VERSION 5.8 ;
BUSBITCHARS "[]" ;
DIVIDERCHAR "/" ;
UNITS
    DATABASE MICRONS 1000 ;
END UNITS

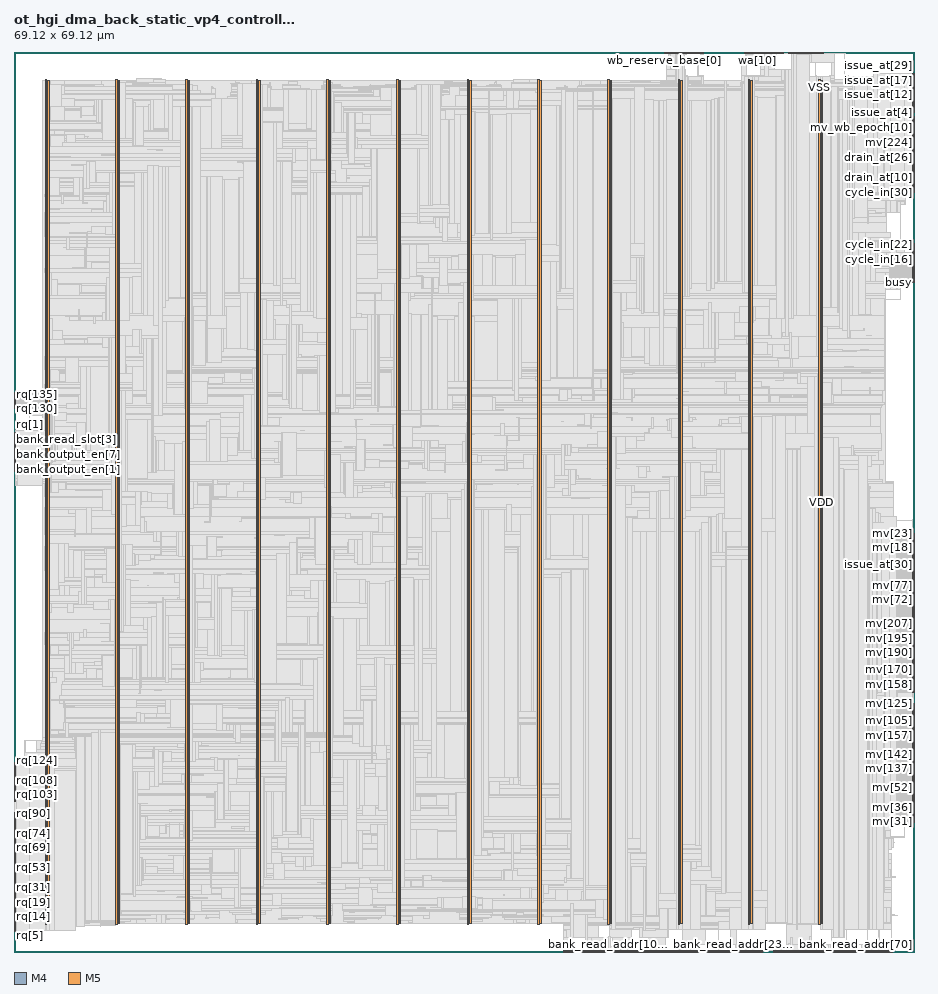
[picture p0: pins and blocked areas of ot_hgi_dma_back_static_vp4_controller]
MACRO ot_hgi_dma_back_static_vp4_controller
  FOREIGN ot_hgi_dma_back_static_vp4_controller 0 0 ;
  CLASS BLOCK ;
  SIZE 69.12 BY 69.12 ;
  PIN bank_output_en[0]
    DIRECTION OUTPUT ;
    USE SIGNAL ;
    PORT
      LAYER M4 ;
        RECT  0 36.912 0.084 36.936 ;
    END
  END bank_output_en[0]
  PIN bank_output_en[1]
    DIRECTION OUTPUT ;
    USE SIGNAL ;
    PORT
      LAYER M4 ;
        RECT  0 37.008 0.084 37.032 ;
    END
  END bank_output_en[1]
  PIN bank_output_en[2]
    DIRECTION OUTPUT ;
    USE SIGNAL ;
    PORT
      LAYER M4 ;
        RECT  0 37.104 0.084 37.128 ;
    END
  END bank_output_en[2]
  PIN bank_output_en[3]
    DIRECTION OUTPUT ;
    USE SIGNAL ;
    PORT
      LAYER M4 ;
        RECT  0 37.2 0.084 37.224 ;
    END
  END bank_output_en[3]
  PIN bank_output_en[4]
    DIRECTION OUTPUT ;
    USE SIGNAL ;
    PORT
      LAYER M4 ;
        RECT  0 37.296 0.084 37.32 ;
    END
  END bank_output_en[4]
  PIN bank_output_en[5]
    DIRECTION OUTPUT ;
    USE SIGNAL ;
    PORT
      LAYER M4 ;
        RECT  0 37.392 0.084 37.416 ;
    END
  END bank_output_en[5]
  PIN bank_output_en[6]
    DIRECTION OUTPUT ;
    USE SIGNAL ;
    PORT
      LAYER M4 ;
        RECT  0 37.488 0.084 37.512 ;
    END
  END bank_output_en[6]
  PIN bank_output_en[7]
    DIRECTION OUTPUT ;
    USE SIGNAL ;
    PORT
      LAYER M4 ;
        RECT  0 37.584 0.084 37.608 ;
    END
  END bank_output_en[7]
  PIN bank_read_addr[0]
    DIRECTION OUTPUT ;
    USE SIGNAL ;
    PORT
      LAYER M5 ;
        RECT  58.32 0 58.344 0.084 ;
    END
  END bank_read_addr[0]
  PIN bank_read_addr[100]
    DIRECTION OUTPUT ;
    USE SIGNAL ;
    PORT
      LAYER M5 ;
        RECT  45.648 0 45.672 0.084 ;
    END
  END bank_read_addr[100]
  PIN bank_read_addr[101]
    DIRECTION OUTPUT ;
    USE SIGNAL ;
    PORT
      LAYER M5 ;
        RECT  45.744 0 45.768 0.084 ;
    END
  END bank_read_addr[101]
  PIN bank_read_addr[102]
    DIRECTION OUTPUT ;
    USE SIGNAL ;
    PORT
      LAYER M5 ;
        RECT  45.84 0 45.864 0.084 ;
    END
  END bank_read_addr[102]
  PIN bank_read_addr[103]
    DIRECTION OUTPUT ;
    USE SIGNAL ;
    PORT
      LAYER M5 ;
        RECT  45.936 0 45.96 0.084 ;
    END
  END bank_read_addr[103]
  PIN bank_read_addr[104]
    DIRECTION OUTPUT ;
    USE SIGNAL ;
    PORT
      LAYER M5 ;
        RECT  46.032 0 46.056 0.084 ;
    END
  END bank_read_addr[104]
  PIN bank_read_addr[105]
    DIRECTION OUTPUT ;
    USE SIGNAL ;
    PORT
      LAYER M5 ;
        RECT  46.128 0 46.152 0.084 ;
    END
  END bank_read_addr[105]
  PIN bank_read_addr[106]
    DIRECTION OUTPUT ;
    USE SIGNAL ;
    PORT
      LAYER M5 ;
        RECT  46.224 0 46.248 0.084 ;
    END
  END bank_read_addr[106]
  PIN bank_read_addr[107]
    DIRECTION OUTPUT ;
    USE SIGNAL ;
    PORT
      LAYER M5 ;
        RECT  46.32 0 46.344 0.084 ;
    END
  END bank_read_addr[107]
  PIN bank_read_addr[108]
    DIRECTION OUTPUT ;
    USE SIGNAL ;
    PORT
      LAYER M5 ;
        RECT  46.416 0 46.44 0.084 ;
    END
  END bank_read_addr[108]
  PIN bank_read_addr[109]
    DIRECTION OUTPUT ;
    USE SIGNAL ;
    PORT
      LAYER M5 ;
        RECT  46.512 0 46.536 0.084 ;
    END
  END bank_read_addr[109]
  PIN bank_read_addr[10]
    DIRECTION OUTPUT ;
    USE SIGNAL ;
    PORT
      LAYER M5 ;
        RECT  59.28 0 59.304 0.084 ;
    END
  END bank_read_addr[10]
  PIN bank_read_addr[110]
    DIRECTION OUTPUT ;
    USE SIGNAL ;
    PORT
      LAYER M5 ;
        RECT  46.608 0 46.632 0.084 ;
    END
  END bank_read_addr[110]
  PIN bank_read_addr[111]
    DIRECTION OUTPUT ;
    USE SIGNAL ;
    PORT
      LAYER M5 ;
        RECT  46.704 0 46.728 0.084 ;
    END
  END bank_read_addr[111]
  PIN bank_read_addr[112]
    DIRECTION OUTPUT ;
    USE SIGNAL ;
    PORT
      LAYER M5 ;
        RECT  46.8 0 46.824 0.084 ;
    END
  END bank_read_addr[112]
  PIN bank_read_addr[113]
    DIRECTION OUTPUT ;
    USE SIGNAL ;
    PORT
      LAYER M5 ;
        RECT  46.896 0 46.92 0.084 ;
    END
  END bank_read_addr[113]
  PIN bank_read_addr[114]
    DIRECTION OUTPUT ;
    USE SIGNAL ;
    PORT
      LAYER M5 ;
        RECT  46.992 0 47.016 0.084 ;
    END
  END bank_read_addr[114]
  PIN bank_read_addr[115]
    DIRECTION OUTPUT ;
    USE SIGNAL ;
    PORT
      LAYER M5 ;
        RECT  47.088 0 47.112 0.084 ;
    END
  END bank_read_addr[115]
  PIN bank_read_addr[116]
    DIRECTION OUTPUT ;
    USE SIGNAL ;
    PORT
      LAYER M5 ;
        RECT  47.184 0 47.208 0.084 ;
    END
  END bank_read_addr[116]
  PIN bank_read_addr[117]
    DIRECTION OUTPUT ;
    USE SIGNAL ;
    PORT
      LAYER M5 ;
        RECT  47.28 0 47.304 0.084 ;
    END
  END bank_read_addr[117]
  PIN bank_read_addr[118]
    DIRECTION OUTPUT ;
    USE SIGNAL ;
    PORT
      LAYER M5 ;
        RECT  47.376 0 47.4 0.084 ;
    END
  END bank_read_addr[118]
  PIN bank_read_addr[119]
    DIRECTION OUTPUT ;
    USE SIGNAL ;
    PORT
      LAYER M5 ;
        RECT  47.472 0 47.496 0.084 ;
    END
  END bank_read_addr[119]
  PIN bank_read_addr[11]
    DIRECTION OUTPUT ;
    USE SIGNAL ;
    PORT
      LAYER M5 ;
        RECT  59.376 0 59.4 0.084 ;
    END
  END bank_read_addr[11]
  PIN bank_read_addr[120]
    DIRECTION OUTPUT ;
    USE SIGNAL ;
    PORT
      LAYER M5 ;
        RECT  47.568 0 47.592 0.084 ;
    END
  END bank_read_addr[120]
  PIN bank_read_addr[121]
    DIRECTION OUTPUT ;
    USE SIGNAL ;
    PORT
      LAYER M5 ;
        RECT  47.664 0 47.688 0.084 ;
    END
  END bank_read_addr[121]
  PIN bank_read_addr[122]
    DIRECTION OUTPUT ;
    USE SIGNAL ;
    PORT
      LAYER M5 ;
        RECT  47.76 0 47.784 0.084 ;
    END
  END bank_read_addr[122]
  PIN bank_read_addr[123]
    DIRECTION OUTPUT ;
    USE SIGNAL ;
    PORT
      LAYER M5 ;
        RECT  47.856 0 47.88 0.084 ;
    END
  END bank_read_addr[123]
  PIN bank_read_addr[124]
    DIRECTION OUTPUT ;
    USE SIGNAL ;
    PORT
      LAYER M5 ;
        RECT  47.952 0 47.976 0.084 ;
    END
  END bank_read_addr[124]
  PIN bank_read_addr[125]
    DIRECTION OUTPUT ;
    USE SIGNAL ;
    PORT
      LAYER M5 ;
        RECT  48.048 0 48.072 0.084 ;
    END
  END bank_read_addr[125]
  PIN bank_read_addr[126]
    DIRECTION OUTPUT ;
    USE SIGNAL ;
    PORT
      LAYER M5 ;
        RECT  48.144 0 48.168 0.084 ;
    END
  END bank_read_addr[126]
  PIN bank_read_addr[127]
    DIRECTION OUTPUT ;
    USE SIGNAL ;
    PORT
      LAYER M5 ;
        RECT  48.24 0 48.264 0.084 ;
    END
  END bank_read_addr[127]
  PIN bank_read_addr[128]
    DIRECTION OUTPUT ;
    USE SIGNAL ;
    PORT
      LAYER M5 ;
        RECT  42.192 0 42.216 0.084 ;
    END
  END bank_read_addr[128]
  PIN bank_read_addr[129]
    DIRECTION OUTPUT ;
    USE SIGNAL ;
    PORT
      LAYER M5 ;
        RECT  42.288 0 42.312 0.084 ;
    END
  END bank_read_addr[129]
  PIN bank_read_addr[12]
    DIRECTION OUTPUT ;
    USE SIGNAL ;
    PORT
      LAYER M5 ;
        RECT  59.472 0 59.496 0.084 ;
    END
  END bank_read_addr[12]
  PIN bank_read_addr[130]
    DIRECTION OUTPUT ;
    USE SIGNAL ;
    PORT
      LAYER M5 ;
        RECT  42.384 0 42.408 0.084 ;
    END
  END bank_read_addr[130]
  PIN bank_read_addr[131]
    DIRECTION OUTPUT ;
    USE SIGNAL ;
    PORT
      LAYER M5 ;
        RECT  42.48 0 42.504 0.084 ;
    END
  END bank_read_addr[131]
  PIN bank_read_addr[132]
    DIRECTION OUTPUT ;
    USE SIGNAL ;
    PORT
      LAYER M5 ;
        RECT  42.576 0 42.6 0.084 ;
    END
  END bank_read_addr[132]
  PIN bank_read_addr[133]
    DIRECTION OUTPUT ;
    USE SIGNAL ;
    PORT
      LAYER M5 ;
        RECT  42.672 0 42.696 0.084 ;
    END
  END bank_read_addr[133]
  PIN bank_read_addr[134]
    DIRECTION OUTPUT ;
    USE SIGNAL ;
    PORT
      LAYER M5 ;
        RECT  42.768 0 42.792 0.084 ;
    END
  END bank_read_addr[134]
  PIN bank_read_addr[135]
    DIRECTION OUTPUT ;
    USE SIGNAL ;
    PORT
      LAYER M5 ;
        RECT  42.864 0 42.888 0.084 ;
    END
  END bank_read_addr[135]
  PIN bank_read_addr[136]
    DIRECTION OUTPUT ;
    USE SIGNAL ;
    PORT
      LAYER M5 ;
        RECT  42.96 0 42.984 0.084 ;
    END
  END bank_read_addr[136]
  PIN bank_read_addr[137]
    DIRECTION OUTPUT ;
    USE SIGNAL ;
    PORT
      LAYER M5 ;
        RECT  43.056 0 43.08 0.084 ;
    END
  END bank_read_addr[137]
  PIN bank_read_addr[138]
    DIRECTION OUTPUT ;
    USE SIGNAL ;
    PORT
      LAYER M5 ;
        RECT  43.152 0 43.176 0.084 ;
    END
  END bank_read_addr[138]
  PIN bank_read_addr[139]
    DIRECTION OUTPUT ;
    USE SIGNAL ;
    PORT
      LAYER M5 ;
        RECT  43.248 0 43.272 0.084 ;
    END
  END bank_read_addr[139]
  PIN bank_read_addr[13]
    DIRECTION OUTPUT ;
    USE SIGNAL ;
    PORT
      LAYER M5 ;
        RECT  59.568 0 59.592 0.084 ;
    END
  END bank_read_addr[13]
  PIN bank_read_addr[140]
    DIRECTION OUTPUT ;
    USE SIGNAL ;
    PORT
      LAYER M5 ;
        RECT  43.344 0 43.368 0.084 ;
    END
  END bank_read_addr[140]
  PIN bank_read_addr[141]
    DIRECTION OUTPUT ;
    USE SIGNAL ;
    PORT
      LAYER M5 ;
        RECT  43.44 0 43.464 0.084 ;
    END
  END bank_read_addr[141]
  PIN bank_read_addr[142]
    DIRECTION OUTPUT ;
    USE SIGNAL ;
    PORT
      LAYER M5 ;
        RECT  43.536 0 43.56 0.084 ;
    END
  END bank_read_addr[142]
  PIN bank_read_addr[143]
    DIRECTION OUTPUT ;
    USE SIGNAL ;
    PORT
      LAYER M5 ;
        RECT  43.632 0 43.656 0.084 ;
    END
  END bank_read_addr[143]
  PIN bank_read_addr[144]
    DIRECTION OUTPUT ;
    USE SIGNAL ;
    PORT
      LAYER M5 ;
        RECT  43.728 0 43.752 0.084 ;
    END
  END bank_read_addr[144]
  PIN bank_read_addr[145]
    DIRECTION OUTPUT ;
    USE SIGNAL ;
    PORT
      LAYER M5 ;
        RECT  43.824 0 43.848 0.084 ;
    END
  END bank_read_addr[145]
  PIN bank_read_addr[146]
    DIRECTION OUTPUT ;
    USE SIGNAL ;
    PORT
      LAYER M5 ;
        RECT  43.92 0 43.944 0.084 ;
    END
  END bank_read_addr[146]
  PIN bank_read_addr[147]
    DIRECTION OUTPUT ;
    USE SIGNAL ;
    PORT
      LAYER M5 ;
        RECT  44.016 0 44.04 0.084 ;
    END
  END bank_read_addr[147]
  PIN bank_read_addr[148]
    DIRECTION OUTPUT ;
    USE SIGNAL ;
    PORT
      LAYER M5 ;
        RECT  44.112 0 44.136 0.084 ;
    END
  END bank_read_addr[148]
  PIN bank_read_addr[149]
    DIRECTION OUTPUT ;
    USE SIGNAL ;
    PORT
      LAYER M5 ;
        RECT  44.208 0 44.232 0.084 ;
    END
  END bank_read_addr[149]
  PIN bank_read_addr[14]
    DIRECTION OUTPUT ;
    USE SIGNAL ;
    PORT
      LAYER M5 ;
        RECT  59.664 0 59.688 0.084 ;
    END
  END bank_read_addr[14]
  PIN bank_read_addr[150]
    DIRECTION OUTPUT ;
    USE SIGNAL ;
    PORT
      LAYER M5 ;
        RECT  44.304 0 44.328 0.084 ;
    END
  END bank_read_addr[150]
  PIN bank_read_addr[151]
    DIRECTION OUTPUT ;
    USE SIGNAL ;
    PORT
      LAYER M5 ;
        RECT  44.4 0 44.424 0.084 ;
    END
  END bank_read_addr[151]
  PIN bank_read_addr[152]
    DIRECTION OUTPUT ;
    USE SIGNAL ;
    PORT
      LAYER M5 ;
        RECT  44.496 0 44.52 0.084 ;
    END
  END bank_read_addr[152]
  PIN bank_read_addr[153]
    DIRECTION OUTPUT ;
    USE SIGNAL ;
    PORT
      LAYER M5 ;
        RECT  44.592 0 44.616 0.084 ;
    END
  END bank_read_addr[153]
  PIN bank_read_addr[154]
    DIRECTION OUTPUT ;
    USE SIGNAL ;
    PORT
      LAYER M5 ;
        RECT  44.688 0 44.712 0.084 ;
    END
  END bank_read_addr[154]
  PIN bank_read_addr[155]
    DIRECTION OUTPUT ;
    USE SIGNAL ;
    PORT
      LAYER M5 ;
        RECT  44.784 0 44.808 0.084 ;
    END
  END bank_read_addr[155]
  PIN bank_read_addr[156]
    DIRECTION OUTPUT ;
    USE SIGNAL ;
    PORT
      LAYER M5 ;
        RECT  44.88 0 44.904 0.084 ;
    END
  END bank_read_addr[156]
  PIN bank_read_addr[157]
    DIRECTION OUTPUT ;
    USE SIGNAL ;
    PORT
      LAYER M5 ;
        RECT  44.976 0 45 0.084 ;
    END
  END bank_read_addr[157]
  PIN bank_read_addr[158]
    DIRECTION OUTPUT ;
    USE SIGNAL ;
    PORT
      LAYER M5 ;
        RECT  45.072 0 45.096 0.084 ;
    END
  END bank_read_addr[158]
  PIN bank_read_addr[159]
    DIRECTION OUTPUT ;
    USE SIGNAL ;
    PORT
      LAYER M5 ;
        RECT  45.168 0 45.192 0.084 ;
    END
  END bank_read_addr[159]
  PIN bank_read_addr[15]
    DIRECTION OUTPUT ;
    USE SIGNAL ;
    PORT
      LAYER M5 ;
        RECT  59.76 0 59.784 0.084 ;
    END
  END bank_read_addr[15]
  PIN bank_read_addr[160]
    DIRECTION OUTPUT ;
    USE SIGNAL ;
    PORT
      LAYER M5 ;
        RECT  51.408 0 51.432 0.084 ;
    END
  END bank_read_addr[160]
  PIN bank_read_addr[161]
    DIRECTION OUTPUT ;
    USE SIGNAL ;
    PORT
      LAYER M5 ;
        RECT  51.504 0 51.528 0.084 ;
    END
  END bank_read_addr[161]
  PIN bank_read_addr[162]
    DIRECTION OUTPUT ;
    USE SIGNAL ;
    PORT
      LAYER M5 ;
        RECT  51.6 0 51.624 0.084 ;
    END
  END bank_read_addr[162]
  PIN bank_read_addr[163]
    DIRECTION OUTPUT ;
    USE SIGNAL ;
    PORT
      LAYER M5 ;
        RECT  51.696 0 51.72 0.084 ;
    END
  END bank_read_addr[163]
  PIN bank_read_addr[164]
    DIRECTION OUTPUT ;
    USE SIGNAL ;
    PORT
      LAYER M5 ;
        RECT  51.792 0 51.816 0.084 ;
    END
  END bank_read_addr[164]
  PIN bank_read_addr[165]
    DIRECTION OUTPUT ;
    USE SIGNAL ;
    PORT
      LAYER M5 ;
        RECT  51.888 0 51.912 0.084 ;
    END
  END bank_read_addr[165]
  PIN bank_read_addr[166]
    DIRECTION OUTPUT ;
    USE SIGNAL ;
    PORT
      LAYER M5 ;
        RECT  51.984 0 52.008 0.084 ;
    END
  END bank_read_addr[166]
  PIN bank_read_addr[167]
    DIRECTION OUTPUT ;
    USE SIGNAL ;
    PORT
      LAYER M5 ;
        RECT  52.08 0 52.104 0.084 ;
    END
  END bank_read_addr[167]
  PIN bank_read_addr[168]
    DIRECTION OUTPUT ;
    USE SIGNAL ;
    PORT
      LAYER M5 ;
        RECT  52.176 0 52.2 0.084 ;
    END
  END bank_read_addr[168]
  PIN bank_read_addr[169]
    DIRECTION OUTPUT ;
    USE SIGNAL ;
    PORT
      LAYER M5 ;
        RECT  52.272 0 52.296 0.084 ;
    END
  END bank_read_addr[169]
  PIN bank_read_addr[16]
    DIRECTION OUTPUT ;
    USE SIGNAL ;
    PORT
      LAYER M5 ;
        RECT  59.856 0 59.88 0.084 ;
    END
  END bank_read_addr[16]
  PIN bank_read_addr[170]
    DIRECTION OUTPUT ;
    USE SIGNAL ;
    PORT
      LAYER M5 ;
        RECT  52.368 0 52.392 0.084 ;
    END
  END bank_read_addr[170]
  PIN bank_read_addr[171]
    DIRECTION OUTPUT ;
    USE SIGNAL ;
    PORT
      LAYER M5 ;
        RECT  52.464 0 52.488 0.084 ;
    END
  END bank_read_addr[171]
  PIN bank_read_addr[172]
    DIRECTION OUTPUT ;
    USE SIGNAL ;
    PORT
      LAYER M5 ;
        RECT  52.56 0 52.584 0.084 ;
    END
  END bank_read_addr[172]
  PIN bank_read_addr[173]
    DIRECTION OUTPUT ;
    USE SIGNAL ;
    PORT
      LAYER M5 ;
        RECT  52.656 0 52.68 0.084 ;
    END
  END bank_read_addr[173]
  PIN bank_read_addr[174]
    DIRECTION OUTPUT ;
    USE SIGNAL ;
    PORT
      LAYER M5 ;
        RECT  52.752 0 52.776 0.084 ;
    END
  END bank_read_addr[174]
  PIN bank_read_addr[175]
    DIRECTION OUTPUT ;
    USE SIGNAL ;
    PORT
      LAYER M5 ;
        RECT  52.848 0 52.872 0.084 ;
    END
  END bank_read_addr[175]
  PIN bank_read_addr[176]
    DIRECTION OUTPUT ;
    USE SIGNAL ;
    PORT
      LAYER M5 ;
        RECT  52.944 0 52.968 0.084 ;
    END
  END bank_read_addr[176]
  PIN bank_read_addr[177]
    DIRECTION OUTPUT ;
    USE SIGNAL ;
    PORT
      LAYER M5 ;
        RECT  53.04 0 53.064 0.084 ;
    END
  END bank_read_addr[177]
  PIN bank_read_addr[178]
    DIRECTION OUTPUT ;
    USE SIGNAL ;
    PORT
      LAYER M5 ;
        RECT  53.136 0 53.16 0.084 ;
    END
  END bank_read_addr[178]
  PIN bank_read_addr[179]
    DIRECTION OUTPUT ;
    USE SIGNAL ;
    PORT
      LAYER M5 ;
        RECT  53.232 0 53.256 0.084 ;
    END
  END bank_read_addr[179]
  PIN bank_read_addr[17]
    DIRECTION OUTPUT ;
    USE SIGNAL ;
    PORT
      LAYER M5 ;
        RECT  59.952 0 59.976 0.084 ;
    END
  END bank_read_addr[17]
  PIN bank_read_addr[180]
    DIRECTION OUTPUT ;
    USE SIGNAL ;
    PORT
      LAYER M5 ;
        RECT  53.328 0 53.352 0.084 ;
    END
  END bank_read_addr[180]
  PIN bank_read_addr[181]
    DIRECTION OUTPUT ;
    USE SIGNAL ;
    PORT
      LAYER M5 ;
        RECT  53.424 0 53.448 0.084 ;
    END
  END bank_read_addr[181]
  PIN bank_read_addr[182]
    DIRECTION OUTPUT ;
    USE SIGNAL ;
    PORT
      LAYER M5 ;
        RECT  53.52 0 53.544 0.084 ;
    END
  END bank_read_addr[182]
  PIN bank_read_addr[183]
    DIRECTION OUTPUT ;
    USE SIGNAL ;
    PORT
      LAYER M5 ;
        RECT  53.616 0 53.64 0.084 ;
    END
  END bank_read_addr[183]
  PIN bank_read_addr[184]
    DIRECTION OUTPUT ;
    USE SIGNAL ;
    PORT
      LAYER M5 ;
        RECT  53.712 0 53.736 0.084 ;
    END
  END bank_read_addr[184]
  PIN bank_read_addr[185]
    DIRECTION OUTPUT ;
    USE SIGNAL ;
    PORT
      LAYER M5 ;
        RECT  53.808 0 53.832 0.084 ;
    END
  END bank_read_addr[185]
  PIN bank_read_addr[186]
    DIRECTION OUTPUT ;
    USE SIGNAL ;
    PORT
      LAYER M5 ;
        RECT  53.904 0 53.928 0.084 ;
    END
  END bank_read_addr[186]
  PIN bank_read_addr[187]
    DIRECTION OUTPUT ;
    USE SIGNAL ;
    PORT
      LAYER M5 ;
        RECT  54 0 54.024 0.084 ;
    END
  END bank_read_addr[187]
  PIN bank_read_addr[188]
    DIRECTION OUTPUT ;
    USE SIGNAL ;
    PORT
      LAYER M5 ;
        RECT  54.096 0 54.12 0.084 ;
    END
  END bank_read_addr[188]
  PIN bank_read_addr[189]
    DIRECTION OUTPUT ;
    USE SIGNAL ;
    PORT
      LAYER M5 ;
        RECT  54.192 0 54.216 0.084 ;
    END
  END bank_read_addr[189]
  PIN bank_read_addr[18]
    DIRECTION OUTPUT ;
    USE SIGNAL ;
    PORT
      LAYER M5 ;
        RECT  60.048 0 60.072 0.084 ;
    END
  END bank_read_addr[18]
  PIN bank_read_addr[190]
    DIRECTION OUTPUT ;
    USE SIGNAL ;
    PORT
      LAYER M5 ;
        RECT  54.288 0 54.312 0.084 ;
    END
  END bank_read_addr[190]
  PIN bank_read_addr[191]
    DIRECTION OUTPUT ;
    USE SIGNAL ;
    PORT
      LAYER M5 ;
        RECT  54.384 0 54.408 0.084 ;
    END
  END bank_read_addr[191]
  PIN bank_read_addr[192]
    DIRECTION OUTPUT ;
    USE SIGNAL ;
    PORT
      LAYER M5 ;
        RECT  48.336 0 48.36 0.084 ;
    END
  END bank_read_addr[192]
  PIN bank_read_addr[193]
    DIRECTION OUTPUT ;
    USE SIGNAL ;
    PORT
      LAYER M5 ;
        RECT  48.432 0 48.456 0.084 ;
    END
  END bank_read_addr[193]
  PIN bank_read_addr[194]
    DIRECTION OUTPUT ;
    USE SIGNAL ;
    PORT
      LAYER M5 ;
        RECT  48.528 0 48.552 0.084 ;
    END
  END bank_read_addr[194]
  PIN bank_read_addr[195]
    DIRECTION OUTPUT ;
    USE SIGNAL ;
    PORT
      LAYER M5 ;
        RECT  48.624 0 48.648 0.084 ;
    END
  END bank_read_addr[195]
  PIN bank_read_addr[196]
    DIRECTION OUTPUT ;
    USE SIGNAL ;
    PORT
      LAYER M5 ;
        RECT  48.72 0 48.744 0.084 ;
    END
  END bank_read_addr[196]
  PIN bank_read_addr[197]
    DIRECTION OUTPUT ;
    USE SIGNAL ;
    PORT
      LAYER M5 ;
        RECT  48.816 0 48.84 0.084 ;
    END
  END bank_read_addr[197]
  PIN bank_read_addr[198]
    DIRECTION OUTPUT ;
    USE SIGNAL ;
    PORT
      LAYER M5 ;
        RECT  48.912 0 48.936 0.084 ;
    END
  END bank_read_addr[198]
  PIN bank_read_addr[199]
    DIRECTION OUTPUT ;
    USE SIGNAL ;
    PORT
      LAYER M5 ;
        RECT  49.008 0 49.032 0.084 ;
    END
  END bank_read_addr[199]
  PIN bank_read_addr[19]
    DIRECTION OUTPUT ;
    USE SIGNAL ;
    PORT
      LAYER M5 ;
        RECT  60.144 0 60.168 0.084 ;
    END
  END bank_read_addr[19]
  PIN bank_read_addr[1]
    DIRECTION OUTPUT ;
    USE SIGNAL ;
    PORT
      LAYER M5 ;
        RECT  58.416 0 58.44 0.084 ;
    END
  END bank_read_addr[1]
  PIN bank_read_addr[200]
    DIRECTION OUTPUT ;
    USE SIGNAL ;
    PORT
      LAYER M5 ;
        RECT  49.104 0 49.128 0.084 ;
    END
  END bank_read_addr[200]
  PIN bank_read_addr[201]
    DIRECTION OUTPUT ;
    USE SIGNAL ;
    PORT
      LAYER M5 ;
        RECT  49.2 0 49.224 0.084 ;
    END
  END bank_read_addr[201]
  PIN bank_read_addr[202]
    DIRECTION OUTPUT ;
    USE SIGNAL ;
    PORT
      LAYER M5 ;
        RECT  49.296 0 49.32 0.084 ;
    END
  END bank_read_addr[202]
  PIN bank_read_addr[203]
    DIRECTION OUTPUT ;
    USE SIGNAL ;
    PORT
      LAYER M5 ;
        RECT  49.392 0 49.416 0.084 ;
    END
  END bank_read_addr[203]
  PIN bank_read_addr[204]
    DIRECTION OUTPUT ;
    USE SIGNAL ;
    PORT
      LAYER M5 ;
        RECT  49.488 0 49.512 0.084 ;
    END
  END bank_read_addr[204]
  PIN bank_read_addr[205]
    DIRECTION OUTPUT ;
    USE SIGNAL ;
    PORT
      LAYER M5 ;
        RECT  49.584 0 49.608 0.084 ;
    END
  END bank_read_addr[205]
  PIN bank_read_addr[206]
    DIRECTION OUTPUT ;
    USE SIGNAL ;
    PORT
      LAYER M5 ;
        RECT  49.68 0 49.704 0.084 ;
    END
  END bank_read_addr[206]
  PIN bank_read_addr[207]
    DIRECTION OUTPUT ;
    USE SIGNAL ;
    PORT
      LAYER M5 ;
        RECT  49.776 0 49.8 0.084 ;
    END
  END bank_read_addr[207]
  PIN bank_read_addr[208]
    DIRECTION OUTPUT ;
    USE SIGNAL ;
    PORT
      LAYER M5 ;
        RECT  49.872 0 49.896 0.084 ;
    END
  END bank_read_addr[208]
  PIN bank_read_addr[209]
    DIRECTION OUTPUT ;
    USE SIGNAL ;
    PORT
      LAYER M5 ;
        RECT  49.968 0 49.992 0.084 ;
    END
  END bank_read_addr[209]
  PIN bank_read_addr[20]
    DIRECTION OUTPUT ;
    USE SIGNAL ;
    PORT
      LAYER M5 ;
        RECT  60.24 0 60.264 0.084 ;
    END
  END bank_read_addr[20]
  PIN bank_read_addr[210]
    DIRECTION OUTPUT ;
    USE SIGNAL ;
    PORT
      LAYER M5 ;
        RECT  50.064 0 50.088 0.084 ;
    END
  END bank_read_addr[210]
  PIN bank_read_addr[211]
    DIRECTION OUTPUT ;
    USE SIGNAL ;
    PORT
      LAYER M5 ;
        RECT  50.16 0 50.184 0.084 ;
    END
  END bank_read_addr[211]
  PIN bank_read_addr[212]
    DIRECTION OUTPUT ;
    USE SIGNAL ;
    PORT
      LAYER M5 ;
        RECT  50.256 0 50.28 0.084 ;
    END
  END bank_read_addr[212]
  PIN bank_read_addr[213]
    DIRECTION OUTPUT ;
    USE SIGNAL ;
    PORT
      LAYER M5 ;
        RECT  50.352 0 50.376 0.084 ;
    END
  END bank_read_addr[213]
  PIN bank_read_addr[214]
    DIRECTION OUTPUT ;
    USE SIGNAL ;
    PORT
      LAYER M5 ;
        RECT  50.448 0 50.472 0.084 ;
    END
  END bank_read_addr[214]
  PIN bank_read_addr[215]
    DIRECTION OUTPUT ;
    USE SIGNAL ;
    PORT
      LAYER M5 ;
        RECT  50.544 0 50.568 0.084 ;
    END
  END bank_read_addr[215]
  PIN bank_read_addr[216]
    DIRECTION OUTPUT ;
    USE SIGNAL ;
    PORT
      LAYER M5 ;
        RECT  50.64 0 50.664 0.084 ;
    END
  END bank_read_addr[216]
  PIN bank_read_addr[217]
    DIRECTION OUTPUT ;
    USE SIGNAL ;
    PORT
      LAYER M5 ;
        RECT  50.736 0 50.76 0.084 ;
    END
  END bank_read_addr[217]
  PIN bank_read_addr[218]
    DIRECTION OUTPUT ;
    USE SIGNAL ;
    PORT
      LAYER M5 ;
        RECT  50.832 0 50.856 0.084 ;
    END
  END bank_read_addr[218]
  PIN bank_read_addr[219]
    DIRECTION OUTPUT ;
    USE SIGNAL ;
    PORT
      LAYER M5 ;
        RECT  50.928 0 50.952 0.084 ;
    END
  END bank_read_addr[219]
  PIN bank_read_addr[21]
    DIRECTION OUTPUT ;
    USE SIGNAL ;
    PORT
      LAYER M5 ;
        RECT  60.336 0 60.36 0.084 ;
    END
  END bank_read_addr[21]
  PIN bank_read_addr[220]
    DIRECTION OUTPUT ;
    USE SIGNAL ;
    PORT
      LAYER M5 ;
        RECT  51.024 0 51.048 0.084 ;
    END
  END bank_read_addr[220]
  PIN bank_read_addr[221]
    DIRECTION OUTPUT ;
    USE SIGNAL ;
    PORT
      LAYER M5 ;
        RECT  51.12 0 51.144 0.084 ;
    END
  END bank_read_addr[221]
  PIN bank_read_addr[222]
    DIRECTION OUTPUT ;
    USE SIGNAL ;
    PORT
      LAYER M5 ;
        RECT  51.216 0 51.24 0.084 ;
    END
  END bank_read_addr[222]
  PIN bank_read_addr[223]
    DIRECTION OUTPUT ;
    USE SIGNAL ;
    PORT
      LAYER M5 ;
        RECT  51.312 0 51.336 0.084 ;
    END
  END bank_read_addr[223]
  PIN bank_read_addr[224]
    DIRECTION OUTPUT ;
    USE SIGNAL ;
    PORT
      LAYER M5 ;
        RECT  54.48 0 54.504 0.084 ;
    END
  END bank_read_addr[224]
  PIN bank_read_addr[225]
    DIRECTION OUTPUT ;
    USE SIGNAL ;
    PORT
      LAYER M5 ;
        RECT  54.576 0 54.6 0.084 ;
    END
  END bank_read_addr[225]
  PIN bank_read_addr[226]
    DIRECTION OUTPUT ;
    USE SIGNAL ;
    PORT
      LAYER M5 ;
        RECT  54.672 0 54.696 0.084 ;
    END
  END bank_read_addr[226]
  PIN bank_read_addr[227]
    DIRECTION OUTPUT ;
    USE SIGNAL ;
    PORT
      LAYER M5 ;
        RECT  54.768 0 54.792 0.084 ;
    END
  END bank_read_addr[227]
  PIN bank_read_addr[228]
    DIRECTION OUTPUT ;
    USE SIGNAL ;
    PORT
      LAYER M5 ;
        RECT  54.864 0 54.888 0.084 ;
    END
  END bank_read_addr[228]
  PIN bank_read_addr[229]
    DIRECTION OUTPUT ;
    USE SIGNAL ;
    PORT
      LAYER M5 ;
        RECT  54.96 0 54.984 0.084 ;
    END
  END bank_read_addr[229]
  PIN bank_read_addr[22]
    DIRECTION OUTPUT ;
    USE SIGNAL ;
    PORT
      LAYER M5 ;
        RECT  60.432 0 60.456 0.084 ;
    END
  END bank_read_addr[22]
  PIN bank_read_addr[230]
    DIRECTION OUTPUT ;
    USE SIGNAL ;
    PORT
      LAYER M5 ;
        RECT  55.056 0 55.08 0.084 ;
    END
  END bank_read_addr[230]
  PIN bank_read_addr[231]
    DIRECTION OUTPUT ;
    USE SIGNAL ;
    PORT
      LAYER M5 ;
        RECT  55.152 0 55.176 0.084 ;
    END
  END bank_read_addr[231]
  PIN bank_read_addr[232]
    DIRECTION OUTPUT ;
    USE SIGNAL ;
    PORT
      LAYER M5 ;
        RECT  55.248 0 55.272 0.084 ;
    END
  END bank_read_addr[232]
  PIN bank_read_addr[233]
    DIRECTION OUTPUT ;
    USE SIGNAL ;
    PORT
      LAYER M5 ;
        RECT  55.344 0 55.368 0.084 ;
    END
  END bank_read_addr[233]
  PIN bank_read_addr[234]
    DIRECTION OUTPUT ;
    USE SIGNAL ;
    PORT
      LAYER M5 ;
        RECT  55.44 0 55.464 0.084 ;
    END
  END bank_read_addr[234]
  PIN bank_read_addr[235]
    DIRECTION OUTPUT ;
    USE SIGNAL ;
    PORT
      LAYER M5 ;
        RECT  55.536 0 55.56 0.084 ;
    END
  END bank_read_addr[235]
  PIN bank_read_addr[236]
    DIRECTION OUTPUT ;
    USE SIGNAL ;
    PORT
      LAYER M5 ;
        RECT  55.632 0 55.656 0.084 ;
    END
  END bank_read_addr[236]
  PIN bank_read_addr[237]
    DIRECTION OUTPUT ;
    USE SIGNAL ;
    PORT
      LAYER M5 ;
        RECT  55.728 0 55.752 0.084 ;
    END
  END bank_read_addr[237]
  PIN bank_read_addr[238]
    DIRECTION OUTPUT ;
    USE SIGNAL ;
    PORT
      LAYER M5 ;
        RECT  55.824 0 55.848 0.084 ;
    END
  END bank_read_addr[238]
  PIN bank_read_addr[239]
    DIRECTION OUTPUT ;
    USE SIGNAL ;
    PORT
      LAYER M5 ;
        RECT  55.92 0 55.944 0.084 ;
    END
  END bank_read_addr[239]
  PIN bank_read_addr[23]
    DIRECTION OUTPUT ;
    USE SIGNAL ;
    PORT
      LAYER M5 ;
        RECT  60.528 0 60.552 0.084 ;
    END
  END bank_read_addr[23]
  PIN bank_read_addr[240]
    DIRECTION OUTPUT ;
    USE SIGNAL ;
    PORT
      LAYER M5 ;
        RECT  56.016 0 56.04 0.084 ;
    END
  END bank_read_addr[240]
  PIN bank_read_addr[241]
    DIRECTION OUTPUT ;
    USE SIGNAL ;
    PORT
      LAYER M5 ;
        RECT  56.112 0 56.136 0.084 ;
    END
  END bank_read_addr[241]
  PIN bank_read_addr[242]
    DIRECTION OUTPUT ;
    USE SIGNAL ;
    PORT
      LAYER M5 ;
        RECT  56.208 0 56.232 0.084 ;
    END
  END bank_read_addr[242]
  PIN bank_read_addr[243]
    DIRECTION OUTPUT ;
    USE SIGNAL ;
    PORT
      LAYER M5 ;
        RECT  56.304 0 56.328 0.084 ;
    END
  END bank_read_addr[243]
  PIN bank_read_addr[244]
    DIRECTION OUTPUT ;
    USE SIGNAL ;
    PORT
      LAYER M5 ;
        RECT  56.4 0 56.424 0.084 ;
    END
  END bank_read_addr[244]
  PIN bank_read_addr[245]
    DIRECTION OUTPUT ;
    USE SIGNAL ;
    PORT
      LAYER M5 ;
        RECT  56.496 0 56.52 0.084 ;
    END
  END bank_read_addr[245]
  PIN bank_read_addr[246]
    DIRECTION OUTPUT ;
    USE SIGNAL ;
    PORT
      LAYER M5 ;
        RECT  56.592 0 56.616 0.084 ;
    END
  END bank_read_addr[246]
  PIN bank_read_addr[247]
    DIRECTION OUTPUT ;
    USE SIGNAL ;
    PORT
      LAYER M5 ;
        RECT  56.688 0 56.712 0.084 ;
    END
  END bank_read_addr[247]
  PIN bank_read_addr[248]
    DIRECTION OUTPUT ;
    USE SIGNAL ;
    PORT
      LAYER M5 ;
        RECT  56.784 0 56.808 0.084 ;
    END
  END bank_read_addr[248]
  PIN bank_read_addr[249]
    DIRECTION OUTPUT ;
    USE SIGNAL ;
    PORT
      LAYER M5 ;
        RECT  56.88 0 56.904 0.084 ;
    END
  END bank_read_addr[249]
  PIN bank_read_addr[24]
    DIRECTION OUTPUT ;
    USE SIGNAL ;
    PORT
      LAYER M5 ;
        RECT  60.624 0 60.648 0.084 ;
    END
  END bank_read_addr[24]
  PIN bank_read_addr[250]
    DIRECTION OUTPUT ;
    USE SIGNAL ;
    PORT
      LAYER M5 ;
        RECT  56.976 0 57 0.084 ;
    END
  END bank_read_addr[250]
  PIN bank_read_addr[251]
    DIRECTION OUTPUT ;
    USE SIGNAL ;
    PORT
      LAYER M5 ;
        RECT  57.072 0 57.096 0.084 ;
    END
  END bank_read_addr[251]
  PIN bank_read_addr[252]
    DIRECTION OUTPUT ;
    USE SIGNAL ;
    PORT
      LAYER M5 ;
        RECT  57.168 0 57.192 0.084 ;
    END
  END bank_read_addr[252]
  PIN bank_read_addr[253]
    DIRECTION OUTPUT ;
    USE SIGNAL ;
    PORT
      LAYER M5 ;
        RECT  57.264 0 57.288 0.084 ;
    END
  END bank_read_addr[253]
  PIN bank_read_addr[254]
    DIRECTION OUTPUT ;
    USE SIGNAL ;
    PORT
      LAYER M5 ;
        RECT  57.36 0 57.384 0.084 ;
    END
  END bank_read_addr[254]
  PIN bank_read_addr[255]
    DIRECTION OUTPUT ;
    USE SIGNAL ;
    PORT
      LAYER M5 ;
        RECT  57.456 0 57.48 0.084 ;
    END
  END bank_read_addr[255]
  PIN bank_read_addr[25]
    DIRECTION OUTPUT ;
    USE SIGNAL ;
    PORT
      LAYER M5 ;
        RECT  60.72 0 60.744 0.084 ;
    END
  END bank_read_addr[25]
  PIN bank_read_addr[26]
    DIRECTION OUTPUT ;
    USE SIGNAL ;
    PORT
      LAYER M5 ;
        RECT  60.816 0 60.84 0.084 ;
    END
  END bank_read_addr[26]
  PIN bank_read_addr[27]
    DIRECTION OUTPUT ;
    USE SIGNAL ;
    PORT
      LAYER M5 ;
        RECT  60.912 0 60.936 0.084 ;
    END
  END bank_read_addr[27]
  PIN bank_read_addr[28]
    DIRECTION OUTPUT ;
    USE SIGNAL ;
    PORT
      LAYER M5 ;
        RECT  61.008 0 61.032 0.084 ;
    END
  END bank_read_addr[28]
  PIN bank_read_addr[29]
    DIRECTION OUTPUT ;
    USE SIGNAL ;
    PORT
      LAYER M5 ;
        RECT  61.104 0 61.128 0.084 ;
    END
  END bank_read_addr[29]
  PIN bank_read_addr[2]
    DIRECTION OUTPUT ;
    USE SIGNAL ;
    PORT
      LAYER M5 ;
        RECT  58.512 0 58.536 0.084 ;
    END
  END bank_read_addr[2]
  PIN bank_read_addr[30]
    DIRECTION OUTPUT ;
    USE SIGNAL ;
    PORT
      LAYER M5 ;
        RECT  61.2 0 61.224 0.084 ;
    END
  END bank_read_addr[30]
  PIN bank_read_addr[31]
    DIRECTION OUTPUT ;
    USE SIGNAL ;
    PORT
      LAYER M5 ;
        RECT  61.296 0 61.32 0.084 ;
    END
  END bank_read_addr[31]
  PIN bank_read_addr[32]
    DIRECTION OUTPUT ;
    USE SIGNAL ;
    PORT
      LAYER M5 ;
        RECT  61.392 0 61.416 0.084 ;
    END
  END bank_read_addr[32]
  PIN bank_read_addr[33]
    DIRECTION OUTPUT ;
    USE SIGNAL ;
    PORT
      LAYER M5 ;
        RECT  61.488 0 61.512 0.084 ;
    END
  END bank_read_addr[33]
  PIN bank_read_addr[34]
    DIRECTION OUTPUT ;
    USE SIGNAL ;
    PORT
      LAYER M5 ;
        RECT  61.584 0 61.608 0.084 ;
    END
  END bank_read_addr[34]
  PIN bank_read_addr[35]
    DIRECTION OUTPUT ;
    USE SIGNAL ;
    PORT
      LAYER M5 ;
        RECT  61.68 0 61.704 0.084 ;
    END
  END bank_read_addr[35]
  PIN bank_read_addr[36]
    DIRECTION OUTPUT ;
    USE SIGNAL ;
    PORT
      LAYER M5 ;
        RECT  61.776 0 61.8 0.084 ;
    END
  END bank_read_addr[36]
  PIN bank_read_addr[37]
    DIRECTION OUTPUT ;
    USE SIGNAL ;
    PORT
      LAYER M5 ;
        RECT  61.872 0 61.896 0.084 ;
    END
  END bank_read_addr[37]
  PIN bank_read_addr[38]
    DIRECTION OUTPUT ;
    USE SIGNAL ;
    PORT
      LAYER M5 ;
        RECT  61.968 0 61.992 0.084 ;
    END
  END bank_read_addr[38]
  PIN bank_read_addr[39]
    DIRECTION OUTPUT ;
    USE SIGNAL ;
    PORT
      LAYER M5 ;
        RECT  62.064 0 62.088 0.084 ;
    END
  END bank_read_addr[39]
  PIN bank_read_addr[3]
    DIRECTION OUTPUT ;
    USE SIGNAL ;
    PORT
      LAYER M5 ;
        RECT  58.608 0 58.632 0.084 ;
    END
  END bank_read_addr[3]
  PIN bank_read_addr[40]
    DIRECTION OUTPUT ;
    USE SIGNAL ;
    PORT
      LAYER M5 ;
        RECT  62.16 0 62.184 0.084 ;
    END
  END bank_read_addr[40]
  PIN bank_read_addr[41]
    DIRECTION OUTPUT ;
    USE SIGNAL ;
    PORT
      LAYER M5 ;
        RECT  62.256 0 62.28 0.084 ;
    END
  END bank_read_addr[41]
  PIN bank_read_addr[42]
    DIRECTION OUTPUT ;
    USE SIGNAL ;
    PORT
      LAYER M5 ;
        RECT  62.352 0 62.376 0.084 ;
    END
  END bank_read_addr[42]
  PIN bank_read_addr[43]
    DIRECTION OUTPUT ;
    USE SIGNAL ;
    PORT
      LAYER M5 ;
        RECT  62.448 0 62.472 0.084 ;
    END
  END bank_read_addr[43]
  PIN bank_read_addr[44]
    DIRECTION OUTPUT ;
    USE SIGNAL ;
    PORT
      LAYER M5 ;
        RECT  62.544 0 62.568 0.084 ;
    END
  END bank_read_addr[44]
  PIN bank_read_addr[45]
    DIRECTION OUTPUT ;
    USE SIGNAL ;
    PORT
      LAYER M5 ;
        RECT  62.64 0 62.664 0.084 ;
    END
  END bank_read_addr[45]
  PIN bank_read_addr[46]
    DIRECTION OUTPUT ;
    USE SIGNAL ;
    PORT
      LAYER M5 ;
        RECT  62.736 0 62.76 0.084 ;
    END
  END bank_read_addr[46]
  PIN bank_read_addr[47]
    DIRECTION OUTPUT ;
    USE SIGNAL ;
    PORT
      LAYER M5 ;
        RECT  62.832 0 62.856 0.084 ;
    END
  END bank_read_addr[47]
  PIN bank_read_addr[48]
    DIRECTION OUTPUT ;
    USE SIGNAL ;
    PORT
      LAYER M5 ;
        RECT  62.928 0 62.952 0.084 ;
    END
  END bank_read_addr[48]
  PIN bank_read_addr[49]
    DIRECTION OUTPUT ;
    USE SIGNAL ;
    PORT
      LAYER M5 ;
        RECT  63.024 0 63.048 0.084 ;
    END
  END bank_read_addr[49]
  PIN bank_read_addr[4]
    DIRECTION OUTPUT ;
    USE SIGNAL ;
    PORT
      LAYER M5 ;
        RECT  58.704 0 58.728 0.084 ;
    END
  END bank_read_addr[4]
  PIN bank_read_addr[50]
    DIRECTION OUTPUT ;
    USE SIGNAL ;
    PORT
      LAYER M5 ;
        RECT  63.12 0 63.144 0.084 ;
    END
  END bank_read_addr[50]
  PIN bank_read_addr[51]
    DIRECTION OUTPUT ;
    USE SIGNAL ;
    PORT
      LAYER M5 ;
        RECT  63.216 0 63.24 0.084 ;
    END
  END bank_read_addr[51]
  PIN bank_read_addr[52]
    DIRECTION OUTPUT ;
    USE SIGNAL ;
    PORT
      LAYER M5 ;
        RECT  63.312 0 63.336 0.084 ;
    END
  END bank_read_addr[52]
  PIN bank_read_addr[53]
    DIRECTION OUTPUT ;
    USE SIGNAL ;
    PORT
      LAYER M5 ;
        RECT  63.408 0 63.432 0.084 ;
    END
  END bank_read_addr[53]
  PIN bank_read_addr[54]
    DIRECTION OUTPUT ;
    USE SIGNAL ;
    PORT
      LAYER M5 ;
        RECT  63.504 0 63.528 0.084 ;
    END
  END bank_read_addr[54]
  PIN bank_read_addr[55]
    DIRECTION OUTPUT ;
    USE SIGNAL ;
    PORT
      LAYER M5 ;
        RECT  63.6 0 63.624 0.084 ;
    END
  END bank_read_addr[55]
  PIN bank_read_addr[56]
    DIRECTION OUTPUT ;
    USE SIGNAL ;
    PORT
      LAYER M5 ;
        RECT  63.696 0 63.72 0.084 ;
    END
  END bank_read_addr[56]
  PIN bank_read_addr[57]
    DIRECTION OUTPUT ;
    USE SIGNAL ;
    PORT
      LAYER M5 ;
        RECT  63.792 0 63.816 0.084 ;
    END
  END bank_read_addr[57]
  PIN bank_read_addr[58]
    DIRECTION OUTPUT ;
    USE SIGNAL ;
    PORT
      LAYER M5 ;
        RECT  63.888 0 63.912 0.084 ;
    END
  END bank_read_addr[58]
  PIN bank_read_addr[59]
    DIRECTION OUTPUT ;
    USE SIGNAL ;
    PORT
      LAYER M5 ;
        RECT  63.984 0 64.008 0.084 ;
    END
  END bank_read_addr[59]
  PIN bank_read_addr[5]
    DIRECTION OUTPUT ;
    USE SIGNAL ;
    PORT
      LAYER M5 ;
        RECT  58.8 0 58.824 0.084 ;
    END
  END bank_read_addr[5]
  PIN bank_read_addr[60]
    DIRECTION OUTPUT ;
    USE SIGNAL ;
    PORT
      LAYER M5 ;
        RECT  64.08 0 64.104 0.084 ;
    END
  END bank_read_addr[60]
  PIN bank_read_addr[61]
    DIRECTION OUTPUT ;
    USE SIGNAL ;
    PORT
      LAYER M5 ;
        RECT  64.176 0 64.2 0.084 ;
    END
  END bank_read_addr[61]
  PIN bank_read_addr[62]
    DIRECTION OUTPUT ;
    USE SIGNAL ;
    PORT
      LAYER M5 ;
        RECT  64.272 0 64.296 0.084 ;
    END
  END bank_read_addr[62]
  PIN bank_read_addr[63]
    DIRECTION OUTPUT ;
    USE SIGNAL ;
    PORT
      LAYER M5 ;
        RECT  64.368 0 64.392 0.084 ;
    END
  END bank_read_addr[63]
  PIN bank_read_addr[64]
    DIRECTION OUTPUT ;
    USE SIGNAL ;
    PORT
      LAYER M5 ;
        RECT  64.464 0 64.488 0.084 ;
    END
  END bank_read_addr[64]
  PIN bank_read_addr[65]
    DIRECTION OUTPUT ;
    USE SIGNAL ;
    PORT
      LAYER M5 ;
        RECT  64.56 0 64.584 0.084 ;
    END
  END bank_read_addr[65]
  PIN bank_read_addr[66]
    DIRECTION OUTPUT ;
    USE SIGNAL ;
    PORT
      LAYER M5 ;
        RECT  64.656 0 64.68 0.084 ;
    END
  END bank_read_addr[66]
  PIN bank_read_addr[67]
    DIRECTION OUTPUT ;
    USE SIGNAL ;
    PORT
      LAYER M5 ;
        RECT  64.752 0 64.776 0.084 ;
    END
  END bank_read_addr[67]
  PIN bank_read_addr[68]
    DIRECTION OUTPUT ;
    USE SIGNAL ;
    PORT
      LAYER M5 ;
        RECT  64.848 0 64.872 0.084 ;
    END
  END bank_read_addr[68]
  PIN bank_read_addr[69]
    DIRECTION OUTPUT ;
    USE SIGNAL ;
    PORT
      LAYER M5 ;
        RECT  64.944 0 64.968 0.084 ;
    END
  END bank_read_addr[69]
  PIN bank_read_addr[6]
    DIRECTION OUTPUT ;
    USE SIGNAL ;
    PORT
      LAYER M5 ;
        RECT  58.896 0 58.92 0.084 ;
    END
  END bank_read_addr[6]
  PIN bank_read_addr[70]
    DIRECTION OUTPUT ;
    USE SIGNAL ;
    PORT
      LAYER M5 ;
        RECT  65.04 0 65.064 0.084 ;
    END
  END bank_read_addr[70]
  PIN bank_read_addr[71]
    DIRECTION OUTPUT ;
    USE SIGNAL ;
    PORT
      LAYER M5 ;
        RECT  65.136 0 65.16 0.084 ;
    END
  END bank_read_addr[71]
  PIN bank_read_addr[72]
    DIRECTION OUTPUT ;
    USE SIGNAL ;
    PORT
      LAYER M5 ;
        RECT  65.232 0 65.256 0.084 ;
    END
  END bank_read_addr[72]
  PIN bank_read_addr[73]
    DIRECTION OUTPUT ;
    USE SIGNAL ;
    PORT
      LAYER M5 ;
        RECT  65.328 0 65.352 0.084 ;
    END
  END bank_read_addr[73]
  PIN bank_read_addr[74]
    DIRECTION OUTPUT ;
    USE SIGNAL ;
    PORT
      LAYER M5 ;
        RECT  65.424 0 65.448 0.084 ;
    END
  END bank_read_addr[74]
  PIN bank_read_addr[75]
    DIRECTION OUTPUT ;
    USE SIGNAL ;
    PORT
      LAYER M5 ;
        RECT  65.52 0 65.544 0.084 ;
    END
  END bank_read_addr[75]
  PIN bank_read_addr[76]
    DIRECTION OUTPUT ;
    USE SIGNAL ;
    PORT
      LAYER M5 ;
        RECT  65.616 0 65.64 0.084 ;
    END
  END bank_read_addr[76]
  PIN bank_read_addr[77]
    DIRECTION OUTPUT ;
    USE SIGNAL ;
    PORT
      LAYER M5 ;
        RECT  65.712 0 65.736 0.084 ;
    END
  END bank_read_addr[77]
  PIN bank_read_addr[78]
    DIRECTION OUTPUT ;
    USE SIGNAL ;
    PORT
      LAYER M5 ;
        RECT  65.808 0 65.832 0.084 ;
    END
  END bank_read_addr[78]
  PIN bank_read_addr[79]
    DIRECTION OUTPUT ;
    USE SIGNAL ;
    PORT
      LAYER M5 ;
        RECT  65.904 0 65.928 0.084 ;
    END
  END bank_read_addr[79]
  PIN bank_read_addr[7]
    DIRECTION OUTPUT ;
    USE SIGNAL ;
    PORT
      LAYER M5 ;
        RECT  58.992 0 59.016 0.084 ;
    END
  END bank_read_addr[7]
  PIN bank_read_addr[80]
    DIRECTION OUTPUT ;
    USE SIGNAL ;
    PORT
      LAYER M5 ;
        RECT  66 0 66.024 0.084 ;
    END
  END bank_read_addr[80]
  PIN bank_read_addr[81]
    DIRECTION OUTPUT ;
    USE SIGNAL ;
    PORT
      LAYER M5 ;
        RECT  66.096 0 66.12 0.084 ;
    END
  END bank_read_addr[81]
  PIN bank_read_addr[82]
    DIRECTION OUTPUT ;
    USE SIGNAL ;
    PORT
      LAYER M5 ;
        RECT  66.192 0 66.216 0.084 ;
    END
  END bank_read_addr[82]
  PIN bank_read_addr[83]
    DIRECTION OUTPUT ;
    USE SIGNAL ;
    PORT
      LAYER M5 ;
        RECT  66.288 0 66.312 0.084 ;
    END
  END bank_read_addr[83]
  PIN bank_read_addr[84]
    DIRECTION OUTPUT ;
    USE SIGNAL ;
    PORT
      LAYER M5 ;
        RECT  66.384 0 66.408 0.084 ;
    END
  END bank_read_addr[84]
  PIN bank_read_addr[85]
    DIRECTION OUTPUT ;
    USE SIGNAL ;
    PORT
      LAYER M5 ;
        RECT  66.48 0 66.504 0.084 ;
    END
  END bank_read_addr[85]
  PIN bank_read_addr[86]
    DIRECTION OUTPUT ;
    USE SIGNAL ;
    PORT
      LAYER M5 ;
        RECT  66.576 0 66.6 0.084 ;
    END
  END bank_read_addr[86]
  PIN bank_read_addr[87]
    DIRECTION OUTPUT ;
    USE SIGNAL ;
    PORT
      LAYER M5 ;
        RECT  66.672 0 66.696 0.084 ;
    END
  END bank_read_addr[87]
  PIN bank_read_addr[88]
    DIRECTION OUTPUT ;
    USE SIGNAL ;
    PORT
      LAYER M5 ;
        RECT  66.768 0 66.792 0.084 ;
    END
  END bank_read_addr[88]
  PIN bank_read_addr[89]
    DIRECTION OUTPUT ;
    USE SIGNAL ;
    PORT
      LAYER M5 ;
        RECT  66.864 0 66.888 0.084 ;
    END
  END bank_read_addr[89]
  PIN bank_read_addr[8]
    DIRECTION OUTPUT ;
    USE SIGNAL ;
    PORT
      LAYER M5 ;
        RECT  59.088 0 59.112 0.084 ;
    END
  END bank_read_addr[8]
  PIN bank_read_addr[90]
    DIRECTION OUTPUT ;
    USE SIGNAL ;
    PORT
      LAYER M5 ;
        RECT  66.96 0 66.984 0.084 ;
    END
  END bank_read_addr[90]
  PIN bank_read_addr[91]
    DIRECTION OUTPUT ;
    USE SIGNAL ;
    PORT
      LAYER M5 ;
        RECT  67.056 0 67.08 0.084 ;
    END
  END bank_read_addr[91]
  PIN bank_read_addr[92]
    DIRECTION OUTPUT ;
    USE SIGNAL ;
    PORT
      LAYER M5 ;
        RECT  67.152 0 67.176 0.084 ;
    END
  END bank_read_addr[92]
  PIN bank_read_addr[93]
    DIRECTION OUTPUT ;
    USE SIGNAL ;
    PORT
      LAYER M5 ;
        RECT  67.248 0 67.272 0.084 ;
    END
  END bank_read_addr[93]
  PIN bank_read_addr[94]
    DIRECTION OUTPUT ;
    USE SIGNAL ;
    PORT
      LAYER M5 ;
        RECT  67.344 0 67.368 0.084 ;
    END
  END bank_read_addr[94]
  PIN bank_read_addr[95]
    DIRECTION OUTPUT ;
    USE SIGNAL ;
    PORT
      LAYER M5 ;
        RECT  67.44 0 67.464 0.084 ;
    END
  END bank_read_addr[95]
  PIN bank_read_addr[96]
    DIRECTION OUTPUT ;
    USE SIGNAL ;
    PORT
      LAYER M5 ;
        RECT  45.264 0 45.288 0.084 ;
    END
  END bank_read_addr[96]
  PIN bank_read_addr[97]
    DIRECTION OUTPUT ;
    USE SIGNAL ;
    PORT
      LAYER M5 ;
        RECT  45.36 0 45.384 0.084 ;
    END
  END bank_read_addr[97]
  PIN bank_read_addr[98]
    DIRECTION OUTPUT ;
    USE SIGNAL ;
    PORT
      LAYER M5 ;
        RECT  45.456 0 45.48 0.084 ;
    END
  END bank_read_addr[98]
  PIN bank_read_addr[99]
    DIRECTION OUTPUT ;
    USE SIGNAL ;
    PORT
      LAYER M5 ;
        RECT  45.552 0 45.576 0.084 ;
    END
  END bank_read_addr[99]
  PIN bank_read_addr[9]
    DIRECTION OUTPUT ;
    USE SIGNAL ;
    PORT
      LAYER M5 ;
        RECT  59.184 0 59.208 0.084 ;
    END
  END bank_read_addr[9]
  PIN bank_read_en[0]
    DIRECTION OUTPUT ;
    USE SIGNAL ;
    PORT
      LAYER M4 ;
        RECT  0 37.68 0.084 37.704 ;
    END
  END bank_read_en[0]
  PIN bank_read_en[1]
    DIRECTION OUTPUT ;
    USE SIGNAL ;
    PORT
      LAYER M4 ;
        RECT  0 37.776 0.084 37.8 ;
    END
  END bank_read_en[1]
  PIN bank_read_en[2]
    DIRECTION OUTPUT ;
    USE SIGNAL ;
    PORT
      LAYER M4 ;
        RECT  0 37.872 0.084 37.896 ;
    END
  END bank_read_en[2]
  PIN bank_read_en[3]
    DIRECTION OUTPUT ;
    USE SIGNAL ;
    PORT
      LAYER M4 ;
        RECT  0 37.968 0.084 37.992 ;
    END
  END bank_read_en[3]
  PIN bank_read_en[4]
    DIRECTION OUTPUT ;
    USE SIGNAL ;
    PORT
      LAYER M4 ;
        RECT  0 38.064 0.084 38.088 ;
    END
  END bank_read_en[4]
  PIN bank_read_en[5]
    DIRECTION OUTPUT ;
    USE SIGNAL ;
    PORT
      LAYER M4 ;
        RECT  0 38.16 0.084 38.184 ;
    END
  END bank_read_en[5]
  PIN bank_read_en[6]
    DIRECTION OUTPUT ;
    USE SIGNAL ;
    PORT
      LAYER M4 ;
        RECT  0 38.256 0.084 38.28 ;
    END
  END bank_read_en[6]
  PIN bank_read_en[7]
    DIRECTION OUTPUT ;
    USE SIGNAL ;
    PORT
      LAYER M4 ;
        RECT  0 38.352 0.084 38.376 ;
    END
  END bank_read_en[7]
  PIN bank_read_slot[0]
    DIRECTION OUTPUT ;
    USE SIGNAL ;
    PORT
      LAYER M4 ;
        RECT  0 38.448 0.084 38.472 ;
    END
  END bank_read_slot[0]
  PIN bank_read_slot[1]
    DIRECTION OUTPUT ;
    USE SIGNAL ;
    PORT
      LAYER M4 ;
        RECT  0 38.544 0.084 38.568 ;
    END
  END bank_read_slot[1]
  PIN bank_read_slot[2]
    DIRECTION OUTPUT ;
    USE SIGNAL ;
    PORT
      LAYER M4 ;
        RECT  0 38.64 0.084 38.664 ;
    END
  END bank_read_slot[2]
  PIN bank_read_slot[3]
    DIRECTION OUTPUT ;
    USE SIGNAL ;
    PORT
      LAYER M4 ;
        RECT  0 38.736 0.084 38.76 ;
    END
  END bank_read_slot[3]
  PIN bank_read_slot[4]
    DIRECTION OUTPUT ;
    USE SIGNAL ;
    PORT
      LAYER M4 ;
        RECT  0 38.832 0.084 38.856 ;
    END
  END bank_read_slot[4]
  PIN bank_read_slot[5]
    DIRECTION OUTPUT ;
    USE SIGNAL ;
    PORT
      LAYER M4 ;
        RECT  0 38.928 0.084 38.952 ;
    END
  END bank_read_slot[5]
  PIN bank_read_slot[6]
    DIRECTION OUTPUT ;
    USE SIGNAL ;
    PORT
      LAYER M4 ;
        RECT  0 39.024 0.084 39.048 ;
    END
  END bank_read_slot[6]
  PIN bank_write_slot[0]
    DIRECTION OUTPUT ;
    USE SIGNAL ;
    PORT
      LAYER M4 ;
        RECT  0 39.12 0.084 39.144 ;
    END
  END bank_write_slot[0]
  PIN bank_write_slot[1]
    DIRECTION OUTPUT ;
    USE SIGNAL ;
    PORT
      LAYER M4 ;
        RECT  0 39.216 0.084 39.24 ;
    END
  END bank_write_slot[1]
  PIN bank_write_slot[2]
    DIRECTION OUTPUT ;
    USE SIGNAL ;
    PORT
      LAYER M4 ;
        RECT  0 39.312 0.084 39.336 ;
    END
  END bank_write_slot[2]
  PIN bank_write_slot[3]
    DIRECTION OUTPUT ;
    USE SIGNAL ;
    PORT
      LAYER M4 ;
        RECT  0 39.408 0.084 39.432 ;
    END
  END bank_write_slot[3]
  PIN bank_write_slot[4]
    DIRECTION OUTPUT ;
    USE SIGNAL ;
    PORT
      LAYER M4 ;
        RECT  0 39.504 0.084 39.528 ;
    END
  END bank_write_slot[4]
  PIN bank_write_slot[5]
    DIRECTION OUTPUT ;
    USE SIGNAL ;
    PORT
      LAYER M4 ;
        RECT  0 39.6 0.084 39.624 ;
    END
  END bank_write_slot[5]
  PIN bank_write_slot[6]
    DIRECTION OUTPUT ;
    USE SIGNAL ;
    PORT
      LAYER M4 ;
        RECT  0 39.696 0.084 39.72 ;
    END
  END bank_write_slot[6]
  PIN busy
    DIRECTION OUTPUT ;
    USE SIGNAL ;
    PORT
      LAYER M4 ;
        RECT  69.036 51.408 69.12 51.432 ;
    END
  END busy
  PIN clk
    DIRECTION INPUT ;
    USE SIGNAL ;
    PORT
      LAYER M4 ;
        RECT  69.036 51.504 69.12 51.528 ;
    END
  END clk
  PIN cycle_in[0]
    DIRECTION INPUT ;
    USE SIGNAL ;
    PORT
      LAYER M4 ;
        RECT  69.036 51.6 69.12 51.624 ;
    END
  END cycle_in[0]
  PIN cycle_in[10]
    DIRECTION INPUT ;
    USE SIGNAL ;
    PORT
      LAYER M4 ;
        RECT  69.036 52.56 69.12 52.584 ;
    END
  END cycle_in[10]
  PIN cycle_in[11]
    DIRECTION INPUT ;
    USE SIGNAL ;
    PORT
      LAYER M4 ;
        RECT  69.036 52.656 69.12 52.68 ;
    END
  END cycle_in[11]
  PIN cycle_in[12]
    DIRECTION INPUT ;
    USE SIGNAL ;
    PORT
      LAYER M4 ;
        RECT  69.036 52.752 69.12 52.776 ;
    END
  END cycle_in[12]
  PIN cycle_in[13]
    DIRECTION INPUT ;
    USE SIGNAL ;
    PORT
      LAYER M4 ;
        RECT  69.036 52.848 69.12 52.872 ;
    END
  END cycle_in[13]
  PIN cycle_in[14]
    DIRECTION INPUT ;
    USE SIGNAL ;
    PORT
      LAYER M4 ;
        RECT  69.036 52.944 69.12 52.968 ;
    END
  END cycle_in[14]
  PIN cycle_in[15]
    DIRECTION INPUT ;
    USE SIGNAL ;
    PORT
      LAYER M4 ;
        RECT  69.036 53.04 69.12 53.064 ;
    END
  END cycle_in[15]
  PIN cycle_in[16]
    DIRECTION INPUT ;
    USE SIGNAL ;
    PORT
      LAYER M4 ;
        RECT  69.036 53.136 69.12 53.16 ;
    END
  END cycle_in[16]
  PIN cycle_in[17]
    DIRECTION INPUT ;
    USE SIGNAL ;
    PORT
      LAYER M4 ;
        RECT  69.036 53.232 69.12 53.256 ;
    END
  END cycle_in[17]
  PIN cycle_in[18]
    DIRECTION INPUT ;
    USE SIGNAL ;
    PORT
      LAYER M4 ;
        RECT  69.036 53.328 69.12 53.352 ;
    END
  END cycle_in[18]
  PIN cycle_in[19]
    DIRECTION INPUT ;
    USE SIGNAL ;
    PORT
      LAYER M4 ;
        RECT  69.036 53.424 69.12 53.448 ;
    END
  END cycle_in[19]
  PIN cycle_in[1]
    DIRECTION INPUT ;
    USE SIGNAL ;
    PORT
      LAYER M4 ;
        RECT  69.036 51.696 69.12 51.72 ;
    END
  END cycle_in[1]
  PIN cycle_in[20]
    DIRECTION INPUT ;
    USE SIGNAL ;
    PORT
      LAYER M4 ;
        RECT  69.036 53.52 69.12 53.544 ;
    END
  END cycle_in[20]
  PIN cycle_in[21]
    DIRECTION INPUT ;
    USE SIGNAL ;
    PORT
      LAYER M4 ;
        RECT  69.036 53.616 69.12 53.64 ;
    END
  END cycle_in[21]
  PIN cycle_in[22]
    DIRECTION INPUT ;
    USE SIGNAL ;
    PORT
      LAYER M4 ;
        RECT  69.036 53.712 69.12 53.736 ;
    END
  END cycle_in[22]
  PIN cycle_in[23]
    DIRECTION INPUT ;
    USE SIGNAL ;
    PORT
      LAYER M4 ;
        RECT  69.036 53.808 69.12 53.832 ;
    END
  END cycle_in[23]
  PIN cycle_in[24]
    DIRECTION INPUT ;
    USE SIGNAL ;
    PORT
      LAYER M4 ;
        RECT  69.036 53.904 69.12 53.928 ;
    END
  END cycle_in[24]
  PIN cycle_in[25]
    DIRECTION INPUT ;
    USE SIGNAL ;
    PORT
      LAYER M4 ;
        RECT  69.036 54 69.12 54.024 ;
    END
  END cycle_in[25]
  PIN cycle_in[26]
    DIRECTION INPUT ;
    USE SIGNAL ;
    PORT
      LAYER M4 ;
        RECT  69.036 54.096 69.12 54.12 ;
    END
  END cycle_in[26]
  PIN cycle_in[27]
    DIRECTION INPUT ;
    USE SIGNAL ;
    PORT
      LAYER M4 ;
        RECT  69.036 54.192 69.12 54.216 ;
    END
  END cycle_in[27]
  PIN cycle_in[28]
    DIRECTION INPUT ;
    USE SIGNAL ;
    PORT
      LAYER M4 ;
        RECT  69.036 54.288 69.12 54.312 ;
    END
  END cycle_in[28]
  PIN cycle_in[29]
    DIRECTION INPUT ;
    USE SIGNAL ;
    PORT
      LAYER M4 ;
        RECT  69.036 54.384 69.12 54.408 ;
    END
  END cycle_in[29]
  PIN cycle_in[2]
    DIRECTION INPUT ;
    USE SIGNAL ;
    PORT
      LAYER M4 ;
        RECT  69.036 51.792 69.12 51.816 ;
    END
  END cycle_in[2]
  PIN cycle_in[30]
    DIRECTION INPUT ;
    USE SIGNAL ;
    PORT
      LAYER M4 ;
        RECT  69.036 58.32 69.12 58.344 ;
    END
  END cycle_in[30]
  PIN cycle_in[31]
    DIRECTION INPUT ;
    USE SIGNAL ;
    PORT
      LAYER M4 ;
        RECT  69.036 58.416 69.12 58.44 ;
    END
  END cycle_in[31]
  PIN cycle_in[3]
    DIRECTION INPUT ;
    USE SIGNAL ;
    PORT
      LAYER M4 ;
        RECT  69.036 51.888 69.12 51.912 ;
    END
  END cycle_in[3]
  PIN cycle_in[4]
    DIRECTION INPUT ;
    USE SIGNAL ;
    PORT
      LAYER M4 ;
        RECT  69.036 51.984 69.12 52.008 ;
    END
  END cycle_in[4]
  PIN cycle_in[5]
    DIRECTION INPUT ;
    USE SIGNAL ;
    PORT
      LAYER M4 ;
        RECT  69.036 52.08 69.12 52.104 ;
    END
  END cycle_in[5]
  PIN cycle_in[6]
    DIRECTION INPUT ;
    USE SIGNAL ;
    PORT
      LAYER M4 ;
        RECT  69.036 52.176 69.12 52.2 ;
    END
  END cycle_in[6]
  PIN cycle_in[7]
    DIRECTION INPUT ;
    USE SIGNAL ;
    PORT
      LAYER M4 ;
        RECT  69.036 52.272 69.12 52.296 ;
    END
  END cycle_in[7]
  PIN cycle_in[8]
    DIRECTION INPUT ;
    USE SIGNAL ;
    PORT
      LAYER M4 ;
        RECT  69.036 52.368 69.12 52.392 ;
    END
  END cycle_in[8]
  PIN cycle_in[9]
    DIRECTION INPUT ;
    USE SIGNAL ;
    PORT
      LAYER M4 ;
        RECT  69.036 52.464 69.12 52.488 ;
    END
  END cycle_in[9]
  PIN drain_at[0]
    DIRECTION INPUT ;
    USE SIGNAL ;
    PORT
      LAYER M4 ;
        RECT  69.036 58.512 69.12 58.536 ;
    END
  END drain_at[0]
  PIN drain_at[10]
    DIRECTION INPUT ;
    USE SIGNAL ;
    PORT
      LAYER M4 ;
        RECT  69.036 59.472 69.12 59.496 ;
    END
  END drain_at[10]
  PIN drain_at[11]
    DIRECTION INPUT ;
    USE SIGNAL ;
    PORT
      LAYER M4 ;
        RECT  69.036 59.568 69.12 59.592 ;
    END
  END drain_at[11]
  PIN drain_at[12]
    DIRECTION INPUT ;
    USE SIGNAL ;
    PORT
      LAYER M4 ;
        RECT  69.036 59.664 69.12 59.688 ;
    END
  END drain_at[12]
  PIN drain_at[13]
    DIRECTION INPUT ;
    USE SIGNAL ;
    PORT
      LAYER M4 ;
        RECT  69.036 59.76 69.12 59.784 ;
    END
  END drain_at[13]
  PIN drain_at[14]
    DIRECTION INPUT ;
    USE SIGNAL ;
    PORT
      LAYER M4 ;
        RECT  69.036 59.856 69.12 59.88 ;
    END
  END drain_at[14]
  PIN drain_at[15]
    DIRECTION INPUT ;
    USE SIGNAL ;
    PORT
      LAYER M4 ;
        RECT  69.036 59.952 69.12 59.976 ;
    END
  END drain_at[15]
  PIN drain_at[16]
    DIRECTION INPUT ;
    USE SIGNAL ;
    PORT
      LAYER M4 ;
        RECT  69.036 60.048 69.12 60.072 ;
    END
  END drain_at[16]
  PIN drain_at[17]
    DIRECTION INPUT ;
    USE SIGNAL ;
    PORT
      LAYER M4 ;
        RECT  69.036 60.144 69.12 60.168 ;
    END
  END drain_at[17]
  PIN drain_at[18]
    DIRECTION INPUT ;
    USE SIGNAL ;
    PORT
      LAYER M4 ;
        RECT  69.036 60.24 69.12 60.264 ;
    END
  END drain_at[18]
  PIN drain_at[19]
    DIRECTION INPUT ;
    USE SIGNAL ;
    PORT
      LAYER M4 ;
        RECT  69.036 60.336 69.12 60.36 ;
    END
  END drain_at[19]
  PIN drain_at[1]
    DIRECTION INPUT ;
    USE SIGNAL ;
    PORT
      LAYER M4 ;
        RECT  69.036 58.608 69.12 58.632 ;
    END
  END drain_at[1]
  PIN drain_at[20]
    DIRECTION INPUT ;
    USE SIGNAL ;
    PORT
      LAYER M4 ;
        RECT  69.036 60.432 69.12 60.456 ;
    END
  END drain_at[20]
  PIN drain_at[21]
    DIRECTION INPUT ;
    USE SIGNAL ;
    PORT
      LAYER M4 ;
        RECT  69.036 60.528 69.12 60.552 ;
    END
  END drain_at[21]
  PIN drain_at[22]
    DIRECTION INPUT ;
    USE SIGNAL ;
    PORT
      LAYER M4 ;
        RECT  69.036 60.624 69.12 60.648 ;
    END
  END drain_at[22]
  PIN drain_at[23]
    DIRECTION INPUT ;
    USE SIGNAL ;
    PORT
      LAYER M4 ;
        RECT  69.036 60.72 69.12 60.744 ;
    END
  END drain_at[23]
  PIN drain_at[24]
    DIRECTION INPUT ;
    USE SIGNAL ;
    PORT
      LAYER M4 ;
        RECT  69.036 60.816 69.12 60.84 ;
    END
  END drain_at[24]
  PIN drain_at[25]
    DIRECTION INPUT ;
    USE SIGNAL ;
    PORT
      LAYER M4 ;
        RECT  69.036 60.912 69.12 60.936 ;
    END
  END drain_at[25]
  PIN drain_at[26]
    DIRECTION INPUT ;
    USE SIGNAL ;
    PORT
      LAYER M4 ;
        RECT  69.036 61.008 69.12 61.032 ;
    END
  END drain_at[26]
  PIN drain_at[27]
    DIRECTION INPUT ;
    USE SIGNAL ;
    PORT
      LAYER M4 ;
        RECT  69.036 61.104 69.12 61.128 ;
    END
  END drain_at[27]
  PIN drain_at[28]
    DIRECTION INPUT ;
    USE SIGNAL ;
    PORT
      LAYER M4 ;
        RECT  69.036 61.2 69.12 61.224 ;
    END
  END drain_at[28]
  PIN drain_at[29]
    DIRECTION INPUT ;
    USE SIGNAL ;
    PORT
      LAYER M4 ;
        RECT  69.036 61.296 69.12 61.32 ;
    END
  END drain_at[29]
  PIN drain_at[2]
    DIRECTION INPUT ;
    USE SIGNAL ;
    PORT
      LAYER M4 ;
        RECT  69.036 58.704 69.12 58.728 ;
    END
  END drain_at[2]
  PIN drain_at[30]
    DIRECTION INPUT ;
    USE SIGNAL ;
    PORT
      LAYER M4 ;
        RECT  69.036 64.464 69.12 64.488 ;
    END
  END drain_at[30]
  PIN drain_at[31]
    DIRECTION INPUT ;
    USE SIGNAL ;
    PORT
      LAYER M4 ;
        RECT  69.036 64.56 69.12 64.584 ;
    END
  END drain_at[31]
  PIN drain_at[3]
    DIRECTION INPUT ;
    USE SIGNAL ;
    PORT
      LAYER M4 ;
        RECT  69.036 58.8 69.12 58.824 ;
    END
  END drain_at[3]
  PIN drain_at[4]
    DIRECTION INPUT ;
    USE SIGNAL ;
    PORT
      LAYER M4 ;
        RECT  69.036 58.896 69.12 58.92 ;
    END
  END drain_at[4]
  PIN drain_at[5]
    DIRECTION INPUT ;
    USE SIGNAL ;
    PORT
      LAYER M4 ;
        RECT  69.036 58.992 69.12 59.016 ;
    END
  END drain_at[5]
  PIN drain_at[6]
    DIRECTION INPUT ;
    USE SIGNAL ;
    PORT
      LAYER M4 ;
        RECT  69.036 59.088 69.12 59.112 ;
    END
  END drain_at[6]
  PIN drain_at[7]
    DIRECTION INPUT ;
    USE SIGNAL ;
    PORT
      LAYER M4 ;
        RECT  69.036 59.184 69.12 59.208 ;
    END
  END drain_at[7]
  PIN drain_at[8]
    DIRECTION INPUT ;
    USE SIGNAL ;
    PORT
      LAYER M4 ;
        RECT  69.036 59.28 69.12 59.304 ;
    END
  END drain_at[8]
  PIN drain_at[9]
    DIRECTION INPUT ;
    USE SIGNAL ;
    PORT
      LAYER M4 ;
        RECT  69.036 59.376 69.12 59.4 ;
    END
  END drain_at[9]
  PIN issue_at[0]
    DIRECTION INPUT ;
    USE SIGNAL ;
    PORT
      LAYER M4 ;
        RECT  69.036 64.656 69.12 64.68 ;
    END
  END issue_at[0]
  PIN issue_at[10]
    DIRECTION INPUT ;
    USE SIGNAL ;
    PORT
      LAYER M4 ;
        RECT  69.036 65.616 69.12 65.64 ;
    END
  END issue_at[10]
  PIN issue_at[11]
    DIRECTION INPUT ;
    USE SIGNAL ;
    PORT
      LAYER M4 ;
        RECT  69.036 65.712 69.12 65.736 ;
    END
  END issue_at[11]
  PIN issue_at[12]
    DIRECTION INPUT ;
    USE SIGNAL ;
    PORT
      LAYER M4 ;
        RECT  69.036 65.808 69.12 65.832 ;
    END
  END issue_at[12]
  PIN issue_at[13]
    DIRECTION INPUT ;
    USE SIGNAL ;
    PORT
      LAYER M4 ;
        RECT  69.036 65.904 69.12 65.928 ;
    END
  END issue_at[13]
  PIN issue_at[14]
    DIRECTION INPUT ;
    USE SIGNAL ;
    PORT
      LAYER M4 ;
        RECT  69.036 66 69.12 66.024 ;
    END
  END issue_at[14]
  PIN issue_at[15]
    DIRECTION INPUT ;
    USE SIGNAL ;
    PORT
      LAYER M4 ;
        RECT  69.036 66.096 69.12 66.12 ;
    END
  END issue_at[15]
  PIN issue_at[16]
    DIRECTION INPUT ;
    USE SIGNAL ;
    PORT
      LAYER M4 ;
        RECT  69.036 66.192 69.12 66.216 ;
    END
  END issue_at[16]
  PIN issue_at[17]
    DIRECTION INPUT ;
    USE SIGNAL ;
    PORT
      LAYER M4 ;
        RECT  69.036 66.288 69.12 66.312 ;
    END
  END issue_at[17]
  PIN issue_at[18]
    DIRECTION INPUT ;
    USE SIGNAL ;
    PORT
      LAYER M4 ;
        RECT  69.036 66.384 69.12 66.408 ;
    END
  END issue_at[18]
  PIN issue_at[19]
    DIRECTION INPUT ;
    USE SIGNAL ;
    PORT
      LAYER M4 ;
        RECT  69.036 66.48 69.12 66.504 ;
    END
  END issue_at[19]
  PIN issue_at[1]
    DIRECTION INPUT ;
    USE SIGNAL ;
    PORT
      LAYER M4 ;
        RECT  69.036 64.752 69.12 64.776 ;
    END
  END issue_at[1]
  PIN issue_at[20]
    DIRECTION INPUT ;
    USE SIGNAL ;
    PORT
      LAYER M4 ;
        RECT  69.036 66.576 69.12 66.6 ;
    END
  END issue_at[20]
  PIN issue_at[21]
    DIRECTION INPUT ;
    USE SIGNAL ;
    PORT
      LAYER M4 ;
        RECT  69.036 66.672 69.12 66.696 ;
    END
  END issue_at[21]
  PIN issue_at[22]
    DIRECTION INPUT ;
    USE SIGNAL ;
    PORT
      LAYER M4 ;
        RECT  69.036 66.768 69.12 66.792 ;
    END
  END issue_at[22]
  PIN issue_at[23]
    DIRECTION INPUT ;
    USE SIGNAL ;
    PORT
      LAYER M4 ;
        RECT  69.036 66.864 69.12 66.888 ;
    END
  END issue_at[23]
  PIN issue_at[24]
    DIRECTION INPUT ;
    USE SIGNAL ;
    PORT
      LAYER M4 ;
        RECT  69.036 66.96 69.12 66.984 ;
    END
  END issue_at[24]
  PIN issue_at[25]
    DIRECTION INPUT ;
    USE SIGNAL ;
    PORT
      LAYER M4 ;
        RECT  69.036 67.056 69.12 67.08 ;
    END
  END issue_at[25]
  PIN issue_at[26]
    DIRECTION INPUT ;
    USE SIGNAL ;
    PORT
      LAYER M4 ;
        RECT  69.036 67.152 69.12 67.176 ;
    END
  END issue_at[26]
  PIN issue_at[27]
    DIRECTION INPUT ;
    USE SIGNAL ;
    PORT
      LAYER M4 ;
        RECT  69.036 67.248 69.12 67.272 ;
    END
  END issue_at[27]
  PIN issue_at[28]
    DIRECTION INPUT ;
    USE SIGNAL ;
    PORT
      LAYER M4 ;
        RECT  69.036 67.344 69.12 67.368 ;
    END
  END issue_at[28]
  PIN issue_at[29]
    DIRECTION INPUT ;
    USE SIGNAL ;
    PORT
      LAYER M4 ;
        RECT  69.036 67.44 69.12 67.464 ;
    END
  END issue_at[29]
  PIN issue_at[2]
    DIRECTION INPUT ;
    USE SIGNAL ;
    PORT
      LAYER M4 ;
        RECT  69.036 64.848 69.12 64.872 ;
    END
  END issue_at[2]
  PIN issue_at[30]
    DIRECTION INPUT ;
    USE SIGNAL ;
    PORT
      LAYER M4 ;
        RECT  69.036 29.136 69.12 29.16 ;
    END
  END issue_at[30]
  PIN issue_at[31]
    DIRECTION INPUT ;
    USE SIGNAL ;
    PORT
      LAYER M4 ;
        RECT  69.036 29.232 69.12 29.256 ;
    END
  END issue_at[31]
  PIN issue_at[3]
    DIRECTION INPUT ;
    USE SIGNAL ;
    PORT
      LAYER M4 ;
        RECT  69.036 64.944 69.12 64.968 ;
    END
  END issue_at[3]
  PIN issue_at[4]
    DIRECTION INPUT ;
    USE SIGNAL ;
    PORT
      LAYER M4 ;
        RECT  69.036 65.04 69.12 65.064 ;
    END
  END issue_at[4]
  PIN issue_at[5]
    DIRECTION INPUT ;
    USE SIGNAL ;
    PORT
      LAYER M4 ;
        RECT  69.036 65.136 69.12 65.16 ;
    END
  END issue_at[5]
  PIN issue_at[6]
    DIRECTION INPUT ;
    USE SIGNAL ;
    PORT
      LAYER M4 ;
        RECT  69.036 65.232 69.12 65.256 ;
    END
  END issue_at[6]
  PIN issue_at[7]
    DIRECTION INPUT ;
    USE SIGNAL ;
    PORT
      LAYER M4 ;
        RECT  69.036 65.328 69.12 65.352 ;
    END
  END issue_at[7]
  PIN issue_at[8]
    DIRECTION INPUT ;
    USE SIGNAL ;
    PORT
      LAYER M4 ;
        RECT  69.036 65.424 69.12 65.448 ;
    END
  END issue_at[8]
  PIN issue_at[9]
    DIRECTION INPUT ;
    USE SIGNAL ;
    PORT
      LAYER M4 ;
        RECT  69.036 65.52 69.12 65.544 ;
    END
  END issue_at[9]
  PIN mv[0]
    DIRECTION INPUT ;
    USE SIGNAL ;
    PORT
      LAYER M4 ;
        RECT  69.036 29.328 69.12 29.352 ;
    END
  END mv[0]
  PIN mv[100]
    DIRECTION INPUT ;
    USE SIGNAL ;
    PORT
      LAYER M4 ;
        RECT  69.036 16.656 69.12 16.68 ;
    END
  END mv[100]
  PIN mv[101]
    DIRECTION INPUT ;
    USE SIGNAL ;
    PORT
      LAYER M4 ;
        RECT  69.036 16.752 69.12 16.776 ;
    END
  END mv[101]
  PIN mv[102]
    DIRECTION INPUT ;
    USE SIGNAL ;
    PORT
      LAYER M4 ;
        RECT  69.036 16.848 69.12 16.872 ;
    END
  END mv[102]
  PIN mv[103]
    DIRECTION INPUT ;
    USE SIGNAL ;
    PORT
      LAYER M4 ;
        RECT  69.036 16.944 69.12 16.968 ;
    END
  END mv[103]
  PIN mv[104]
    DIRECTION INPUT ;
    USE SIGNAL ;
    PORT
      LAYER M4 ;
        RECT  69.036 17.04 69.12 17.064 ;
    END
  END mv[104]
  PIN mv[105]
    DIRECTION INPUT ;
    USE SIGNAL ;
    PORT
      LAYER M4 ;
        RECT  69.036 17.136 69.12 17.16 ;
    END
  END mv[105]
  PIN mv[106]
    DIRECTION INPUT ;
    USE SIGNAL ;
    PORT
      LAYER M4 ;
        RECT  69.036 17.232 69.12 17.256 ;
    END
  END mv[106]
  PIN mv[107]
    DIRECTION INPUT ;
    USE SIGNAL ;
    PORT
      LAYER M4 ;
        RECT  69.036 17.328 69.12 17.352 ;
    END
  END mv[107]
  PIN mv[108]
    DIRECTION INPUT ;
    USE SIGNAL ;
    PORT
      LAYER M4 ;
        RECT  69.036 17.424 69.12 17.448 ;
    END
  END mv[108]
  PIN mv[109]
    DIRECTION INPUT ;
    USE SIGNAL ;
    PORT
      LAYER M4 ;
        RECT  69.036 17.52 69.12 17.544 ;
    END
  END mv[109]
  PIN mv[10]
    DIRECTION INPUT ;
    USE SIGNAL ;
    PORT
      LAYER M4 ;
        RECT  69.036 30.288 69.12 30.312 ;
    END
  END mv[10]
  PIN mv[110]
    DIRECTION INPUT ;
    USE SIGNAL ;
    PORT
      LAYER M4 ;
        RECT  69.036 17.616 69.12 17.64 ;
    END
  END mv[110]
  PIN mv[111]
    DIRECTION INPUT ;
    USE SIGNAL ;
    PORT
      LAYER M4 ;
        RECT  69.036 17.712 69.12 17.736 ;
    END
  END mv[111]
  PIN mv[112]
    DIRECTION INPUT ;
    USE SIGNAL ;
    PORT
      LAYER M4 ;
        RECT  69.036 17.808 69.12 17.832 ;
    END
  END mv[112]
  PIN mv[113]
    DIRECTION INPUT ;
    USE SIGNAL ;
    PORT
      LAYER M4 ;
        RECT  69.036 17.904 69.12 17.928 ;
    END
  END mv[113]
  PIN mv[114]
    DIRECTION INPUT ;
    USE SIGNAL ;
    PORT
      LAYER M4 ;
        RECT  69.036 18 69.12 18.024 ;
    END
  END mv[114]
  PIN mv[115]
    DIRECTION INPUT ;
    USE SIGNAL ;
    PORT
      LAYER M4 ;
        RECT  69.036 18.096 69.12 18.12 ;
    END
  END mv[115]
  PIN mv[116]
    DIRECTION INPUT ;
    USE SIGNAL ;
    PORT
      LAYER M4 ;
        RECT  69.036 18.192 69.12 18.216 ;
    END
  END mv[116]
  PIN mv[117]
    DIRECTION INPUT ;
    USE SIGNAL ;
    PORT
      LAYER M4 ;
        RECT  69.036 18.288 69.12 18.312 ;
    END
  END mv[117]
  PIN mv[118]
    DIRECTION INPUT ;
    USE SIGNAL ;
    PORT
      LAYER M4 ;
        RECT  69.036 18.384 69.12 18.408 ;
    END
  END mv[118]
  PIN mv[119]
    DIRECTION INPUT ;
    USE SIGNAL ;
    PORT
      LAYER M4 ;
        RECT  69.036 18.48 69.12 18.504 ;
    END
  END mv[119]
  PIN mv[11]
    DIRECTION INPUT ;
    USE SIGNAL ;
    PORT
      LAYER M4 ;
        RECT  69.036 30.384 69.12 30.408 ;
    END
  END mv[11]
  PIN mv[120]
    DIRECTION INPUT ;
    USE SIGNAL ;
    PORT
      LAYER M4 ;
        RECT  69.036 18.576 69.12 18.6 ;
    END
  END mv[120]
  PIN mv[121]
    DIRECTION INPUT ;
    USE SIGNAL ;
    PORT
      LAYER M4 ;
        RECT  69.036 18.672 69.12 18.696 ;
    END
  END mv[121]
  PIN mv[122]
    DIRECTION INPUT ;
    USE SIGNAL ;
    PORT
      LAYER M4 ;
        RECT  69.036 18.768 69.12 18.792 ;
    END
  END mv[122]
  PIN mv[123]
    DIRECTION INPUT ;
    USE SIGNAL ;
    PORT
      LAYER M4 ;
        RECT  69.036 18.864 69.12 18.888 ;
    END
  END mv[123]
  PIN mv[124]
    DIRECTION INPUT ;
    USE SIGNAL ;
    PORT
      LAYER M4 ;
        RECT  69.036 18.96 69.12 18.984 ;
    END
  END mv[124]
  PIN mv[125]
    DIRECTION INPUT ;
    USE SIGNAL ;
    PORT
      LAYER M4 ;
        RECT  69.036 19.056 69.12 19.08 ;
    END
  END mv[125]
  PIN mv[126]
    DIRECTION INPUT ;
    USE SIGNAL ;
    PORT
      LAYER M4 ;
        RECT  69.036 13.008 69.12 13.032 ;
    END
  END mv[126]
  PIN mv[127]
    DIRECTION INPUT ;
    USE SIGNAL ;
    PORT
      LAYER M4 ;
        RECT  69.036 13.104 69.12 13.128 ;
    END
  END mv[127]
  PIN mv[128]
    DIRECTION INPUT ;
    USE SIGNAL ;
    PORT
      LAYER M4 ;
        RECT  69.036 13.2 69.12 13.224 ;
    END
  END mv[128]
  PIN mv[129]
    DIRECTION INPUT ;
    USE SIGNAL ;
    PORT
      LAYER M4 ;
        RECT  69.036 13.296 69.12 13.32 ;
    END
  END mv[129]
  PIN mv[12]
    DIRECTION INPUT ;
    USE SIGNAL ;
    PORT
      LAYER M4 ;
        RECT  69.036 30.48 69.12 30.504 ;
    END
  END mv[12]
  PIN mv[130]
    DIRECTION INPUT ;
    USE SIGNAL ;
    PORT
      LAYER M4 ;
        RECT  69.036 13.392 69.12 13.416 ;
    END
  END mv[130]
  PIN mv[131]
    DIRECTION INPUT ;
    USE SIGNAL ;
    PORT
      LAYER M4 ;
        RECT  69.036 13.488 69.12 13.512 ;
    END
  END mv[131]
  PIN mv[132]
    DIRECTION INPUT ;
    USE SIGNAL ;
    PORT
      LAYER M4 ;
        RECT  69.036 13.584 69.12 13.608 ;
    END
  END mv[132]
  PIN mv[133]
    DIRECTION INPUT ;
    USE SIGNAL ;
    PORT
      LAYER M4 ;
        RECT  69.036 13.68 69.12 13.704 ;
    END
  END mv[133]
  PIN mv[134]
    DIRECTION INPUT ;
    USE SIGNAL ;
    PORT
      LAYER M4 ;
        RECT  69.036 13.776 69.12 13.8 ;
    END
  END mv[134]
  PIN mv[135]
    DIRECTION INPUT ;
    USE SIGNAL ;
    PORT
      LAYER M4 ;
        RECT  69.036 13.872 69.12 13.896 ;
    END
  END mv[135]
  PIN mv[136]
    DIRECTION INPUT ;
    USE SIGNAL ;
    PORT
      LAYER M4 ;
        RECT  69.036 13.968 69.12 13.992 ;
    END
  END mv[136]
  PIN mv[137]
    DIRECTION INPUT ;
    USE SIGNAL ;
    PORT
      LAYER M4 ;
        RECT  69.036 14.064 69.12 14.088 ;
    END
  END mv[137]
  PIN mv[138]
    DIRECTION INPUT ;
    USE SIGNAL ;
    PORT
      LAYER M4 ;
        RECT  69.036 14.16 69.12 14.184 ;
    END
  END mv[138]
  PIN mv[139]
    DIRECTION INPUT ;
    USE SIGNAL ;
    PORT
      LAYER M4 ;
        RECT  69.036 14.256 69.12 14.28 ;
    END
  END mv[139]
  PIN mv[13]
    DIRECTION INPUT ;
    USE SIGNAL ;
    PORT
      LAYER M4 ;
        RECT  69.036 30.576 69.12 30.6 ;
    END
  END mv[13]
  PIN mv[140]
    DIRECTION INPUT ;
    USE SIGNAL ;
    PORT
      LAYER M4 ;
        RECT  69.036 14.352 69.12 14.376 ;
    END
  END mv[140]
  PIN mv[141]
    DIRECTION INPUT ;
    USE SIGNAL ;
    PORT
      LAYER M4 ;
        RECT  69.036 14.448 69.12 14.472 ;
    END
  END mv[141]
  PIN mv[142]
    DIRECTION INPUT ;
    USE SIGNAL ;
    PORT
      LAYER M4 ;
        RECT  69.036 14.544 69.12 14.568 ;
    END
  END mv[142]
  PIN mv[143]
    DIRECTION INPUT ;
    USE SIGNAL ;
    PORT
      LAYER M4 ;
        RECT  69.036 14.64 69.12 14.664 ;
    END
  END mv[143]
  PIN mv[144]
    DIRECTION INPUT ;
    USE SIGNAL ;
    PORT
      LAYER M4 ;
        RECT  69.036 14.736 69.12 14.76 ;
    END
  END mv[144]
  PIN mv[145]
    DIRECTION INPUT ;
    USE SIGNAL ;
    PORT
      LAYER M4 ;
        RECT  69.036 14.832 69.12 14.856 ;
    END
  END mv[145]
  PIN mv[146]
    DIRECTION INPUT ;
    USE SIGNAL ;
    PORT
      LAYER M4 ;
        RECT  69.036 14.928 69.12 14.952 ;
    END
  END mv[146]
  PIN mv[147]
    DIRECTION INPUT ;
    USE SIGNAL ;
    PORT
      LAYER M4 ;
        RECT  69.036 15.024 69.12 15.048 ;
    END
  END mv[147]
  PIN mv[148]
    DIRECTION INPUT ;
    USE SIGNAL ;
    PORT
      LAYER M4 ;
        RECT  69.036 15.12 69.12 15.144 ;
    END
  END mv[148]
  PIN mv[149]
    DIRECTION INPUT ;
    USE SIGNAL ;
    PORT
      LAYER M4 ;
        RECT  69.036 15.216 69.12 15.24 ;
    END
  END mv[149]
  PIN mv[14]
    DIRECTION INPUT ;
    USE SIGNAL ;
    PORT
      LAYER M4 ;
        RECT  69.036 30.672 69.12 30.696 ;
    END
  END mv[14]
  PIN mv[150]
    DIRECTION INPUT ;
    USE SIGNAL ;
    PORT
      LAYER M4 ;
        RECT  69.036 15.312 69.12 15.336 ;
    END
  END mv[150]
  PIN mv[151]
    DIRECTION INPUT ;
    USE SIGNAL ;
    PORT
      LAYER M4 ;
        RECT  69.036 15.408 69.12 15.432 ;
    END
  END mv[151]
  PIN mv[152]
    DIRECTION INPUT ;
    USE SIGNAL ;
    PORT
      LAYER M4 ;
        RECT  69.036 15.504 69.12 15.528 ;
    END
  END mv[152]
  PIN mv[153]
    DIRECTION INPUT ;
    USE SIGNAL ;
    PORT
      LAYER M4 ;
        RECT  69.036 15.6 69.12 15.624 ;
    END
  END mv[153]
  PIN mv[154]
    DIRECTION INPUT ;
    USE SIGNAL ;
    PORT
      LAYER M4 ;
        RECT  69.036 15.696 69.12 15.72 ;
    END
  END mv[154]
  PIN mv[155]
    DIRECTION INPUT ;
    USE SIGNAL ;
    PORT
      LAYER M4 ;
        RECT  69.036 15.792 69.12 15.816 ;
    END
  END mv[155]
  PIN mv[156]
    DIRECTION INPUT ;
    USE SIGNAL ;
    PORT
      LAYER M4 ;
        RECT  69.036 15.888 69.12 15.912 ;
    END
  END mv[156]
  PIN mv[157]
    DIRECTION INPUT ;
    USE SIGNAL ;
    PORT
      LAYER M4 ;
        RECT  69.036 15.984 69.12 16.008 ;
    END
  END mv[157]
  PIN mv[158]
    DIRECTION INPUT ;
    USE SIGNAL ;
    PORT
      LAYER M4 ;
        RECT  69.036 19.92 69.12 19.944 ;
    END
  END mv[158]
  PIN mv[159]
    DIRECTION INPUT ;
    USE SIGNAL ;
    PORT
      LAYER M4 ;
        RECT  69.036 20.016 69.12 20.04 ;
    END
  END mv[159]
  PIN mv[15]
    DIRECTION INPUT ;
    USE SIGNAL ;
    PORT
      LAYER M4 ;
        RECT  69.036 30.768 69.12 30.792 ;
    END
  END mv[15]
  PIN mv[160]
    DIRECTION INPUT ;
    USE SIGNAL ;
    PORT
      LAYER M4 ;
        RECT  69.036 20.112 69.12 20.136 ;
    END
  END mv[160]
  PIN mv[161]
    DIRECTION INPUT ;
    USE SIGNAL ;
    PORT
      LAYER M4 ;
        RECT  69.036 20.208 69.12 20.232 ;
    END
  END mv[161]
  PIN mv[162]
    DIRECTION INPUT ;
    USE SIGNAL ;
    PORT
      LAYER M4 ;
        RECT  69.036 20.304 69.12 20.328 ;
    END
  END mv[162]
  PIN mv[163]
    DIRECTION INPUT ;
    USE SIGNAL ;
    PORT
      LAYER M4 ;
        RECT  69.036 20.4 69.12 20.424 ;
    END
  END mv[163]
  PIN mv[164]
    DIRECTION INPUT ;
    USE SIGNAL ;
    PORT
      LAYER M4 ;
        RECT  69.036 20.496 69.12 20.52 ;
    END
  END mv[164]
  PIN mv[165]
    DIRECTION INPUT ;
    USE SIGNAL ;
    PORT
      LAYER M4 ;
        RECT  69.036 20.592 69.12 20.616 ;
    END
  END mv[165]
  PIN mv[166]
    DIRECTION INPUT ;
    USE SIGNAL ;
    PORT
      LAYER M4 ;
        RECT  69.036 20.688 69.12 20.712 ;
    END
  END mv[166]
  PIN mv[167]
    DIRECTION INPUT ;
    USE SIGNAL ;
    PORT
      LAYER M4 ;
        RECT  69.036 20.784 69.12 20.808 ;
    END
  END mv[167]
  PIN mv[168]
    DIRECTION INPUT ;
    USE SIGNAL ;
    PORT
      LAYER M4 ;
        RECT  69.036 20.88 69.12 20.904 ;
    END
  END mv[168]
  PIN mv[169]
    DIRECTION INPUT ;
    USE SIGNAL ;
    PORT
      LAYER M4 ;
        RECT  69.036 20.976 69.12 21 ;
    END
  END mv[169]
  PIN mv[16]
    DIRECTION INPUT ;
    USE SIGNAL ;
    PORT
      LAYER M4 ;
        RECT  69.036 30.864 69.12 30.888 ;
    END
  END mv[16]
  PIN mv[170]
    DIRECTION INPUT ;
    USE SIGNAL ;
    PORT
      LAYER M4 ;
        RECT  69.036 21.072 69.12 21.096 ;
    END
  END mv[170]
  PIN mv[171]
    DIRECTION INPUT ;
    USE SIGNAL ;
    PORT
      LAYER M4 ;
        RECT  69.036 21.168 69.12 21.192 ;
    END
  END mv[171]
  PIN mv[172]
    DIRECTION INPUT ;
    USE SIGNAL ;
    PORT
      LAYER M4 ;
        RECT  69.036 21.264 69.12 21.288 ;
    END
  END mv[172]
  PIN mv[173]
    DIRECTION INPUT ;
    USE SIGNAL ;
    PORT
      LAYER M4 ;
        RECT  69.036 21.36 69.12 21.384 ;
    END
  END mv[173]
  PIN mv[174]
    DIRECTION INPUT ;
    USE SIGNAL ;
    PORT
      LAYER M4 ;
        RECT  69.036 21.456 69.12 21.48 ;
    END
  END mv[174]
  PIN mv[175]
    DIRECTION INPUT ;
    USE SIGNAL ;
    PORT
      LAYER M4 ;
        RECT  69.036 21.552 69.12 21.576 ;
    END
  END mv[175]
  PIN mv[176]
    DIRECTION INPUT ;
    USE SIGNAL ;
    PORT
      LAYER M4 ;
        RECT  69.036 21.648 69.12 21.672 ;
    END
  END mv[176]
  PIN mv[177]
    DIRECTION INPUT ;
    USE SIGNAL ;
    PORT
      LAYER M4 ;
        RECT  69.036 21.744 69.12 21.768 ;
    END
  END mv[177]
  PIN mv[178]
    DIRECTION INPUT ;
    USE SIGNAL ;
    PORT
      LAYER M4 ;
        RECT  69.036 21.84 69.12 21.864 ;
    END
  END mv[178]
  PIN mv[179]
    DIRECTION INPUT ;
    USE SIGNAL ;
    PORT
      LAYER M4 ;
        RECT  69.036 21.936 69.12 21.96 ;
    END
  END mv[179]
  PIN mv[17]
    DIRECTION INPUT ;
    USE SIGNAL ;
    PORT
      LAYER M4 ;
        RECT  69.036 30.96 69.12 30.984 ;
    END
  END mv[17]
  PIN mv[180]
    DIRECTION INPUT ;
    USE SIGNAL ;
    PORT
      LAYER M4 ;
        RECT  69.036 22.032 69.12 22.056 ;
    END
  END mv[180]
  PIN mv[181]
    DIRECTION INPUT ;
    USE SIGNAL ;
    PORT
      LAYER M4 ;
        RECT  69.036 22.128 69.12 22.152 ;
    END
  END mv[181]
  PIN mv[182]
    DIRECTION INPUT ;
    USE SIGNAL ;
    PORT
      LAYER M4 ;
        RECT  69.036 22.224 69.12 22.248 ;
    END
  END mv[182]
  PIN mv[183]
    DIRECTION INPUT ;
    USE SIGNAL ;
    PORT
      LAYER M4 ;
        RECT  69.036 22.32 69.12 22.344 ;
    END
  END mv[183]
  PIN mv[184]
    DIRECTION INPUT ;
    USE SIGNAL ;
    PORT
      LAYER M4 ;
        RECT  69.036 22.416 69.12 22.44 ;
    END
  END mv[184]
  PIN mv[185]
    DIRECTION INPUT ;
    USE SIGNAL ;
    PORT
      LAYER M4 ;
        RECT  69.036 22.512 69.12 22.536 ;
    END
  END mv[185]
  PIN mv[186]
    DIRECTION INPUT ;
    USE SIGNAL ;
    PORT
      LAYER M4 ;
        RECT  69.036 22.608 69.12 22.632 ;
    END
  END mv[186]
  PIN mv[187]
    DIRECTION INPUT ;
    USE SIGNAL ;
    PORT
      LAYER M4 ;
        RECT  69.036 22.704 69.12 22.728 ;
    END
  END mv[187]
  PIN mv[188]
    DIRECTION INPUT ;
    USE SIGNAL ;
    PORT
      LAYER M4 ;
        RECT  69.036 22.8 69.12 22.824 ;
    END
  END mv[188]
  PIN mv[189]
    DIRECTION INPUT ;
    USE SIGNAL ;
    PORT
      LAYER M4 ;
        RECT  69.036 22.896 69.12 22.92 ;
    END
  END mv[189]
  PIN mv[18]
    DIRECTION INPUT ;
    USE SIGNAL ;
    PORT
      LAYER M4 ;
        RECT  69.036 31.056 69.12 31.08 ;
    END
  END mv[18]
  PIN mv[190]
    DIRECTION INPUT ;
    USE SIGNAL ;
    PORT
      LAYER M4 ;
        RECT  69.036 22.992 69.12 23.016 ;
    END
  END mv[190]
  PIN mv[191]
    DIRECTION INPUT ;
    USE SIGNAL ;
    PORT
      LAYER M4 ;
        RECT  69.036 23.088 69.12 23.112 ;
    END
  END mv[191]
  PIN mv[192]
    DIRECTION INPUT ;
    USE SIGNAL ;
    PORT
      LAYER M4 ;
        RECT  69.036 23.184 69.12 23.208 ;
    END
  END mv[192]
  PIN mv[193]
    DIRECTION INPUT ;
    USE SIGNAL ;
    PORT
      LAYER M4 ;
        RECT  69.036 23.28 69.12 23.304 ;
    END
  END mv[193]
  PIN mv[194]
    DIRECTION INPUT ;
    USE SIGNAL ;
    PORT
      LAYER M4 ;
        RECT  69.036 23.376 69.12 23.4 ;
    END
  END mv[194]
  PIN mv[195]
    DIRECTION INPUT ;
    USE SIGNAL ;
    PORT
      LAYER M4 ;
        RECT  69.036 23.472 69.12 23.496 ;
    END
  END mv[195]
  PIN mv[196]
    DIRECTION INPUT ;
    USE SIGNAL ;
    PORT
      LAYER M4 ;
        RECT  69.036 23.568 69.12 23.592 ;
    END
  END mv[196]
  PIN mv[197]
    DIRECTION INPUT ;
    USE SIGNAL ;
    PORT
      LAYER M4 ;
        RECT  69.036 23.664 69.12 23.688 ;
    END
  END mv[197]
  PIN mv[198]
    DIRECTION INPUT ;
    USE SIGNAL ;
    PORT
      LAYER M4 ;
        RECT  69.036 23.76 69.12 23.784 ;
    END
  END mv[198]
  PIN mv[199]
    DIRECTION INPUT ;
    USE SIGNAL ;
    PORT
      LAYER M4 ;
        RECT  69.036 23.856 69.12 23.88 ;
    END
  END mv[199]
  PIN mv[19]
    DIRECTION INPUT ;
    USE SIGNAL ;
    PORT
      LAYER M4 ;
        RECT  69.036 31.152 69.12 31.176 ;
    END
  END mv[19]
  PIN mv[1]
    DIRECTION INPUT ;
    USE SIGNAL ;
    PORT
      LAYER M4 ;
        RECT  69.036 29.424 69.12 29.448 ;
    END
  END mv[1]
  PIN mv[200]
    DIRECTION INPUT ;
    USE SIGNAL ;
    PORT
      LAYER M4 ;
        RECT  69.036 23.952 69.12 23.976 ;
    END
  END mv[200]
  PIN mv[201]
    DIRECTION INPUT ;
    USE SIGNAL ;
    PORT
      LAYER M4 ;
        RECT  69.036 24.048 69.12 24.072 ;
    END
  END mv[201]
  PIN mv[202]
    DIRECTION INPUT ;
    USE SIGNAL ;
    PORT
      LAYER M4 ;
        RECT  69.036 24.144 69.12 24.168 ;
    END
  END mv[202]
  PIN mv[203]
    DIRECTION INPUT ;
    USE SIGNAL ;
    PORT
      LAYER M4 ;
        RECT  69.036 24.24 69.12 24.264 ;
    END
  END mv[203]
  PIN mv[204]
    DIRECTION INPUT ;
    USE SIGNAL ;
    PORT
      LAYER M4 ;
        RECT  69.036 24.336 69.12 24.36 ;
    END
  END mv[204]
  PIN mv[205]
    DIRECTION INPUT ;
    USE SIGNAL ;
    PORT
      LAYER M4 ;
        RECT  69.036 24.432 69.12 24.456 ;
    END
  END mv[205]
  PIN mv[206]
    DIRECTION INPUT ;
    USE SIGNAL ;
    PORT
      LAYER M4 ;
        RECT  69.036 24.528 69.12 24.552 ;
    END
  END mv[206]
  PIN mv[207]
    DIRECTION INPUT ;
    USE SIGNAL ;
    PORT
      LAYER M4 ;
        RECT  69.036 24.624 69.12 24.648 ;
    END
  END mv[207]
  PIN mv[208]
    DIRECTION INPUT ;
    USE SIGNAL ;
    PORT
      LAYER M4 ;
        RECT  69.036 24.72 69.12 24.744 ;
    END
  END mv[208]
  PIN mv[209]
    DIRECTION INPUT ;
    USE SIGNAL ;
    PORT
      LAYER M4 ;
        RECT  69.036 24.816 69.12 24.84 ;
    END
  END mv[209]
  PIN mv[20]
    DIRECTION INPUT ;
    USE SIGNAL ;
    PORT
      LAYER M4 ;
        RECT  69.036 31.248 69.12 31.272 ;
    END
  END mv[20]
  PIN mv[210]
    DIRECTION INPUT ;
    USE SIGNAL ;
    PORT
      LAYER M4 ;
        RECT  69.036 24.912 69.12 24.936 ;
    END
  END mv[210]
  PIN mv[211]
    DIRECTION INPUT ;
    USE SIGNAL ;
    PORT
      LAYER M4 ;
        RECT  69.036 25.008 69.12 25.032 ;
    END
  END mv[211]
  PIN mv[212]
    DIRECTION INPUT ;
    USE SIGNAL ;
    PORT
      LAYER M4 ;
        RECT  69.036 25.104 69.12 25.128 ;
    END
  END mv[212]
  PIN mv[213]
    DIRECTION INPUT ;
    USE SIGNAL ;
    PORT
      LAYER M4 ;
        RECT  69.036 25.2 69.12 25.224 ;
    END
  END mv[213]
  PIN mv[214]
    DIRECTION INPUT ;
    USE SIGNAL ;
    PORT
      LAYER M4 ;
        RECT  69.036 25.296 69.12 25.32 ;
    END
  END mv[214]
  PIN mv[215]
    DIRECTION INPUT ;
    USE SIGNAL ;
    PORT
      LAYER M4 ;
        RECT  69.036 25.392 69.12 25.416 ;
    END
  END mv[215]
  PIN mv[216]
    DIRECTION INPUT ;
    USE SIGNAL ;
    PORT
      LAYER M4 ;
        RECT  69.036 25.488 69.12 25.512 ;
    END
  END mv[216]
  PIN mv[217]
    DIRECTION INPUT ;
    USE SIGNAL ;
    PORT
      LAYER M4 ;
        RECT  69.036 25.584 69.12 25.608 ;
    END
  END mv[217]
  PIN mv[218]
    DIRECTION INPUT ;
    USE SIGNAL ;
    PORT
      LAYER M4 ;
        RECT  69.036 25.68 69.12 25.704 ;
    END
  END mv[218]
  PIN mv[219]
    DIRECTION INPUT ;
    USE SIGNAL ;
    PORT
      LAYER M4 ;
        RECT  69.036 25.776 69.12 25.8 ;
    END
  END mv[219]
  PIN mv[21]
    DIRECTION INPUT ;
    USE SIGNAL ;
    PORT
      LAYER M4 ;
        RECT  69.036 31.344 69.12 31.368 ;
    END
  END mv[21]
  PIN mv[220]
    DIRECTION INPUT ;
    USE SIGNAL ;
    PORT
      LAYER M4 ;
        RECT  69.036 25.872 69.12 25.896 ;
    END
  END mv[220]
  PIN mv[221]
    DIRECTION INPUT ;
    USE SIGNAL ;
    PORT
      LAYER M4 ;
        RECT  69.036 25.968 69.12 25.992 ;
    END
  END mv[221]
  PIN mv[222]
    DIRECTION INPUT ;
    USE SIGNAL ;
    PORT
      LAYER M4 ;
        RECT  69.036 61.392 69.12 61.416 ;
    END
  END mv[222]
  PIN mv[223]
    DIRECTION INPUT ;
    USE SIGNAL ;
    PORT
      LAYER M4 ;
        RECT  69.036 61.488 69.12 61.512 ;
    END
  END mv[223]
  PIN mv[224]
    DIRECTION INPUT ;
    USE SIGNAL ;
    PORT
      LAYER M4 ;
        RECT  69.036 61.584 69.12 61.608 ;
    END
  END mv[224]
  PIN mv[225]
    DIRECTION INPUT ;
    USE SIGNAL ;
    PORT
      LAYER M4 ;
        RECT  69.036 61.68 69.12 61.704 ;
    END
  END mv[225]
  PIN mv[226]
    DIRECTION INPUT ;
    USE SIGNAL ;
    PORT
      LAYER M4 ;
        RECT  69.036 61.776 69.12 61.8 ;
    END
  END mv[226]
  PIN mv[22]
    DIRECTION INPUT ;
    USE SIGNAL ;
    PORT
      LAYER M4 ;
        RECT  69.036 31.44 69.12 31.464 ;
    END
  END mv[22]
  PIN mv[23]
    DIRECTION INPUT ;
    USE SIGNAL ;
    PORT
      LAYER M4 ;
        RECT  69.036 31.536 69.12 31.56 ;
    END
  END mv[23]
  PIN mv[24]
    DIRECTION INPUT ;
    USE SIGNAL ;
    PORT
      LAYER M4 ;
        RECT  69.036 31.632 69.12 31.656 ;
    END
  END mv[24]
  PIN mv[25]
    DIRECTION INPUT ;
    USE SIGNAL ;
    PORT
      LAYER M4 ;
        RECT  69.036 31.728 69.12 31.752 ;
    END
  END mv[25]
  PIN mv[26]
    DIRECTION INPUT ;
    USE SIGNAL ;
    PORT
      LAYER M4 ;
        RECT  69.036 31.824 69.12 31.848 ;
    END
  END mv[26]
  PIN mv[27]
    DIRECTION INPUT ;
    USE SIGNAL ;
    PORT
      LAYER M4 ;
        RECT  69.036 31.92 69.12 31.944 ;
    END
  END mv[27]
  PIN mv[28]
    DIRECTION INPUT ;
    USE SIGNAL ;
    PORT
      LAYER M4 ;
        RECT  69.036 32.016 69.12 32.04 ;
    END
  END mv[28]
  PIN mv[29]
    DIRECTION INPUT ;
    USE SIGNAL ;
    PORT
      LAYER M4 ;
        RECT  69.036 32.112 69.12 32.136 ;
    END
  END mv[29]
  PIN mv[2]
    DIRECTION INPUT ;
    USE SIGNAL ;
    PORT
      LAYER M4 ;
        RECT  69.036 29.52 69.12 29.544 ;
    END
  END mv[2]
  PIN mv[30]
    DIRECTION INPUT ;
    USE SIGNAL ;
    PORT
      LAYER M4 ;
        RECT  69.036 9.936 69.12 9.96 ;
    END
  END mv[30]
  PIN mv[31]
    DIRECTION INPUT ;
    USE SIGNAL ;
    PORT
      LAYER M4 ;
        RECT  69.036 10.032 69.12 10.056 ;
    END
  END mv[31]
  PIN mv[32]
    DIRECTION INPUT ;
    USE SIGNAL ;
    PORT
      LAYER M4 ;
        RECT  69.036 10.128 69.12 10.152 ;
    END
  END mv[32]
  PIN mv[33]
    DIRECTION INPUT ;
    USE SIGNAL ;
    PORT
      LAYER M4 ;
        RECT  69.036 10.224 69.12 10.248 ;
    END
  END mv[33]
  PIN mv[34]
    DIRECTION INPUT ;
    USE SIGNAL ;
    PORT
      LAYER M4 ;
        RECT  69.036 10.32 69.12 10.344 ;
    END
  END mv[34]
  PIN mv[35]
    DIRECTION INPUT ;
    USE SIGNAL ;
    PORT
      LAYER M4 ;
        RECT  69.036 10.416 69.12 10.44 ;
    END
  END mv[35]
  PIN mv[36]
    DIRECTION INPUT ;
    USE SIGNAL ;
    PORT
      LAYER M4 ;
        RECT  69.036 10.512 69.12 10.536 ;
    END
  END mv[36]
  PIN mv[37]
    DIRECTION INPUT ;
    USE SIGNAL ;
    PORT
      LAYER M4 ;
        RECT  69.036 10.608 69.12 10.632 ;
    END
  END mv[37]
  PIN mv[38]
    DIRECTION INPUT ;
    USE SIGNAL ;
    PORT
      LAYER M4 ;
        RECT  69.036 10.704 69.12 10.728 ;
    END
  END mv[38]
  PIN mv[39]
    DIRECTION INPUT ;
    USE SIGNAL ;
    PORT
      LAYER M4 ;
        RECT  69.036 10.8 69.12 10.824 ;
    END
  END mv[39]
  PIN mv[3]
    DIRECTION INPUT ;
    USE SIGNAL ;
    PORT
      LAYER M4 ;
        RECT  69.036 29.616 69.12 29.64 ;
    END
  END mv[3]
  PIN mv[40]
    DIRECTION INPUT ;
    USE SIGNAL ;
    PORT
      LAYER M4 ;
        RECT  69.036 10.896 69.12 10.92 ;
    END
  END mv[40]
  PIN mv[41]
    DIRECTION INPUT ;
    USE SIGNAL ;
    PORT
      LAYER M4 ;
        RECT  69.036 10.992 69.12 11.016 ;
    END
  END mv[41]
  PIN mv[42]
    DIRECTION INPUT ;
    USE SIGNAL ;
    PORT
      LAYER M4 ;
        RECT  69.036 11.088 69.12 11.112 ;
    END
  END mv[42]
  PIN mv[43]
    DIRECTION INPUT ;
    USE SIGNAL ;
    PORT
      LAYER M4 ;
        RECT  69.036 11.184 69.12 11.208 ;
    END
  END mv[43]
  PIN mv[44]
    DIRECTION INPUT ;
    USE SIGNAL ;
    PORT
      LAYER M4 ;
        RECT  69.036 11.28 69.12 11.304 ;
    END
  END mv[44]
  PIN mv[45]
    DIRECTION INPUT ;
    USE SIGNAL ;
    PORT
      LAYER M4 ;
        RECT  69.036 11.376 69.12 11.4 ;
    END
  END mv[45]
  PIN mv[46]
    DIRECTION INPUT ;
    USE SIGNAL ;
    PORT
      LAYER M4 ;
        RECT  69.036 11.472 69.12 11.496 ;
    END
  END mv[46]
  PIN mv[47]
    DIRECTION INPUT ;
    USE SIGNAL ;
    PORT
      LAYER M4 ;
        RECT  69.036 11.568 69.12 11.592 ;
    END
  END mv[47]
  PIN mv[48]
    DIRECTION INPUT ;
    USE SIGNAL ;
    PORT
      LAYER M4 ;
        RECT  69.036 11.664 69.12 11.688 ;
    END
  END mv[48]
  PIN mv[49]
    DIRECTION INPUT ;
    USE SIGNAL ;
    PORT
      LAYER M4 ;
        RECT  69.036 11.76 69.12 11.784 ;
    END
  END mv[49]
  PIN mv[4]
    DIRECTION INPUT ;
    USE SIGNAL ;
    PORT
      LAYER M4 ;
        RECT  69.036 29.712 69.12 29.736 ;
    END
  END mv[4]
  PIN mv[50]
    DIRECTION INPUT ;
    USE SIGNAL ;
    PORT
      LAYER M4 ;
        RECT  69.036 11.856 69.12 11.88 ;
    END
  END mv[50]
  PIN mv[51]
    DIRECTION INPUT ;
    USE SIGNAL ;
    PORT
      LAYER M4 ;
        RECT  69.036 11.952 69.12 11.976 ;
    END
  END mv[51]
  PIN mv[52]
    DIRECTION INPUT ;
    USE SIGNAL ;
    PORT
      LAYER M4 ;
        RECT  69.036 12.048 69.12 12.072 ;
    END
  END mv[52]
  PIN mv[53]
    DIRECTION INPUT ;
    USE SIGNAL ;
    PORT
      LAYER M4 ;
        RECT  69.036 12.144 69.12 12.168 ;
    END
  END mv[53]
  PIN mv[54]
    DIRECTION INPUT ;
    USE SIGNAL ;
    PORT
      LAYER M4 ;
        RECT  69.036 12.24 69.12 12.264 ;
    END
  END mv[54]
  PIN mv[55]
    DIRECTION INPUT ;
    USE SIGNAL ;
    PORT
      LAYER M4 ;
        RECT  69.036 12.336 69.12 12.36 ;
    END
  END mv[55]
  PIN mv[56]
    DIRECTION INPUT ;
    USE SIGNAL ;
    PORT
      LAYER M4 ;
        RECT  69.036 12.432 69.12 12.456 ;
    END
  END mv[56]
  PIN mv[57]
    DIRECTION INPUT ;
    USE SIGNAL ;
    PORT
      LAYER M4 ;
        RECT  69.036 12.528 69.12 12.552 ;
    END
  END mv[57]
  PIN mv[58]
    DIRECTION INPUT ;
    USE SIGNAL ;
    PORT
      LAYER M4 ;
        RECT  69.036 12.624 69.12 12.648 ;
    END
  END mv[58]
  PIN mv[59]
    DIRECTION INPUT ;
    USE SIGNAL ;
    PORT
      LAYER M4 ;
        RECT  69.036 12.72 69.12 12.744 ;
    END
  END mv[59]
  PIN mv[5]
    DIRECTION INPUT ;
    USE SIGNAL ;
    PORT
      LAYER M4 ;
        RECT  69.036 29.808 69.12 29.832 ;
    END
  END mv[5]
  PIN mv[60]
    DIRECTION INPUT ;
    USE SIGNAL ;
    PORT
      LAYER M4 ;
        RECT  69.036 12.816 69.12 12.84 ;
    END
  END mv[60]
  PIN mv[61]
    DIRECTION INPUT ;
    USE SIGNAL ;
    PORT
      LAYER M4 ;
        RECT  69.036 12.912 69.12 12.936 ;
    END
  END mv[61]
  PIN mv[62]
    DIRECTION INPUT ;
    USE SIGNAL ;
    PORT
      LAYER M4 ;
        RECT  69.036 26.064 69.12 26.088 ;
    END
  END mv[62]
  PIN mv[63]
    DIRECTION INPUT ;
    USE SIGNAL ;
    PORT
      LAYER M4 ;
        RECT  69.036 26.16 69.12 26.184 ;
    END
  END mv[63]
  PIN mv[64]
    DIRECTION INPUT ;
    USE SIGNAL ;
    PORT
      LAYER M4 ;
        RECT  69.036 26.256 69.12 26.28 ;
    END
  END mv[64]
  PIN mv[65]
    DIRECTION INPUT ;
    USE SIGNAL ;
    PORT
      LAYER M4 ;
        RECT  69.036 26.352 69.12 26.376 ;
    END
  END mv[65]
  PIN mv[66]
    DIRECTION INPUT ;
    USE SIGNAL ;
    PORT
      LAYER M4 ;
        RECT  69.036 26.448 69.12 26.472 ;
    END
  END mv[66]
  PIN mv[67]
    DIRECTION INPUT ;
    USE SIGNAL ;
    PORT
      LAYER M4 ;
        RECT  69.036 26.544 69.12 26.568 ;
    END
  END mv[67]
  PIN mv[68]
    DIRECTION INPUT ;
    USE SIGNAL ;
    PORT
      LAYER M4 ;
        RECT  69.036 26.64 69.12 26.664 ;
    END
  END mv[68]
  PIN mv[69]
    DIRECTION INPUT ;
    USE SIGNAL ;
    PORT
      LAYER M4 ;
        RECT  69.036 26.736 69.12 26.76 ;
    END
  END mv[69]
  PIN mv[6]
    DIRECTION INPUT ;
    USE SIGNAL ;
    PORT
      LAYER M4 ;
        RECT  69.036 29.904 69.12 29.928 ;
    END
  END mv[6]
  PIN mv[70]
    DIRECTION INPUT ;
    USE SIGNAL ;
    PORT
      LAYER M4 ;
        RECT  69.036 26.832 69.12 26.856 ;
    END
  END mv[70]
  PIN mv[71]
    DIRECTION INPUT ;
    USE SIGNAL ;
    PORT
      LAYER M4 ;
        RECT  69.036 26.928 69.12 26.952 ;
    END
  END mv[71]
  PIN mv[72]
    DIRECTION INPUT ;
    USE SIGNAL ;
    PORT
      LAYER M4 ;
        RECT  69.036 27.024 69.12 27.048 ;
    END
  END mv[72]
  PIN mv[73]
    DIRECTION INPUT ;
    USE SIGNAL ;
    PORT
      LAYER M4 ;
        RECT  69.036 27.12 69.12 27.144 ;
    END
  END mv[73]
  PIN mv[74]
    DIRECTION INPUT ;
    USE SIGNAL ;
    PORT
      LAYER M4 ;
        RECT  69.036 27.216 69.12 27.24 ;
    END
  END mv[74]
  PIN mv[75]
    DIRECTION INPUT ;
    USE SIGNAL ;
    PORT
      LAYER M4 ;
        RECT  69.036 27.312 69.12 27.336 ;
    END
  END mv[75]
  PIN mv[76]
    DIRECTION INPUT ;
    USE SIGNAL ;
    PORT
      LAYER M4 ;
        RECT  69.036 27.408 69.12 27.432 ;
    END
  END mv[76]
  PIN mv[77]
    DIRECTION INPUT ;
    USE SIGNAL ;
    PORT
      LAYER M4 ;
        RECT  69.036 27.504 69.12 27.528 ;
    END
  END mv[77]
  PIN mv[78]
    DIRECTION INPUT ;
    USE SIGNAL ;
    PORT
      LAYER M4 ;
        RECT  69.036 27.6 69.12 27.624 ;
    END
  END mv[78]
  PIN mv[79]
    DIRECTION INPUT ;
    USE SIGNAL ;
    PORT
      LAYER M4 ;
        RECT  69.036 27.696 69.12 27.72 ;
    END
  END mv[79]
  PIN mv[7]
    DIRECTION INPUT ;
    USE SIGNAL ;
    PORT
      LAYER M4 ;
        RECT  69.036 30 69.12 30.024 ;
    END
  END mv[7]
  PIN mv[80]
    DIRECTION INPUT ;
    USE SIGNAL ;
    PORT
      LAYER M4 ;
        RECT  69.036 27.792 69.12 27.816 ;
    END
  END mv[80]
  PIN mv[81]
    DIRECTION INPUT ;
    USE SIGNAL ;
    PORT
      LAYER M4 ;
        RECT  69.036 27.888 69.12 27.912 ;
    END
  END mv[81]
  PIN mv[82]
    DIRECTION INPUT ;
    USE SIGNAL ;
    PORT
      LAYER M4 ;
        RECT  69.036 27.984 69.12 28.008 ;
    END
  END mv[82]
  PIN mv[83]
    DIRECTION INPUT ;
    USE SIGNAL ;
    PORT
      LAYER M4 ;
        RECT  69.036 28.08 69.12 28.104 ;
    END
  END mv[83]
  PIN mv[84]
    DIRECTION INPUT ;
    USE SIGNAL ;
    PORT
      LAYER M4 ;
        RECT  69.036 28.176 69.12 28.2 ;
    END
  END mv[84]
  PIN mv[85]
    DIRECTION INPUT ;
    USE SIGNAL ;
    PORT
      LAYER M4 ;
        RECT  69.036 28.272 69.12 28.296 ;
    END
  END mv[85]
  PIN mv[86]
    DIRECTION INPUT ;
    USE SIGNAL ;
    PORT
      LAYER M4 ;
        RECT  69.036 28.368 69.12 28.392 ;
    END
  END mv[86]
  PIN mv[87]
    DIRECTION INPUT ;
    USE SIGNAL ;
    PORT
      LAYER M4 ;
        RECT  69.036 28.464 69.12 28.488 ;
    END
  END mv[87]
  PIN mv[88]
    DIRECTION INPUT ;
    USE SIGNAL ;
    PORT
      LAYER M4 ;
        RECT  69.036 28.56 69.12 28.584 ;
    END
  END mv[88]
  PIN mv[89]
    DIRECTION INPUT ;
    USE SIGNAL ;
    PORT
      LAYER M4 ;
        RECT  69.036 28.656 69.12 28.68 ;
    END
  END mv[89]
  PIN mv[8]
    DIRECTION INPUT ;
    USE SIGNAL ;
    PORT
      LAYER M4 ;
        RECT  69.036 30.096 69.12 30.12 ;
    END
  END mv[8]
  PIN mv[90]
    DIRECTION INPUT ;
    USE SIGNAL ;
    PORT
      LAYER M4 ;
        RECT  69.036 28.752 69.12 28.776 ;
    END
  END mv[90]
  PIN mv[91]
    DIRECTION INPUT ;
    USE SIGNAL ;
    PORT
      LAYER M4 ;
        RECT  69.036 28.848 69.12 28.872 ;
    END
  END mv[91]
  PIN mv[92]
    DIRECTION INPUT ;
    USE SIGNAL ;
    PORT
      LAYER M4 ;
        RECT  69.036 28.944 69.12 28.968 ;
    END
  END mv[92]
  PIN mv[93]
    DIRECTION INPUT ;
    USE SIGNAL ;
    PORT
      LAYER M4 ;
        RECT  69.036 29.04 69.12 29.064 ;
    END
  END mv[93]
  PIN mv[94]
    DIRECTION INPUT ;
    USE SIGNAL ;
    PORT
      LAYER M4 ;
        RECT  69.036 16.08 69.12 16.104 ;
    END
  END mv[94]
  PIN mv[95]
    DIRECTION INPUT ;
    USE SIGNAL ;
    PORT
      LAYER M4 ;
        RECT  69.036 16.176 69.12 16.2 ;
    END
  END mv[95]
  PIN mv[96]
    DIRECTION INPUT ;
    USE SIGNAL ;
    PORT
      LAYER M4 ;
        RECT  69.036 16.272 69.12 16.296 ;
    END
  END mv[96]
  PIN mv[97]
    DIRECTION INPUT ;
    USE SIGNAL ;
    PORT
      LAYER M4 ;
        RECT  69.036 16.368 69.12 16.392 ;
    END
  END mv[97]
  PIN mv[98]
    DIRECTION INPUT ;
    USE SIGNAL ;
    PORT
      LAYER M4 ;
        RECT  69.036 16.464 69.12 16.488 ;
    END
  END mv[98]
  PIN mv[99]
    DIRECTION INPUT ;
    USE SIGNAL ;
    PORT
      LAYER M4 ;
        RECT  69.036 16.56 69.12 16.584 ;
    END
  END mv[99]
  PIN mv[9]
    DIRECTION INPUT ;
    USE SIGNAL ;
    PORT
      LAYER M4 ;
        RECT  69.036 30.192 69.12 30.216 ;
    END
  END mv[9]
  PIN mv_done
    DIRECTION OUTPUT ;
    USE SIGNAL ;
    PORT
      LAYER M4 ;
        RECT  69.036 61.872 69.12 61.896 ;
    END
  END mv_done
  PIN mv_fault
    DIRECTION OUTPUT ;
    USE SIGNAL ;
    PORT
      LAYER M4 ;
        RECT  69.036 61.968 69.12 61.992 ;
    END
  END mv_fault
  PIN mv_src
    DIRECTION OUTPUT ;
    USE SIGNAL ;
    PORT
      LAYER M4 ;
        RECT  69.036 62.064 69.12 62.088 ;
    END
  END mv_src
  PIN mv_v
    DIRECTION INPUT ;
    USE SIGNAL ;
    PORT
      LAYER M4 ;
        RECT  69.036 62.16 69.12 62.184 ;
    END
  END mv_v
  PIN mv_wb_bank
    DIRECTION INPUT ;
    USE SIGNAL ;
    PORT
      LAYER M4 ;
        RECT  69.036 62.256 69.12 62.28 ;
    END
  END mv_wb_bank
  PIN mv_wb_epoch[0]
    DIRECTION INPUT ;
    USE SIGNAL ;
    PORT
      LAYER M4 ;
        RECT  69.036 62.352 69.12 62.376 ;
    END
  END mv_wb_epoch[0]
  PIN mv_wb_epoch[10]
    DIRECTION INPUT ;
    USE SIGNAL ;
    PORT
      LAYER M4 ;
        RECT  69.036 63.312 69.12 63.336 ;
    END
  END mv_wb_epoch[10]
  PIN mv_wb_epoch[11]
    DIRECTION INPUT ;
    USE SIGNAL ;
    PORT
      LAYER M4 ;
        RECT  69.036 63.408 69.12 63.432 ;
    END
  END mv_wb_epoch[11]
  PIN mv_wb_epoch[12]
    DIRECTION INPUT ;
    USE SIGNAL ;
    PORT
      LAYER M4 ;
        RECT  69.036 63.504 69.12 63.528 ;
    END
  END mv_wb_epoch[12]
  PIN mv_wb_epoch[13]
    DIRECTION INPUT ;
    USE SIGNAL ;
    PORT
      LAYER M4 ;
        RECT  69.036 63.6 69.12 63.624 ;
    END
  END mv_wb_epoch[13]
  PIN mv_wb_epoch[14]
    DIRECTION INPUT ;
    USE SIGNAL ;
    PORT
      LAYER M4 ;
        RECT  69.036 63.696 69.12 63.72 ;
    END
  END mv_wb_epoch[14]
  PIN mv_wb_epoch[15]
    DIRECTION INPUT ;
    USE SIGNAL ;
    PORT
      LAYER M4 ;
        RECT  69.036 63.792 69.12 63.816 ;
    END
  END mv_wb_epoch[15]
  PIN mv_wb_epoch[1]
    DIRECTION INPUT ;
    USE SIGNAL ;
    PORT
      LAYER M4 ;
        RECT  69.036 62.448 69.12 62.472 ;
    END
  END mv_wb_epoch[1]
  PIN mv_wb_epoch[2]
    DIRECTION INPUT ;
    USE SIGNAL ;
    PORT
      LAYER M4 ;
        RECT  69.036 62.544 69.12 62.568 ;
    END
  END mv_wb_epoch[2]
  PIN mv_wb_epoch[3]
    DIRECTION INPUT ;
    USE SIGNAL ;
    PORT
      LAYER M4 ;
        RECT  69.036 62.64 69.12 62.664 ;
    END
  END mv_wb_epoch[3]
  PIN mv_wb_epoch[4]
    DIRECTION INPUT ;
    USE SIGNAL ;
    PORT
      LAYER M4 ;
        RECT  69.036 62.736 69.12 62.76 ;
    END
  END mv_wb_epoch[4]
  PIN mv_wb_epoch[5]
    DIRECTION INPUT ;
    USE SIGNAL ;
    PORT
      LAYER M4 ;
        RECT  69.036 62.832 69.12 62.856 ;
    END
  END mv_wb_epoch[5]
  PIN mv_wb_epoch[6]
    DIRECTION INPUT ;
    USE SIGNAL ;
    PORT
      LAYER M4 ;
        RECT  69.036 62.928 69.12 62.952 ;
    END
  END mv_wb_epoch[6]
  PIN mv_wb_epoch[7]
    DIRECTION INPUT ;
    USE SIGNAL ;
    PORT
      LAYER M4 ;
        RECT  69.036 63.024 69.12 63.048 ;
    END
  END mv_wb_epoch[7]
  PIN mv_wb_epoch[8]
    DIRECTION INPUT ;
    USE SIGNAL ;
    PORT
      LAYER M4 ;
        RECT  69.036 63.12 69.12 63.144 ;
    END
  END mv_wb_epoch[8]
  PIN mv_wb_epoch[9]
    DIRECTION INPUT ;
    USE SIGNAL ;
    PORT
      LAYER M4 ;
        RECT  69.036 63.216 69.12 63.24 ;
    END
  END mv_wb_epoch[9]
  PIN quiet
    DIRECTION OUTPUT ;
    USE SIGNAL ;
    PORT
      LAYER M4 ;
        RECT  69.036 63.888 69.12 63.912 ;
    END
  END quiet
  PIN rq[0]
    DIRECTION OUTPUT ;
    USE SIGNAL ;
    PORT
      LAYER M4 ;
        RECT  0 39.792 0.084 39.816 ;
    END
  END rq[0]
  PIN rq[100]
    DIRECTION OUTPUT ;
    USE SIGNAL ;
    PORT
      LAYER M4 ;
        RECT  0 11.76 0.084 11.784 ;
    END
  END rq[100]
  PIN rq[101]
    DIRECTION OUTPUT ;
    USE SIGNAL ;
    PORT
      LAYER M4 ;
        RECT  0 11.856 0.084 11.88 ;
    END
  END rq[101]
  PIN rq[102]
    DIRECTION OUTPUT ;
    USE SIGNAL ;
    PORT
      LAYER M4 ;
        RECT  0 11.952 0.084 11.976 ;
    END
  END rq[102]
  PIN rq[103]
    DIRECTION OUTPUT ;
    USE SIGNAL ;
    PORT
      LAYER M4 ;
        RECT  0 12.048 0.084 12.072 ;
    END
  END rq[103]
  PIN rq[104]
    DIRECTION OUTPUT ;
    USE SIGNAL ;
    PORT
      LAYER M4 ;
        RECT  0 12.144 0.084 12.168 ;
    END
  END rq[104]
  PIN rq[105]
    DIRECTION OUTPUT ;
    USE SIGNAL ;
    PORT
      LAYER M4 ;
        RECT  0 12.24 0.084 12.264 ;
    END
  END rq[105]
  PIN rq[106]
    DIRECTION OUTPUT ;
    USE SIGNAL ;
    PORT
      LAYER M4 ;
        RECT  0 12.336 0.084 12.36 ;
    END
  END rq[106]
  PIN rq[107]
    DIRECTION OUTPUT ;
    USE SIGNAL ;
    PORT
      LAYER M4 ;
        RECT  0 12.432 0.084 12.456 ;
    END
  END rq[107]
  PIN rq[108]
    DIRECTION OUTPUT ;
    USE SIGNAL ;
    PORT
      LAYER M4 ;
        RECT  0 12.528 0.084 12.552 ;
    END
  END rq[108]
  PIN rq[109]
    DIRECTION OUTPUT ;
    USE SIGNAL ;
    PORT
      LAYER M4 ;
        RECT  0 12.624 0.084 12.648 ;
    END
  END rq[109]
  PIN rq[10]
    DIRECTION OUTPUT ;
    USE SIGNAL ;
    PORT
      LAYER M4 ;
        RECT  0 2.352 0.084 2.376 ;
    END
  END rq[10]
  PIN rq[110]
    DIRECTION OUTPUT ;
    USE SIGNAL ;
    PORT
      LAYER M4 ;
        RECT  0 12.72 0.084 12.744 ;
    END
  END rq[110]
  PIN rq[111]
    DIRECTION OUTPUT ;
    USE SIGNAL ;
    PORT
      LAYER M4 ;
        RECT  0 12.816 0.084 12.84 ;
    END
  END rq[111]
  PIN rq[112]
    DIRECTION OUTPUT ;
    USE SIGNAL ;
    PORT
      LAYER M4 ;
        RECT  0 12.912 0.084 12.936 ;
    END
  END rq[112]
  PIN rq[113]
    DIRECTION OUTPUT ;
    USE SIGNAL ;
    PORT
      LAYER M4 ;
        RECT  0 13.008 0.084 13.032 ;
    END
  END rq[113]
  PIN rq[114]
    DIRECTION OUTPUT ;
    USE SIGNAL ;
    PORT
      LAYER M4 ;
        RECT  0 13.104 0.084 13.128 ;
    END
  END rq[114]
  PIN rq[115]
    DIRECTION OUTPUT ;
    USE SIGNAL ;
    PORT
      LAYER M4 ;
        RECT  0 13.2 0.084 13.224 ;
    END
  END rq[115]
  PIN rq[116]
    DIRECTION OUTPUT ;
    USE SIGNAL ;
    PORT
      LAYER M4 ;
        RECT  0 13.296 0.084 13.32 ;
    END
  END rq[116]
  PIN rq[117]
    DIRECTION OUTPUT ;
    USE SIGNAL ;
    PORT
      LAYER M4 ;
        RECT  0 13.392 0.084 13.416 ;
    END
  END rq[117]
  PIN rq[118]
    DIRECTION OUTPUT ;
    USE SIGNAL ;
    PORT
      LAYER M4 ;
        RECT  0 13.488 0.084 13.512 ;
    END
  END rq[118]
  PIN rq[119]
    DIRECTION OUTPUT ;
    USE SIGNAL ;
    PORT
      LAYER M4 ;
        RECT  0 13.584 0.084 13.608 ;
    END
  END rq[119]
  PIN rq[11]
    DIRECTION OUTPUT ;
    USE SIGNAL ;
    PORT
      LAYER M4 ;
        RECT  0 2.448 0.084 2.472 ;
    END
  END rq[11]
  PIN rq[120]
    DIRECTION OUTPUT ;
    USE SIGNAL ;
    PORT
      LAYER M4 ;
        RECT  0 13.68 0.084 13.704 ;
    END
  END rq[120]
  PIN rq[121]
    DIRECTION OUTPUT ;
    USE SIGNAL ;
    PORT
      LAYER M4 ;
        RECT  0 13.776 0.084 13.8 ;
    END
  END rq[121]
  PIN rq[122]
    DIRECTION OUTPUT ;
    USE SIGNAL ;
    PORT
      LAYER M4 ;
        RECT  0 13.872 0.084 13.896 ;
    END
  END rq[122]
  PIN rq[123]
    DIRECTION OUTPUT ;
    USE SIGNAL ;
    PORT
      LAYER M4 ;
        RECT  0 13.968 0.084 13.992 ;
    END
  END rq[123]
  PIN rq[124]
    DIRECTION OUTPUT ;
    USE SIGNAL ;
    PORT
      LAYER M4 ;
        RECT  0 14.064 0.084 14.088 ;
    END
  END rq[124]
  PIN rq[125]
    DIRECTION OUTPUT ;
    USE SIGNAL ;
    PORT
      LAYER M4 ;
        RECT  0 14.16 0.084 14.184 ;
    END
  END rq[125]
  PIN rq[126]
    DIRECTION OUTPUT ;
    USE SIGNAL ;
    PORT
      LAYER M4 ;
        RECT  0 14.256 0.084 14.28 ;
    END
  END rq[126]
  PIN rq[127]
    DIRECTION OUTPUT ;
    USE SIGNAL ;
    PORT
      LAYER M4 ;
        RECT  0 14.352 0.084 14.376 ;
    END
  END rq[127]
  PIN rq[128]
    DIRECTION OUTPUT ;
    USE SIGNAL ;
    PORT
      LAYER M4 ;
        RECT  0 14.448 0.084 14.472 ;
    END
  END rq[128]
  PIN rq[129]
    DIRECTION OUTPUT ;
    USE SIGNAL ;
    PORT
      LAYER M4 ;
        RECT  0 14.544 0.084 14.568 ;
    END
  END rq[129]
  PIN rq[12]
    DIRECTION OUTPUT ;
    USE SIGNAL ;
    PORT
      LAYER M4 ;
        RECT  0 2.544 0.084 2.568 ;
    END
  END rq[12]
  PIN rq[130]
    DIRECTION OUTPUT ;
    USE SIGNAL ;
    PORT
      LAYER M4 ;
        RECT  0 41.712 0.084 41.736 ;
    END
  END rq[130]
  PIN rq[131]
    DIRECTION OUTPUT ;
    USE SIGNAL ;
    PORT
      LAYER M4 ;
        RECT  0 41.808 0.084 41.832 ;
    END
  END rq[131]
  PIN rq[132]
    DIRECTION OUTPUT ;
    USE SIGNAL ;
    PORT
      LAYER M4 ;
        RECT  0 41.904 0.084 41.928 ;
    END
  END rq[132]
  PIN rq[133]
    DIRECTION OUTPUT ;
    USE SIGNAL ;
    PORT
      LAYER M4 ;
        RECT  0 42 0.084 42.024 ;
    END
  END rq[133]
  PIN rq[134]
    DIRECTION OUTPUT ;
    USE SIGNAL ;
    PORT
      LAYER M4 ;
        RECT  0 42.096 0.084 42.12 ;
    END
  END rq[134]
  PIN rq[135]
    DIRECTION OUTPUT ;
    USE SIGNAL ;
    PORT
      LAYER M4 ;
        RECT  0 42.192 0.084 42.216 ;
    END
  END rq[135]
  PIN rq[13]
    DIRECTION OUTPUT ;
    USE SIGNAL ;
    PORT
      LAYER M4 ;
        RECT  0 2.64 0.084 2.664 ;
    END
  END rq[13]
  PIN rq[14]
    DIRECTION OUTPUT ;
    USE SIGNAL ;
    PORT
      LAYER M4 ;
        RECT  0 2.736 0.084 2.76 ;
    END
  END rq[14]
  PIN rq[15]
    DIRECTION OUTPUT ;
    USE SIGNAL ;
    PORT
      LAYER M4 ;
        RECT  0 2.832 0.084 2.856 ;
    END
  END rq[15]
  PIN rq[16]
    DIRECTION OUTPUT ;
    USE SIGNAL ;
    PORT
      LAYER M4 ;
        RECT  0 2.928 0.084 2.952 ;
    END
  END rq[16]
  PIN rq[17]
    DIRECTION OUTPUT ;
    USE SIGNAL ;
    PORT
      LAYER M4 ;
        RECT  0 3.024 0.084 3.048 ;
    END
  END rq[17]
  PIN rq[18]
    DIRECTION OUTPUT ;
    USE SIGNAL ;
    PORT
      LAYER M4 ;
        RECT  0 3.12 0.084 3.144 ;
    END
  END rq[18]
  PIN rq[19]
    DIRECTION OUTPUT ;
    USE SIGNAL ;
    PORT
      LAYER M4 ;
        RECT  0 3.216 0.084 3.24 ;
    END
  END rq[19]
  PIN rq[1]
    DIRECTION OUTPUT ;
    USE SIGNAL ;
    PORT
      LAYER M4 ;
        RECT  0 39.888 0.084 39.912 ;
    END
  END rq[1]
  PIN rq[20]
    DIRECTION OUTPUT ;
    USE SIGNAL ;
    PORT
      LAYER M4 ;
        RECT  0 3.312 0.084 3.336 ;
    END
  END rq[20]
  PIN rq[21]
    DIRECTION OUTPUT ;
    USE SIGNAL ;
    PORT
      LAYER M4 ;
        RECT  0 3.408 0.084 3.432 ;
    END
  END rq[21]
  PIN rq[22]
    DIRECTION OUTPUT ;
    USE SIGNAL ;
    PORT
      LAYER M4 ;
        RECT  0 3.504 0.084 3.528 ;
    END
  END rq[22]
  PIN rq[23]
    DIRECTION OUTPUT ;
    USE SIGNAL ;
    PORT
      LAYER M4 ;
        RECT  0 3.6 0.084 3.624 ;
    END
  END rq[23]
  PIN rq[24]
    DIRECTION OUTPUT ;
    USE SIGNAL ;
    PORT
      LAYER M4 ;
        RECT  0 3.696 0.084 3.72 ;
    END
  END rq[24]
  PIN rq[25]
    DIRECTION OUTPUT ;
    USE SIGNAL ;
    PORT
      LAYER M4 ;
        RECT  0 3.792 0.084 3.816 ;
    END
  END rq[25]
  PIN rq[26]
    DIRECTION OUTPUT ;
    USE SIGNAL ;
    PORT
      LAYER M4 ;
        RECT  0 3.888 0.084 3.912 ;
    END
  END rq[26]
  PIN rq[27]
    DIRECTION OUTPUT ;
    USE SIGNAL ;
    PORT
      LAYER M4 ;
        RECT  0 3.984 0.084 4.008 ;
    END
  END rq[27]
  PIN rq[28]
    DIRECTION OUTPUT ;
    USE SIGNAL ;
    PORT
      LAYER M4 ;
        RECT  0 4.08 0.084 4.104 ;
    END
  END rq[28]
  PIN rq[29]
    DIRECTION OUTPUT ;
    USE SIGNAL ;
    PORT
      LAYER M4 ;
        RECT  0 4.176 0.084 4.2 ;
    END
  END rq[29]
  PIN rq[2]
    DIRECTION OUTPUT ;
    USE SIGNAL ;
    PORT
      LAYER M4 ;
        RECT  0 1.584 0.084 1.608 ;
    END
  END rq[2]
  PIN rq[30]
    DIRECTION OUTPUT ;
    USE SIGNAL ;
    PORT
      LAYER M4 ;
        RECT  0 4.272 0.084 4.296 ;
    END
  END rq[30]
  PIN rq[31]
    DIRECTION OUTPUT ;
    USE SIGNAL ;
    PORT
      LAYER M4 ;
        RECT  0 4.368 0.084 4.392 ;
    END
  END rq[31]
  PIN rq[32]
    DIRECTION OUTPUT ;
    USE SIGNAL ;
    PORT
      LAYER M4 ;
        RECT  0 4.464 0.084 4.488 ;
    END
  END rq[32]
  PIN rq[33]
    DIRECTION OUTPUT ;
    USE SIGNAL ;
    PORT
      LAYER M4 ;
        RECT  0 4.56 0.084 4.584 ;
    END
  END rq[33]
  PIN rq[34]
    DIRECTION OUTPUT ;
    USE SIGNAL ;
    PORT
      LAYER M4 ;
        RECT  0 4.656 0.084 4.68 ;
    END
  END rq[34]
  PIN rq[35]
    DIRECTION OUTPUT ;
    USE SIGNAL ;
    PORT
      LAYER M4 ;
        RECT  0 4.752 0.084 4.776 ;
    END
  END rq[35]
  PIN rq[36]
    DIRECTION OUTPUT ;
    USE SIGNAL ;
    PORT
      LAYER M4 ;
        RECT  0 4.848 0.084 4.872 ;
    END
  END rq[36]
  PIN rq[37]
    DIRECTION OUTPUT ;
    USE SIGNAL ;
    PORT
      LAYER M4 ;
        RECT  0 4.944 0.084 4.968 ;
    END
  END rq[37]
  PIN rq[38]
    DIRECTION OUTPUT ;
    USE SIGNAL ;
    PORT
      LAYER M4 ;
        RECT  0 5.04 0.084 5.064 ;
    END
  END rq[38]
  PIN rq[39]
    DIRECTION OUTPUT ;
    USE SIGNAL ;
    PORT
      LAYER M4 ;
        RECT  0 5.136 0.084 5.16 ;
    END
  END rq[39]
  PIN rq[3]
    DIRECTION OUTPUT ;
    USE SIGNAL ;
    PORT
      LAYER M4 ;
        RECT  0 1.68 0.084 1.704 ;
    END
  END rq[3]
  PIN rq[40]
    DIRECTION OUTPUT ;
    USE SIGNAL ;
    PORT
      LAYER M4 ;
        RECT  0 5.232 0.084 5.256 ;
    END
  END rq[40]
  PIN rq[41]
    DIRECTION OUTPUT ;
    USE SIGNAL ;
    PORT
      LAYER M4 ;
        RECT  0 5.328 0.084 5.352 ;
    END
  END rq[41]
  PIN rq[42]
    DIRECTION OUTPUT ;
    USE SIGNAL ;
    PORT
      LAYER M4 ;
        RECT  0 5.424 0.084 5.448 ;
    END
  END rq[42]
  PIN rq[43]
    DIRECTION OUTPUT ;
    USE SIGNAL ;
    PORT
      LAYER M4 ;
        RECT  0 5.52 0.084 5.544 ;
    END
  END rq[43]
  PIN rq[44]
    DIRECTION OUTPUT ;
    USE SIGNAL ;
    PORT
      LAYER M4 ;
        RECT  0 5.616 0.084 5.64 ;
    END
  END rq[44]
  PIN rq[45]
    DIRECTION OUTPUT ;
    USE SIGNAL ;
    PORT
      LAYER M4 ;
        RECT  0 5.712 0.084 5.736 ;
    END
  END rq[45]
  PIN rq[46]
    DIRECTION OUTPUT ;
    USE SIGNAL ;
    PORT
      LAYER M4 ;
        RECT  0 5.808 0.084 5.832 ;
    END
  END rq[46]
  PIN rq[47]
    DIRECTION OUTPUT ;
    USE SIGNAL ;
    PORT
      LAYER M4 ;
        RECT  0 5.904 0.084 5.928 ;
    END
  END rq[47]
  PIN rq[48]
    DIRECTION OUTPUT ;
    USE SIGNAL ;
    PORT
      LAYER M4 ;
        RECT  0 6 0.084 6.024 ;
    END
  END rq[48]
  PIN rq[49]
    DIRECTION OUTPUT ;
    USE SIGNAL ;
    PORT
      LAYER M4 ;
        RECT  0 6.096 0.084 6.12 ;
    END
  END rq[49]
  PIN rq[4]
    DIRECTION OUTPUT ;
    USE SIGNAL ;
    PORT
      LAYER M4 ;
        RECT  0 1.776 0.084 1.8 ;
    END
  END rq[4]
  PIN rq[50]
    DIRECTION OUTPUT ;
    USE SIGNAL ;
    PORT
      LAYER M4 ;
        RECT  0 6.192 0.084 6.216 ;
    END
  END rq[50]
  PIN rq[51]
    DIRECTION OUTPUT ;
    USE SIGNAL ;
    PORT
      LAYER M4 ;
        RECT  0 6.288 0.084 6.312 ;
    END
  END rq[51]
  PIN rq[52]
    DIRECTION OUTPUT ;
    USE SIGNAL ;
    PORT
      LAYER M4 ;
        RECT  0 6.384 0.084 6.408 ;
    END
  END rq[52]
  PIN rq[53]
    DIRECTION OUTPUT ;
    USE SIGNAL ;
    PORT
      LAYER M4 ;
        RECT  0 6.48 0.084 6.504 ;
    END
  END rq[53]
  PIN rq[54]
    DIRECTION OUTPUT ;
    USE SIGNAL ;
    PORT
      LAYER M4 ;
        RECT  0 6.576 0.084 6.6 ;
    END
  END rq[54]
  PIN rq[55]
    DIRECTION OUTPUT ;
    USE SIGNAL ;
    PORT
      LAYER M4 ;
        RECT  0 6.672 0.084 6.696 ;
    END
  END rq[55]
  PIN rq[56]
    DIRECTION OUTPUT ;
    USE SIGNAL ;
    PORT
      LAYER M4 ;
        RECT  0 6.768 0.084 6.792 ;
    END
  END rq[56]
  PIN rq[57]
    DIRECTION OUTPUT ;
    USE SIGNAL ;
    PORT
      LAYER M4 ;
        RECT  0 6.864 0.084 6.888 ;
    END
  END rq[57]
  PIN rq[58]
    DIRECTION OUTPUT ;
    USE SIGNAL ;
    PORT
      LAYER M4 ;
        RECT  0 6.96 0.084 6.984 ;
    END
  END rq[58]
  PIN rq[59]
    DIRECTION OUTPUT ;
    USE SIGNAL ;
    PORT
      LAYER M4 ;
        RECT  0 7.056 0.084 7.08 ;
    END
  END rq[59]
  PIN rq[5]
    DIRECTION OUTPUT ;
    USE SIGNAL ;
    PORT
      LAYER M4 ;
        RECT  0 1.872 0.084 1.896 ;
    END
  END rq[5]
  PIN rq[60]
    DIRECTION OUTPUT ;
    USE SIGNAL ;
    PORT
      LAYER M4 ;
        RECT  0 7.152 0.084 7.176 ;
    END
  END rq[60]
  PIN rq[61]
    DIRECTION OUTPUT ;
    USE SIGNAL ;
    PORT
      LAYER M4 ;
        RECT  0 7.248 0.084 7.272 ;
    END
  END rq[61]
  PIN rq[62]
    DIRECTION OUTPUT ;
    USE SIGNAL ;
    PORT
      LAYER M4 ;
        RECT  0 7.344 0.084 7.368 ;
    END
  END rq[62]
  PIN rq[63]
    DIRECTION OUTPUT ;
    USE SIGNAL ;
    PORT
      LAYER M4 ;
        RECT  0 7.44 0.084 7.464 ;
    END
  END rq[63]
  PIN rq[64]
    DIRECTION OUTPUT ;
    USE SIGNAL ;
    PORT
      LAYER M4 ;
        RECT  0 7.536 0.084 7.56 ;
    END
  END rq[64]
  PIN rq[65]
    DIRECTION OUTPUT ;
    USE SIGNAL ;
    PORT
      LAYER M4 ;
        RECT  0 7.632 0.084 7.656 ;
    END
  END rq[65]
  PIN rq[66]
    DIRECTION OUTPUT ;
    USE SIGNAL ;
    PORT
      LAYER M4 ;
        RECT  0 7.728 0.084 7.752 ;
    END
  END rq[66]
  PIN rq[67]
    DIRECTION OUTPUT ;
    USE SIGNAL ;
    PORT
      LAYER M4 ;
        RECT  0 7.824 0.084 7.848 ;
    END
  END rq[67]
  PIN rq[68]
    DIRECTION OUTPUT ;
    USE SIGNAL ;
    PORT
      LAYER M4 ;
        RECT  0 7.92 0.084 7.944 ;
    END
  END rq[68]
  PIN rq[69]
    DIRECTION OUTPUT ;
    USE SIGNAL ;
    PORT
      LAYER M4 ;
        RECT  0 8.016 0.084 8.04 ;
    END
  END rq[69]
  PIN rq[6]
    DIRECTION OUTPUT ;
    USE SIGNAL ;
    PORT
      LAYER M4 ;
        RECT  0 1.968 0.084 1.992 ;
    END
  END rq[6]
  PIN rq[70]
    DIRECTION OUTPUT ;
    USE SIGNAL ;
    PORT
      LAYER M4 ;
        RECT  0 8.112 0.084 8.136 ;
    END
  END rq[70]
  PIN rq[71]
    DIRECTION OUTPUT ;
    USE SIGNAL ;
    PORT
      LAYER M4 ;
        RECT  0 8.208 0.084 8.232 ;
    END
  END rq[71]
  PIN rq[72]
    DIRECTION OUTPUT ;
    USE SIGNAL ;
    PORT
      LAYER M4 ;
        RECT  0 8.304 0.084 8.328 ;
    END
  END rq[72]
  PIN rq[73]
    DIRECTION OUTPUT ;
    USE SIGNAL ;
    PORT
      LAYER M4 ;
        RECT  0 8.4 0.084 8.424 ;
    END
  END rq[73]
  PIN rq[74]
    DIRECTION OUTPUT ;
    USE SIGNAL ;
    PORT
      LAYER M4 ;
        RECT  0 8.496 0.084 8.52 ;
    END
  END rq[74]
  PIN rq[75]
    DIRECTION OUTPUT ;
    USE SIGNAL ;
    PORT
      LAYER M4 ;
        RECT  0 8.592 0.084 8.616 ;
    END
  END rq[75]
  PIN rq[76]
    DIRECTION OUTPUT ;
    USE SIGNAL ;
    PORT
      LAYER M4 ;
        RECT  0 8.688 0.084 8.712 ;
    END
  END rq[76]
  PIN rq[77]
    DIRECTION OUTPUT ;
    USE SIGNAL ;
    PORT
      LAYER M4 ;
        RECT  0 8.784 0.084 8.808 ;
    END
  END rq[77]
  PIN rq[78]
    DIRECTION OUTPUT ;
    USE SIGNAL ;
    PORT
      LAYER M4 ;
        RECT  0 8.88 0.084 8.904 ;
    END
  END rq[78]
  PIN rq[79]
    DIRECTION OUTPUT ;
    USE SIGNAL ;
    PORT
      LAYER M4 ;
        RECT  0 8.976 0.084 9 ;
    END
  END rq[79]
  PIN rq[7]
    DIRECTION OUTPUT ;
    USE SIGNAL ;
    PORT
      LAYER M4 ;
        RECT  0 2.064 0.084 2.088 ;
    END
  END rq[7]
  PIN rq[80]
    DIRECTION OUTPUT ;
    USE SIGNAL ;
    PORT
      LAYER M4 ;
        RECT  0 9.072 0.084 9.096 ;
    END
  END rq[80]
  PIN rq[81]
    DIRECTION OUTPUT ;
    USE SIGNAL ;
    PORT
      LAYER M4 ;
        RECT  0 9.168 0.084 9.192 ;
    END
  END rq[81]
  PIN rq[82]
    DIRECTION OUTPUT ;
    USE SIGNAL ;
    PORT
      LAYER M4 ;
        RECT  0 9.264 0.084 9.288 ;
    END
  END rq[82]
  PIN rq[83]
    DIRECTION OUTPUT ;
    USE SIGNAL ;
    PORT
      LAYER M4 ;
        RECT  0 9.36 0.084 9.384 ;
    END
  END rq[83]
  PIN rq[84]
    DIRECTION OUTPUT ;
    USE SIGNAL ;
    PORT
      LAYER M4 ;
        RECT  0 9.456 0.084 9.48 ;
    END
  END rq[84]
  PIN rq[85]
    DIRECTION OUTPUT ;
    USE SIGNAL ;
    PORT
      LAYER M4 ;
        RECT  0 9.552 0.084 9.576 ;
    END
  END rq[85]
  PIN rq[86]
    DIRECTION OUTPUT ;
    USE SIGNAL ;
    PORT
      LAYER M4 ;
        RECT  0 9.648 0.084 9.672 ;
    END
  END rq[86]
  PIN rq[87]
    DIRECTION OUTPUT ;
    USE SIGNAL ;
    PORT
      LAYER M4 ;
        RECT  0 9.744 0.084 9.768 ;
    END
  END rq[87]
  PIN rq[88]
    DIRECTION OUTPUT ;
    USE SIGNAL ;
    PORT
      LAYER M4 ;
        RECT  0 9.84 0.084 9.864 ;
    END
  END rq[88]
  PIN rq[89]
    DIRECTION OUTPUT ;
    USE SIGNAL ;
    PORT
      LAYER M4 ;
        RECT  0 9.936 0.084 9.96 ;
    END
  END rq[89]
  PIN rq[8]
    DIRECTION OUTPUT ;
    USE SIGNAL ;
    PORT
      LAYER M4 ;
        RECT  0 2.16 0.084 2.184 ;
    END
  END rq[8]
  PIN rq[90]
    DIRECTION OUTPUT ;
    USE SIGNAL ;
    PORT
      LAYER M4 ;
        RECT  0 10.032 0.084 10.056 ;
    END
  END rq[90]
  PIN rq[91]
    DIRECTION OUTPUT ;
    USE SIGNAL ;
    PORT
      LAYER M4 ;
        RECT  0 10.128 0.084 10.152 ;
    END
  END rq[91]
  PIN rq[92]
    DIRECTION OUTPUT ;
    USE SIGNAL ;
    PORT
      LAYER M4 ;
        RECT  0 10.224 0.084 10.248 ;
    END
  END rq[92]
  PIN rq[93]
    DIRECTION OUTPUT ;
    USE SIGNAL ;
    PORT
      LAYER M4 ;
        RECT  0 10.32 0.084 10.344 ;
    END
  END rq[93]
  PIN rq[94]
    DIRECTION OUTPUT ;
    USE SIGNAL ;
    PORT
      LAYER M4 ;
        RECT  0 10.416 0.084 10.44 ;
    END
  END rq[94]
  PIN rq[95]
    DIRECTION OUTPUT ;
    USE SIGNAL ;
    PORT
      LAYER M4 ;
        RECT  0 10.512 0.084 10.536 ;
    END
  END rq[95]
  PIN rq[96]
    DIRECTION OUTPUT ;
    USE SIGNAL ;
    PORT
      LAYER M4 ;
        RECT  0 10.608 0.084 10.632 ;
    END
  END rq[96]
  PIN rq[97]
    DIRECTION OUTPUT ;
    USE SIGNAL ;
    PORT
      LAYER M4 ;
        RECT  0 10.704 0.084 10.728 ;
    END
  END rq[97]
  PIN rq[98]
    DIRECTION OUTPUT ;
    USE SIGNAL ;
    PORT
      LAYER M4 ;
        RECT  0 11.568 0.084 11.592 ;
    END
  END rq[98]
  PIN rq[99]
    DIRECTION OUTPUT ;
    USE SIGNAL ;
    PORT
      LAYER M4 ;
        RECT  0 11.664 0.084 11.688 ;
    END
  END rq[99]
  PIN rq[9]
    DIRECTION OUTPUT ;
    USE SIGNAL ;
    PORT
      LAYER M4 ;
        RECT  0 2.256 0.084 2.28 ;
    END
  END rq[9]
  PIN rr_valid_i[0]
    DIRECTION INPUT ;
    USE SIGNAL ;
    PORT
      LAYER M4 ;
        RECT  0 42.288 0.084 42.312 ;
    END
  END rr_valid_i[0]
  PIN rr_valid_i[1]
    DIRECTION INPUT ;
    USE SIGNAL ;
    PORT
      LAYER M4 ;
        RECT  0 42.384 0.084 42.408 ;
    END
  END rr_valid_i[1]
  PIN rr_valid_i[2]
    DIRECTION INPUT ;
    USE SIGNAL ;
    PORT
      LAYER M4 ;
        RECT  0 42.48 0.084 42.504 ;
    END
  END rr_valid_i[2]
  PIN rr_valid_i[3]
    DIRECTION INPUT ;
    USE SIGNAL ;
    PORT
      LAYER M4 ;
        RECT  0 42.576 0.084 42.6 ;
    END
  END rr_valid_i[3]
  PIN rr_valid_i[4]
    DIRECTION INPUT ;
    USE SIGNAL ;
    PORT
      LAYER M4 ;
        RECT  0 42.672 0.084 42.696 ;
    END
  END rr_valid_i[4]
  PIN rr_valid_i[5]
    DIRECTION INPUT ;
    USE SIGNAL ;
    PORT
      LAYER M4 ;
        RECT  0 42.768 0.084 42.792 ;
    END
  END rr_valid_i[5]
  PIN rr_valid_i[6]
    DIRECTION INPUT ;
    USE SIGNAL ;
    PORT
      LAYER M4 ;
        RECT  0 42.864 0.084 42.888 ;
    END
  END rr_valid_i[6]
  PIN rr_valid_i[7]
    DIRECTION INPUT ;
    USE SIGNAL ;
    PORT
      LAYER M4 ;
        RECT  0 42.96 0.084 42.984 ;
    END
  END rr_valid_i[7]
  PIN rst_n
    DIRECTION INPUT ;
    USE SIGNAL ;
    PORT
      LAYER M4 ;
        RECT  69.036 63.984 69.12 64.008 ;
    END
  END rst_n
  PIN stk[0]
    DIRECTION INPUT ;
    USE SIGNAL ;
    PORT
      LAYER M4 ;
        RECT  69.036 64.08 69.12 64.104 ;
    END
  END stk[0]
  PIN stk[1]
    DIRECTION INPUT ;
    USE SIGNAL ;
    PORT
      LAYER M4 ;
        RECT  69.036 64.176 69.12 64.2 ;
    END
  END stk[1]
  PIN wa[0]
    DIRECTION INPUT ;
    USE SIGNAL ;
    PORT
      LAYER M5 ;
        RECT  56.112 69.036 56.136 69.12 ;
    END
  END wa[0]
  PIN wa[10]
    DIRECTION INPUT ;
    USE SIGNAL ;
    PORT
      LAYER M5 ;
        RECT  57.072 69.036 57.096 69.12 ;
    END
  END wa[10]
  PIN wa[11]
    DIRECTION INPUT ;
    USE SIGNAL ;
    PORT
      LAYER M5 ;
        RECT  57.168 69.036 57.192 69.12 ;
    END
  END wa[11]
  PIN wa[1]
    DIRECTION INPUT ;
    USE SIGNAL ;
    PORT
      LAYER M5 ;
        RECT  56.208 69.036 56.232 69.12 ;
    END
  END wa[1]
  PIN wa[2]
    DIRECTION INPUT ;
    USE SIGNAL ;
    PORT
      LAYER M5 ;
        RECT  56.304 69.036 56.328 69.12 ;
    END
  END wa[2]
  PIN wa[3]
    DIRECTION INPUT ;
    USE SIGNAL ;
    PORT
      LAYER M5 ;
        RECT  56.4 69.036 56.424 69.12 ;
    END
  END wa[3]
  PIN wa[4]
    DIRECTION INPUT ;
    USE SIGNAL ;
    PORT
      LAYER M5 ;
        RECT  56.496 69.036 56.52 69.12 ;
    END
  END wa[4]
  PIN wa[5]
    DIRECTION INPUT ;
    USE SIGNAL ;
    PORT
      LAYER M5 ;
        RECT  56.592 69.036 56.616 69.12 ;
    END
  END wa[5]
  PIN wa[6]
    DIRECTION INPUT ;
    USE SIGNAL ;
    PORT
      LAYER M5 ;
        RECT  56.688 69.036 56.712 69.12 ;
    END
  END wa[6]
  PIN wa[7]
    DIRECTION INPUT ;
    USE SIGNAL ;
    PORT
      LAYER M5 ;
        RECT  56.784 69.036 56.808 69.12 ;
    END
  END wa[7]
  PIN wa[8]
    DIRECTION INPUT ;
    USE SIGNAL ;
    PORT
      LAYER M5 ;
        RECT  56.88 69.036 56.904 69.12 ;
    END
  END wa[8]
  PIN wa[9]
    DIRECTION INPUT ;
    USE SIGNAL ;
    PORT
      LAYER M5 ;
        RECT  56.976 69.036 57 69.12 ;
    END
  END wa[9]
  PIN wb_fill_bank
    DIRECTION OUTPUT ;
    USE SIGNAL ;
    PORT
      LAYER M5 ;
        RECT  57.264 69.036 57.288 69.12 ;
    END
  END wb_fill_bank
  PIN wb_fill_epoch[0]
    DIRECTION OUTPUT ;
    USE SIGNAL ;
    PORT
      LAYER M5 ;
        RECT  57.36 69.036 57.384 69.12 ;
    END
  END wb_fill_epoch[0]
  PIN wb_fill_epoch[10]
    DIRECTION OUTPUT ;
    USE SIGNAL ;
    PORT
      LAYER M5 ;
        RECT  58.32 69.036 58.344 69.12 ;
    END
  END wb_fill_epoch[10]
  PIN wb_fill_epoch[11]
    DIRECTION OUTPUT ;
    USE SIGNAL ;
    PORT
      LAYER M5 ;
        RECT  58.416 69.036 58.44 69.12 ;
    END
  END wb_fill_epoch[11]
  PIN wb_fill_epoch[12]
    DIRECTION OUTPUT ;
    USE SIGNAL ;
    PORT
      LAYER M5 ;
        RECT  58.512 69.036 58.536 69.12 ;
    END
  END wb_fill_epoch[12]
  PIN wb_fill_epoch[13]
    DIRECTION OUTPUT ;
    USE SIGNAL ;
    PORT
      LAYER M5 ;
        RECT  58.608 69.036 58.632 69.12 ;
    END
  END wb_fill_epoch[13]
  PIN wb_fill_epoch[14]
    DIRECTION OUTPUT ;
    USE SIGNAL ;
    PORT
      LAYER M5 ;
        RECT  58.704 69.036 58.728 69.12 ;
    END
  END wb_fill_epoch[14]
  PIN wb_fill_epoch[15]
    DIRECTION OUTPUT ;
    USE SIGNAL ;
    PORT
      LAYER M5 ;
        RECT  58.8 69.036 58.824 69.12 ;
    END
  END wb_fill_epoch[15]
  PIN wb_fill_epoch[1]
    DIRECTION OUTPUT ;
    USE SIGNAL ;
    PORT
      LAYER M5 ;
        RECT  57.456 69.036 57.48 69.12 ;
    END
  END wb_fill_epoch[1]
  PIN wb_fill_epoch[2]
    DIRECTION OUTPUT ;
    USE SIGNAL ;
    PORT
      LAYER M5 ;
        RECT  57.552 69.036 57.576 69.12 ;
    END
  END wb_fill_epoch[2]
  PIN wb_fill_epoch[3]
    DIRECTION OUTPUT ;
    USE SIGNAL ;
    PORT
      LAYER M5 ;
        RECT  57.648 69.036 57.672 69.12 ;
    END
  END wb_fill_epoch[3]
  PIN wb_fill_epoch[4]
    DIRECTION OUTPUT ;
    USE SIGNAL ;
    PORT
      LAYER M5 ;
        RECT  57.744 69.036 57.768 69.12 ;
    END
  END wb_fill_epoch[4]
  PIN wb_fill_epoch[5]
    DIRECTION OUTPUT ;
    USE SIGNAL ;
    PORT
      LAYER M5 ;
        RECT  57.84 69.036 57.864 69.12 ;
    END
  END wb_fill_epoch[5]
  PIN wb_fill_epoch[6]
    DIRECTION OUTPUT ;
    USE SIGNAL ;
    PORT
      LAYER M5 ;
        RECT  57.936 69.036 57.96 69.12 ;
    END
  END wb_fill_epoch[6]
  PIN wb_fill_epoch[7]
    DIRECTION OUTPUT ;
    USE SIGNAL ;
    PORT
      LAYER M5 ;
        RECT  58.032 69.036 58.056 69.12 ;
    END
  END wb_fill_epoch[7]
  PIN wb_fill_epoch[8]
    DIRECTION OUTPUT ;
    USE SIGNAL ;
    PORT
      LAYER M5 ;
        RECT  58.128 69.036 58.152 69.12 ;
    END
  END wb_fill_epoch[8]
  PIN wb_fill_epoch[9]
    DIRECTION OUTPUT ;
    USE SIGNAL ;
    PORT
      LAYER M5 ;
        RECT  58.224 69.036 58.248 69.12 ;
    END
  END wb_fill_epoch[9]
  PIN wb_fill_start
    DIRECTION OUTPUT ;
    USE SIGNAL ;
    PORT
      LAYER M5 ;
        RECT  58.896 69.036 58.92 69.12 ;
    END
  END wb_fill_start
  PIN wb_ready
    DIRECTION INPUT ;
    USE SIGNAL ;
    PORT
      LAYER M5 ;
        RECT  58.992 69.036 59.016 69.12 ;
    END
  END wb_ready
  PIN wb_reserve_bank
    DIRECTION OUTPUT ;
    USE SIGNAL ;
    PORT
      LAYER M5 ;
        RECT  59.088 69.036 59.112 69.12 ;
    END
  END wb_reserve_bank
  PIN wb_reserve_base[0]
    DIRECTION OUTPUT ;
    USE SIGNAL ;
    PORT
      LAYER M5 ;
        RECT  49.968 69.036 49.992 69.12 ;
    END
  END wb_reserve_base[0]
  PIN wb_reserve_base[10]
    DIRECTION OUTPUT ;
    USE SIGNAL ;
    PORT
      LAYER M5 ;
        RECT  50.928 69.036 50.952 69.12 ;
    END
  END wb_reserve_base[10]
  PIN wb_reserve_base[11]
    DIRECTION OUTPUT ;
    USE SIGNAL ;
    PORT
      LAYER M5 ;
        RECT  51.024 69.036 51.048 69.12 ;
    END
  END wb_reserve_base[11]
  PIN wb_reserve_base[12]
    DIRECTION OUTPUT ;
    USE SIGNAL ;
    PORT
      LAYER M5 ;
        RECT  51.12 69.036 51.144 69.12 ;
    END
  END wb_reserve_base[12]
  PIN wb_reserve_base[13]
    DIRECTION OUTPUT ;
    USE SIGNAL ;
    PORT
      LAYER M5 ;
        RECT  51.216 69.036 51.24 69.12 ;
    END
  END wb_reserve_base[13]
  PIN wb_reserve_base[14]
    DIRECTION OUTPUT ;
    USE SIGNAL ;
    PORT
      LAYER M5 ;
        RECT  51.312 69.036 51.336 69.12 ;
    END
  END wb_reserve_base[14]
  PIN wb_reserve_base[15]
    DIRECTION OUTPUT ;
    USE SIGNAL ;
    PORT
      LAYER M5 ;
        RECT  51.408 69.036 51.432 69.12 ;
    END
  END wb_reserve_base[15]
  PIN wb_reserve_base[16]
    DIRECTION OUTPUT ;
    USE SIGNAL ;
    PORT
      LAYER M5 ;
        RECT  51.504 69.036 51.528 69.12 ;
    END
  END wb_reserve_base[16]
  PIN wb_reserve_base[17]
    DIRECTION OUTPUT ;
    USE SIGNAL ;
    PORT
      LAYER M5 ;
        RECT  51.6 69.036 51.624 69.12 ;
    END
  END wb_reserve_base[17]
  PIN wb_reserve_base[18]
    DIRECTION OUTPUT ;
    USE SIGNAL ;
    PORT
      LAYER M5 ;
        RECT  51.696 69.036 51.72 69.12 ;
    END
  END wb_reserve_base[18]
  PIN wb_reserve_base[19]
    DIRECTION OUTPUT ;
    USE SIGNAL ;
    PORT
      LAYER M5 ;
        RECT  51.792 69.036 51.816 69.12 ;
    END
  END wb_reserve_base[19]
  PIN wb_reserve_base[1]
    DIRECTION OUTPUT ;
    USE SIGNAL ;
    PORT
      LAYER M5 ;
        RECT  50.064 69.036 50.088 69.12 ;
    END
  END wb_reserve_base[1]
  PIN wb_reserve_base[20]
    DIRECTION OUTPUT ;
    USE SIGNAL ;
    PORT
      LAYER M5 ;
        RECT  51.888 69.036 51.912 69.12 ;
    END
  END wb_reserve_base[20]
  PIN wb_reserve_base[21]
    DIRECTION OUTPUT ;
    USE SIGNAL ;
    PORT
      LAYER M5 ;
        RECT  51.984 69.036 52.008 69.12 ;
    END
  END wb_reserve_base[21]
  PIN wb_reserve_base[22]
    DIRECTION OUTPUT ;
    USE SIGNAL ;
    PORT
      LAYER M5 ;
        RECT  52.08 69.036 52.104 69.12 ;
    END
  END wb_reserve_base[22]
  PIN wb_reserve_base[23]
    DIRECTION OUTPUT ;
    USE SIGNAL ;
    PORT
      LAYER M5 ;
        RECT  52.176 69.036 52.2 69.12 ;
    END
  END wb_reserve_base[23]
  PIN wb_reserve_base[24]
    DIRECTION OUTPUT ;
    USE SIGNAL ;
    PORT
      LAYER M5 ;
        RECT  52.272 69.036 52.296 69.12 ;
    END
  END wb_reserve_base[24]
  PIN wb_reserve_base[25]
    DIRECTION OUTPUT ;
    USE SIGNAL ;
    PORT
      LAYER M5 ;
        RECT  52.368 69.036 52.392 69.12 ;
    END
  END wb_reserve_base[25]
  PIN wb_reserve_base[26]
    DIRECTION OUTPUT ;
    USE SIGNAL ;
    PORT
      LAYER M5 ;
        RECT  52.464 69.036 52.488 69.12 ;
    END
  END wb_reserve_base[26]
  PIN wb_reserve_base[27]
    DIRECTION OUTPUT ;
    USE SIGNAL ;
    PORT
      LAYER M5 ;
        RECT  52.56 69.036 52.584 69.12 ;
    END
  END wb_reserve_base[27]
  PIN wb_reserve_base[28]
    DIRECTION OUTPUT ;
    USE SIGNAL ;
    PORT
      LAYER M5 ;
        RECT  52.656 69.036 52.68 69.12 ;
    END
  END wb_reserve_base[28]
  PIN wb_reserve_base[29]
    DIRECTION OUTPUT ;
    USE SIGNAL ;
    PORT
      LAYER M5 ;
        RECT  52.752 69.036 52.776 69.12 ;
    END
  END wb_reserve_base[29]
  PIN wb_reserve_base[2]
    DIRECTION OUTPUT ;
    USE SIGNAL ;
    PORT
      LAYER M5 ;
        RECT  50.16 69.036 50.184 69.12 ;
    END
  END wb_reserve_base[2]
  PIN wb_reserve_base[30]
    DIRECTION OUTPUT ;
    USE SIGNAL ;
    PORT
      LAYER M5 ;
        RECT  52.848 69.036 52.872 69.12 ;
    END
  END wb_reserve_base[30]
  PIN wb_reserve_base[31]
    DIRECTION OUTPUT ;
    USE SIGNAL ;
    PORT
      LAYER M5 ;
        RECT  52.944 69.036 52.968 69.12 ;
    END
  END wb_reserve_base[31]
  PIN wb_reserve_base[3]
    DIRECTION OUTPUT ;
    USE SIGNAL ;
    PORT
      LAYER M5 ;
        RECT  50.256 69.036 50.28 69.12 ;
    END
  END wb_reserve_base[3]
  PIN wb_reserve_base[4]
    DIRECTION OUTPUT ;
    USE SIGNAL ;
    PORT
      LAYER M5 ;
        RECT  50.352 69.036 50.376 69.12 ;
    END
  END wb_reserve_base[4]
  PIN wb_reserve_base[5]
    DIRECTION OUTPUT ;
    USE SIGNAL ;
    PORT
      LAYER M5 ;
        RECT  50.448 69.036 50.472 69.12 ;
    END
  END wb_reserve_base[5]
  PIN wb_reserve_base[6]
    DIRECTION OUTPUT ;
    USE SIGNAL ;
    PORT
      LAYER M5 ;
        RECT  50.544 69.036 50.568 69.12 ;
    END
  END wb_reserve_base[6]
  PIN wb_reserve_base[7]
    DIRECTION OUTPUT ;
    USE SIGNAL ;
    PORT
      LAYER M5 ;
        RECT  50.64 69.036 50.664 69.12 ;
    END
  END wb_reserve_base[7]
  PIN wb_reserve_base[8]
    DIRECTION OUTPUT ;
    USE SIGNAL ;
    PORT
      LAYER M5 ;
        RECT  50.736 69.036 50.76 69.12 ;
    END
  END wb_reserve_base[8]
  PIN wb_reserve_base[9]
    DIRECTION OUTPUT ;
    USE SIGNAL ;
    PORT
      LAYER M5 ;
        RECT  50.832 69.036 50.856 69.12 ;
    END
  END wb_reserve_base[9]
  PIN wb_reserve_epoch[0]
    DIRECTION OUTPUT ;
    USE SIGNAL ;
    PORT
      LAYER M5 ;
        RECT  59.472 69.036 59.496 69.12 ;
    END
  END wb_reserve_epoch[0]
  PIN wb_reserve_epoch[10]
    DIRECTION OUTPUT ;
    USE SIGNAL ;
    PORT
      LAYER M5 ;
        RECT  60.432 69.036 60.456 69.12 ;
    END
  END wb_reserve_epoch[10]
  PIN wb_reserve_epoch[11]
    DIRECTION OUTPUT ;
    USE SIGNAL ;
    PORT
      LAYER M5 ;
        RECT  60.528 69.036 60.552 69.12 ;
    END
  END wb_reserve_epoch[11]
  PIN wb_reserve_epoch[12]
    DIRECTION OUTPUT ;
    USE SIGNAL ;
    PORT
      LAYER M5 ;
        RECT  60.624 69.036 60.648 69.12 ;
    END
  END wb_reserve_epoch[12]
  PIN wb_reserve_epoch[13]
    DIRECTION OUTPUT ;
    USE SIGNAL ;
    PORT
      LAYER M5 ;
        RECT  60.72 69.036 60.744 69.12 ;
    END
  END wb_reserve_epoch[13]
  PIN wb_reserve_epoch[14]
    DIRECTION OUTPUT ;
    USE SIGNAL ;
    PORT
      LAYER M5 ;
        RECT  60.816 69.036 60.84 69.12 ;
    END
  END wb_reserve_epoch[14]
  PIN wb_reserve_epoch[15]
    DIRECTION OUTPUT ;
    USE SIGNAL ;
    PORT
      LAYER M5 ;
        RECT  60.912 69.036 60.936 69.12 ;
    END
  END wb_reserve_epoch[15]
  PIN wb_reserve_epoch[1]
    DIRECTION OUTPUT ;
    USE SIGNAL ;
    PORT
      LAYER M5 ;
        RECT  59.568 69.036 59.592 69.12 ;
    END
  END wb_reserve_epoch[1]
  PIN wb_reserve_epoch[2]
    DIRECTION OUTPUT ;
    USE SIGNAL ;
    PORT
      LAYER M5 ;
        RECT  59.664 69.036 59.688 69.12 ;
    END
  END wb_reserve_epoch[2]
  PIN wb_reserve_epoch[3]
    DIRECTION OUTPUT ;
    USE SIGNAL ;
    PORT
      LAYER M5 ;
        RECT  59.76 69.036 59.784 69.12 ;
    END
  END wb_reserve_epoch[3]
  PIN wb_reserve_epoch[4]
    DIRECTION OUTPUT ;
    USE SIGNAL ;
    PORT
      LAYER M5 ;
        RECT  59.856 69.036 59.88 69.12 ;
    END
  END wb_reserve_epoch[4]
  PIN wb_reserve_epoch[5]
    DIRECTION OUTPUT ;
    USE SIGNAL ;
    PORT
      LAYER M5 ;
        RECT  59.952 69.036 59.976 69.12 ;
    END
  END wb_reserve_epoch[5]
  PIN wb_reserve_epoch[6]
    DIRECTION OUTPUT ;
    USE SIGNAL ;
    PORT
      LAYER M5 ;
        RECT  60.048 69.036 60.072 69.12 ;
    END
  END wb_reserve_epoch[6]
  PIN wb_reserve_epoch[7]
    DIRECTION OUTPUT ;
    USE SIGNAL ;
    PORT
      LAYER M5 ;
        RECT  60.144 69.036 60.168 69.12 ;
    END
  END wb_reserve_epoch[7]
  PIN wb_reserve_epoch[8]
    DIRECTION OUTPUT ;
    USE SIGNAL ;
    PORT
      LAYER M5 ;
        RECT  60.24 69.036 60.264 69.12 ;
    END
  END wb_reserve_epoch[8]
  PIN wb_reserve_epoch[9]
    DIRECTION OUTPUT ;
    USE SIGNAL ;
    PORT
      LAYER M5 ;
        RECT  60.336 69.036 60.36 69.12 ;
    END
  END wb_reserve_epoch[9]
  PIN wb_reserve_sectors[0]
    DIRECTION OUTPUT ;
    USE SIGNAL ;
    PORT
      LAYER M5 ;
        RECT  61.008 69.036 61.032 69.12 ;
    END
  END wb_reserve_sectors[0]
  PIN wb_reserve_sectors[10]
    DIRECTION OUTPUT ;
    USE SIGNAL ;
    PORT
      LAYER M5 ;
        RECT  61.968 69.036 61.992 69.12 ;
    END
  END wb_reserve_sectors[10]
  PIN wb_reserve_sectors[11]
    DIRECTION OUTPUT ;
    USE SIGNAL ;
    PORT
      LAYER M5 ;
        RECT  62.064 69.036 62.088 69.12 ;
    END
  END wb_reserve_sectors[11]
  PIN wb_reserve_sectors[1]
    DIRECTION OUTPUT ;
    USE SIGNAL ;
    PORT
      LAYER M5 ;
        RECT  61.104 69.036 61.128 69.12 ;
    END
  END wb_reserve_sectors[1]
  PIN wb_reserve_sectors[2]
    DIRECTION OUTPUT ;
    USE SIGNAL ;
    PORT
      LAYER M5 ;
        RECT  61.2 69.036 61.224 69.12 ;
    END
  END wb_reserve_sectors[2]
  PIN wb_reserve_sectors[3]
    DIRECTION OUTPUT ;
    USE SIGNAL ;
    PORT
      LAYER M5 ;
        RECT  61.296 69.036 61.32 69.12 ;
    END
  END wb_reserve_sectors[3]
  PIN wb_reserve_sectors[4]
    DIRECTION OUTPUT ;
    USE SIGNAL ;
    PORT
      LAYER M5 ;
        RECT  61.392 69.036 61.416 69.12 ;
    END
  END wb_reserve_sectors[4]
  PIN wb_reserve_sectors[5]
    DIRECTION OUTPUT ;
    USE SIGNAL ;
    PORT
      LAYER M5 ;
        RECT  61.488 69.036 61.512 69.12 ;
    END
  END wb_reserve_sectors[5]
  PIN wb_reserve_sectors[6]
    DIRECTION OUTPUT ;
    USE SIGNAL ;
    PORT
      LAYER M5 ;
        RECT  61.584 69.036 61.608 69.12 ;
    END
  END wb_reserve_sectors[6]
  PIN wb_reserve_sectors[7]
    DIRECTION OUTPUT ;
    USE SIGNAL ;
    PORT
      LAYER M5 ;
        RECT  61.68 69.036 61.704 69.12 ;
    END
  END wb_reserve_sectors[7]
  PIN wb_reserve_sectors[8]
    DIRECTION OUTPUT ;
    USE SIGNAL ;
    PORT
      LAYER M5 ;
        RECT  61.776 69.036 61.8 69.12 ;
    END
  END wb_reserve_sectors[8]
  PIN wb_reserve_sectors[9]
    DIRECTION OUTPUT ;
    USE SIGNAL ;
    PORT
      LAYER M5 ;
        RECT  61.872 69.036 61.896 69.12 ;
    END
  END wb_reserve_sectors[9]
  PIN wb_reserve_v
    DIRECTION OUTPUT ;
    USE SIGNAL ;
    PORT
      LAYER M5 ;
        RECT  62.16 69.036 62.184 69.12 ;
    END
  END wb_reserve_v
  PIN VDD
    DIRECTION INOUT ;
    USE POWER ;
    PORT
      LAYER M5 ;
        RECT  61.992 2.151 62.112 66.969 ;
        RECT  56.592 2.151 56.712 66.969 ;
        RECT  51.192 2.151 51.312 66.969 ;
        RECT  45.792 2.151 45.912 66.969 ;
        RECT  40.392 2.151 40.512 66.969 ;
        RECT  34.992 2.151 35.112 66.969 ;
        RECT  29.592 2.151 29.712 66.969 ;
        RECT  24.192 2.151 24.312 66.969 ;
        RECT  18.792 2.151 18.912 66.969 ;
        RECT  13.392 2.151 13.512 66.969 ;
        RECT  7.992 2.151 8.112 66.969 ;
        RECT  2.592 2.151 2.712 66.969 ;
    END
  END VDD
  PIN VSS
    DIRECTION INOUT ;
    USE GROUND ;
    PORT
      LAYER M5 ;
        RECT  61.8 2.137 61.92 66.983 ;
        RECT  56.4 2.137 56.52 66.983 ;
        RECT  51 2.137 51.12 66.983 ;
        RECT  45.6 2.137 45.72 66.983 ;
        RECT  40.2 2.137 40.32 66.983 ;
        RECT  34.8 2.137 34.92 66.983 ;
        RECT  29.4 2.137 29.52 66.983 ;
        RECT  24 2.137 24.12 66.983 ;
        RECT  18.6 2.137 18.72 66.983 ;
        RECT  13.2 2.137 13.32 66.983 ;
        RECT  7.8 2.137 7.92 66.983 ;
        RECT  2.4 2.137 2.52 66.983 ;
    END
  END VSS
  # OT_OBS_CLOSED layer=M5 d_um=1.536 added=396
  OBS
    LAYER RVTN ;
     RECT  2.16 2.16 66.96 2.295 ;
     RECT  2.16 2.565 66.96 2.835 ;
     RECT  2.16 3.105 66.96 3.375 ;
     RECT  2.16 3.645 66.96 3.915 ;
     RECT  2.16 4.185 66.96 4.455 ;
     RECT  2.16 4.725 66.96 4.995 ;
     RECT  2.16 5.265 66.96 5.535 ;
     RECT  2.16 5.805 66.96 6.075 ;
     RECT  2.16 6.345 66.96 6.615 ;
     RECT  2.16 6.885 66.96 7.155 ;
     RECT  2.16 7.425 66.96 7.695 ;
     RECT  2.16 7.965 66.96 8.235 ;
     RECT  2.16 8.505 66.96 8.775 ;
     RECT  2.16 9.045 66.96 9.315 ;
     RECT  2.16 9.585 66.96 9.855 ;
     RECT  2.16 10.125 66.96 10.395 ;
     RECT  2.16 10.665 66.96 10.935 ;
     RECT  2.16 11.205 66.96 11.475 ;
     RECT  2.16 11.745 66.96 12.015 ;
     RECT  2.16 12.285 66.96 12.555 ;
     RECT  2.16 12.825 66.96 13.095 ;
     RECT  2.16 13.365 66.96 13.635 ;
     RECT  2.16 13.905 66.96 14.175 ;
     RECT  2.16 14.445 66.96 14.715 ;
     RECT  2.16 14.985 66.96 15.255 ;
     RECT  2.16 15.525 66.96 15.795 ;
     RECT  2.16 16.065 66.96 16.335 ;
     RECT  2.16 16.605 66.96 16.875 ;
     RECT  2.16 17.145 66.96 17.415 ;
     RECT  2.16 17.685 66.96 17.955 ;
     RECT  2.16 18.225 66.96 18.495 ;
     RECT  2.16 18.765 66.96 19.035 ;
     RECT  2.16 19.305 66.96 19.575 ;
     RECT  2.16 19.845 66.96 20.115 ;
     RECT  2.16 20.385 66.96 20.655 ;
     RECT  2.16 20.925 66.96 21.195 ;
     RECT  2.16 21.465 66.96 21.735 ;
     RECT  2.16 22.005 66.96 22.275 ;
     RECT  2.16 22.545 66.96 22.815 ;
     RECT  2.16 23.085 66.96 23.355 ;
     RECT  2.16 23.625 66.96 23.895 ;
     RECT  2.16 24.165 66.96 24.435 ;
     RECT  2.16 24.705 66.96 24.975 ;
     RECT  2.16 25.245 66.96 25.515 ;
     RECT  2.16 25.785 66.96 26.055 ;
     RECT  2.16 26.325 66.96 26.595 ;
     RECT  2.16 26.865 66.96 27.135 ;
     RECT  2.16 27.405 66.96 27.675 ;
     RECT  2.16 27.945 66.96 28.215 ;
     RECT  2.16 28.485 66.96 28.755 ;
     RECT  2.16 29.025 66.96 29.295 ;
     RECT  2.16 29.565 66.96 29.835 ;
     RECT  2.16 30.105 66.96 30.375 ;
     RECT  2.16 30.645 66.96 30.915 ;
     RECT  2.16 31.185 66.96 31.455 ;
     RECT  2.16 31.725 66.96 31.995 ;
     RECT  2.16 32.265 66.96 32.535 ;
     RECT  2.16 32.805 66.96 33.075 ;
     RECT  2.16 33.345 66.96 33.615 ;
     RECT  2.16 33.885 66.96 34.155 ;
     RECT  2.16 34.425 66.96 34.695 ;
     RECT  2.16 34.965 66.96 35.235 ;
     RECT  2.16 35.505 66.96 35.775 ;
     RECT  2.16 36.045 66.96 36.315 ;
     RECT  2.16 36.585 66.96 36.855 ;
     RECT  2.16 37.125 66.96 37.395 ;
     RECT  2.16 37.665 66.96 37.935 ;
     RECT  2.16 38.205 66.96 38.475 ;
     RECT  2.16 38.745 66.96 39.015 ;
     RECT  2.16 39.285 66.96 39.555 ;
     RECT  2.16 39.825 66.96 40.095 ;
     RECT  2.16 40.365 66.96 40.635 ;
     RECT  2.16 40.905 66.96 41.175 ;
     RECT  2.16 41.445 66.96 41.715 ;
     RECT  2.16 41.985 66.96 42.255 ;
     RECT  2.16 42.525 66.96 42.795 ;
     RECT  2.16 43.065 66.96 43.335 ;
     RECT  2.16 43.605 66.96 43.875 ;
     RECT  2.16 44.145 66.96 44.415 ;
     RECT  2.16 44.685 66.96 44.955 ;
     RECT  2.16 45.225 66.96 45.495 ;
     RECT  2.16 45.765 66.96 46.035 ;
     RECT  2.16 46.305 66.96 46.575 ;
     RECT  2.16 46.845 66.96 47.115 ;
     RECT  2.16 47.385 66.96 47.655 ;
     RECT  2.16 47.925 66.96 48.195 ;
     RECT  2.16 48.465 66.96 48.735 ;
     RECT  2.16 49.005 66.96 49.275 ;
     RECT  2.16 49.545 66.96 49.815 ;
     RECT  2.16 50.085 66.96 50.355 ;
     RECT  2.16 50.625 66.96 50.895 ;
     RECT  2.16 51.165 66.96 51.435 ;
     RECT  2.16 51.705 66.96 51.975 ;
     RECT  2.16 52.245 66.96 52.515 ;
     RECT  2.16 52.785 66.96 53.055 ;
     RECT  2.16 53.325 66.96 53.595 ;
     RECT  2.16 53.865 66.96 54.135 ;
     RECT  2.16 54.405 66.96 54.675 ;
     RECT  2.16 54.945 66.96 55.215 ;
     RECT  2.16 55.485 66.96 55.755 ;
     RECT  2.16 56.025 66.96 56.295 ;
     RECT  2.16 56.565 66.96 56.835 ;
     RECT  2.16 57.105 66.96 57.375 ;
     RECT  2.16 57.645 66.96 57.915 ;
     RECT  2.16 58.185 66.96 58.455 ;
     RECT  2.16 58.725 66.96 58.995 ;
     RECT  2.16 59.265 66.96 59.535 ;
     RECT  2.16 59.805 66.96 60.075 ;
     RECT  2.16 60.345 66.96 60.615 ;
     RECT  2.16 60.885 66.96 61.155 ;
     RECT  2.16 61.425 66.96 61.695 ;
     RECT  2.16 61.965 66.96 62.235 ;
     RECT  2.16 62.505 66.96 62.775 ;
     RECT  2.16 63.045 66.96 63.315 ;
     RECT  2.16 63.585 66.96 63.855 ;
     RECT  2.16 64.125 66.96 64.395 ;
     RECT  2.16 64.665 66.96 64.935 ;
     RECT  2.16 65.205 66.96 65.475 ;
     RECT  2.16 65.745 66.96 66.015 ;
     RECT  2.16 66.285 66.96 66.555 ;
     RECT  2.16 66.825 66.96 66.96 ;
    LAYER RVTP ;
     RECT  2.16 2.295 66.96 2.565 ;
     RECT  2.16 2.835 66.96 3.105 ;
     RECT  2.16 3.375 66.96 3.645 ;
     RECT  2.16 3.915 66.96 4.185 ;
     RECT  2.16 4.455 66.96 4.725 ;
     RECT  2.16 4.995 66.96 5.265 ;
     RECT  2.16 5.535 66.96 5.805 ;
     RECT  2.16 6.075 66.96 6.345 ;
     RECT  2.16 6.615 66.96 6.885 ;
     RECT  2.16 7.155 66.96 7.425 ;
     RECT  2.16 7.695 66.96 7.965 ;
     RECT  2.16 8.235 66.96 8.505 ;
     RECT  2.16 8.775 66.96 9.045 ;
     RECT  2.16 9.315 66.96 9.585 ;
     RECT  2.16 9.855 66.96 10.125 ;
     RECT  2.16 10.395 66.96 10.665 ;
     RECT  2.16 10.935 66.96 11.205 ;
     RECT  2.16 11.475 66.96 11.745 ;
     RECT  2.16 12.015 66.96 12.285 ;
     RECT  2.16 12.555 66.96 12.825 ;
     RECT  2.16 13.095 66.96 13.365 ;
     RECT  2.16 13.635 66.96 13.905 ;
     RECT  2.16 14.175 66.96 14.445 ;
     RECT  2.16 14.715 66.96 14.985 ;
     RECT  2.16 15.255 66.96 15.525 ;
     RECT  2.16 15.795 66.96 16.065 ;
     RECT  2.16 16.335 66.96 16.605 ;
     RECT  2.16 16.875 66.96 17.145 ;
     RECT  2.16 17.415 66.96 17.685 ;
     RECT  2.16 17.955 66.96 18.225 ;
     RECT  2.16 18.495 66.96 18.765 ;
     RECT  2.16 19.035 66.96 19.305 ;
     RECT  2.16 19.575 66.96 19.845 ;
     RECT  2.16 20.115 66.96 20.385 ;
     RECT  2.16 20.655 66.96 20.925 ;
     RECT  2.16 21.195 66.96 21.465 ;
     RECT  2.16 21.735 66.96 22.005 ;
     RECT  2.16 22.275 66.96 22.545 ;
     RECT  2.16 22.815 66.96 23.085 ;
     RECT  2.16 23.355 66.96 23.625 ;
     RECT  2.16 23.895 66.96 24.165 ;
     RECT  2.16 24.435 66.96 24.705 ;
     RECT  2.16 24.975 66.96 25.245 ;
     RECT  2.16 25.515 66.96 25.785 ;
     RECT  2.16 26.055 66.96 26.325 ;
     RECT  2.16 26.595 66.96 26.865 ;
     RECT  2.16 27.135 66.96 27.405 ;
     RECT  2.16 27.675 66.96 27.945 ;
     RECT  2.16 28.215 66.96 28.485 ;
     RECT  2.16 28.755 66.96 29.025 ;
     RECT  2.16 29.295 66.96 29.565 ;
     RECT  2.16 29.835 66.96 30.105 ;
     RECT  2.16 30.375 66.96 30.645 ;
     RECT  2.16 30.915 66.96 31.185 ;
     RECT  2.16 31.455 66.96 31.725 ;
     RECT  2.16 31.995 66.96 32.265 ;
     RECT  2.16 32.535 66.96 32.805 ;
     RECT  2.16 33.075 66.96 33.345 ;
     RECT  2.16 33.615 66.96 33.885 ;
     RECT  2.16 34.155 66.96 34.425 ;
     RECT  2.16 34.695 66.96 34.965 ;
     RECT  2.16 35.235 66.96 35.505 ;
     RECT  2.16 35.775 66.96 36.045 ;
     RECT  2.16 36.315 66.96 36.585 ;
     RECT  2.16 36.855 66.96 37.125 ;
     RECT  2.16 37.395 66.96 37.665 ;
     RECT  2.16 37.935 66.96 38.205 ;
     RECT  2.16 38.475 66.96 38.745 ;
     RECT  2.16 39.015 66.96 39.285 ;
     RECT  2.16 39.555 66.96 39.825 ;
     RECT  2.16 40.095 66.96 40.365 ;
     RECT  2.16 40.635 66.96 40.905 ;
     RECT  2.16 41.175 66.96 41.445 ;
     RECT  2.16 41.715 66.96 41.985 ;
     RECT  2.16 42.255 66.96 42.525 ;
     RECT  2.16 42.795 66.96 43.065 ;
     RECT  2.16 43.335 66.96 43.605 ;
     RECT  2.16 43.875 66.96 44.145 ;
     RECT  2.16 44.415 66.96 44.685 ;
     RECT  2.16 44.955 66.96 45.225 ;
     RECT  2.16 45.495 66.96 45.765 ;
     RECT  2.16 46.035 66.96 46.305 ;
     RECT  2.16 46.575 66.96 46.845 ;
     RECT  2.16 47.115 66.96 47.385 ;
     RECT  2.16 47.655 66.96 47.925 ;
     RECT  2.16 48.195 66.96 48.465 ;
     RECT  2.16 48.735 66.96 49.005 ;
     RECT  2.16 49.275 66.96 49.545 ;
     RECT  2.16 49.815 66.96 50.085 ;
     RECT  2.16 50.355 66.96 50.625 ;
     RECT  2.16 50.895 66.96 51.165 ;
     RECT  2.16 51.435 66.96 51.705 ;
     RECT  2.16 51.975 66.96 52.245 ;
     RECT  2.16 52.515 66.96 52.785 ;
     RECT  2.16 53.055 66.96 53.325 ;
     RECT  2.16 53.595 66.96 53.865 ;
     RECT  2.16 54.135 66.96 54.405 ;
     RECT  2.16 54.675 66.96 54.945 ;
     RECT  2.16 55.215 66.96 55.485 ;
     RECT  2.16 55.755 66.96 56.025 ;
     RECT  2.16 56.295 66.96 56.565 ;
     RECT  2.16 56.835 66.96 57.105 ;
     RECT  2.16 57.375 66.96 57.645 ;
     RECT  2.16 57.915 66.96 58.185 ;
     RECT  2.16 58.455 66.96 58.725 ;
     RECT  2.16 58.995 66.96 59.265 ;
     RECT  2.16 59.535 66.96 59.805 ;
     RECT  2.16 60.075 66.96 60.345 ;
     RECT  2.16 60.615 66.96 60.885 ;
     RECT  2.16 61.155 66.96 61.425 ;
     RECT  2.16 61.695 66.96 61.965 ;
     RECT  2.16 62.235 66.96 62.505 ;
     RECT  2.16 62.775 66.96 63.045 ;
     RECT  2.16 63.315 66.96 63.585 ;
     RECT  2.16 63.855 66.96 64.125 ;
     RECT  2.16 64.395 66.96 64.665 ;
     RECT  2.16 64.935 66.96 65.205 ;
     RECT  2.16 65.475 66.96 65.745 ;
     RECT  2.16 66.015 66.96 66.285 ;
     RECT  2.16 66.555 66.96 66.825 ;
    LAYER M1 ;
     RECT  2.16 2.151 66.96 66.969 ;
    LAYER M2 ;
     RECT  0.103 14.841 0.139 14.859 ;
     RECT  0.103 36.396 0.139 36.414 ;
     RECT  0.139 14.256 0.175 14.859 ;
     RECT  0.103 7.902 0.211 7.92 ;
     RECT  0.139 35.856 0.247 36.414 ;
     RECT  0.103 37.476 0.247 37.494 ;
     RECT  0.211 7.236 0.311 7.92 ;
     RECT  0.175 8.946 0.535 8.964 ;
     RECT  0.175 13.572 0.851 14.859 ;
     RECT  0.535 8.82 1.147 9.576 ;
     RECT  0.103 10.836 1.147 10.854 ;
     RECT  1.147 41.184 1.183 41.202 ;
     RECT  0.851 14.841 1.219 14.859 ;
     RECT  1.147 3.078 1.687 3.096 ;
     RECT  0.851 13.572 1.723 13.59 ;
     RECT  1.219 14.841 1.723 15.354 ;
     RECT  0.823 16.236 1.723 16.254 ;
     RECT  1.723 13.572 2.155 16.254 ;
     RECT  1.687 3.078 2.16 3.132 ;
     RECT  0.535 4.5 2.16 4.518 ;
     RECT  0.535 6.318 2.16 6.336 ;
     RECT  0.311 7.902 2.16 7.92 ;
     RECT  1.147 8.82 2.16 10.854 ;
     RECT  2.155 13.572 2.16 16.434 ;
     RECT  0.247 35.856 2.16 37.494 ;
     RECT  2.155 38.376 2.16 38.394 ;
     RECT  1.183 41.184 2.16 41.544 ;
     RECT  2.16 2.151 2.731 66.969 ;
     RECT  2.731 2.106 2.839 66.969 ;
     RECT  2.839 2.034 3.847 66.969 ;
     RECT  3.847 1.998 6.683 66.969 ;
     RECT  6.683 2.034 7.763 66.969 ;
     RECT  7.763 2.151 9.391 66.969 ;
     RECT  9.391 2.151 11.327 67.086 ;
     RECT  11.327 2.151 11.651 67.014 ;
     RECT  11.651 2.151 38.371 66.969 ;
     RECT  38.371 2.151 39.623 67.014 ;
     RECT  39.623 2.151 43.447 66.969 ;
     RECT  43.447 2.106 43.555 66.969 ;
     RECT  43.555 2.034 45.059 66.969 ;
     RECT  45.059 2.151 47.479 66.969 ;
     RECT  47.479 2.106 47.759 66.969 ;
     RECT  47.759 2.151 53.383 66.969 ;
     RECT  53.383 2.106 54.247 66.969 ;
     RECT  54.247 2.034 55.859 66.969 ;
     RECT  55.859 2.106 56.723 66.969 ;
     RECT  56.723 2.151 57.991 66.969 ;
     RECT  57.991 2.151 59.603 67.014 ;
     RECT  59.603 2.151 62.779 66.969 ;
     RECT  62.779 2.151 65.363 67.014 ;
     RECT  65.363 2.151 66.96 66.969 ;
     RECT  66.96 56.466 66.983 66.618 ;
     RECT  66.96 3.726 67.019 7.524 ;
     RECT  67.019 4.464 67.091 7.524 ;
     RECT  67.091 5.076 67.127 7.524 ;
     RECT  67.127 5.616 67.199 6.03 ;
     RECT  67.127 6.822 67.199 7.524 ;
     RECT  66.96 33.156 67.235 33.912 ;
     RECT  66.96 11.484 67.271 32.292 ;
     RECT  67.235 33.156 67.271 33.606 ;
     RECT  67.199 6.012 67.307 6.03 ;
     RECT  66.96 8.82 67.307 9.378 ;
     RECT  66.96 50.904 67.307 55.242 ;
     RECT  66.983 56.772 67.307 66.618 ;
     RECT  67.199 7.434 67.343 7.524 ;
     RECT  67.343 7.506 67.415 7.524 ;
     RECT  66.96 36.09 67.559 36.108 ;
     RECT  67.271 15.066 67.775 23.148 ;
     RECT  67.271 33.156 67.775 33.444 ;
     RECT  67.307 50.904 67.775 54.666 ;
     RECT  67.271 11.484 67.811 14.166 ;
     RECT  67.775 15.066 67.811 18.018 ;
     RECT  67.271 23.904 67.811 32.292 ;
     RECT  67.775 50.904 67.811 53.892 ;
     RECT  67.775 54.648 67.811 54.666 ;
     RECT  67.307 56.772 67.811 66.582 ;
     RECT  67.811 11.484 67.847 13.698 ;
     RECT  67.775 18.774 67.847 19.026 ;
     RECT  67.775 19.854 67.847 23.148 ;
     RECT  67.811 50.904 67.847 52.614 ;
     RECT  67.811 56.772 67.847 64.692 ;
     RECT  66.96 10.368 67.883 10.692 ;
     RECT  67.847 11.556 67.883 13.698 ;
     RECT  67.847 19.008 67.883 19.026 ;
     RECT  67.847 51.408 67.883 52.308 ;
     RECT  66.96 50.094 68.099 50.112 ;
     RECT  67.847 56.772 68.099 61.452 ;
     RECT  67.811 15.066 68.351 16.632 ;
     RECT  67.811 25.254 68.351 30.906 ;
     RECT  67.811 53.37 68.351 53.892 ;
     RECT  67.811 65.484 68.351 66.582 ;
     RECT  67.883 11.718 68.387 13.698 ;
     RECT  68.351 15.066 68.387 15.084 ;
     RECT  67.811 17.496 68.387 17.982 ;
     RECT  67.847 20.124 68.387 23.148 ;
     RECT  67.811 23.904 68.387 24.498 ;
     RECT  68.351 25.254 68.387 28.746 ;
     RECT  68.351 29.538 68.387 30.906 ;
     RECT  67.883 52.29 68.387 52.308 ;
     RECT  68.351 53.451 68.387 53.892 ;
     RECT  68.351 65.484 68.387 65.538 ;
     RECT  68.351 66.294 68.387 66.582 ;
     RECT  67.307 8.82 68.423 8.838 ;
     RECT  67.883 10.368 68.423 10.386 ;
     RECT  68.387 11.718 68.423 12.384 ;
     RECT  68.351 16.038 68.423 16.632 ;
     RECT  68.387 27.216 68.423 28.584 ;
     RECT  67.883 51.408 68.423 51.426 ;
     RECT  68.387 53.451 68.423 53.694 ;
     RECT  68.071 54.684 68.423 54.702 ;
     RECT  68.099 57.384 68.423 61.452 ;
     RECT  67.847 62.244 68.423 64.656 ;
     RECT  68.387 20.16 68.459 23.148 ;
     RECT  68.387 25.254 68.459 26.082 ;
     RECT  68.423 57.384 68.459 57.402 ;
     RECT  68.423 58.23 68.495 60.912 ;
     RECT  68.423 62.28 68.495 63.108 ;
     RECT  68.387 65.52 68.495 65.538 ;
     RECT  68.387 66.456 68.495 66.546 ;
     RECT  68.423 64.134 68.531 64.656 ;
     RECT  68.495 66.456 68.531 66.474 ;
     RECT  68.791 10.44 68.827 10.458 ;
     RECT  68.387 13.176 68.855 13.698 ;
     RECT  68.387 17.496 68.891 17.514 ;
     RECT  68.423 16.038 68.927 16.596 ;
     RECT  67.811 31.77 68.927 31.788 ;
     RECT  68.827 10.44 68.935 10.809 ;
     RECT  68.935 10.44 68.963 10.998 ;
     RECT  68.459 25.254 68.963 25.308 ;
     RECT  68.387 29.88 68.963 30.474 ;
     RECT  68.963 10.521 68.999 10.998 ;
     RECT  68.423 12.096 68.999 12.114 ;
     RECT  68.927 16.074 68.999 16.596 ;
     RECT  68.459 20.16 68.999 20.448 ;
     RECT  68.459 21.276 68.999 23.148 ;
     RECT  68.963 25.29 68.999 25.308 ;
     RECT  68.963 30.42 68.999 30.474 ;
     RECT  68.423 53.64 68.999 53.694 ;
     RECT  68.495 58.266 68.999 60.912 ;
     RECT  68.999 10.791 69.035 10.998 ;
     RECT  68.855 13.176 69.035 13.194 ;
     RECT  68.999 16.578 69.035 16.596 ;
     RECT  68.999 20.16 69.035 20.178 ;
     RECT  68.999 21.276 69.035 22.914 ;
     RECT  68.387 23.976 69.035 24.498 ;
     RECT  68.459 26.064 69.035 26.082 ;
     RECT  68.423 27.342 69.035 28.584 ;
     RECT  68.999 30.456 69.035 30.474 ;
     RECT  67.775 33.156 69.035 33.174 ;
     RECT  68.999 53.676 69.035 53.694 ;
     RECT  68.999 58.356 69.035 60.912 ;
     RECT  68.495 62.28 69.035 62.496 ;
     RECT  68.531 64.134 69.035 64.152 ;
     RECT  69.035 58.356 69.071 58.824 ;
     RECT  69.007 18.306 69.107 18.324 ;
     RECT  69.035 21.276 69.107 21.879 ;
     RECT  69.035 23.976 69.107 23.994 ;
     RECT  69.071 58.356 69.107 58.374 ;
     RECT  69.035 60.426 69.107 60.444 ;
    LAYER M3 ;
     RECT  48.816 0.091 50.058 0.139 ;
     RECT  53.964 0.091 54.198 0.221 ;
     RECT  53.964 0.221 54.126 0.269 ;
     RECT  56.412 0.091 56.43 0.269 ;
     RECT  62.568 0.091 62.586 0.331 ;
     RECT  45.432 0.091 47.43 0.365 ;
     RECT  65.556 0.427 65.574 0.523 ;
     RECT  62.28 0.331 62.586 0.557 ;
     RECT  42.876 0.091 42.894 0.571 ;
     RECT  43.92 0.523 43.938 0.571 ;
     RECT  44.964 0.523 44.982 0.571 ;
     RECT  51.336 0.091 52.434 0.571 ;
     RECT  55.008 0.091 55.026 0.571 ;
     RECT  43.92 0.571 44.982 0.701 ;
     RECT  42.192 0.571 42.894 1.099 ;
     RECT  43.92 0.701 44.91 1.099 ;
     RECT  48.744 0.139 50.058 1.099 ;
     RECT  45.936 0.365 47.43 1.147 ;
     RECT  48.744 1.099 50.274 1.147 ;
     RECT  62.748 0.571 62.766 1.147 ;
     RECT  45.756 1.147 47.43 1.723 ;
     RECT  48.24 1.147 50.274 1.723 ;
     RECT  51.336 0.571 53.082 1.723 ;
     RECT  55.008 0.571 55.494 1.723 ;
     RECT  62.748 1.147 63.054 1.723 ;
     RECT  66.42 0.139 66.438 1.723 ;
     RECT  67.392 0.571 67.41 1.723 ;
     RECT  45.756 1.723 53.262 1.771 ;
     RECT  54.108 0.269 54.126 1.771 ;
     RECT  55.008 1.723 56.142 1.771 ;
     RECT  65.52 0.523 65.574 1.771 ;
     RECT  3.672 1.771 3.69 1.867 ;
     RECT  4.68 1.675 4.698 1.867 ;
     RECT  57.42 1.819 57.438 1.867 ;
     RECT  3.672 1.867 4.698 1.963 ;
     RECT  65.52 1.771 65.646 2.011 ;
     RECT  42.192 1.099 44.91 2.029 ;
     RECT  45.756 1.771 56.142 2.029 ;
     RECT  1.152 1.579 1.17 2.059 ;
     RECT  65.412 2.011 65.646 2.059 ;
     RECT  2.844 2.029 2.862 2.101 ;
     RECT  6.66 1.993 6.678 2.101 ;
     RECT  7.74 2.029 7.758 2.101 ;
     RECT  42.192 2.029 56.142 2.101 ;
     RECT  57.42 1.867 57.546 2.101 ;
     RECT  62.748 1.723 63.126 2.107 ;
     RECT  63.936 0.523 63.954 2.107 ;
     RECT  1.152 2.059 1.71 2.143 ;
     RECT  2.736 2.101 2.862 2.143 ;
     RECT  6.66 2.101 7.758 2.143 ;
     RECT  59.328 0.091 61.254 2.143 ;
     RECT  65.34 2.059 65.646 2.155 ;
     RECT  66.42 1.723 67.41 2.155 ;
     RECT  3.672 1.963 5.418 2.191 ;
     RECT  6.66 2.143 7.905 2.191 ;
     RECT  24.015 2.143 24.105 2.191 ;
     RECT  42.192 2.101 57.546 2.191 ;
     RECT  59.328 2.143 61.905 2.191 ;
     RECT  62.748 2.107 63.954 2.191 ;
     RECT  65.34 2.155 67.41 2.191 ;
     RECT  24.015 2.191 24.354 2.227 ;
     RECT  58.572 2.191 64.062 2.251 ;
     RECT  64.8 2.191 67.41 2.251 ;
     RECT  3.672 2.191 5.814 2.263 ;
     RECT  6.66 2.191 8.514 2.263 ;
     RECT  17.028 2.191 17.046 2.263 ;
     RECT  25.776 2.227 26.082 2.263 ;
     RECT  38.628 2.227 38.646 2.263 ;
     RECT  41.76 2.191 57.546 2.263 ;
     RECT  58.284 2.251 67.41 2.263 ;
     RECT  30.276 2.191 30.294 2.299 ;
     RECT  34.815 2.143 34.905 2.335 ;
     RECT  1.152 2.143 2.862 2.371 ;
     RECT  3.672 2.263 8.514 2.371 ;
     RECT  23.94 2.227 24.354 2.371 ;
     RECT  25.632 2.263 26.154 2.371 ;
     RECT  34.815 2.335 35.658 2.371 ;
     RECT  13.215 2.143 13.305 2.413 ;
     RECT  18.615 2.143 18.705 2.413 ;
     RECT  29.415 2.143 29.505 2.413 ;
     RECT  30.276 2.299 30.618 2.413 ;
     RECT  40.215 2.143 40.305 2.413 ;
     RECT  1.152 2.371 8.946 2.461 ;
     RECT  10.116 2.371 10.134 2.461 ;
     RECT  13.215 2.413 13.497 2.461 ;
     RECT  38.628 2.263 39.294 2.461 ;
     RECT  11.952 2.461 11.97 2.497 ;
     RECT  13.215 2.461 13.662 2.497 ;
     RECT  17.028 2.263 17.154 2.497 ;
     RECT  18.615 2.413 18.897 2.497 ;
     RECT  20.592 2.461 20.61 2.497 ;
     RECT  25.308 2.371 26.154 2.497 ;
     RECT  34.815 2.371 35.946 2.497 ;
     RECT  37.944 2.461 39.402 2.497 ;
     RECT  40.215 2.413 40.497 2.497 ;
     RECT  13.032 2.497 13.662 2.533 ;
     RECT  20.34 2.497 20.61 2.533 ;
     RECT  11.7 2.497 11.97 2.569 ;
     RECT  28.008 2.533 28.026 2.569 ;
     RECT  34.236 2.497 35.946 2.569 ;
     RECT  20.34 2.533 21.042 2.597 ;
     RECT  1.152 2.461 10.134 2.605 ;
     RECT  10.908 2.371 10.926 2.605 ;
     RECT  11.7 2.569 12.078 2.605 ;
     RECT  13.032 2.533 13.806 2.605 ;
     RECT  14.76 2.569 14.778 2.605 ;
     RECT  20.52 2.597 21.042 2.605 ;
     RECT  21.852 2.533 21.87 2.605 ;
     RECT  23.544 2.371 24.354 2.605 ;
     RECT  25.308 2.497 27.054 2.605 ;
     RECT  27.936 2.569 28.134 2.605 ;
     RECT  0.216 2.587 0.234 2.635 ;
     RECT  14.76 2.605 14.958 2.641 ;
     RECT  15.768 2.569 15.786 2.641 ;
     RECT  20.52 2.605 21.87 2.641 ;
     RECT  25.308 2.605 28.134 2.641 ;
     RECT  34.236 2.569 36.414 2.641 ;
     RECT  37.656 2.497 40.497 2.641 ;
     RECT  0.144 2.635 0.234 2.731 ;
     RECT  23.256 2.605 24.354 2.731 ;
     RECT  29.415 2.413 30.618 2.731 ;
     RECT  37.548 2.641 40.497 2.731 ;
     RECT  41.292 2.263 67.41 2.731 ;
     RECT  23.04 2.731 24.354 2.767 ;
     RECT  25.308 2.641 28.242 2.767 ;
     RECT  29.16 2.731 30.618 2.767 ;
     RECT  20.52 2.641 22.194 2.803 ;
     RECT  23.04 2.767 24.462 2.803 ;
     RECT  25.308 2.767 30.618 2.803 ;
     RECT  31.428 2.569 31.878 2.803 ;
     RECT  0.144 2.731 0.342 2.861 ;
     RECT  11.7 2.605 13.878 2.875 ;
     RECT  14.76 2.641 15.786 2.875 ;
     RECT  17.028 2.497 18.897 2.875 ;
     RECT  1.152 2.605 10.926 2.911 ;
     RECT  11.7 2.875 15.786 2.911 ;
     RECT  16.812 2.875 19.026 2.911 ;
     RECT  34.236 2.641 36.702 2.911 ;
     RECT  16.812 2.911 19.278 3.001 ;
     RECT  34.236 2.911 36.774 3.001 ;
     RECT  16.74 3.001 19.278 3.037 ;
     RECT  1.152 2.911 15.786 3.101 ;
     RECT  25.272 2.803 31.878 3.109 ;
     RECT  33.048 3.073 33.066 3.109 ;
     RECT  1.692 3.101 13.662 3.137 ;
     RECT  25.272 3.109 33.066 3.145 ;
     RECT  33.948 3.001 36.774 3.145 ;
     RECT  37.548 2.731 67.41 3.145 ;
     RECT  14.4 3.101 15.786 3.181 ;
     RECT  16.56 3.037 19.278 3.181 ;
     RECT  25.272 3.145 67.41 3.181 ;
     RECT  2.304 3.137 13.662 3.209 ;
     RECT  25.236 3.181 67.41 3.299 ;
     RECT  14.4 3.181 19.746 3.343 ;
     RECT  20.52 2.803 24.462 3.343 ;
     RECT  14.4 3.343 24.462 3.569 ;
     RECT  25.236 3.299 35.982 3.569 ;
     RECT  27.36 3.569 35.982 3.677 ;
     RECT  20.556 3.569 24.462 3.721 ;
     RECT  25.236 3.569 26.478 3.721 ;
     RECT  2.304 3.209 13.59 3.955 ;
     RECT  14.4 3.569 19.818 3.955 ;
     RECT  36.756 3.299 67.41 3.983 ;
     RECT  27.504 3.677 35.982 4.081 ;
     RECT  36.756 3.983 41.598 4.081 ;
     RECT  27.504 4.081 41.598 4.109 ;
     RECT  20.556 3.721 26.478 4.145 ;
     RECT  0.144 2.861 0.162 4.219 ;
     RECT  0.144 4.219 0.234 4.363 ;
     RECT  2.304 3.955 19.818 4.379 ;
     RECT  0.144 4.363 0.342 4.495 ;
     RECT  15.156 4.379 19.818 4.495 ;
     RECT  20.556 4.145 26.442 4.495 ;
     RECT  2.304 4.379 14.382 4.685 ;
     RECT  27.504 4.109 38.934 4.765 ;
     RECT  39.744 4.109 41.598 4.801 ;
     RECT  42.48 3.983 67.41 4.801 ;
     RECT  0.144 4.495 0.558 4.877 ;
     RECT  15.156 4.495 26.442 4.891 ;
     RECT  15.156 4.891 26.478 4.939 ;
     RECT  27.468 4.765 38.934 4.963 ;
     RECT  39.744 4.801 67.41 4.963 ;
     RECT  2.34 4.685 14.382 5.161 ;
     RECT  15.156 4.939 26.55 5.161 ;
     RECT  0.144 4.877 0.306 5.501 ;
     RECT  27.396 4.963 67.41 5.501 ;
     RECT  27.396 5.501 37.458 5.575 ;
     RECT  0.216 5.501 0.306 5.597 ;
     RECT  2.34 5.161 26.55 5.603 ;
     RECT  0.288 5.597 0.306 5.645 ;
     RECT  20.808 5.603 26.55 5.701 ;
     RECT  27.324 5.575 37.458 5.701 ;
     RECT  2.34 5.603 19.926 5.851 ;
     RECT  2.196 5.851 19.926 6.029 ;
     RECT  20.808 5.701 37.458 6.277 ;
     RECT  38.268 5.501 67.41 6.277 ;
     RECT  2.268 6.029 19.926 6.385 ;
     RECT  2.268 6.385 19.962 6.811 ;
     RECT  20.808 6.277 67.41 6.811 ;
     RECT  0.54 6.313 0.558 6.955 ;
     RECT  0.432 6.955 0.558 7.051 ;
     RECT  2.268 6.811 67.41 7.079 ;
     RECT  0.36 7.051 0.558 7.133 ;
     RECT  0.36 7.133 0.378 7.147 ;
     RECT  0.144 7.147 0.378 7.181 ;
     RECT  2.304 7.079 67.41 7.529 ;
     RECT  0.144 7.181 0.342 7.661 ;
     RECT  2.304 7.529 66.906 7.889 ;
     RECT  0.144 7.661 0.234 7.897 ;
     RECT  2.304 7.889 66.834 7.915 ;
     RECT  2.268 7.915 66.834 7.925 ;
     RECT  21.096 7.925 66.834 7.961 ;
     RECT  0.108 7.897 0.234 8.045 ;
     RECT  2.268 7.925 20.214 8.107 ;
     RECT  21.096 7.961 35.91 8.303 ;
     RECT  2.232 8.107 20.214 8.429 ;
     RECT  2.268 8.429 20.214 8.699 ;
     RECT  0.144 8.045 0.234 8.765 ;
     RECT  2.304 8.699 20.214 8.765 ;
     RECT  0.18 8.765 0.234 8.815 ;
     RECT  1.152 7.483 1.17 8.815 ;
     RECT  12.708 8.765 20.214 8.815 ;
     RECT  21.096 8.303 26.658 8.815 ;
     RECT  36.828 7.961 66.834 8.827 ;
     RECT  27.432 8.303 35.91 8.941 ;
     RECT  12.708 8.815 26.658 9.049 ;
     RECT  27.432 8.941 35.982 9.049 ;
     RECT  12.708 9.049 35.982 9.247 ;
     RECT  36.72 8.827 66.834 9.247 ;
     RECT  12.708 9.247 66.834 9.355 ;
     RECT  2.304 8.765 11.97 9.643 ;
     RECT  68.4 8.815 68.418 9.835 ;
     RECT  0.18 8.815 1.17 9.869 ;
     RECT  2.268 9.643 11.97 9.931 ;
     RECT  12.708 9.355 67.302 9.931 ;
     RECT  2.268 9.931 67.302 10.157 ;
     RECT  0.144 9.931 0.162 10.219 ;
     RECT  1.152 9.869 1.17 10.229 ;
     RECT  2.268 10.157 66.726 10.463 ;
     RECT  2.268 10.463 26.802 10.633 ;
     RECT  68.4 9.835 69.03 10.669 ;
     RECT  0.108 10.219 0.162 10.685 ;
     RECT  2.232 10.633 26.802 10.831 ;
     RECT  0.108 10.685 0.126 10.859 ;
     RECT  67.86 10.669 69.03 10.925 ;
     RECT  27.756 10.463 66.726 11.011 ;
     RECT  27.756 11.011 66.834 11.069 ;
     RECT  1.728 10.831 26.802 11.281 ;
     RECT  27.756 11.069 66.726 11.281 ;
     RECT  67.86 10.925 67.95 11.479 ;
     RECT  67.824 11.479 67.95 11.713 ;
     RECT  68.832 10.925 69.03 11.713 ;
     RECT  67.824 11.713 69.03 11.755 ;
     RECT  1.728 11.281 66.726 12.043 ;
     RECT  1.728 12.043 66.762 12.119 ;
     RECT  1.728 12.119 36.522 12.209 ;
     RECT  0.324 11.851 0.342 12.235 ;
     RECT  37.26 12.119 66.762 12.523 ;
     RECT  67.788 11.755 69.03 12.523 ;
     RECT  0.108 12.235 0.342 12.557 ;
     RECT  1.728 12.209 36.486 12.857 ;
     RECT  37.26 12.523 69.03 12.857 ;
     RECT  1.728 12.857 16.362 13.003 ;
     RECT  17.1 12.857 36.486 13.055 ;
     RECT  28.62 13.055 36.486 13.063 ;
     RECT  37.26 12.857 38.034 13.063 ;
     RECT  38.772 12.857 69.03 13.199 ;
     RECT  38.772 13.199 68.85 13.433 ;
     RECT  28.62 13.063 38.034 13.675 ;
     RECT  38.772 13.433 66.834 13.675 ;
     RECT  67.788 13.433 68.85 13.703 ;
     RECT  1.224 13.003 16.362 13.711 ;
     RECT  17.1 13.055 27.774 13.711 ;
     RECT  28.62 13.675 66.834 13.837 ;
     RECT  1.224 13.711 27.774 14.099 ;
     RECT  28.584 13.837 66.834 14.099 ;
     RECT  28.584 14.099 36.09 14.135 ;
     RECT  36.864 14.099 66.834 14.135 ;
     RECT  0.108 12.557 0.198 14.251 ;
     RECT  1.224 14.099 22.518 14.251 ;
     RECT  23.292 14.099 27.774 14.525 ;
     RECT  67.788 13.703 68.418 14.539 ;
     RECT  37.008 14.135 66.834 14.755 ;
     RECT  67.788 14.539 68.994 14.755 ;
     RECT  23.328 14.525 27.774 14.791 ;
     RECT  37.008 14.755 68.994 14.819 ;
     RECT  0.108 14.251 22.518 14.864 ;
     RECT  28.584 14.135 36.054 14.881 ;
     RECT  23.328 14.791 27.81 15.053 ;
     RECT  67.248 14.819 68.994 15.211 ;
     RECT  23.364 15.053 27.81 15.251 ;
     RECT  23.364 15.251 27.774 15.323 ;
     RECT  28.584 14.881 36.27 15.331 ;
     RECT  37.008 14.819 66.474 15.331 ;
     RECT  0.828 14.864 22.518 15.359 ;
     RECT  1.728 15.359 22.518 15.557 ;
     RECT  28.584 15.331 66.474 15.565 ;
     RECT  67.248 15.211 69.03 15.565 ;
     RECT  2.016 15.557 22.518 15.787 ;
     RECT  28.584 15.565 69.03 15.821 ;
     RECT  2.016 15.787 22.734 15.989 ;
     RECT  2.088 15.989 22.734 16.141 ;
     RECT  23.472 15.323 27.774 16.141 ;
     RECT  2.088 16.141 27.774 16.169 ;
     RECT  0.828 15.359 0.846 16.259 ;
     RECT  28.584 15.821 67.806 16.267 ;
     RECT  2.16 16.169 27.774 16.439 ;
     RECT  2.415 16.439 27.774 16.537 ;
     RECT  28.548 16.267 67.806 16.537 ;
     RECT  68.832 15.821 69.03 16.601 ;
     RECT  2.415 16.537 67.806 16.609 ;
     RECT  68.832 16.601 68.958 16.609 ;
     RECT  2.415 16.609 68.958 16.709 ;
     RECT  3.456 16.709 68.958 16.781 ;
     RECT  68.868 16.781 68.958 17.069 ;
     RECT  3.456 16.781 67.806 17.075 ;
     RECT  3.816 17.075 67.806 17.515 ;
     RECT  68.868 17.069 68.886 17.515 ;
     RECT  3.816 17.515 68.886 17.645 ;
     RECT  3.96 17.645 68.886 17.899 ;
     RECT  3.96 17.899 68.994 17.987 ;
     RECT  3.96 17.987 67.806 18.023 ;
     RECT  68.976 17.987 68.994 18.283 ;
     RECT  68.976 18.283 69.03 18.301 ;
     RECT  3.96 18.023 67.77 18.769 ;
     RECT  3.96 18.769 67.842 18.955 ;
     RECT  68.976 18.301 69.102 18.955 ;
     RECT  3.96 18.955 69.102 19.075 ;
     RECT  3.492 19.075 69.102 19.103 ;
     RECT  67.752 19.103 69.102 19.301 ;
     RECT  2.415 16.709 2.697 19.339 ;
     RECT  3.492 19.103 66.834 19.339 ;
     RECT  2.415 19.339 66.834 19.379 ;
     RECT  3.492 19.379 66.834 19.679 ;
     RECT  67.824 19.301 69.102 20.107 ;
     RECT  3.636 19.679 66.834 20.191 ;
     RECT  67.788 20.107 69.102 20.191 ;
     RECT  3.636 20.191 69.102 20.579 ;
     RECT  2.415 19.379 2.697 20.683 ;
     RECT  2.415 20.683 2.754 20.731 ;
     RECT  3.708 20.579 69.102 20.759 ;
     RECT  3.852 20.759 69.102 20.909 ;
     RECT  3.852 20.909 66.834 21.029 ;
     RECT  2.415 20.731 2.898 21.067 ;
     RECT  2.415 21.067 2.934 21.505 ;
     RECT  3.852 21.029 5.598 21.505 ;
     RECT  6.336 21.029 66.834 21.733 ;
     RECT  67.752 20.909 69.102 21.733 ;
     RECT  6.336 21.733 69.102 21.773 ;
     RECT  2.415 21.505 5.598 21.811 ;
     RECT  6.336 21.773 66.834 21.811 ;
     RECT  2.415 21.811 66.834 22.507 ;
     RECT  67.752 21.773 69.102 22.507 ;
     RECT  2.415 22.507 69.102 22.811 ;
     RECT  3.456 22.811 69.102 23.189 ;
     RECT  2.415 22.811 2.697 23.557 ;
     RECT  3.456 23.189 66.762 23.557 ;
     RECT  2.415 23.557 66.762 23.629 ;
     RECT  67.788 23.189 69.102 23.927 ;
     RECT  68.94 23.927 69.102 23.999 ;
     RECT  67.788 23.927 67.806 24.043 ;
     RECT  2.376 23.629 66.762 24.133 ;
     RECT  67.752 24.043 67.806 24.133 ;
     RECT  68.94 23.999 69.03 24.503 ;
     RECT  2.376 24.133 67.806 24.509 ;
     RECT  68.94 24.503 68.994 25.291 ;
     RECT  2.415 24.509 67.806 25.511 ;
     RECT  68.94 25.291 69.03 25.555 ;
     RECT  68.364 25.555 69.03 26.087 ;
     RECT  68.364 26.087 68.454 26.093 ;
     RECT  68.364 26.093 68.382 26.251 ;
     RECT  68.328 26.251 68.382 26.347 ;
     RECT  2.415 25.511 67.374 26.443 ;
     RECT  68.292 26.347 68.382 26.443 ;
     RECT  2.415 26.443 68.382 26.923 ;
     RECT  2.415 26.923 69.03 27.401 ;
     RECT  4.284 27.401 69.03 27.977 ;
     RECT  2.415 27.401 3.51 28.147 ;
     RECT  4.284 27.977 5.454 28.147 ;
     RECT  2.415 28.147 5.454 28.445 ;
     RECT  2.415 28.445 5.418 28.553 ;
     RECT  6.192 27.977 69.03 29.021 ;
     RECT  68.328 29.021 69.03 29.327 ;
     RECT  2.415 28.553 5.346 29.335 ;
     RECT  2.376 29.335 5.346 29.371 ;
     RECT  6.192 29.021 67.266 29.371 ;
     RECT  2.376 29.371 67.266 29.489 ;
     RECT  4.5 29.489 67.266 30.109 ;
     RECT  68.364 29.327 69.03 30.109 ;
     RECT  2.376 29.489 3.726 30.331 ;
     RECT  2.376 30.331 3.762 30.415 ;
     RECT  4.5 30.109 69.03 30.415 ;
     RECT  2.376 30.415 69.03 30.479 ;
     RECT  2.376 30.479 68.922 30.911 ;
     RECT  68.868 30.911 68.922 30.941 ;
     RECT  2.376 30.911 67.914 31.085 ;
     RECT  2.376 31.085 67.806 31.145 ;
     RECT  68.904 30.941 68.922 31.339 ;
     RECT  68.904 31.339 69.03 31.793 ;
     RECT  2.415 31.145 67.806 32.035 ;
     RECT  2.34 32.035 67.806 32.297 ;
     RECT  69.012 31.793 69.03 33.179 ;
     RECT  2.34 32.297 67.77 33.449 ;
     RECT  2.34 33.449 67.554 34.151 ;
     RECT  2.415 34.151 67.554 34.925 ;
     RECT  2.415 34.925 16.326 34.969 ;
     RECT  17.136 34.925 67.554 35.339 ;
     RECT  2.34 34.969 16.326 35.941 ;
     RECT  17.604 35.339 67.554 35.969 ;
     RECT  2.34 35.941 16.542 36.013 ;
     RECT  67.536 35.969 67.554 36.113 ;
     RECT  0.144 35.851 0.162 36.121 ;
     RECT  2.16 36.013 16.542 36.121 ;
     RECT  17.604 35.969 66.69 36.121 ;
     RECT  2.16 36.121 66.69 36.275 ;
     RECT  0.144 36.121 0.234 36.391 ;
     RECT  0.108 36.391 0.234 36.859 ;
     RECT  0.108 36.859 0.27 37.399 ;
     RECT  2.16 36.275 66.474 37.471 ;
     RECT  0.108 37.399 0.306 37.675 ;
     RECT  0.108 37.675 0.342 37.709 ;
     RECT  2.16 37.471 66.762 37.769 ;
     RECT  0.144 37.709 0.342 37.805 ;
     RECT  2.16 37.769 66.402 38.399 ;
     RECT  2.304 38.399 66.402 38.551 ;
     RECT  0.144 37.805 0.306 38.669 ;
     RECT  2.304 38.551 66.618 38.669 ;
     RECT  0.36 38.827 0.45 39.005 ;
     RECT  0.36 39.005 0.378 39.053 ;
     RECT  1.152 39.115 1.17 39.211 ;
     RECT  0.324 39.403 0.342 39.533 ;
     RECT  0.216 39.547 0.234 39.821 ;
     RECT  2.34 38.669 66.618 39.821 ;
     RECT  0.108 39.883 0.126 40.061 ;
     RECT  2.34 39.821 66.546 40.325 ;
     RECT  1.152 39.211 1.206 41.207 ;
     RECT  2.34 40.325 65.79 41.251 ;
     RECT  66.528 40.325 66.546 41.251 ;
     RECT  2.34 41.251 66.546 41.341 ;
     RECT  1.188 41.207 1.206 41.549 ;
     RECT  2.304 41.341 66.546 41.791 ;
     RECT  2.304 41.791 66.618 41.933 ;
     RECT  30.528 41.933 66.618 41.953 ;
     RECT  30.528 41.953 66.69 41.987 ;
     RECT  30.888 41.987 66.69 42.061 ;
     RECT  0.144 41.947 0.162 42.125 ;
     RECT  30.888 42.061 66.834 42.179 ;
     RECT  2.304 41.933 29.697 42.667 ;
     RECT  30.888 42.179 66.726 42.715 ;
     RECT  2.268 42.667 29.697 42.755 ;
     RECT  30.492 42.715 66.726 42.797 ;
     RECT  2.304 42.755 29.697 42.835 ;
     RECT  30.492 42.797 62.838 42.835 ;
     RECT  63.576 42.797 66.726 43.141 ;
     RECT  2.304 42.835 62.838 43.259 ;
     RECT  2.304 43.259 44.37 43.331 ;
     RECT  2.304 43.331 29.754 43.565 ;
     RECT  2.415 43.565 29.754 43.601 ;
     RECT  2.415 43.601 29.697 43.709 ;
     RECT  30.672 43.331 44.37 44.011 ;
     RECT  45.144 43.259 62.838 44.011 ;
     RECT  30.672 44.011 62.838 44.077 ;
     RECT  63.576 43.141 66.87 44.077 ;
     RECT  30.672 44.077 66.87 44.155 ;
     RECT  30.564 44.155 66.87 44.419 ;
     RECT  3.528 43.709 29.697 44.443 ;
     RECT  3.528 44.443 29.754 44.491 ;
     RECT  3.492 44.491 29.754 44.581 ;
     RECT  30.528 44.419 66.87 44.581 ;
     RECT  3.492 44.581 66.87 44.689 ;
     RECT  2.415 43.709 2.697 44.725 ;
     RECT  3.42 44.689 66.87 44.725 ;
     RECT  2.376 44.725 66.87 44.915 ;
     RECT  2.376 44.915 58.734 45.419 ;
     RECT  2.376 45.419 58.662 45.629 ;
     RECT  59.796 44.915 66.87 45.697 ;
     RECT  2.376 45.629 58.23 45.725 ;
     RECT  59.76 45.697 66.87 46.201 ;
     RECT  2.415 45.725 58.23 46.651 ;
     RECT  59.148 46.201 66.87 46.651 ;
     RECT  2.415 46.651 66.87 47.111 ;
     RECT  2.415 47.111 58.158 47.381 ;
     RECT  2.415 47.381 57.942 48.901 ;
     RECT  58.968 47.111 66.87 48.901 ;
     RECT  2.415 48.901 66.87 50.155 ;
     RECT  2.415 50.155 66.906 50.395 ;
     RECT  2.412 50.395 66.906 50.549 ;
     RECT  2.412 50.549 32.634 50.669 ;
     RECT  68.076 50.089 68.094 50.899 ;
     RECT  2.415 50.669 32.634 51.331 ;
     RECT  33.372 50.549 66.906 51.331 ;
     RECT  67.824 50.899 68.094 51.403 ;
     RECT  67.824 51.403 68.418 51.595 ;
     RECT  67.824 51.595 69.03 51.787 ;
     RECT  67.788 51.787 69.03 51.883 ;
     RECT  2.415 51.331 66.906 52.171 ;
     RECT  2.376 52.171 66.906 52.213 ;
     RECT  67.752 51.883 69.03 52.213 ;
     RECT  2.376 52.213 69.03 52.475 ;
     RECT  2.415 52.475 69.03 53.453 ;
     RECT  2.415 53.453 67.014 53.474 ;
     RECT  67.752 53.453 69.03 53.699 ;
     RECT  2.415 53.474 66.978 54.379 ;
     RECT  67.752 53.699 68.418 54.379 ;
     RECT  2.415 54.379 68.418 54.671 ;
     RECT  68.076 54.671 68.418 54.707 ;
     RECT  2.415 54.671 67.302 54.869 ;
     RECT  2.415 54.869 33.246 54.985 ;
     RECT  34.056 54.869 67.302 55.247 ;
     RECT  2.376 54.985 33.246 55.993 ;
     RECT  34.056 55.247 66.978 55.993 ;
     RECT  2.376 55.993 66.978 56.489 ;
     RECT  68.076 54.707 68.094 56.795 ;
     RECT  2.376 56.489 66.906 56.831 ;
     RECT  2.412 56.831 66.906 57.065 ;
     RECT  68.436 57.379 68.454 57.649 ;
     RECT  2.415 57.065 66.906 57.721 ;
     RECT  67.824 57.649 68.454 57.721 ;
     RECT  2.415 57.721 68.454 57.991 ;
     RECT  2.376 57.991 68.454 58.157 ;
     RECT  2.415 58.157 68.454 58.225 ;
     RECT  2.415 58.225 68.49 58.261 ;
     RECT  2.415 58.261 68.994 58.315 ;
     RECT  2.415 58.315 69.03 58.351 ;
     RECT  2.415 58.351 69.102 58.733 ;
     RECT  2.415 58.733 67.554 58.877 ;
     RECT  2.415 58.877 41.058 59.099 ;
     RECT  2.415 59.099 24.786 59.189 ;
     RECT  41.832 58.877 67.554 59.563 ;
     RECT  68.4 58.733 69.102 59.563 ;
     RECT  25.524 59.099 41.058 59.611 ;
     RECT  41.832 59.563 69.102 59.611 ;
     RECT  2.415 59.189 24.678 60.035 ;
     RECT  25.524 59.611 69.102 60.151 ;
     RECT  25.164 60.151 69.102 60.449 ;
     RECT  2.415 60.035 24.354 60.817 ;
     RECT  25.164 60.449 69.03 60.817 ;
     RECT  2.415 60.817 69.03 60.989 ;
     RECT  2.415 60.989 22.59 61.349 ;
     RECT  2.415 61.349 22.554 61.889 ;
     RECT  23.364 60.989 69.03 62.041 ;
     RECT  3.708 61.889 22.554 62.159 ;
     RECT  3.852 62.159 22.554 62.311 ;
     RECT  23.292 62.041 69.03 62.311 ;
     RECT  3.852 62.311 69.03 62.501 ;
     RECT  2.415 61.889 2.697 62.731 ;
     RECT  3.852 62.501 68.958 63.005 ;
     RECT  2.415 62.731 3.114 63.121 ;
     RECT  3.852 63.005 68.49 63.121 ;
     RECT  2.415 63.121 68.49 63.149 ;
     RECT  2.415 63.149 33.282 63.653 ;
     RECT  2.415 63.653 33.102 63.815 ;
     RECT  2.415 63.815 9.522 63.821 ;
     RECT  3.852 63.821 9.522 63.851 ;
     RECT  34.164 63.149 68.454 63.851 ;
     RECT  34.164 63.851 67.302 63.883 ;
     RECT  68.076 63.851 68.454 64.075 ;
     RECT  68.076 64.075 69.03 64.157 ;
     RECT  34.056 63.883 67.302 64.205 ;
     RECT  34.056 64.205 66.834 64.291 ;
     RECT  3.852 63.851 9.486 64.633 ;
     RECT  10.296 63.815 33.102 64.633 ;
     RECT  68.076 64.157 68.526 64.651 ;
     RECT  3.852 64.633 33.102 64.741 ;
     RECT  33.84 64.291 66.834 64.741 ;
     RECT  3.852 64.741 66.834 64.769 ;
     RECT  38.772 64.769 66.834 64.933 ;
     RECT  67.788 64.651 68.526 64.933 ;
     RECT  3.852 64.769 37.818 64.939 ;
     RECT  3.564 64.939 37.818 64.967 ;
     RECT  38.772 64.933 68.526 65.035 ;
     RECT  3.564 64.967 32.85 65.357 ;
     RECT  38.772 65.035 68.958 65.399 ;
     RECT  3.564 65.357 15.642 65.435 ;
     RECT  16.416 65.357 32.85 65.669 ;
     RECT  16.524 65.669 32.85 65.705 ;
     RECT  33.912 64.967 37.818 65.741 ;
     RECT  16.632 65.705 32.85 65.749 ;
     RECT  16.632 65.749 32.958 65.821 ;
     RECT  3.564 65.435 15.462 65.885 ;
     RECT  3.852 65.885 15.462 65.939 ;
     RECT  16.632 65.821 33.462 66.047 ;
     RECT  16.668 66.047 33.462 66.083 ;
     RECT  23.508 66.083 33.462 66.119 ;
     RECT  34.2 65.741 37.818 66.139 ;
     RECT  38.844 65.399 68.958 66.139 ;
     RECT  3.852 65.939 14.31 66.173 ;
     RECT  16.668 66.083 22.698 66.209 ;
     RECT  34.2 66.139 68.958 66.221 ;
     RECT  34.2 66.221 67.302 66.269 ;
     RECT  68.328 66.221 68.958 66.269 ;
     RECT  20.628 66.209 22.698 66.281 ;
     RECT  68.328 66.269 68.526 66.281 ;
     RECT  15.192 65.939 15.462 66.317 ;
     RECT  20.628 66.281 22.626 66.317 ;
     RECT  23.58 66.119 33.462 66.353 ;
     RECT  34.2 66.269 40.497 66.353 ;
     RECT  41.652 66.269 67.302 66.353 ;
     RECT  15.192 66.317 15.354 66.389 ;
     RECT  23.58 66.353 29.697 66.389 ;
     RECT  30.492 66.353 33.462 66.389 ;
     RECT  41.652 66.353 42.498 66.389 ;
     RECT  3.852 66.173 14.094 66.479 ;
     RECT  15.192 66.389 15.21 66.479 ;
     RECT  16.668 66.209 19.782 66.479 ;
     RECT  23.58 66.389 25.254 66.479 ;
     RECT  26.1 66.389 29.697 66.479 ;
     RECT  34.2 66.353 37.458 66.479 ;
     RECT  42.3 66.389 42.498 66.479 ;
     RECT  43.272 66.353 67.302 66.479 ;
     RECT  68.364 66.281 68.526 66.479 ;
     RECT  30.744 66.389 33.462 66.487 ;
     RECT  34.2 66.479 35.514 66.487 ;
     RECT  27.288 66.479 29.697 66.515 ;
     RECT  42.3 66.479 42.318 66.515 ;
     RECT  16.668 66.479 19.71 66.551 ;
     RECT  20.628 66.317 22.014 66.551 ;
     RECT  23.58 66.479 25.074 66.551 ;
     RECT  27.396 66.515 29.697 66.551 ;
     RECT  30.744 66.487 35.514 66.551 ;
     RECT  36.252 66.479 37.458 66.551 ;
     RECT  43.38 66.479 54.882 66.551 ;
     RECT  7.815 66.479 14.094 66.557 ;
     RECT  3.852 66.479 5.238 66.587 ;
     RECT  6.12 66.479 6.894 66.587 ;
     RECT  23.796 66.551 25.074 66.587 ;
     RECT  27.396 66.551 27.414 66.587 ;
     RECT  30.888 66.551 35.514 66.587 ;
     RECT  36.54 66.551 37.386 66.587 ;
     RECT  43.92 66.551 54.882 66.587 ;
     RECT  68.364 66.479 68.49 66.587 ;
     RECT  6.12 66.587 6.138 66.605 ;
     RECT  7.815 66.557 13.698 66.605 ;
     RECT  4.464 66.587 4.482 66.623 ;
     RECT  5.22 66.587 5.238 66.623 ;
     RECT  6.876 66.587 6.894 66.623 ;
     RECT  7.815 66.605 11.646 66.623 ;
     RECT  12.492 66.605 13.497 66.623 ;
     RECT  23.796 66.587 24.822 66.623 ;
     RECT  28.548 66.551 29.697 66.623 ;
     RECT  30.888 66.587 31.95 66.623 ;
     RECT  32.796 66.587 35.514 66.623 ;
     RECT  36.864 66.587 37.386 66.623 ;
     RECT  43.92 66.587 44.298 66.623 ;
     RECT  12.888 66.623 13.497 66.659 ;
     RECT  16.668 66.551 19.674 66.659 ;
     RECT  20.628 66.551 21.762 66.659 ;
     RECT  23.796 66.623 24.534 66.659 ;
     RECT  28.728 66.623 29.697 66.659 ;
     RECT  30.96 66.623 30.978 66.659 ;
     RECT  31.932 66.623 31.95 66.659 ;
     RECT  32.796 66.623 35.097 66.659 ;
     RECT  43.92 66.623 43.938 66.659 ;
     RECT  45.108 66.587 54.882 66.659 ;
     RECT  16.668 66.659 17.298 66.701 ;
     RECT  18.072 66.659 18.897 66.701 ;
     RECT  55.764 66.479 67.302 66.701 ;
     RECT  2.415 63.821 2.697 66.707 ;
     RECT  13.215 66.659 13.497 66.707 ;
     RECT  18.216 66.701 18.897 66.707 ;
     RECT  29.415 66.659 29.697 66.707 ;
     RECT  33.048 66.659 35.097 66.707 ;
     RECT  38.232 66.353 40.497 66.707 ;
     RECT  17.028 66.701 17.298 66.749 ;
     RECT  19.656 66.659 19.674 66.749 ;
     RECT  23.796 66.659 24.426 66.749 ;
     RECT  33.048 66.707 34.905 66.749 ;
     RECT  36.936 66.623 37.026 66.749 ;
     RECT  38.232 66.707 40.305 66.749 ;
     RECT  45.615 66.659 54.738 66.749 ;
     RECT  55.764 66.701 67.266 66.749 ;
     RECT  7.815 66.623 9.414 66.755 ;
     RECT  10.332 66.623 11.646 66.785 ;
     RECT  33.048 66.749 33.894 66.785 ;
     RECT  34.74 66.749 34.905 66.785 ;
     RECT  38.376 66.749 40.305 66.785 ;
     RECT  45.615 66.749 46.278 66.785 ;
     RECT  65.304 66.749 67.266 66.797 ;
     RECT  8.64 66.755 9.414 66.821 ;
     RECT  23.796 66.749 24.318 66.821 ;
     RECT  33.048 66.785 33.642 66.821 ;
     RECT  37.008 66.749 37.026 66.821 ;
     RECT  47.376 66.749 48.87 66.821 ;
     RECT  55.872 66.749 63.018 66.845 ;
     RECT  21.096 66.659 21.762 66.857 ;
     RECT  49.644 66.749 54.702 66.857 ;
     RECT  65.304 66.797 66.726 66.857 ;
     RECT  17.028 66.749 17.046 66.893 ;
     RECT  24.015 66.821 24.318 66.893 ;
     RECT  63.756 66.749 64.566 66.893 ;
     RECT  9.18 66.821 9.414 66.929 ;
     RECT  18.216 66.707 18.705 66.929 ;
     RECT  33.048 66.821 33.066 66.929 ;
     RECT  47.376 66.821 47.394 66.929 ;
     RECT  48.852 66.821 48.87 66.929 ;
     RECT  49.644 66.857 52.974 66.929 ;
     RECT  53.82 66.857 54.702 66.929 ;
     RECT  61.38 66.845 63.018 66.929 ;
     RECT  63.792 66.893 64.566 66.929 ;
     RECT  54.684 66.929 54.702 66.941 ;
     RECT  2.415 66.707 2.505 66.977 ;
     RECT  7.815 66.755 7.905 66.977 ;
     RECT  13.215 66.707 13.305 66.977 ;
     RECT  18.615 66.929 18.705 66.977 ;
     RECT  24.015 66.893 24.105 66.977 ;
     RECT  29.415 66.707 29.505 66.977 ;
     RECT  34.815 66.785 34.905 66.977 ;
     RECT  39.6 66.785 40.305 66.977 ;
     RECT  45.615 66.785 45.705 66.977 ;
     RECT  68.436 66.587 68.49 66.989 ;
     RECT  10.728 66.785 11.646 67.019 ;
     RECT  38.376 66.785 38.394 67.019 ;
     RECT  39.6 66.977 39.618 67.019 ;
     RECT  65.34 66.857 66.726 67.019 ;
     RECT  61.524 66.929 63.018 67.085 ;
     RECT  9.396 66.929 9.414 67.091 ;
     RECT  10.908 67.019 11.322 67.091 ;
     RECT  68.472 66.989 68.49 67.181 ;
     RECT  50.148 66.929 52.974 67.229 ;
     RECT  50.148 67.229 51.75 67.277 ;
     RECT  52.524 67.229 52.974 67.277 ;
     RECT  55.872 66.845 60.498 67.277 ;
     RECT  61.524 67.085 61.65 67.277 ;
     RECT  62.64 67.085 63.018 67.277 ;
     RECT  63.792 66.929 64.098 67.277 ;
     RECT  65.988 67.019 66.726 67.373 ;
     RECT  65.988 67.373 66.006 67.469 ;
     RECT  50.148 67.277 51.57 67.805 ;
     RECT  57.348 67.277 58.806 67.805 ;
     RECT  59.724 67.277 59.778 67.805 ;
     RECT  62.82 67.277 63.018 68.333 ;
     RECT  50.148 67.805 51.462 68.381 ;
     RECT  62.82 68.333 62.838 68.381 ;
     RECT  52.524 67.277 52.542 68.429 ;
     RECT  55.872 67.277 56.25 68.429 ;
     RECT  59.724 67.805 59.742 68.429 ;
     RECT  61.524 67.277 61.578 68.429 ;
     RECT  50.472 68.381 50.922 68.909 ;
     RECT  57.348 67.805 58.374 68.909 ;
     RECT  50.472 68.909 50.886 69.005 ;
     RECT  56.232 68.429 56.25 69.005 ;
     RECT  57.78 68.909 58.374 69.005 ;
     RECT  60.084 68.875 60.102 69.005 ;
     RECT  61.524 68.429 61.542 69.005 ;
     RECT  63.792 67.277 63.81 69.005 ;
    LAYER M4 ;
     RECT  0.084 36.912 0.097 36.936 ;
     RECT  0.06 36.936 0.097 37.008 ;
     RECT  0.084 37.008 0.097 37.032 ;
     RECT  0.06 37.032 0.097 37.104 ;
     RECT  0.084 37.104 0.097 37.128 ;
     RECT  0.06 37.128 0.097 37.2 ;
     RECT  0.084 37.2 0.097 37.224 ;
     RECT  0.06 37.224 0.097 37.296 ;
     RECT  0.084 37.296 0.097 37.32 ;
     RECT  0.06 37.32 0.097 37.392 ;
     RECT  0.084 37.392 0.097 37.416 ;
     RECT  0.06 37.416 0.097 37.488 ;
     RECT  0.084 37.488 0.097 37.512 ;
     RECT  0.06 37.512 0.097 37.584 ;
     RECT  0.084 37.584 0.097 37.608 ;
     RECT  0.06 37.608 0.097 37.68 ;
     RECT  0.084 37.68 0.097 37.704 ;
     RECT  0.06 37.704 0.097 37.776 ;
     RECT  0.084 37.776 0.097 37.8 ;
     RECT  0.06 37.8 0.097 37.872 ;
     RECT  0.084 37.872 0.097 37.896 ;
     RECT  0.06 37.896 0.097 37.968 ;
     RECT  0.084 37.968 0.097 37.992 ;
     RECT  0.06 37.992 0.097 38.064 ;
     RECT  0.084 38.064 0.097 38.088 ;
     RECT  0.06 38.088 0.097 38.16 ;
     RECT  0.084 38.16 0.097 38.184 ;
     RECT  0.06 38.184 0.097 38.256 ;
     RECT  0.084 38.256 0.097 38.28 ;
     RECT  0.06 38.28 0.097 38.352 ;
     RECT  0.084 38.352 0.097 38.376 ;
     RECT  0.06 38.376 0.097 38.448 ;
     RECT  0.084 38.448 0.097 38.472 ;
     RECT  0.06 38.472 0.097 38.544 ;
     RECT  0.084 38.544 0.097 38.568 ;
     RECT  0.06 38.568 0.097 38.64 ;
     RECT  0.084 38.64 0.097 38.664 ;
     RECT  0.06 38.664 0.097 38.736 ;
     RECT  0.084 38.736 0.097 38.76 ;
     RECT  0.06 38.76 0.097 38.832 ;
     RECT  0.084 38.832 0.097 38.856 ;
     RECT  0.06 38.856 0.097 38.928 ;
     RECT  0.084 38.928 0.097 38.952 ;
     RECT  0.06 38.952 0.097 39.024 ;
     RECT  0.084 39.024 0.097 39.048 ;
     RECT  0.06 39.048 0.097 39.12 ;
     RECT  0.084 39.12 0.097 39.144 ;
     RECT  0.06 39.144 0.097 39.216 ;
     RECT  0.084 39.216 0.097 39.24 ;
     RECT  0.06 39.24 0.097 39.312 ;
     RECT  0.084 39.312 0.097 39.336 ;
     RECT  0.06 39.336 0.097 39.408 ;
     RECT  0.084 39.408 0.097 39.432 ;
     RECT  0.06 39.432 0.097 39.504 ;
     RECT  0.084 39.504 0.097 39.528 ;
     RECT  0.06 39.528 0.097 39.6 ;
     RECT  0.084 39.6 0.097 39.624 ;
     RECT  0.06 39.624 0.097 39.696 ;
     RECT  0.084 39.696 0.097 39.72 ;
     RECT  0.06 39.72 0.097 39.792 ;
     RECT  0.084 39.792 0.097 39.816 ;
     RECT  0.06 39.816 0.097 39.888 ;
     RECT  0.084 39.888 0.097 39.912 ;
     RECT  0.084 1.584 0.205 1.608 ;
     RECT  0.06 1.608 0.205 1.68 ;
     RECT  0.084 1.68 0.205 1.704 ;
     RECT  0.06 1.704 0.205 1.776 ;
     RECT  0.084 1.776 0.205 1.8 ;
     RECT  0.06 1.8 0.205 1.872 ;
     RECT  0.084 1.872 0.205 1.896 ;
     RECT  0.06 1.896 0.205 1.968 ;
     RECT  0.084 1.968 0.205 1.992 ;
     RECT  0.06 1.992 0.205 2.064 ;
     RECT  0.084 2.064 0.205 2.088 ;
     RECT  0.06 2.088 0.205 2.16 ;
     RECT  0.084 2.16 0.205 2.184 ;
     RECT  0.06 2.184 0.205 2.256 ;
     RECT  0.084 2.256 0.205 2.28 ;
     RECT  0.06 2.28 0.205 2.352 ;
     RECT  0.084 2.352 0.205 2.376 ;
     RECT  0.06 2.376 0.205 2.448 ;
     RECT  0.084 2.448 0.205 2.472 ;
     RECT  0.06 2.472 0.205 2.544 ;
     RECT  0.084 2.544 0.205 2.568 ;
     RECT  0.06 2.568 0.205 2.64 ;
     RECT  0.084 2.64 0.205 2.664 ;
     RECT  0.06 2.664 0.205 2.736 ;
     RECT  0.084 2.736 0.205 2.76 ;
     RECT  0.06 2.76 0.205 2.832 ;
     RECT  0.084 2.832 0.205 2.856 ;
     RECT  0.06 2.856 0.205 2.928 ;
     RECT  0.084 2.928 0.205 2.952 ;
     RECT  0.06 2.952 0.205 3.024 ;
     RECT  0.084 3.024 0.205 3.048 ;
     RECT  0.06 3.048 0.205 3.12 ;
     RECT  0.084 3.12 0.205 3.144 ;
     RECT  0.06 3.144 0.205 3.216 ;
     RECT  0.084 3.216 0.205 3.24 ;
     RECT  0.06 3.24 0.205 3.312 ;
     RECT  0.084 3.312 0.205 3.336 ;
     RECT  0.06 3.336 0.205 3.408 ;
     RECT  0.084 3.408 0.205 3.432 ;
     RECT  0.06 3.432 0.205 3.504 ;
     RECT  0.084 3.504 0.205 3.528 ;
     RECT  0.06 3.528 0.205 3.6 ;
     RECT  0.084 3.6 0.205 3.624 ;
     RECT  0.06 3.624 0.205 3.696 ;
     RECT  0.084 3.696 0.205 3.72 ;
     RECT  0.06 3.72 0.205 3.792 ;
     RECT  0.084 3.792 0.205 3.816 ;
     RECT  0.06 3.816 0.205 3.888 ;
     RECT  0.084 3.888 0.205 3.912 ;
     RECT  0.06 3.912 0.205 3.984 ;
     RECT  0.084 3.984 0.205 4.008 ;
     RECT  0.06 4.008 0.205 4.08 ;
     RECT  0.084 4.08 0.205 4.104 ;
     RECT  0.06 4.104 0.205 4.176 ;
     RECT  0.084 4.176 0.205 4.2 ;
     RECT  0.06 4.2 0.205 4.272 ;
     RECT  0.084 4.272 0.205 4.296 ;
     RECT  0.06 4.296 0.205 4.368 ;
     RECT  0.084 4.368 0.205 4.392 ;
     RECT  0.06 4.392 0.205 4.464 ;
     RECT  0.084 4.464 0.205 4.488 ;
     RECT  0.06 4.488 0.205 4.56 ;
     RECT  0.084 4.56 0.205 4.584 ;
     RECT  0.06 4.584 0.205 4.656 ;
     RECT  0.084 4.656 0.205 4.68 ;
     RECT  0.06 4.68 0.205 4.752 ;
     RECT  0.084 4.752 0.205 4.776 ;
     RECT  0.06 4.776 0.205 4.848 ;
     RECT  0.084 4.848 0.205 4.872 ;
     RECT  0.06 4.872 0.205 4.944 ;
     RECT  0.084 4.944 0.205 4.968 ;
     RECT  0.06 4.968 0.205 5.04 ;
     RECT  0.084 5.04 0.205 5.064 ;
     RECT  0.06 5.064 0.205 5.136 ;
     RECT  0.084 5.136 0.205 5.16 ;
     RECT  0.06 5.16 0.205 5.232 ;
     RECT  0.084 5.232 0.205 5.256 ;
     RECT  0.06 5.256 0.205 5.328 ;
     RECT  0.084 5.328 0.205 5.352 ;
     RECT  0.06 5.352 0.205 5.424 ;
     RECT  0.084 5.424 0.205 5.448 ;
     RECT  0.06 5.448 0.205 5.52 ;
     RECT  0.084 5.52 0.205 5.544 ;
     RECT  0.06 5.544 0.205 5.616 ;
     RECT  0.084 5.616 0.205 5.64 ;
     RECT  0.06 5.64 0.205 5.712 ;
     RECT  0.084 5.712 0.205 5.736 ;
     RECT  0.06 5.736 0.205 5.808 ;
     RECT  0.084 5.808 0.205 5.832 ;
     RECT  0.06 5.832 0.205 5.904 ;
     RECT  0.084 5.904 0.205 5.928 ;
     RECT  0.06 5.928 0.205 6 ;
     RECT  0.084 6 0.205 6.024 ;
     RECT  0.06 6.024 0.205 6.096 ;
     RECT  0.084 6.096 0.205 6.12 ;
     RECT  0.06 6.12 0.205 6.192 ;
     RECT  0.084 6.192 0.205 6.216 ;
     RECT  0.06 6.216 0.205 6.288 ;
     RECT  0.084 6.288 0.205 6.312 ;
     RECT  0.06 6.312 0.205 6.384 ;
     RECT  0.084 6.384 0.205 6.408 ;
     RECT  0.06 6.408 0.205 6.48 ;
     RECT  0.084 6.48 0.205 6.504 ;
     RECT  0.06 6.504 0.205 6.576 ;
     RECT  0.084 6.576 0.205 6.6 ;
     RECT  0.06 6.6 0.205 6.672 ;
     RECT  0.084 6.672 0.205 6.696 ;
     RECT  0.06 6.696 0.205 6.768 ;
     RECT  0.084 6.768 0.205 6.792 ;
     RECT  0.06 6.792 0.205 6.864 ;
     RECT  0.084 6.864 0.205 6.888 ;
     RECT  0.06 6.888 0.205 6.96 ;
     RECT  0.084 6.96 0.205 6.984 ;
     RECT  0.06 6.984 0.205 7.056 ;
     RECT  0.084 7.056 0.205 7.08 ;
     RECT  0.06 7.08 0.205 7.152 ;
     RECT  0.084 7.152 0.205 7.176 ;
     RECT  0.06 7.176 0.205 7.248 ;
     RECT  0.084 7.248 0.205 7.272 ;
     RECT  0.06 7.272 0.205 7.344 ;
     RECT  0.084 7.344 0.205 7.368 ;
     RECT  0.06 7.368 0.205 7.44 ;
     RECT  0.084 7.44 0.205 7.464 ;
     RECT  0.06 7.464 0.205 7.536 ;
     RECT  0.084 7.536 0.205 7.56 ;
     RECT  0.06 7.56 0.205 7.632 ;
     RECT  0.084 7.632 0.205 7.656 ;
     RECT  0.06 7.656 0.205 7.728 ;
     RECT  0.084 7.728 0.205 7.752 ;
     RECT  0.06 7.752 0.205 7.824 ;
     RECT  0.084 7.824 0.205 7.848 ;
     RECT  0.06 7.848 0.205 7.92 ;
     RECT  0.084 7.92 0.205 7.944 ;
     RECT  0.06 7.944 0.205 8.016 ;
     RECT  0.084 8.016 0.205 8.04 ;
     RECT  0.06 8.04 0.205 8.112 ;
     RECT  0.084 8.112 0.205 8.136 ;
     RECT  0.06 8.136 0.205 8.208 ;
     RECT  0.084 8.208 0.205 8.232 ;
     RECT  0.06 8.232 0.205 8.304 ;
     RECT  0.084 8.304 0.205 8.328 ;
     RECT  0.06 8.328 0.205 8.4 ;
     RECT  0.084 8.4 0.205 8.424 ;
     RECT  0.06 8.424 0.205 8.496 ;
     RECT  0.084 8.496 0.205 8.52 ;
     RECT  0.06 8.52 0.205 8.592 ;
     RECT  0.084 8.592 0.205 8.616 ;
     RECT  0.06 8.616 0.205 8.688 ;
     RECT  0.084 8.688 0.205 8.712 ;
     RECT  0.06 8.712 0.205 8.784 ;
     RECT  0.084 8.784 0.205 8.808 ;
     RECT  0.06 8.808 0.205 8.88 ;
     RECT  0.084 8.88 0.205 8.904 ;
     RECT  0.06 8.904 0.205 8.976 ;
     RECT  0.084 8.976 0.205 9 ;
     RECT  0.06 9 0.205 9.072 ;
     RECT  0.084 9.072 0.205 9.096 ;
     RECT  0.06 9.096 0.205 9.168 ;
     RECT  0.084 9.168 0.205 9.192 ;
     RECT  0.06 9.192 0.205 9.264 ;
     RECT  0.084 9.264 0.205 9.288 ;
     RECT  0.06 9.288 0.205 9.36 ;
     RECT  0.084 9.36 0.205 9.384 ;
     RECT  0.06 9.384 0.205 9.456 ;
     RECT  0.084 9.456 0.205 9.48 ;
     RECT  0.06 9.48 0.205 9.552 ;
     RECT  0.084 9.552 0.205 9.576 ;
     RECT  0.06 9.576 0.205 9.648 ;
     RECT  0.084 9.648 0.205 9.672 ;
     RECT  0.06 9.672 0.205 9.744 ;
     RECT  0.084 9.744 0.205 9.768 ;
     RECT  0.06 9.768 0.205 9.84 ;
     RECT  0.084 9.84 0.205 9.864 ;
     RECT  0.06 9.864 0.205 9.936 ;
     RECT  0.084 9.936 0.205 9.96 ;
     RECT  0.06 9.96 0.205 10.032 ;
     RECT  0.084 10.032 0.205 10.056 ;
     RECT  0.06 10.056 0.205 10.128 ;
     RECT  0.084 10.128 0.205 10.152 ;
     RECT  0.06 10.152 0.205 10.224 ;
     RECT  0.084 10.224 0.205 10.248 ;
     RECT  0.06 10.248 0.205 10.32 ;
     RECT  0.084 10.32 0.205 10.344 ;
     RECT  0.06 10.344 0.205 10.416 ;
     RECT  0.084 10.416 0.205 10.44 ;
     RECT  0.06 10.44 0.205 10.512 ;
     RECT  0.084 10.512 0.205 10.536 ;
     RECT  0.06 10.536 0.205 10.608 ;
     RECT  0.084 10.608 0.205 10.632 ;
     RECT  0.06 10.632 0.205 10.704 ;
     RECT  0.084 10.704 0.205 10.728 ;
     RECT  0.06 10.728 0.205 11.568 ;
     RECT  0.084 11.568 0.205 11.592 ;
     RECT  0.06 11.592 0.205 11.664 ;
     RECT  0.084 11.664 0.205 11.688 ;
     RECT  0.06 11.688 0.205 11.76 ;
     RECT  0.084 11.76 0.205 11.784 ;
     RECT  0.06 11.784 0.205 11.856 ;
     RECT  0.084 11.856 0.205 11.88 ;
     RECT  0.06 11.88 0.205 11.952 ;
     RECT  0.084 11.952 0.205 11.976 ;
     RECT  0.06 11.976 0.205 12.048 ;
     RECT  0.084 12.048 0.205 12.072 ;
     RECT  0.06 12.072 0.205 12.144 ;
     RECT  0.084 12.144 0.205 12.168 ;
     RECT  0.06 12.168 0.205 12.24 ;
     RECT  0.084 12.24 0.205 12.264 ;
     RECT  0.06 12.264 0.205 12.336 ;
     RECT  0.084 12.336 0.205 12.36 ;
     RECT  0.06 12.36 0.205 12.432 ;
     RECT  0.084 12.432 0.205 12.456 ;
     RECT  0.06 12.456 0.205 12.528 ;
     RECT  0.084 12.528 0.205 12.552 ;
     RECT  0.06 12.552 0.205 12.624 ;
     RECT  0.084 12.624 0.205 12.648 ;
     RECT  0.06 12.648 0.205 12.72 ;
     RECT  0.084 12.72 0.205 12.744 ;
     RECT  0.06 12.744 0.205 12.816 ;
     RECT  0.084 12.816 0.205 12.84 ;
     RECT  0.06 12.84 0.205 12.912 ;
     RECT  0.084 12.912 0.205 12.936 ;
     RECT  0.06 12.936 0.205 13.008 ;
     RECT  0.084 13.008 0.205 13.032 ;
     RECT  0.06 13.032 0.205 13.104 ;
     RECT  0.084 13.104 0.205 13.128 ;
     RECT  0.06 13.128 0.205 13.2 ;
     RECT  0.084 13.2 0.205 13.224 ;
     RECT  0.06 13.224 0.205 13.296 ;
     RECT  0.084 13.296 0.205 13.32 ;
     RECT  0.06 13.32 0.205 13.392 ;
     RECT  0.084 13.392 0.205 13.416 ;
     RECT  0.06 13.416 0.205 13.488 ;
     RECT  0.084 13.488 0.205 13.512 ;
     RECT  0.06 13.512 0.205 13.584 ;
     RECT  0.084 13.584 0.205 13.608 ;
     RECT  0.06 13.608 0.205 13.68 ;
     RECT  0.084 13.68 0.205 13.704 ;
     RECT  0.06 13.704 0.205 13.776 ;
     RECT  0.084 13.776 0.205 13.8 ;
     RECT  0.06 13.8 0.205 13.872 ;
     RECT  0.084 13.872 0.205 13.896 ;
     RECT  0.06 13.896 0.205 13.968 ;
     RECT  0.084 13.968 0.205 13.992 ;
     RECT  0.06 13.992 0.205 14.064 ;
     RECT  0.084 14.064 0.205 14.088 ;
     RECT  0.06 14.088 0.205 14.16 ;
     RECT  0.084 14.16 0.205 14.184 ;
     RECT  0.06 14.184 0.205 14.256 ;
     RECT  0.084 14.256 0.205 14.28 ;
     RECT  0.06 14.28 0.205 14.352 ;
     RECT  0.084 14.352 0.205 14.376 ;
     RECT  0.06 14.376 0.205 14.448 ;
     RECT  0.084 14.448 0.205 14.472 ;
     RECT  0.06 14.472 0.205 14.544 ;
     RECT  0.084 14.544 0.205 14.568 ;
     RECT  0.205 1.584 1.181 14.664 ;
     RECT  0.084 41.712 2.401 41.736 ;
     RECT  0.06 41.736 2.401 41.808 ;
     RECT  0.084 41.808 2.401 41.832 ;
     RECT  0.06 41.832 2.401 41.904 ;
     RECT  0.084 41.904 2.401 41.928 ;
     RECT  0.06 41.928 2.401 42 ;
     RECT  0.084 42 2.401 42.024 ;
     RECT  0.06 42.024 2.401 42.096 ;
     RECT  0.084 42.096 2.401 42.12 ;
     RECT  0.06 42.12 2.401 42.192 ;
     RECT  0.084 42.192 2.401 42.216 ;
     RECT  0.06 42.216 2.401 42.288 ;
     RECT  0.084 42.288 2.401 42.312 ;
     RECT  0.06 42.312 2.401 42.384 ;
     RECT  0.084 42.384 2.401 42.408 ;
     RECT  0.06 42.408 2.401 42.48 ;
     RECT  0.084 42.48 2.401 42.504 ;
     RECT  0.06 42.504 2.401 42.576 ;
     RECT  0.084 42.576 2.401 42.6 ;
     RECT  0.06 42.6 2.401 42.672 ;
     RECT  0.084 42.672 2.401 42.696 ;
     RECT  0.06 42.696 2.401 42.768 ;
     RECT  0.084 42.768 2.401 42.792 ;
     RECT  0.06 42.792 2.401 42.864 ;
     RECT  0.084 42.864 2.401 42.888 ;
     RECT  0.06 42.888 2.401 42.96 ;
     RECT  0.084 42.96 2.401 42.984 ;
     RECT  1.181 1.68 2.408 14.664 ;
     RECT  2.365 24.48 2.408 24.504 ;
     RECT  2.365 29.76 2.408 29.784 ;
     RECT  2.401 35.28 2.408 35.304 ;
     RECT  0.097 36.912 2.408 40.056 ;
     RECT  2.401 41.376 2.408 43.032 ;
     RECT  2.365 45.696 2.408 45.72 ;
     RECT  2.401 50.64 2.408 50.664 ;
     RECT  2.365 52.176 2.408 52.2 ;
     RECT  2.365 55.968 2.408 55.992 ;
     RECT  2.401 57.024 2.408 57.048 ;
     RECT  2.365 58.128 2.408 58.152 ;
     RECT  2.408 1.68 2.512 66.972 ;
     RECT  2.512 1.68 2.704 66.702 ;
     RECT  2.704 35.28 2.765 43.8 ;
     RECT  2.704 26.064 2.867 26.76 ;
     RECT  2.704 50.4 2.867 52.2 ;
     RECT  2.765 35.28 2.873 42.6 ;
     RECT  2.704 55.92 2.873 55.992 ;
     RECT  2.873 37.584 2.945 42.6 ;
     RECT  2.945 37.584 2.981 41.4 ;
     RECT  2.704 47.04 2.981 48.648 ;
     RECT  2.704 1.68 3.089 14.664 ;
     RECT  2.981 37.68 3.089 41.4 ;
     RECT  3.089 37.68 3.161 39.576 ;
     RECT  2.704 45.648 3.161 45.72 ;
     RECT  2.704 20.688 3.299 21.096 ;
     RECT  2.945 42.576 3.305 42.6 ;
     RECT  2.867 50.4 3.305 51.624 ;
     RECT  3.161 37.968 3.341 39.576 ;
     RECT  2.704 27.84 3.395 31.368 ;
     RECT  2.873 35.28 3.413 36.024 ;
     RECT  2.704 63.792 3.443 63.816 ;
     RECT  2.704 16.032 3.485 16.056 ;
     RECT  2.704 57.024 3.521 57.048 ;
     RECT  2.704 58.128 3.521 59.448 ;
     RECT  2.704 64.944 3.635 66.6 ;
     RECT  3.521 58.128 3.685 58.152 ;
     RECT  2.981 47.04 3.701 47.736 ;
     RECT  3.685 57.456 3.772 58.152 ;
     RECT  2.704 17.04 3.805 17.064 ;
     RECT  2.704 19.344 3.829 19.368 ;
     RECT  3.829 18.816 3.875 19.368 ;
     RECT  3.395 28.416 3.875 31.368 ;
     RECT  2.704 22.752 3.877 22.776 ;
     RECT  3.701 47.04 3.913 47.064 ;
     RECT  3.413 35.52 3.949 36.024 ;
     RECT  3.161 45.648 3.949 45.672 ;
     RECT  2.765 43.776 3.973 43.8 ;
     RECT  3.949 44.976 3.973 45.672 ;
     RECT  3.805 17.04 3.985 17.64 ;
     RECT  3.805 54.096 4.021 54.12 ;
     RECT  2.704 62.736 4.021 62.76 ;
     RECT  3.089 40.848 4.025 41.4 ;
     RECT  3.949 35.52 4.061 36.12 ;
     RECT  2.704 24.432 4.093 24.504 ;
     RECT  2.867 26.736 4.093 26.76 ;
     RECT  3.985 16.512 4.169 17.64 ;
     RECT  3.875 28.8 4.169 31.368 ;
     RECT  2.704 33.984 4.201 34.008 ;
     RECT  3.949 48.816 4.237 48.84 ;
     RECT  4.021 53.952 4.241 54.84 ;
     RECT  2.873 55.92 4.241 55.944 ;
     RECT  3.877 21.36 4.273 22.776 ;
     RECT  4.093 23.904 4.273 24.504 ;
     RECT  2.704 61.104 4.313 61.128 ;
     RECT  3.341 37.968 4.405 39.384 ;
     RECT  4.273 21.36 4.421 24.504 ;
     RECT  4.169 16.512 4.525 16.536 ;
     RECT  4.405 37.872 4.529 39.384 ;
     RECT  3.772 58.128 4.549 58.152 ;
     RECT  3.521 59.424 4.549 59.448 ;
     RECT  4.169 28.8 4.565 30.936 ;
     RECT  4.421 23.28 4.595 24.504 ;
     RECT  4.093 26.112 4.601 26.76 ;
     RECT  3.875 18.816 4.637 18.84 ;
     RECT  4.061 35.52 4.637 35.544 ;
     RECT  4.525 16.32 4.669 16.536 ;
     RECT  2.704 32.448 4.669 32.472 ;
     RECT  4.529 38.16 4.669 39.384 ;
     RECT  3.635 64.944 4.673 65.544 ;
     RECT  4.669 15.456 4.705 16.536 ;
     RECT  3.089 1.68 4.709 13.944 ;
     RECT  4.021 62.208 4.709 62.76 ;
     RECT  4.669 31.92 4.741 32.472 ;
     RECT  4.201 33.648 4.741 34.008 ;
     RECT  4.421 21.36 4.745 22.248 ;
     RECT  4.741 31.92 4.753 34.008 ;
     RECT  4.709 1.968 4.777 13.944 ;
     RECT  4.705 14.976 4.777 16.536 ;
     RECT  4.669 38.16 4.777 39.48 ;
     RECT  4.057 40.656 4.777 40.68 ;
     RECT  4.237 48.48 4.921 48.84 ;
     RECT  3.973 43.776 4.925 45.672 ;
     RECT  4.601 26.688 4.957 26.76 ;
     RECT  4.057 41.76 4.957 42.12 ;
     RECT  4.921 48.48 4.981 48.888 ;
     RECT  4.595 23.904 4.997 24.504 ;
     RECT  3.305 50.4 5.027 51.288 ;
     RECT  4.549 58.128 5.065 59.448 ;
     RECT  4.981 48.48 5.068 49.368 ;
     RECT  4.957 41.76 5.101 42.792 ;
     RECT  4.925 43.776 5.101 45 ;
     RECT  5.068 48.48 5.105 48.888 ;
     RECT  4.673 64.944 5.132 64.968 ;
     RECT  4.169 17.616 5.141 17.64 ;
     RECT  4.957 26.688 5.209 27.72 ;
     RECT  4.565 28.8 5.209 30.84 ;
     RECT  5.027 50.688 5.213 51.288 ;
     RECT  5.132 64.128 5.219 64.968 ;
     RECT  5.065 57.744 5.253 59.448 ;
     RECT  4.997 24.144 5.317 24.504 ;
     RECT  4.364 36.864 5.317 36.888 ;
     RECT  5.253 57.456 5.353 59.448 ;
     RECT  4.453 60.432 5.353 60.456 ;
     RECT  4.745 21.36 5.357 22.2 ;
     RECT  5.353 57.456 5.363 60.456 ;
     RECT  3.913 46.752 5.389 47.064 ;
     RECT  4.709 62.496 5.411 62.76 ;
     RECT  4.489 52.56 5.425 52.584 ;
     RECT  4.241 53.952 5.425 54.12 ;
     RECT  4.777 1.968 5.429 16.536 ;
     RECT  5.209 26.688 5.429 30.84 ;
     RECT  5.425 52.56 5.497 54.12 ;
     RECT  4.777 38.16 5.5 40.68 ;
     RECT  5.429 2.208 5.501 16.536 ;
     RECT  5.497 52.512 5.533 54.12 ;
     RECT  4.273 55.2 5.533 55.272 ;
     RECT  5.363 58.656 5.533 60.456 ;
     RECT  5.429 26.688 5.537 28.824 ;
     RECT  5.533 52.512 5.537 55.272 ;
     RECT  5.5 38.496 5.569 40.68 ;
     RECT  5.101 41.76 5.569 45 ;
     RECT  5.317 24.144 5.573 24.792 ;
     RECT  5.537 27.888 5.573 28.824 ;
     RECT  4.753 32.16 5.605 34.008 ;
     RECT  5.411 62.496 5.609 62.664 ;
     RECT  5.537 54.096 5.645 55.272 ;
     RECT  5.389 46.704 5.677 47.064 ;
     RECT  5.645 55.2 5.677 55.272 ;
     RECT  5.363 57.456 5.681 57.576 ;
     RECT  5.609 62.64 5.753 62.664 ;
     RECT  5.533 58.656 5.825 60.744 ;
     RECT  5.569 38.496 5.897 45 ;
     RECT  5.501 2.4 5.929 16.536 ;
     RECT  5.317 36.864 5.965 37.08 ;
     RECT  5.677 55.2 5.965 55.32 ;
     RECT  5.605 32.16 5.969 34.104 ;
     RECT  5.537 52.512 5.969 53.016 ;
     RECT  5.537 26.688 6.109 26.904 ;
     RECT  5.219 64.272 6.109 64.968 ;
     RECT  5.105 48.48 6.14 48.84 ;
     RECT  6.109 64.272 6.145 65.016 ;
     RECT  3.635 66.576 6.149 66.6 ;
     RECT  5.357 21.984 6.181 22.2 ;
     RECT  5.573 24.144 6.185 24.168 ;
     RECT  6.14 48.24 6.227 48.84 ;
     RECT  5.825 59.136 6.293 60.744 ;
     RECT  6.145 64.272 6.325 65.496 ;
     RECT  6.293 59.136 6.329 59.88 ;
     RECT  5.965 36.864 6.469 37.32 ;
     RECT  6.325 63.744 6.509 65.496 ;
     RECT  5.929 2.4 6.517 16.872 ;
     RECT  6.517 2.4 6.653 17.112 ;
     RECT  6.181 21.984 6.685 22.344 ;
     RECT  6.509 63.744 6.685 65.448 ;
     RECT  6.685 62.976 6.767 65.448 ;
     RECT  6.685 21.984 6.793 22.776 ;
     RECT  5.573 28.8 6.793 28.824 ;
     RECT  5.969 33.888 6.793 34.104 ;
     RECT  6.793 28.8 6.829 29.016 ;
     RECT  6.793 33.888 6.829 34.44 ;
     RECT  4.705 35.472 6.829 35.496 ;
     RECT  5.677 46.704 6.829 47.208 ;
     RECT  6.227 48.48 6.829 48.84 ;
     RECT  5.929 56.832 6.865 57.048 ;
     RECT  5.429 30.576 6.937 30.84 ;
     RECT  6.829 48.48 7.004 49.128 ;
     RECT  5.213 50.688 7.004 51.192 ;
     RECT  5.965 55.2 7.045 55.752 ;
     RECT  6.829 28.368 7.117 29.016 ;
     RECT  6.937 30.576 7.117 30.984 ;
     RECT  7.004 48.48 7.117 51.192 ;
     RECT  6.865 56.832 7.117 57.624 ;
     RECT  5.897 38.496 7.225 44.952 ;
     RECT  6.829 46.464 7.225 47.208 ;
     RECT  6.109 26.304 7.261 26.904 ;
     RECT  6.757 23.856 7.297 23.88 ;
     RECT  6.469 36.864 7.297 37.416 ;
     RECT  7.225 38.496 7.297 47.208 ;
     RECT  7.117 48.48 7.333 51.768 ;
     RECT  5.969 52.944 7.333 53.016 ;
     RECT  7.117 56.832 7.333 58.152 ;
     RECT  6.329 59.136 7.333 59.832 ;
     RECT  7.297 23.856 7.369 23.928 ;
     RECT  6.649 25.2 7.369 25.224 ;
     RECT  7.333 48.48 7.369 53.016 ;
     RECT  5.645 54.096 7.369 54.12 ;
     RECT  7.369 23.856 7.381 25.224 ;
     RECT  7.261 26.304 7.381 27.096 ;
     RECT  6.829 33.888 7.513 35.496 ;
     RECT  7.297 36.864 7.513 47.208 ;
     RECT  7.045 55.104 7.585 55.752 ;
     RECT  7.333 56.832 7.585 59.832 ;
     RECT  6.793 20.4 7.729 22.776 ;
     RECT  7.381 23.856 7.729 27.096 ;
     RECT  7.261 19.344 7.765 19.368 ;
     RECT  6.653 2.4 7.808 16.872 ;
     RECT  7.765 19.296 7.808 19.368 ;
     RECT  7.729 20.4 7.808 27.096 ;
     RECT  7.117 28.368 7.808 30.984 ;
     RECT  5.969 32.16 7.808 32.52 ;
     RECT  7.513 33.6 7.808 47.208 ;
     RECT  7.369 48.48 7.808 54.12 ;
     RECT  7.585 55.104 7.808 59.832 ;
     RECT  6.721 61.2 7.808 61.224 ;
     RECT  6.767 62.304 7.808 65.448 ;
     RECT  7.808 2.148 7.912 66.972 ;
     RECT  7.912 2.4 7.949 66.744 ;
     RECT  7.949 2.418 8.104 66.744 ;
     RECT  8.104 2.784 8.201 15.96 ;
     RECT  8.201 2.784 8.237 3.048 ;
     RECT  8.104 24.624 8.237 43.128 ;
     RECT  8.237 24.624 8.243 34.392 ;
     RECT  8.243 32.496 8.273 34.392 ;
     RECT  8.243 24.624 8.417 31.32 ;
     RECT  8.104 44.4 8.531 47.352 ;
     RECT  8.417 25.104 8.561 31.32 ;
     RECT  8.237 35.376 8.597 43.128 ;
     RECT  8.104 62.448 8.597 66.744 ;
     RECT  8.273 32.688 8.633 34.392 ;
     RECT  8.531 44.4 8.633 45.144 ;
     RECT  8.597 35.376 8.741 40.872 ;
     RECT  8.104 48.48 8.849 51.816 ;
     RECT  8.561 25.104 8.915 28.584 ;
     RECT  8.915 25.104 8.956 28.536 ;
     RECT  8.956 25.104 8.957 26.904 ;
     RECT  8.597 42.144 9.065 43.128 ;
     RECT  9.065 43.104 9.097 43.128 ;
     RECT  8.633 44.4 9.097 45 ;
     RECT  8.531 46.512 9.097 47.352 ;
     RECT  8.849 49.008 9.097 51.816 ;
     RECT  8.597 62.448 9.097 65.544 ;
     RECT  8.597 66.576 9.107 66.744 ;
     RECT  8.104 21.12 9.133 23.304 ;
     RECT  8.201 4.512 9.137 15.96 ;
     RECT  8.561 29.664 9.137 31.32 ;
     RECT  9.097 61.92 9.137 65.544 ;
     RECT  9.107 66.624 9.173 66.744 ;
     RECT  9.137 61.92 9.209 65.448 ;
     RECT  9.137 4.512 9.212 13.848 ;
     RECT  8.104 52.848 9.253 58.776 ;
     RECT  8.104 59.808 9.253 59.832 ;
     RECT  9.137 29.664 9.281 30.6 ;
     RECT  9.212 4.272 9.299 13.848 ;
     RECT  8.237 2.784 9.317 2.856 ;
     RECT  9.137 14.928 9.317 15.96 ;
     RECT  9.281 29.664 9.317 30.504 ;
     RECT  8.633 32.736 9.349 34.392 ;
     RECT  8.741 35.376 9.349 35.4 ;
     RECT  9.209 61.92 9.353 65.256 ;
     RECT  9.133 20.928 9.385 23.304 ;
     RECT  8.104 18.768 9.389 19.368 ;
     RECT  8.104 17.664 9.421 17.688 ;
     RECT  9.299 5.088 9.497 13.848 ;
     RECT  8.956 28.512 9.539 28.536 ;
     RECT  9.317 29.76 9.58 30.504 ;
     RECT  9.589 19.824 9.601 19.848 ;
     RECT  9.385 20.928 9.601 23.544 ;
     RECT  9.097 46.512 9.601 47.784 ;
     RECT  9.497 5.088 9.605 11.4 ;
     RECT  9.605 8.64 9.677 11.4 ;
     RECT  9.421 17.664 9.677 18.408 ;
     RECT  9.601 19.824 9.677 23.544 ;
     RECT  9.349 32.736 9.713 35.4 ;
     RECT  9.713 32.736 9.745 33.336 ;
     RECT  9.605 5.088 9.779 7.224 ;
     RECT  9.097 49.008 9.781 51.864 ;
     RECT  9.253 52.848 9.781 59.832 ;
     RECT  9.677 20.352 9.821 23.544 ;
     RECT  9.713 34.368 9.821 35.4 ;
     RECT  9.601 45.984 9.821 47.784 ;
     RECT  9.779 5.472 9.893 7.224 ;
     RECT  9.781 49.008 9.925 59.832 ;
     RECT  9.893 5.472 9.929 7.128 ;
     RECT  9.353 61.92 9.929 64.92 ;
     RECT  8.957 25.104 9.961 25.704 ;
     RECT  9.097 43.104 9.961 45 ;
     RECT  9.821 45.984 9.961 47.112 ;
     RECT  9.677 17.664 10.001 18.312 ;
     RECT  9.745 32.256 10.001 33.336 ;
     RECT  10.001 32.256 10.037 33.192 ;
     RECT  9.929 6 10.073 7.128 ;
     RECT  9.677 8.64 10.073 10.392 ;
     RECT  10.037 32.256 10.181 33.096 ;
     RECT  9.961 43.104 10.213 47.112 ;
     RECT  8.741 36.384 10.217 40.872 ;
     RECT  9.925 48.912 10.249 59.832 ;
     RECT  9.733 3.936 10.253 3.96 ;
     RECT  9.821 21.12 10.285 23.544 ;
     RECT  9.961 24.768 10.285 25.704 ;
     RECT  10.073 8.88 10.289 10.392 ;
     RECT  9.677 11.376 10.289 11.4 ;
     RECT  9.821 34.608 10.289 35.4 ;
     RECT  9.929 63.12 10.321 64.92 ;
     RECT  10.261 28.128 10.348 28.152 ;
     RECT  8.957 26.784 10.353 26.904 ;
     RECT  9.173 66.72 10.361 66.744 ;
     RECT  9.497 12.48 10.433 13.848 ;
     RECT  10.321 63.12 10.465 65.064 ;
     RECT  9.317 2.832 10.469 2.856 ;
     RECT  9.58 30.096 10.469 30.504 ;
     RECT  10.285 21.12 10.549 25.704 ;
     RECT  10.217 36.816 10.573 40.872 ;
     RECT  10.213 42.144 10.573 47.112 ;
     RECT  10.289 34.608 10.577 35.304 ;
     RECT  10.573 36.816 10.613 47.112 ;
     RECT  9.317 14.928 10.645 15.432 ;
     RECT  10.249 48.912 10.681 60.408 ;
     RECT  10.465 63.12 10.685 65.496 ;
     RECT  10.613 36.864 10.693 47.112 ;
     RECT  10.645 14.928 10.7 15.528 ;
     RECT  10.181 32.256 10.717 32.328 ;
     RECT  10.469 30.192 10.757 30.504 ;
     RECT  10.7 14.928 10.787 15.72 ;
     RECT  10.433 12.72 10.789 13.848 ;
     RECT  10.787 14.928 10.789 15.528 ;
     RECT  10.693 36.864 10.865 39.624 ;
     RECT  10.549 21.12 10.933 25.752 ;
     RECT  10.353 26.784 10.933 26.808 ;
     RECT  10.249 61.632 10.933 61.656 ;
     RECT  10.717 31.536 10.937 32.328 ;
     RECT  10.865 36.864 10.937 39.288 ;
     RECT  10.001 18 10.973 18.312 ;
     RECT  10.073 6 11.009 6.552 ;
     RECT  10.973 18.288 11.041 18.312 ;
     RECT  10.681 48.096 11.075 60.408 ;
     RECT  10.937 36.96 11.081 39.288 ;
     RECT  10.693 41.184 11.113 47.112 ;
     RECT  11.075 48.096 11.113 60.36 ;
     RECT  10.789 12.72 11.117 15.528 ;
     RECT  10.289 8.88 11.153 9.72 ;
     RECT  10.757 30.48 11.228 30.504 ;
     RECT  10.937 31.536 11.228 32.28 ;
     RECT  10.825 20.064 11.297 20.088 ;
     RECT  11.228 30.48 11.315 32.28 ;
     RECT  10.933 21.12 11.372 26.808 ;
     RECT  11.117 12.912 11.405 15.384 ;
     RECT  11.113 41.184 11.411 60.36 ;
     RECT  11.411 41.184 11.441 48.456 ;
     RECT  10.933 61.536 11.441 61.656 ;
     RECT  11.372 21.12 11.459 27.24 ;
     RECT  11.405 14.592 11.477 15.384 ;
     RECT  10.717 29.088 11.513 29.112 ;
     RECT  10.685 63.264 11.581 65.496 ;
     RECT  11.005 4.656 11.585 4.68 ;
     RECT  11.081 37.008 11.585 39.288 ;
     RECT  11.041 18.288 11.617 18.84 ;
     RECT  11.153 9.072 11.653 9.72 ;
     RECT  11.459 21.12 11.653 27.096 ;
     RECT  11.653 20.736 11.657 27.096 ;
     RECT  11.411 49.536 11.657 60.36 ;
     RECT  11.653 9.072 11.699 9.816 ;
     RECT  11.441 42.096 11.701 48.456 ;
     RECT  11.701 42.144 11.74 48.456 ;
     RECT  10.577 34.608 11.761 35.208 ;
     RECT  11.581 63.264 11.833 65.832 ;
     RECT  11.657 20.736 11.837 25.848 ;
     RECT  11.837 20.736 11.873 23.352 ;
     RECT  11.657 50.016 11.873 60.36 ;
     RECT  11.905 10.896 11.977 10.92 ;
     RECT  11.761 17.232 12.049 17.256 ;
     RECT  11.617 18.288 12.049 19.368 ;
     RECT  11.977 10.8 12.083 10.92 ;
     RECT  11.477 14.64 12.089 15.384 ;
     RECT  11.873 20.976 12.125 23.352 ;
     RECT  11.761 34.08 12.157 35.208 ;
     RECT  11.833 62.304 12.161 65.832 ;
     RECT  12.157 34.08 12.229 35.928 ;
     RECT  11.009 6 12.265 6.264 ;
     RECT  11.869 7.392 12.265 7.416 ;
     RECT  12.229 33.6 12.325 35.928 ;
     RECT  11.585 37.008 12.325 39.048 ;
     RECT  11.761 29.04 12.337 29.064 ;
     RECT  11.315 30.48 12.517 30.744 ;
     RECT  11.315 31.92 12.517 32.28 ;
     RECT  11.657 27.072 12.553 27.096 ;
     RECT  12.481 4.176 12.589 4.2 ;
     RECT  12.517 30.48 12.613 32.28 ;
     RECT  12.553 27.072 12.697 27.192 ;
     RECT  12.337 28.416 12.697 29.064 ;
     RECT  11.873 50.304 12.769 60.36 ;
     RECT  12.769 50.304 12.812 60.696 ;
     RECT  12.161 62.304 12.812 64.968 ;
     RECT  11.405 12.912 12.877 13.08 ;
     RECT  12.613 30.384 12.913 32.28 ;
     RECT  12.325 33.6 12.949 39.048 ;
     RECT  11.74 44.688 12.949 48.456 ;
     RECT  12.265 6 13.021 7.416 ;
     RECT  12.517 8.736 13.021 8.76 ;
     RECT  11.699 9.792 13.021 9.816 ;
     RECT  11.74 42.144 13.057 43.32 ;
     RECT  12.949 44.448 13.057 48.456 ;
     RECT  13.021 8.736 13.093 9.816 ;
     RECT  12.083 10.896 13.093 10.92 ;
     RECT  12.877 12.912 13.093 13.608 ;
     RECT  13.057 42.144 13.093 48.456 ;
     RECT  12.089 14.64 13.129 14.664 ;
     RECT  12.553 15.744 13.129 16.008 ;
     RECT  13.093 42 13.129 48.696 ;
     RECT  13.093 8.736 13.201 10.92 ;
     RECT  13.129 41.712 13.201 48.696 ;
     RECT  12.985 3.072 13.208 3.096 ;
     RECT  12.589 4.176 13.208 4.248 ;
     RECT  13.021 5.568 13.208 7.416 ;
     RECT  13.201 8.448 13.208 10.92 ;
     RECT  13.093 12.48 13.208 13.608 ;
     RECT  13.129 14.64 13.208 16.008 ;
     RECT  12.049 17.232 13.208 19.368 ;
     RECT  12.125 20.976 13.208 21 ;
     RECT  12.125 22.08 13.208 23.352 ;
     RECT  11.837 24.48 13.208 25.848 ;
     RECT  12.697 27.072 13.208 29.064 ;
     RECT  12.913 30.384 13.208 32.328 ;
     RECT  12.949 33.6 13.208 39.24 ;
     RECT  13.201 41.712 13.208 49.08 ;
     RECT  12.812 50.304 13.208 64.968 ;
     RECT  12.193 66.24 13.208 66.6 ;
     RECT  13.208 2.148 13.312 66.972 ;
     RECT  13.312 2.418 13.504 66.702 ;
     RECT  13.504 13.056 13.637 13.608 ;
     RECT  13.504 42.144 13.667 64.968 ;
     RECT  13.504 4.128 13.673 4.248 ;
     RECT  13.504 8.544 13.673 10.872 ;
     RECT  13.504 14.64 13.708 18.984 ;
     RECT  13.504 20.736 13.709 31.224 ;
     RECT  13.504 66.144 13.709 66.6 ;
     RECT  13.673 9.312 13.745 10.872 ;
     RECT  13.667 45.024 13.745 64.968 ;
     RECT  13.504 34.08 13.781 36.168 ;
     RECT  13.745 45.024 13.817 49.608 ;
     RECT  13.709 20.736 13.853 29.064 ;
     RECT  13.853 23.28 13.889 29.064 ;
     RECT  13.708 14.64 13.955 16.152 ;
     RECT  13.889 23.376 13.961 29.064 ;
     RECT  13.781 34.368 14.069 36.168 ;
     RECT  13.961 23.376 14.105 26.808 ;
     RECT  13.709 66.144 14.105 66.552 ;
     RECT  13.955 14.784 14.141 16.152 ;
     RECT  13.853 20.736 14.291 22.248 ;
     RECT  13.745 50.64 14.291 64.968 ;
     RECT  13.504 32.304 14.321 32.328 ;
     RECT  14.291 60.672 14.321 64.968 ;
     RECT  14.105 66.144 14.321 66.168 ;
     RECT  14.321 61.344 14.332 64.968 ;
     RECT  14.141 15.84 14.429 16.152 ;
     RECT  13.637 13.584 14.537 13.608 ;
     RECT  14.291 21.648 14.537 22.248 ;
     RECT  14.537 22.08 14.573 22.248 ;
     RECT  13.961 27.888 14.573 29.064 ;
     RECT  13.817 45.024 14.681 48.504 ;
     RECT  13.504 37.68 14.773 39.336 ;
     RECT  13.504 40.416 14.773 40.44 ;
     RECT  14.773 37.68 14.785 40.44 ;
     RECT  13.817 49.584 14.785 49.608 ;
     RECT  14.291 50.64 14.785 59.592 ;
     RECT  14.732 2.592 14.819 2.616 ;
     RECT  13.709 30.192 14.821 31.224 ;
     RECT  14.681 45.264 14.821 48.504 ;
     RECT  14.785 49.584 14.821 59.592 ;
     RECT  13.673 4.128 14.825 4.152 ;
     RECT  14.105 23.376 14.857 24.744 ;
     RECT  13.667 42.144 14.86 43.8 ;
     RECT  14.821 30.192 14.861 31.896 ;
     RECT  14.86 42.144 14.861 42.168 ;
     RECT  14.821 45.264 14.897 59.592 ;
     RECT  14.86 43.632 14.929 43.8 ;
     RECT  14.429 15.84 14.933 15.864 ;
     RECT  14.785 37.68 15.001 40.776 ;
     RECT  14.641 33.024 15.013 33.048 ;
     RECT  14.069 34.368 15.013 35.832 ;
     RECT  13.504 6.096 15.02 6.312 ;
     RECT  15.013 33.024 15.059 35.832 ;
     RECT  14.897 48.864 15.059 59.592 ;
     RECT  15.02 6.096 15.073 7.272 ;
     RECT  15.073 5.712 15.109 7.272 ;
     RECT  14.141 14.784 15.109 14.808 ;
     RECT  14.105 25.728 15.109 26.808 ;
     RECT  15.059 33.504 15.149 35.832 ;
     RECT  15.109 4.944 15.157 7.272 ;
     RECT  15.109 25.728 15.181 26.904 ;
     RECT  14.573 27.888 15.181 28.968 ;
     RECT  14.332 61.68 15.181 64.968 ;
     RECT  15.149 33.504 15.185 33.528 ;
     RECT  15.157 6.096 15.253 7.272 ;
     RECT  15.149 34.752 15.253 35.832 ;
     RECT  15.253 34.752 15.299 36.264 ;
     RECT  13.745 9.6 15.361 10.872 ;
     RECT  14.749 11.904 15.361 11.928 ;
     RECT  14.857 22.8 15.361 24.744 ;
     RECT  15.181 25.728 15.361 28.968 ;
     RECT  15.109 14.784 15.397 14.904 ;
     RECT  15.361 9.6 15.433 10.92 ;
     RECT  15.361 11.904 15.433 12.36 ;
     RECT  15.433 9.6 15.473 12.36 ;
     RECT  14.861 30.384 15.581 31.896 ;
     RECT  13.708 17.52 15.589 18.984 ;
     RECT  15.361 22.8 15.617 28.968 ;
     RECT  15.299 35.904 15.617 36.264 ;
     RECT  15.397 13.92 15.635 14.904 ;
     RECT  15.548 15.984 15.635 16.008 ;
     RECT  15.473 10.176 15.649 12.36 ;
     RECT  15.299 34.752 15.689 34.824 ;
     RECT  15.617 35.904 15.761 35.928 ;
     RECT  15.617 22.8 15.793 27.912 ;
     RECT  15.617 28.944 15.833 28.968 ;
     RECT  15.001 37.68 15.833 40.872 ;
     RECT  15.157 4.944 15.901 4.968 ;
     RECT  15.793 22.704 15.905 27.912 ;
     RECT  14.897 45.264 15.905 47.88 ;
     RECT  15.905 22.8 15.923 27.912 ;
     RECT  15.181 61.68 15.941 65.544 ;
     RECT  15.581 30.384 15.971 30.84 ;
     RECT  15.971 30.816 15.977 30.84 ;
     RECT  15.581 31.872 16.013 31.896 ;
     RECT  15.059 48.912 16.013 59.592 ;
     RECT  15.589 17.04 16.019 18.984 ;
     RECT  14.929 43.632 16.049 44.088 ;
     RECT  15.905 46.128 16.085 47.88 ;
     RECT  15.649 10.176 16.117 12.936 ;
     RECT  15.635 13.92 16.117 14.808 ;
     RECT  16.013 48.912 16.157 59.304 ;
     RECT  16.117 10.176 16.163 14.808 ;
     RECT  16.049 43.776 16.189 44.088 ;
     RECT  16.019 17.04 16.301 17.544 ;
     RECT  16.085 46.32 16.333 47.88 ;
     RECT  16.157 48.912 16.333 49.608 ;
     RECT  15.833 37.68 16.373 39.48 ;
     RECT  16.163 10.896 16.481 14.808 ;
     RECT  16.301 17.04 16.556 17.448 ;
     RECT  16.481 10.896 16.595 12.36 ;
     RECT  16.441 21.024 16.597 21.048 ;
     RECT  15.923 23.52 16.697 27.912 ;
     RECT  16.697 27.312 16.805 27.912 ;
     RECT  16.019 18.768 16.841 18.792 ;
     RECT  16.556 16.992 16.873 17.448 ;
     RECT  15.901 4.128 16.909 4.968 ;
     RECT  15.253 6.096 16.945 7.896 ;
     RECT  16.873 16.368 16.981 17.448 ;
     RECT  16.481 13.344 17.129 14.808 ;
     RECT  15.941 62.736 17.161 65.544 ;
     RECT  16.657 66.672 17.161 66.696 ;
     RECT  16.373 38.16 17.165 39.48 ;
     RECT  17.165 38.496 17.221 39.48 ;
     RECT  16.909 3.408 17.269 4.968 ;
     RECT  16.945 6.096 17.269 7.944 ;
     RECT  16.157 50.64 17.269 59.304 ;
     RECT  17.221 38.496 17.305 39.912 ;
     RECT  15.865 41.04 17.305 41.448 ;
     RECT  17.269 50.64 17.309 59.496 ;
     RECT  17.233 15.072 17.345 15.096 ;
     RECT  16.333 46.32 17.377 49.608 ;
     RECT  17.309 50.64 17.377 50.664 ;
     RECT  17.269 3.408 17.381 7.944 ;
     RECT  16.189 43.776 17.381 44.52 ;
     RECT  16.981 16.128 17.417 17.448 ;
     RECT  16.333 29.04 17.453 29.064 ;
     RECT  17.317 33.072 17.461 33.096 ;
     RECT  17.461 33.072 17.507 33.336 ;
     RECT  15.941 61.68 17.521 61.704 ;
     RECT  17.161 62.736 17.521 66.696 ;
     RECT  17.161 60.672 17.557 60.696 ;
     RECT  17.305 38.496 17.593 41.448 ;
     RECT  17.593 38.496 17.653 42.168 ;
     RECT  17.309 51.744 17.653 59.496 ;
     RECT  17.557 60.528 17.653 60.696 ;
     RECT  16.697 23.52 17.665 26.232 ;
     RECT  16.693 9.456 17.701 9.672 ;
     RECT  16.597 21.024 17.953 21.672 ;
     RECT  17.665 22.752 17.953 26.232 ;
     RECT  17.377 46.32 17.953 50.664 ;
     RECT  17.701 9.264 18.061 9.672 ;
     RECT  16.595 11.28 18.061 12.36 ;
     RECT  16.805 27.312 18.169 27.72 ;
     RECT  17.381 3.408 18.205 3.432 ;
     RECT  17.653 38.496 18.277 42.792 ;
     RECT  17.953 21.024 18.313 26.232 ;
     RECT  17.381 43.776 18.349 43.944 ;
     RECT  18.277 37.872 18.469 42.792 ;
     RECT  18.349 43.776 18.469 44.808 ;
     RECT  17.953 46.272 18.469 50.664 ;
     RECT  18.313 21.024 18.493 26.28 ;
     RECT  18.169 29.232 18.529 29.256 ;
     RECT  17.129 13.344 18.565 13.992 ;
     RECT  17.653 51.744 18.601 60.696 ;
     RECT  17.521 61.68 18.601 66.696 ;
     RECT  18.205 2.928 18.608 3.432 ;
     RECT  17.381 4.944 18.608 7.944 ;
     RECT  18.061 9.264 18.608 12.36 ;
     RECT  18.565 13.344 18.608 14.76 ;
     RECT  17.521 15.792 18.608 15.816 ;
     RECT  17.417 17.04 18.608 17.448 ;
     RECT  17.233 18.672 18.608 18.696 ;
     RECT  18.493 20.688 18.608 26.28 ;
     RECT  18.169 27.312 18.608 27.912 ;
     RECT  18.529 28.992 18.608 29.256 ;
     RECT  18.133 30.672 18.608 30.696 ;
     RECT  18.457 31.776 18.608 31.8 ;
     RECT  17.507 33.312 18.608 33.336 ;
     RECT  15.689 34.752 18.608 34.776 ;
     RECT  18.469 37.872 18.608 44.808 ;
     RECT  18.469 46.176 18.608 50.664 ;
     RECT  18.601 51.744 18.608 66.696 ;
     RECT  18.608 2.148 18.712 66.972 ;
     RECT  18.712 2.418 18.904 66.702 ;
     RECT  18.904 51.312 19.073 66.6 ;
     RECT  18.904 40.416 19.109 50.136 ;
     RECT  18.904 5.04 19.139 13.464 ;
     RECT  19.139 5.712 19.253 13.464 ;
     RECT  18.904 34.752 19.283 36.456 ;
     RECT  19.283 34.752 19.324 34.776 ;
     RECT  19.109 47.04 19.379 50.136 ;
     RECT  19.253 5.712 19.389 12.36 ;
     RECT  19.109 40.416 19.433 45.864 ;
     RECT  19.433 40.416 19.505 42.024 ;
     RECT  19.073 64.896 19.505 66.6 ;
     RECT  18.904 3.312 19.541 3.336 ;
     RECT  19.505 64.896 19.721 66.36 ;
     RECT  19.389 5.712 19.793 5.736 ;
     RECT  19.389 6.816 19.804 12.36 ;
     RECT  19.073 51.312 19.897 63.672 ;
     RECT  19.379 47.04 19.901 50.04 ;
     RECT  19.804 8.784 19.907 12.36 ;
     RECT  18.904 14.64 20.005 16.248 ;
     RECT  18.904 17.424 20.005 17.448 ;
     RECT  18.904 37.872 20.041 37.896 ;
     RECT  20.005 14.64 20.113 17.496 ;
     RECT  18.904 18.528 20.113 18.552 ;
     RECT  19.901 47.04 20.117 48.552 ;
     RECT  18.904 20.64 20.153 30.168 ;
     RECT  19.897 51.168 20.153 63.672 ;
     RECT  20.153 23.664 20.185 30.168 ;
     RECT  20.113 14.64 20.293 18.552 ;
     RECT  20.041 37.584 20.329 37.896 ;
     RECT  19.969 39.216 20.329 39.24 ;
     RECT  19.505 40.416 20.369 41.064 ;
     RECT  19.283 36.432 20.437 36.456 ;
     RECT  20.329 37.584 20.437 39.24 ;
     RECT  19.901 49.68 20.473 50.04 ;
     RECT  20.153 51.168 20.473 60.696 ;
     RECT  20.437 36.432 20.509 39.24 ;
     RECT  19.804 6.816 20.531 7.656 ;
     RECT  20.293 14.64 20.549 19.32 ;
     RECT  20.369 41.04 20.549 41.064 ;
     RECT  20.473 49.68 20.585 60.696 ;
     RECT  20.153 61.68 20.585 63.672 ;
     RECT  20.531 6.816 20.621 7.368 ;
     RECT  20.509 36.432 20.621 39.912 ;
     RECT  19.433 43.008 20.653 45.864 ;
     RECT  19.907 8.976 20.657 12.36 ;
     RECT  20.585 63.072 20.725 63.672 ;
     RECT  19.721 64.896 20.725 66.264 ;
     RECT  20.005 32.016 20.765 32.04 ;
     RECT  20.401 34.752 20.833 34.776 ;
     RECT  20.657 9.264 20.869 12.36 ;
     RECT  19.253 13.44 20.869 13.464 ;
     RECT  20.549 16.896 20.869 19.32 ;
     RECT  20.585 49.68 20.905 50.04 ;
     RECT  20.653 42.432 20.941 45.864 ;
     RECT  20.117 47.04 20.941 48.168 ;
     RECT  20.185 23.664 20.945 30.6 ;
     RECT  20.905 49.488 20.945 50.04 ;
     RECT  20.869 9.264 20.965 13.464 ;
     RECT  20.549 14.64 20.965 15.816 ;
     RECT  20.941 42.432 21.085 48.168 ;
     RECT  20.725 63.072 21.089 66.264 ;
     RECT  20.945 27.36 21.121 30.6 ;
     RECT  21.085 42.144 21.121 48.168 ;
     RECT  20.945 49.488 21.121 49.704 ;
     RECT  20.869 16.896 21.125 19.512 ;
     RECT  21.121 27.36 21.125 30.696 ;
     RECT  21.125 28.992 21.193 30.696 ;
     RECT  21.121 42.144 21.193 49.704 ;
     RECT  20.833 34.56 21.265 34.776 ;
     RECT  21.125 27.36 21.305 27.768 ;
     RECT  20.585 51.696 21.305 60.696 ;
     RECT  21.193 41.712 21.341 49.704 ;
     RECT  20.365 3.36 21.373 3.384 ;
     RECT  21.125 16.896 21.377 19.416 ;
     RECT  21.305 59.232 21.409 60.696 ;
     RECT  20.585 61.68 21.409 61.704 ;
     RECT  21.409 59.232 21.413 61.704 ;
     RECT  21.265 34.56 21.445 35.256 ;
     RECT  21.413 60.624 21.593 61.704 ;
     RECT  20.621 6.96 21.625 7.368 ;
     RECT  21.305 51.696 21.625 58.2 ;
     RECT  20.621 36.624 21.676 39.912 ;
     RECT  21.341 41.712 21.701 48.216 ;
     RECT  21.193 28.992 21.733 31.416 ;
     RECT  21.733 28.992 21.773 31.8 ;
     RECT  20.965 9.264 21.805 15.816 ;
     RECT  21.805 9.024 21.877 15.816 ;
     RECT  21.377 16.896 21.877 17.496 ;
     RECT  21.701 45.696 21.881 48.216 ;
     RECT  21.881 46.896 21.917 48.216 ;
     RECT  20.153 20.64 21.973 22.488 ;
     RECT  21.773 28.992 22.012 30.696 ;
     RECT  21.341 49.2 22.021 49.704 ;
     RECT  21.625 51.312 22.021 58.2 ;
     RECT  21.877 9.024 22.025 17.496 ;
     RECT  21.445 34.464 22.061 35.256 ;
     RECT  21.881 45.696 22.061 45.864 ;
     RECT  22.025 9.024 22.093 10.248 ;
     RECT  22.061 35.232 22.097 35.256 ;
     RECT  21.701 41.712 22.129 44.424 ;
     RECT  22.012 30.336 22.133 30.696 ;
     RECT  21.917 46.896 22.133 48.168 ;
     RECT  21.973 20.496 22.165 22.488 ;
     RECT  21.625 6.576 22.201 7.368 ;
     RECT  21.305 27.408 22.273 27.768 ;
     RECT  21.985 40.032 22.277 40.056 ;
     RECT  22.025 11.232 22.345 17.496 ;
     RECT  21.377 18.528 22.345 19.416 ;
     RECT  22.345 11.232 22.349 19.416 ;
     RECT  22.201 6.288 22.385 7.368 ;
     RECT  21.089 63.648 22.453 66.264 ;
     RECT  20.945 23.664 22.549 25.752 ;
     RECT  22.021 49.2 22.549 58.2 ;
     RECT  21.413 59.232 22.549 59.448 ;
     RECT  22.549 49.2 22.561 59.448 ;
     RECT  21.593 60.768 22.561 61.704 ;
     RECT  22.012 28.992 22.565 29.304 ;
     RECT  21.773 31.776 22.669 31.8 ;
     RECT  18.904 33.312 22.669 33.336 ;
     RECT  22.549 23.52 22.673 25.752 ;
     RECT  22.093 8.784 22.777 10.248 ;
     RECT  22.273 27.12 22.777 27.768 ;
     RECT  22.561 49.2 22.787 61.704 ;
     RECT  22.349 11.232 22.809 15.816 ;
     RECT  22.385 6.576 22.817 7.368 ;
     RECT  22.453 63.216 22.885 66.264 ;
     RECT  22.817 6.624 22.993 7.368 ;
     RECT  22.777 8.592 22.993 10.248 ;
     RECT  22.787 49.2 22.993 59.88 ;
     RECT  22.993 6.624 22.997 10.248 ;
     RECT  22.349 16.896 23.029 19.416 ;
     RECT  22.165 20.448 23.029 22.488 ;
     RECT  22.061 45.696 23.065 45.72 ;
     RECT  22.133 30.624 23.101 30.696 ;
     RECT  22.669 31.776 23.101 33.336 ;
     RECT  23.101 30.336 23.137 33.336 ;
     RECT  22.787 60.864 23.209 61.704 ;
     RECT  22.885 63.072 23.209 66.264 ;
     RECT  22.993 48.72 23.245 59.88 ;
     RECT  22.673 23.616 23.281 25.752 ;
     RECT  22.129 41.616 23.281 44.424 ;
     RECT  23.065 45.696 23.281 45.816 ;
     RECT  23.029 16.896 23.317 22.488 ;
     RECT  22.133 46.896 23.317 47.592 ;
     RECT  23.281 23.616 23.42 26.04 ;
     RECT  22.777 27.12 23.42 28.536 ;
     RECT  23.281 41.616 23.497 45.816 ;
     RECT  23.317 5.328 23.605 5.352 ;
     RECT  23.317 16.896 23.749 22.584 ;
     RECT  23.42 23.616 23.749 28.536 ;
     RECT  22.809 11.232 23.785 15.288 ;
     RECT  21.676 36.624 23.857 38.52 ;
     RECT  23.209 60.864 23.893 66.264 ;
     RECT  21.373 3.312 24.008 3.384 ;
     RECT  23.605 5.232 24.008 5.352 ;
     RECT  22.997 6.624 24.008 10.152 ;
     RECT  23.785 11.232 24.008 15.432 ;
     RECT  23.749 16.896 24.008 28.536 ;
     RECT  23.137 29.76 24.008 33.336 ;
     RECT  23.857 35.712 24.008 38.52 ;
     RECT  23.497 41.472 24.008 45.816 ;
     RECT  23.317 46.848 24.008 47.592 ;
     RECT  23.245 48.672 24.008 59.88 ;
     RECT  23.893 60.864 24.008 66.552 ;
     RECT  24.008 2.148 24.112 66.972 ;
     RECT  24.112 2.418 24.304 66.702 ;
     RECT  24.304 33.408 24.365 34.2 ;
     RECT  24.304 61.344 24.419 66.552 ;
     RECT  24.304 13.392 24.467 25.752 ;
     RECT  24.467 16.08 24.473 25.752 ;
     RECT  24.304 3.168 24.48 3.192 ;
     RECT  24.304 26.832 24.509 30.888 ;
     RECT  24.473 16.656 24.515 25.752 ;
     RECT  24.419 62.976 24.545 66.072 ;
     RECT  24.509 30.144 24.581 30.888 ;
     RECT  24.545 62.976 24.617 65.784 ;
     RECT  24.304 41.472 24.653 58.2 ;
     RECT  24.304 59.76 24.689 59.784 ;
     RECT  24.509 26.832 24.797 29.16 ;
     RECT  24.653 41.472 24.941 41.736 ;
     RECT  24.304 35.328 25.043 38.184 ;
     RECT  24.617 62.976 25.121 65.256 ;
     RECT  24.304 6.528 25.157 10.152 ;
     RECT  24.304 39.216 25.157 39.24 ;
     RECT  24.653 42.816 25.265 58.2 ;
     RECT  24.304 11.232 25.333 12.312 ;
     RECT  24.467 13.392 25.333 14.76 ;
     RECT  25.043 35.328 25.333 37.608 ;
     RECT  24.515 16.656 25.337 25.608 ;
     RECT  25.121 62.976 25.337 64.92 ;
     RECT  25.333 35.232 25.369 37.608 ;
     RECT  24.365 33.408 25.441 33.672 ;
     RECT  25.369 35.136 25.477 37.608 ;
     RECT  24.304 4.8 25.481 5.256 ;
     RECT  24.419 61.344 25.513 61.704 ;
     RECT  25.337 62.976 25.513 64.44 ;
     RECT  24.581 30.576 25.585 30.888 ;
     RECT  25.513 61.344 25.585 64.44 ;
     RECT  25.157 6.912 25.621 10.152 ;
     RECT  25.333 11.232 25.621 14.76 ;
     RECT  25.585 30.576 25.657 31.416 ;
     RECT  25.585 61.104 25.665 64.44 ;
     RECT  25.621 59.424 25.769 59.448 ;
     RECT  25.265 42.816 25.805 58.152 ;
     RECT  24.941 41.712 25.873 41.736 ;
     RECT  25.805 42.816 25.873 47.784 ;
     RECT  25.441 33.264 25.877 33.672 ;
     RECT  25.877 33.264 25.913 33.432 ;
     RECT  25.405 38.784 26.012 38.808 ;
     RECT  25.337 16.656 26.017 17.448 ;
     RECT  25.913 33.312 26.021 33.432 ;
     RECT  25.477 34.944 26.099 37.608 ;
     RECT  25.873 41.712 26.099 47.784 ;
     RECT  25.665 60.528 26.129 64.44 ;
     RECT  25.657 30.576 26.161 31.704 ;
     RECT  25.765 3.072 26.165 3.096 ;
     RECT  26.099 41.952 26.201 47.784 ;
     RECT  26.099 36.96 26.233 37.608 ;
     RECT  26.012 38.64 26.233 38.808 ;
     RECT  26.201 42 26.243 47.784 ;
     RECT  26.129 61.68 26.243 64.44 ;
     RECT  26.161 40.896 26.252 40.92 ;
     RECT  25.621 6.912 26.273 14.76 ;
     RECT  26.233 36.96 26.293 38.808 ;
     RECT  26.252 40.272 26.293 40.92 ;
     RECT  25.337 18.528 26.309 25.608 ;
     RECT  25.805 48.768 26.309 58.152 ;
     RECT  26.293 36.96 26.339 40.92 ;
     RECT  26.099 34.944 26.345 35.832 ;
     RECT  26.345 35.136 26.381 35.832 ;
     RECT  26.243 61.68 26.381 62.52 ;
     RECT  25.873 66.048 26.381 66.072 ;
     RECT  26.161 29.904 26.413 31.704 ;
     RECT  26.273 6.912 26.449 9.336 ;
     RECT  26.017 16.032 26.521 17.448 ;
     RECT  26.273 10.992 26.525 14.76 ;
     RECT  26.309 23.184 26.525 25.608 ;
     RECT  24.797 26.832 26.557 28.584 ;
     RECT  25.481 4.944 26.561 5.256 ;
     RECT  26.309 18.528 26.627 22.056 ;
     RECT  26.309 48.768 26.669 49.032 ;
     RECT  26.381 61.68 26.669 62.04 ;
     RECT  26.309 54.96 26.737 58.152 ;
     RECT  26.449 6.432 26.771 9.336 ;
     RECT  26.413 29.76 26.773 31.704 ;
     RECT  26.381 35.328 26.777 35.832 ;
     RECT  26.339 40.896 26.777 40.92 ;
     RECT  26.243 63.648 26.777 64.44 ;
     RECT  26.521 15.792 26.809 17.448 ;
     RECT  26.627 18.528 26.809 19.32 ;
     RECT  26.525 11.232 26.885 14.76 ;
     RECT  26.339 36.96 26.885 39.384 ;
     RECT  26.129 60.528 26.917 60.552 ;
     RECT  26.885 37.248 26.957 39.384 ;
     RECT  26.557 26.784 26.993 28.584 ;
     RECT  26.957 37.248 26.993 38.52 ;
     RECT  26.525 23.568 27.133 25.608 ;
     RECT  26.993 26.784 27.133 28.44 ;
     RECT  26.243 43.728 27.169 47.784 ;
     RECT  26.669 48.768 27.169 48.936 ;
     RECT  27.133 23.568 27.281 28.44 ;
     RECT  26.737 54.96 27.313 58.776 ;
     RECT  26.771 9.072 27.349 9.336 ;
     RECT  26.917 60.336 27.349 60.552 ;
     RECT  26.669 61.68 27.349 61.704 ;
     RECT  26.777 63.648 27.385 64.344 ;
     RECT  26.773 29.76 27.389 32.328 ;
     RECT  26.777 35.616 27.425 35.832 ;
     RECT  26.885 14.496 27.452 14.76 ;
     RECT  26.809 15.792 27.452 19.32 ;
     RECT  26.021 33.312 27.457 33.336 ;
     RECT  26.243 42 27.457 42.408 ;
     RECT  27.169 43.728 27.457 48.936 ;
     RECT  27.313 54.96 27.457 59.304 ;
     RECT  27.349 60.336 27.457 61.704 ;
     RECT  26.449 66.192 27.457 66.216 ;
     RECT  27.452 14.496 27.539 19.32 ;
     RECT  27.389 29.904 27.569 32.328 ;
     RECT  27.457 66.048 27.601 66.216 ;
     RECT  27.457 42 27.685 48.936 ;
     RECT  26.309 50.016 27.685 50.568 ;
     RECT  26.627 20.4 27.709 22.056 ;
     RECT  27.685 42 27.772 50.568 ;
     RECT  27.539 15.84 27.817 19.32 ;
     RECT  27.709 20.4 27.817 22.584 ;
     RECT  27.637 3.456 27.853 3.48 ;
     RECT  27.457 54.96 27.853 61.704 ;
     RECT  27.772 42 27.884 48.936 ;
     RECT  26.561 4.992 27.889 5.256 ;
     RECT  26.771 6.672 27.925 7.896 ;
     RECT  27.349 9.072 27.925 9.816 ;
     RECT  26.309 51.696 27.925 53.592 ;
     RECT  27.853 54.72 27.925 61.704 ;
     RECT  27.925 51.696 27.929 61.704 ;
     RECT  26.885 11.232 27.961 13.464 ;
     RECT  27.569 32.256 27.961 32.328 ;
     RECT  27.457 33.312 27.961 33.672 ;
     RECT  27.884 41.52 27.971 48.936 ;
     RECT  27.971 41.904 28.037 48.936 ;
     RECT  26.993 37.248 28.073 37.8 ;
     RECT  27.601 65.712 28.105 66.216 ;
     RECT  28.105 65.712 28.141 66.264 ;
     RECT  28.141 65.424 28.177 66.264 ;
     RECT  27.772 50.016 28.213 50.568 ;
     RECT  27.961 32.256 28.289 33.672 ;
     RECT  27.569 29.904 28.325 31.128 ;
     RECT  27.817 15.84 28.433 22.584 ;
     RECT  27.425 35.664 28.453 35.832 ;
     RECT  27.925 6.672 28.465 9.816 ;
     RECT  27.853 3.456 28.537 3.576 ;
     RECT  27.281 23.568 28.537 28.296 ;
     RECT  27.961 10.896 28.609 13.464 ;
     RECT  27.539 14.496 28.609 14.76 ;
     RECT  28.465 6.288 28.681 9.816 ;
     RECT  28.609 10.896 28.681 14.76 ;
     RECT  28.537 23.568 28.825 28.44 ;
     RECT  28.453 35.664 28.897 36.072 ;
     RECT  28.681 6.288 28.933 14.76 ;
     RECT  28.433 15.84 28.933 22.056 ;
     RECT  28.037 45.696 28.933 48.936 ;
     RECT  28.037 41.904 29.005 44.472 ;
     RECT  27.385 62.736 29.005 64.344 ;
     RECT  28.177 65.424 29.005 66.408 ;
     RECT  28.897 35.232 29.041 36.072 ;
     RECT  28.412 38.928 29.041 38.952 ;
     RECT  27.349 40.512 29.041 40.536 ;
     RECT  27.889 4.56 29.077 5.256 ;
     RECT  28.933 6.288 29.077 22.056 ;
     RECT  29.041 38.928 29.113 40.536 ;
     RECT  29.005 41.904 29.113 44.712 ;
     RECT  28.933 45.696 29.113 48.984 ;
     RECT  28.325 29.952 29.185 31.128 ;
     RECT  28.289 32.256 29.185 33.336 ;
     RECT  28.825 23.568 29.257 28.536 ;
     RECT  29.113 41.904 29.257 48.984 ;
     RECT  28.213 50.016 29.257 51.336 ;
     RECT  29.041 34.896 29.329 36.072 ;
     RECT  28.537 2.832 29.408 3.576 ;
     RECT  29.077 4.56 29.408 22.056 ;
     RECT  29.257 23.568 29.408 28.728 ;
     RECT  29.185 29.952 29.408 33.336 ;
     RECT  29.329 34.848 29.408 36.072 ;
     RECT  28.073 37.248 29.408 37.656 ;
     RECT  29.113 38.784 29.408 40.536 ;
     RECT  29.257 41.904 29.408 51.336 ;
     RECT  27.929 52.416 29.408 61.704 ;
     RECT  29.005 62.736 29.408 66.408 ;
     RECT  29.408 2.148 29.512 66.972 ;
     RECT  29.512 2.418 29.704 66.702 ;
     RECT  29.704 51.696 29.765 54.312 ;
     RECT  29.704 4.944 29.98 17.496 ;
     RECT  29.704 29.76 30.131 34.968 ;
     RECT  30.131 30.192 30.197 34.968 ;
     RECT  29.704 37.152 30.269 37.656 ;
     RECT  29.704 41.568 30.269 50.664 ;
     RECT  30.269 37.536 30.341 37.656 ;
     RECT  29.765 51.744 30.341 54.312 ;
     RECT  29.98 7.104 30.413 17.496 ;
     RECT  30.269 50.016 30.413 50.664 ;
     RECT  29.98 4.944 30.485 5.496 ;
     RECT  30.269 41.568 30.521 49.032 ;
     RECT  30.485 4.992 30.557 5.496 ;
     RECT  29.704 38.784 30.593 40.344 ;
     RECT  30.413 10.896 30.701 17.496 ;
     RECT  29.704 23.568 30.701 28.728 ;
     RECT  29.704 18.48 30.733 22.152 ;
     RECT  30.701 23.568 30.733 28.584 ;
     RECT  30.413 50.352 30.773 50.664 ;
     RECT  30.701 10.896 30.809 14.952 ;
     RECT  29.704 62.784 30.877 66.264 ;
     RECT  30.413 7.104 30.881 9.384 ;
     RECT  30.773 50.64 30.881 50.664 ;
     RECT  30.341 51.888 30.881 54.312 ;
     RECT  30.877 62.784 30.949 66.6 ;
     RECT  29.704 56.688 31.021 61.704 ;
     RECT  30.701 16.224 31.093 17.496 ;
     RECT  30.733 18.48 31.093 28.584 ;
     RECT  30.197 30.192 31.093 30.648 ;
     RECT  31.021 55.968 31.169 61.704 ;
     RECT  30.593 40.32 31.196 40.344 ;
     RECT  30.521 41.568 31.196 48.984 ;
     RECT  30.809 10.896 31.205 11.976 ;
     RECT  31.169 55.968 31.237 56.088 ;
     RECT  31.196 40.32 31.241 48.984 ;
     RECT  30.593 38.784 31.273 39.288 ;
     RECT  31.241 40.416 31.283 48.984 ;
     RECT  30.881 51.888 31.309 51.96 ;
     RECT  30.949 62.784 31.309 66.648 ;
     RECT  30.557 5.04 31.34 5.496 ;
     RECT  31.093 29.664 31.345 30.648 ;
     RECT  30.341 37.536 31.345 37.608 ;
     RECT  31.309 50.976 31.349 51.96 ;
     RECT  31.345 29.664 31.381 30.696 ;
     RECT  30.197 31.872 31.381 34.968 ;
     RECT  31.093 16.224 31.385 28.584 ;
     RECT  31.34 5.04 31.427 5.88 ;
     RECT  31.349 50.976 31.457 51.912 ;
     RECT  31.345 37.104 31.489 37.608 ;
     RECT  31.273 38.64 31.489 39.288 ;
     RECT  29.704 36.048 31.532 36.072 ;
     RECT  31.021 3.36 31.571 3.384 ;
     RECT  31.532 35.952 31.601 36.072 ;
     RECT  31.601 35.952 31.619 35.976 ;
     RECT  31.381 29.664 31.633 34.968 ;
     RECT  30.809 13.392 31.741 14.952 ;
     RECT  31.489 37.104 31.777 39.288 ;
     RECT  31.169 57.312 31.849 61.704 ;
     RECT  31.309 62.688 31.849 66.648 ;
     RECT  30.881 52.992 31.853 54.312 ;
     RECT  31.283 41.664 31.861 48.984 ;
     RECT  31.385 23.28 31.921 28.584 ;
     RECT  31.633 29.664 31.921 35.208 ;
     RECT  31.777 37.008 31.925 39.288 ;
     RECT  31.925 38.64 31.961 39.288 ;
     RECT  31.849 57.312 31.961 66.648 ;
     RECT  31.741 13.392 32.029 15.24 ;
     RECT  31.385 16.224 32.029 22.152 ;
     RECT  31.861 41.664 32.029 49.752 ;
     RECT  31.457 50.976 32.029 51.816 ;
     RECT  31.427 5.472 32.051 5.88 ;
     RECT  31.921 23.28 32.069 35.208 ;
     RECT  32.029 41.664 32.105 51.816 ;
     RECT  31.961 57.312 32.177 66.6 ;
     RECT  31.237 55.92 32.209 56.088 ;
     RECT  32.105 50.64 32.249 51.816 ;
     RECT  31.853 52.992 32.281 53.352 ;
     RECT  32.209 55.92 32.353 56.376 ;
     RECT  31.205 11.232 32.425 11.976 ;
     RECT  32.029 13.392 32.465 22.152 ;
     RECT  32.465 18.48 32.485 22.152 ;
     RECT  32.069 23.28 32.485 32.28 ;
     RECT  32.005 3.408 32.533 3.432 ;
     RECT  30.881 7.152 32.537 9.384 ;
     RECT  32.105 41.664 32.537 48.84 ;
     RECT  31.961 38.784 32.573 39.288 ;
     RECT  31.283 40.416 32.573 40.44 ;
     RECT  32.249 50.976 32.573 51.816 ;
     RECT  32.573 51.216 32.641 51.816 ;
     RECT  32.281 52.944 32.641 53.352 ;
     RECT  32.353 55.632 32.677 56.376 ;
     RECT  32.177 57.408 32.753 66.6 ;
     RECT  32.533 3.408 32.821 4.152 ;
     RECT  32.753 65.52 32.861 66.6 ;
     RECT  32.051 5.472 32.893 5.496 ;
     RECT  32.861 66.144 32.897 66.6 ;
     RECT  32.677 55.248 32.929 56.376 ;
     RECT  32.821 3.312 32.965 4.152 ;
     RECT  31.925 37.008 33.068 37.608 ;
     RECT  32.465 13.392 33.073 17.496 ;
     RECT  33.068 36.816 33.109 37.608 ;
     RECT  32.573 38.784 33.109 38.952 ;
     RECT  33.109 36.816 33.155 38.952 ;
     RECT  32.537 41.664 33.257 48.6 ;
     RECT  32.641 51.216 33.257 53.352 ;
     RECT  32.929 54.576 33.257 56.376 ;
     RECT  32.069 33.312 33.329 35.208 ;
     RECT  32.897 66.144 33.329 66.168 ;
     RECT  32.753 57.408 33.361 63.912 ;
     RECT  32.425 11.232 33.397 12.072 ;
     RECT  33.257 55.968 33.433 56.376 ;
     RECT  33.361 57.36 33.433 63.912 ;
     RECT  32.485 18.48 33.505 32.28 ;
     RECT  33.329 33.312 33.505 34.776 ;
     RECT  33.257 52.416 33.577 53.352 ;
     RECT  33.257 41.664 33.653 42.744 ;
     RECT  33.257 43.824 33.793 48.6 ;
     RECT  33.433 55.968 33.829 63.912 ;
     RECT  33.397 10.464 33.932 12.072 ;
     RECT  32.537 7.152 33.973 9.288 ;
     RECT  33.932 10.464 33.973 12.264 ;
     RECT  33.793 43.824 34.117 48.792 ;
     RECT  33.577 52.416 34.165 53.4 ;
     RECT  33.257 51.216 34.225 51.24 ;
     RECT  33.257 54.576 34.261 54.696 ;
     RECT  33.829 55.968 34.261 64.344 ;
     RECT  34.225 51.168 34.309 51.24 ;
     RECT  33.505 18.48 34.405 34.776 ;
     RECT  32.965 3.312 34.441 4.2 ;
     RECT  33.155 37.584 34.441 38.952 ;
     RECT  34.117 43.824 34.549 49.896 ;
     RECT  34.309 51.168 34.549 51.432 ;
     RECT  33.073 13.344 34.585 17.496 ;
     RECT  34.405 18.48 34.585 35.544 ;
     RECT  34.585 18.48 34.621 35.784 ;
     RECT  34.441 37.584 34.657 39.24 ;
     RECT  33.653 41.664 34.693 41.688 ;
     RECT  33.653 42.72 34.693 42.744 ;
     RECT  33.973 7.152 34.729 12.264 ;
     RECT  34.585 13.296 34.729 17.496 ;
     RECT  34.621 18.48 34.729 35.976 ;
     RECT  34.657 37.584 34.729 39.768 ;
     RECT  34.441 3.312 34.808 4.248 ;
     RECT  32.893 5.424 34.808 5.496 ;
     RECT  34.729 7.152 34.808 17.496 ;
     RECT  34.729 18.48 34.808 36.072 ;
     RECT  34.729 37.584 34.808 40.68 ;
     RECT  34.693 41.664 34.808 42.744 ;
     RECT  34.549 43.824 34.808 51.432 ;
     RECT  34.165 52.416 34.808 53.544 ;
     RECT  34.261 54.576 34.808 64.344 ;
     RECT  34.808 2.148 34.912 66.972 ;
     RECT  34.912 2.418 35.104 66.702 ;
     RECT  35.104 39.744 35.165 42.696 ;
     RECT  35.104 5.472 35.267 36.264 ;
     RECT  35.267 5.472 35.309 6.312 ;
     RECT  35.104 50.064 35.309 53.544 ;
     RECT  35.104 55.008 35.345 64.536 ;
     RECT  35.267 7.44 35.381 36.264 ;
     RECT  35.165 39.744 35.381 39.768 ;
     RECT  35.104 43.872 35.381 48.792 ;
     RECT  35.345 55.152 35.411 64.536 ;
     RECT  35.104 3.312 35.417 4.248 ;
     RECT  35.381 35.52 35.525 35.928 ;
     RECT  35.417 3.312 35.633 4.2 ;
     RECT  35.104 37.584 35.633 38.184 ;
     RECT  35.381 7.44 35.921 34.008 ;
     RECT  35.633 37.584 35.921 38.136 ;
     RECT  35.309 51.168 35.957 53.544 ;
     RECT  35.633 4.176 35.993 4.2 ;
     RECT  35.921 8.784 36.029 34.008 ;
     RECT  35.921 7.44 36.371 7.8 ;
     RECT  35.411 55.152 36.421 64.488 ;
     RECT  35.104 65.568 36.421 66.168 ;
     RECT  36.029 10.416 36.467 34.008 ;
     RECT  36.421 55.152 36.497 66.168 ;
     RECT  36.497 55.152 36.565 64.344 ;
     RECT  36.371 7.44 36.605 7.464 ;
     RECT  35.957 51.216 36.713 53.544 ;
     RECT  36.029 8.784 36.749 9.144 ;
     RECT  35.525 35.904 36.785 35.928 ;
     RECT  35.165 41.616 36.785 42.696 ;
     RECT  36.565 54.72 36.785 64.344 ;
     RECT  36.785 41.616 36.965 42.6 ;
     RECT  36.713 51.216 37.001 53.448 ;
     RECT  35.309 50.064 37.033 50.088 ;
     RECT  36.965 41.616 37.069 41.64 ;
     RECT  35.381 43.872 37.141 48.408 ;
     RECT  37.033 50.064 37.141 50.184 ;
     RECT  37.069 41.568 37.153 41.64 ;
     RECT  36.925 39.648 37.357 39.672 ;
     RECT  37.004 37.008 37.465 37.032 ;
     RECT  37.153 41.616 37.613 41.64 ;
     RECT  36.497 65.376 37.613 66.168 ;
     RECT  35.309 5.472 37.621 5.496 ;
     RECT  37.357 7.632 37.645 7.656 ;
     RECT  36.749 8.784 37.645 9.096 ;
     RECT  37.465 36.96 37.645 37.032 ;
     RECT  35.921 38.112 37.645 38.136 ;
     RECT  37.58 4.368 37.667 4.392 ;
     RECT  37.621 5.472 37.685 6.312 ;
     RECT  36.467 13.392 37.685 34.008 ;
     RECT  37.357 39.648 37.685 40.584 ;
     RECT  37.685 32.304 37.789 34.008 ;
     RECT  37.645 36.96 37.813 38.136 ;
     RECT  37.685 39.648 37.813 39.672 ;
     RECT  37.813 36.96 37.859 39.672 ;
     RECT  36.785 55.152 37.861 64.344 ;
     RECT  37.859 36.96 37.865 37.608 ;
     RECT  37.859 38.88 37.9 39.672 ;
     RECT  37.861 55.152 38.189 64.392 ;
     RECT  37.789 32.304 38.225 34.392 ;
     RECT  37.613 66.144 38.225 66.168 ;
     RECT  37.685 6.288 38.245 6.312 ;
     RECT  37.645 7.632 38.245 9.096 ;
     RECT  37.141 43.872 38.257 50.184 ;
     RECT  37.001 51.216 38.257 53.352 ;
     RECT  38.245 6.288 38.341 9.096 ;
     RECT  38.257 43.104 38.437 50.184 ;
     RECT  38.257 51.168 38.545 53.352 ;
     RECT  36.565 2.832 38.581 2.856 ;
     RECT  37.685 13.392 38.653 30.648 ;
     RECT  38.341 6.288 38.689 6.408 ;
     RECT  38.636 35.904 38.723 35.928 ;
     RECT  38.653 13.392 38.729 31.176 ;
     RECT  37.9 39.312 38.753 39.672 ;
     RECT  38.617 41.04 38.753 41.064 ;
     RECT  38.437 42.336 38.765 50.184 ;
     RECT  38.753 39.312 38.819 41.064 ;
     RECT  38.819 39.312 38.837 40.968 ;
     RECT  38.729 18.48 38.869 31.176 ;
     RECT  38.225 32.304 38.869 33.624 ;
     RECT  38.341 7.632 38.873 9.096 ;
     RECT  38.729 13.392 38.905 17.496 ;
     RECT  38.765 44.016 38.981 50.184 ;
     RECT  38.765 42.336 39.085 42.6 ;
     RECT  37.865 37.152 39.157 37.608 ;
     RECT  38.581 2.832 39.161 3 ;
     RECT  38.545 51.168 39.253 53.544 ;
     RECT  38.905 54.72 39.253 54.744 ;
     RECT  38.189 56.016 39.697 64.392 ;
     RECT  38.869 18.48 39.733 33.624 ;
     RECT  39.733 18.48 39.769 34.152 ;
     RECT  39.733 35.232 39.769 35.784 ;
     RECT  39.769 18.48 39.877 35.784 ;
     RECT  39.157 37.152 39.877 38.184 ;
     RECT  38.293 66.192 40.021 66.216 ;
     RECT  38.981 44.016 40.057 44.184 ;
     RECT  38.873 8.16 40.165 9.096 ;
     RECT  38.905 12.816 40.165 17.496 ;
     RECT  39.877 18.48 40.165 38.184 ;
     RECT  40.057 43.872 40.201 44.184 ;
     RECT  38.981 45.264 40.201 50.184 ;
     RECT  39.161 2.832 40.208 2.856 ;
     RECT  38.689 5.856 40.208 6.408 ;
     RECT  40.165 7.392 40.208 9.096 ;
     RECT  36.467 10.416 40.208 11.832 ;
     RECT  40.165 12.816 40.208 38.184 ;
     RECT  38.837 39.648 40.208 39.672 ;
     RECT  38.837 40.944 40.208 40.968 ;
     RECT  39.085 42.192 40.208 42.6 ;
     RECT  40.201 43.872 40.208 50.184 ;
     RECT  39.253 51.168 40.208 54.744 ;
     RECT  39.697 56.016 40.208 64.68 ;
     RECT  40.021 66.048 40.208 66.216 ;
     RECT  40.208 2.148 40.312 66.972 ;
     RECT  40.312 2.418 40.504 66.702 ;
     RECT  40.504 2.832 40.643 2.856 ;
     RECT  40.504 3.84 40.643 5.16 ;
     RECT  40.504 12.912 40.673 38.184 ;
     RECT  40.504 8.16 40.781 11.832 ;
     RECT  40.673 30.144 40.835 38.184 ;
     RECT  40.835 30.24 40.889 38.184 ;
     RECT  40.889 30.24 40.925 34.44 ;
     RECT  40.643 4.512 41.069 5.16 ;
     RECT  40.925 30.24 41.213 33.624 ;
     RECT  40.504 43.872 41.213 53.064 ;
     RECT  40.889 35.712 41.501 38.184 ;
     RECT  41.213 44.16 41.645 53.064 ;
     RECT  40.504 54.336 41.653 65.016 ;
     RECT  41.645 44.16 41.753 49.608 ;
     RECT  40.504 42.72 41.821 42.744 ;
     RECT  40.781 10.272 41.857 11.832 ;
     RECT  40.673 12.912 41.857 28.776 ;
     RECT  41.821 42.336 41.929 42.744 ;
     RECT  41.645 50.736 41.929 53.064 ;
     RECT  41.653 54.288 41.929 65.016 ;
     RECT  41.929 50.736 41.933 65.016 ;
     RECT  41.933 50.928 42.037 65.016 ;
     RECT  40.504 66.048 42.037 66.264 ;
     RECT  41.857 10.272 42.073 28.776 ;
     RECT  41.501 36.576 42.073 38.184 ;
     RECT  42.085 40.752 42.172 40.776 ;
     RECT  41.069 5.136 42.185 5.16 ;
     RECT  42.181 0.576 42.217 0.6 ;
     RECT  42.073 36.576 42.293 38.952 ;
     RECT  42.217 0.576 42.323 0.696 ;
     RECT  42.037 50.928 42.329 66.264 ;
     RECT  42.293 38.112 42.365 38.952 ;
     RECT  42.289 1.68 42.373 1.704 ;
     RECT  42.373 1.68 42.397 1.752 ;
     RECT  42.289 5.376 42.421 5.688 ;
     RECT  42.421 5.376 42.467 6.648 ;
     RECT  41.929 42.336 42.473 43.176 ;
     RECT  40.781 8.16 42.505 9.096 ;
     RECT  42.365 38.16 42.505 38.952 ;
     RECT  42.145 35.088 42.613 35.592 ;
     RECT  42.293 36.576 42.613 37.08 ;
     RECT  42.505 38.16 42.725 39 ;
     RECT  42.397 1.104 42.757 1.752 ;
     RECT  42.181 2.832 42.757 2.856 ;
     RECT  42.467 5.664 42.757 6.648 ;
     RECT  42.505 7.92 42.757 9.096 ;
     RECT  42.073 10.272 42.757 29.112 ;
     RECT  42.613 35.088 42.761 37.08 ;
     RECT  42.757 5.664 42.793 9.096 ;
     RECT  42.757 10.272 42.793 29.352 ;
     RECT  42.473 42.528 42.803 43.176 ;
     RECT  42.725 38.4 42.833 39 ;
     RECT  42.821 0.096 42.905 0.12 ;
     RECT  42.757 1.104 42.941 3.72 ;
     RECT  41.753 44.16 42.973 49.32 ;
     RECT  42.329 50.928 42.973 66.12 ;
     RECT  41.213 30.48 42.977 33.624 ;
     RECT  42.761 35.904 43.121 37.08 ;
     RECT  43.121 36.288 43.193 37.08 ;
     RECT  42.973 44.16 43.301 66.12 ;
     RECT  43.193 36.288 43.337 36.6 ;
     RECT  43.301 66.096 43.369 66.12 ;
     RECT  42.833 38.4 43.373 38.712 ;
     RECT  42.829 34.848 43.513 34.872 ;
     RECT  43.525 3.984 43.585 4.008 ;
     RECT  42.803 42.528 43.621 42.744 ;
     RECT  43.513 34.8 43.661 34.872 ;
     RECT  42.977 30.48 43.693 33.576 ;
     RECT  43.585 3.984 43.729 4.632 ;
     RECT  42.793 5.664 43.729 29.352 ;
     RECT  43.297 40.464 43.837 40.488 ;
     RECT  43.729 3.984 43.859 29.352 ;
     RECT  42.941 1.104 43.909 2.904 ;
     RECT  43.373 38.688 43.985 38.712 ;
     RECT  43.909 0.528 44.051 2.904 ;
     RECT  44.051 2.256 44.065 2.904 ;
     RECT  43.859 5.136 44.089 29.352 ;
     RECT  43.693 30.336 44.089 33.576 ;
     RECT  43.661 34.848 44.165 34.872 ;
     RECT  43.337 36.288 44.165 36.36 ;
     RECT  44.165 36.336 44.237 36.36 ;
     RECT  43.837 40.464 44.252 41.352 ;
     RECT  44.252 40.224 44.339 41.352 ;
     RECT  44.051 0.528 44.341 1.128 ;
     RECT  43.621 42.336 44.437 42.744 ;
     RECT  43.301 44.16 44.437 64.68 ;
     RECT  44.437 42.336 44.444 64.68 ;
     RECT  43.369 66.096 44.444 66.168 ;
     RECT  44.339 41.04 44.489 41.352 ;
     RECT  44.444 42.336 44.524 66.168 ;
     RECT  44.524 44.736 44.531 66.168 ;
     RECT  44.524 42.336 44.597 43.128 ;
     RECT  44.065 2.688 44.629 2.904 ;
     RECT  43.859 3.984 44.629 4.008 ;
     RECT  44.053 38.736 44.809 38.952 ;
     RECT  44.629 2.688 45.301 4.008 ;
     RECT  44.341 0.144 45.421 1.128 ;
     RECT  45.301 2.496 45.608 4.008 ;
     RECT  44.089 5.136 45.608 33.576 ;
     RECT  45.205 35.808 45.608 35.832 ;
     RECT  45.529 37.104 45.608 37.128 ;
     RECT  44.809 38.736 45.608 40.008 ;
     RECT  44.489 41.04 45.608 41.064 ;
     RECT  44.597 43.104 45.608 43.128 ;
     RECT  44.531 44.736 45.608 64.68 ;
     RECT  44.531 66.144 45.608 66.168 ;
     RECT  45.421 0.096 45.637 1.128 ;
     RECT  45.608 2.148 45.712 66.972 ;
     RECT  45.637 0.096 45.785 1.176 ;
     RECT  45.712 2.148 45.877 66.702 ;
     RECT  45.877 1.728 45.904 66.702 ;
     RECT  45.904 42.432 46.001 65.544 ;
     RECT  45.785 0.096 46.067 0.408 ;
     RECT  45.904 1.728 46.181 39.624 ;
     RECT  46.181 37.104 46.253 39.624 ;
     RECT  45.904 41.376 46.361 41.4 ;
     RECT  46.253 37.104 46.505 37.128 ;
     RECT  46.001 42.432 46.547 50.616 ;
     RECT  46.547 45.696 46.649 50.616 ;
     RECT  46.547 42.432 46.793 44.472 ;
     RECT  46.649 45.696 46.829 48.312 ;
     RECT  46.181 2.256 46.937 35.832 ;
     RECT  46.253 38.256 46.973 39.624 ;
     RECT  46.649 49.296 47.045 50.616 ;
     RECT  46.937 2.256 47.117 33.336 ;
     RECT  46.067 0.096 47.153 0.168 ;
     RECT  46.001 51.6 47.333 65.544 ;
     RECT  47.117 2.256 47.369 7.656 ;
     RECT  47.333 54.336 47.369 65.544 ;
     RECT  46.937 34.368 47.405 35.832 ;
     RECT  47.369 2.256 47.411 6.6 ;
     RECT  47.005 41.04 47.413 41.064 ;
     RECT  46.793 42.432 47.413 43.272 ;
     RECT  47.153 0.096 47.441 0.12 ;
     RECT  46.829 45.696 47.441 47.928 ;
     RECT  47.413 40.8 47.477 41.064 ;
     RECT  46.793 44.352 47.477 44.472 ;
     RECT  47.477 40.8 47.5 40.824 ;
     RECT  47.413 42.192 47.5 43.272 ;
     RECT  47.117 8.736 47.513 33.336 ;
     RECT  47.5 42.576 47.621 43.272 ;
     RECT  47.477 44.448 47.621 44.472 ;
     RECT  47.369 54.432 47.653 65.544 ;
     RECT  47.405 35.328 47.657 35.832 ;
     RECT  46.973 38.688 47.801 39.624 ;
     RECT  47.045 49.392 47.833 50.616 ;
     RECT  47.333 51.6 47.833 53.304 ;
     RECT  47.513 33.312 47.905 33.336 ;
     RECT  47.833 37.296 47.941 37.32 ;
     RECT  47.557 1.728 48.037 1.896 ;
     RECT  47.833 49.392 48.049 53.304 ;
     RECT  47.369 7.632 48.085 7.656 ;
     RECT  47.513 8.736 48.085 32.328 ;
     RECT  48.049 49.296 48.193 53.304 ;
     RECT  48.037 1.152 48.269 1.896 ;
     RECT  48.193 49.008 48.341 53.304 ;
     RECT  48.269 1.68 48.38 1.896 ;
     RECT  47.411 2.88 48.38 6.6 ;
     RECT  47.801 39.312 48.409 39.624 ;
     RECT  47.441 45.744 48.409 47.928 ;
     RECT  48.341 49.152 48.409 53.304 ;
     RECT  47.653 54.432 48.409 66.456 ;
     RECT  48.409 49.152 48.413 66.456 ;
     RECT  48.409 39.312 48.449 39.912 ;
     RECT  48.38 1.68 48.467 6.6 ;
     RECT  48.467 2.832 48.553 6.6 ;
     RECT  48.085 7.632 48.553 32.328 ;
     RECT  47.941 36.432 48.557 37.32 ;
     RECT  48.517 0.096 48.689 0.12 ;
     RECT  48.449 39.888 48.733 39.912 ;
     RECT  48.689 0.096 48.773 0.168 ;
     RECT  48.733 39.888 48.773 40.2 ;
     RECT  47.905 33.312 48.805 33.912 ;
     RECT  47.657 35.328 48.805 35.352 ;
     RECT  48.409 45.168 48.805 47.928 ;
     RECT  48.557 36.912 48.809 37.32 ;
     RECT  48.809 36.912 48.851 36.936 ;
     RECT  47.621 43.248 48.851 43.272 ;
     RECT  48.773 40.176 48.997 40.2 ;
     RECT  48.997 40.176 49.084 41.064 ;
     RECT  48.413 49.152 49.097 65.496 ;
     RECT  49.084 40.176 49.139 40.968 ;
     RECT  48.467 1.68 49.235 1.8 ;
     RECT  48.553 2.832 49.309 32.328 ;
     RECT  48.805 33.312 49.309 35.352 ;
     RECT  49.309 2.832 49.523 35.352 ;
     RECT  49.523 4.512 49.525 35.352 ;
     RECT  49.097 49.152 49.525 65.4 ;
     RECT  48.805 45.024 49.561 47.928 ;
     RECT  49.525 48.96 49.561 65.4 ;
     RECT  49.235 1.728 49.597 1.8 ;
     RECT  49.523 2.832 49.597 3.336 ;
     RECT  49.525 4.512 49.619 35.448 ;
     RECT  49.561 45.024 49.853 65.4 ;
     RECT  49.853 45.024 49.889 49.32 ;
     RECT  49.813 36.48 49.96 36.504 ;
     RECT  49.889 48.96 49.961 49.32 ;
     RECT  49.96 36.48 50.101 36.552 ;
     RECT  49.853 50.592 50.137 65.4 ;
     RECT  49.597 1.728 50.204 3.336 ;
     RECT  50.137 40.848 50.209 40.872 ;
     RECT  49.957 68.352 50.245 68.376 ;
     RECT  50.204 1.104 50.291 3.336 ;
     RECT  49.619 33.312 50.317 35.448 ;
     RECT  50.101 36.432 50.317 36.552 ;
     RECT  50.209 40.032 50.353 40.872 ;
     RECT  50.245 68.352 50.389 68.952 ;
     RECT  50.389 67.824 50.434 68.952 ;
     RECT  50.353 40.032 50.461 40.968 ;
     RECT  49.619 4.512 50.713 32.328 ;
     RECT  50.317 33.312 50.713 36.552 ;
     RECT  48.773 0.096 50.821 0.12 ;
     RECT  49.669 66.672 50.821 66.696 ;
     RECT  50.434 67.824 50.821 69 ;
     RECT  49.889 45.024 50.849 47.928 ;
     RECT  50.291 1.728 50.869 3.336 ;
     RECT  50.713 4.512 50.869 36.552 ;
     RECT  50.821 66.672 50.897 69 ;
     RECT  50.849 44.448 50.965 47.928 ;
     RECT  49.961 49.056 50.965 49.32 ;
     RECT  50.869 1.728 51.008 36.552 ;
     RECT  50.461 39.552 51.008 40.968 ;
     RECT  50.893 42.48 51.008 42.504 ;
     RECT  50.965 44.448 51.008 49.32 ;
     RECT  50.137 50.592 51.008 65.496 ;
     RECT  50.897 66.672 51.008 68.952 ;
     RECT  50.821 0.096 51.059 0.312 ;
     RECT  51.008 1.728 51.304 68.952 ;
     RECT  51.304 50.352 51.473 68.952 ;
     RECT  51.304 46.32 51.581 49.32 ;
     RECT  51.473 50.352 51.581 67.8 ;
     RECT  51.304 33.312 51.587 37.608 ;
     RECT  51.473 68.928 51.683 68.952 ;
     RECT  51.581 50.352 51.689 67.272 ;
     RECT  51.689 66.576 51.761 67.272 ;
     RECT  51.304 40.752 51.833 41.976 ;
     RECT  51.304 43.056 51.833 43.08 ;
     RECT  51.761 66.576 51.833 67.224 ;
     RECT  51.833 40.752 51.869 41.304 ;
     RECT  51.689 50.352 51.875 65.4 ;
     RECT  51.875 50.592 51.905 65.4 ;
     RECT  51.587 33.888 51.923 37.608 ;
     RECT  51.923 33.888 51.941 33.912 ;
     RECT  51.304 1.728 51.977 6.936 ;
     RECT  51.833 66.576 52.021 66.696 ;
     RECT  51.905 50.928 52.049 65.4 ;
     RECT  51.977 6.336 52.057 6.936 ;
     RECT  51.304 38.688 52.121 39.624 ;
     RECT  51.869 40.752 52.121 41.064 ;
     RECT  51.059 0.096 52.22 0.216 ;
     RECT  52.121 38.688 52.307 38.712 ;
     RECT  51.304 8.256 52.333 32.328 ;
     RECT  52.121 40.896 52.345 41.064 ;
     RECT  52.22 0.096 52.445 0.552 ;
     RECT  52.057 6.384 52.445 6.936 ;
     RECT  52.345 40.896 52.445 40.92 ;
     RECT  52.508 68.4 52.595 68.424 ;
     RECT  52.333 8.208 52.621 32.328 ;
     RECT  51.923 35.04 52.697 37.608 ;
     RECT  51.977 1.728 52.705 5.16 ;
     RECT  52.621 8.208 52.765 32.472 ;
     RECT  51.304 45.264 52.765 45.288 ;
     RECT  52.445 6.576 52.801 6.936 ;
     RECT  52.765 8.208 52.801 33 ;
     RECT  52.021 66.624 52.837 66.696 ;
     RECT  52.741 68.928 52.931 68.952 ;
     RECT  51.581 46.32 52.981 48.168 ;
     RECT  51.581 49.296 52.981 49.32 ;
     RECT  52.837 66.624 52.985 67.272 ;
     RECT  52.765 44.928 53.021 45.288 ;
     RECT  52.697 35.04 53.057 36.888 ;
     RECT  52.705 2.832 53.092 5.16 ;
     RECT  53.009 0.576 53.093 0.6 ;
     RECT  52.049 51.36 53.161 65.4 ;
     RECT  53.092 2.832 53.201 5.208 ;
     RECT  53.057 35.088 53.212 35.832 ;
     RECT  52.801 6.576 53.305 33 ;
     RECT  52.981 46.32 53.305 49.32 ;
     RECT  53.161 50.832 53.489 65.4 ;
     RECT  53.305 6.576 53.509 33.336 ;
     RECT  53.509 6.288 53.557 33.336 ;
     RECT  53.557 6.288 53.561 33.48 ;
     RECT  53.489 50.976 53.593 65.4 ;
     RECT  53.305 46.32 53.597 49.848 ;
     RECT  53.561 6.288 53.605 29.592 ;
     RECT  53.057 36.864 53.665 36.888 ;
     RECT  53.021 45.264 53.804 45.288 ;
     RECT  53.597 46.32 53.804 49.128 ;
     RECT  53.593 50.976 53.809 65.448 ;
     RECT  53.809 50.976 53.813 65.544 ;
     RECT  53.201 2.832 53.849 4.632 ;
     RECT  53.849 3.408 53.891 4.632 ;
     RECT  53.804 45.264 53.891 49.128 ;
     RECT  53.797 0.288 53.893 0.312 ;
     RECT  53.665 36.864 53.917 37.464 ;
     RECT  53.893 0.192 53.938 0.312 ;
     RECT  53.917 36.864 53.953 38.424 ;
     RECT  53.938 0.096 53.954 0.312 ;
     RECT  53.561 30.72 53.989 33.48 ;
     RECT  53.813 51.408 54.029 65.544 ;
     RECT  52.705 1.728 54.085 1.8 ;
     RECT  53.891 46.32 54.101 49.128 ;
     RECT  53.954 0.096 54.131 0.264 ;
     RECT  53.989 30.72 54.133 33.576 ;
     RECT  54.029 51.504 54.133 65.544 ;
     RECT  54.133 40.464 54.169 40.488 ;
     RECT  54.133 51.504 54.205 65.592 ;
     RECT  53.212 35.184 54.277 35.832 ;
     RECT  53.953 36.864 54.277 38.568 ;
     RECT  53.891 4.512 54.325 4.632 ;
     RECT  53.605 5.712 54.325 29.592 ;
     RECT  54.169 40.464 54.353 40.872 ;
     RECT  54.131 0.096 54.371 0.216 ;
     RECT  54.133 30.72 54.419 33.672 ;
     RECT  53.845 43.824 54.565 43.848 ;
     RECT  54.205 51.504 54.565 65.64 ;
     RECT  52.985 66.624 54.565 66.936 ;
     RECT  54.419 33.312 54.601 33.672 ;
     RECT  54.277 35.184 54.601 38.568 ;
     RECT  54.325 4.512 54.637 29.592 ;
     RECT  54.419 30.72 54.637 32.328 ;
     RECT  54.637 4.512 54.659 32.328 ;
     RECT  54.565 42.864 54.713 43.848 ;
     RECT  54.565 51.504 54.713 66.936 ;
     RECT  54.659 4.56 54.721 32.328 ;
     RECT  54.353 40.608 54.901 40.872 ;
     RECT  54.085 1.728 54.949 2.328 ;
     RECT  53.891 3.408 54.949 3.432 ;
     RECT  54.371 0.096 55.037 0.12 ;
     RECT  54.101 47.04 55.361 49.128 ;
     RECT  54.713 43.824 55.429 43.848 ;
     RECT  55.421 0.144 55.505 0.6 ;
     RECT  54.901 40.608 55.681 41.064 ;
     RECT  55.141 42.816 55.681 42.84 ;
     RECT  55.361 48.336 55.681 49.128 ;
     RECT  54.721 31.152 55.861 32.328 ;
     RECT  54.601 33.312 55.861 38.568 ;
     RECT  54.713 51.504 55.861 66.168 ;
     RECT  55.681 40.608 55.868 41.16 ;
     RECT  54.949 1.728 55.897 3.432 ;
     RECT  54.721 4.56 55.897 30.12 ;
     RECT  55.861 51.504 55.969 66.696 ;
     RECT  55.969 50.688 56.069 66.696 ;
     RECT  55.861 68.4 56.177 68.424 ;
     RECT  56.177 68.4 56.261 69 ;
     RECT  55.505 0.144 56.293 0.264 ;
     RECT  55.361 47.04 56.293 47.304 ;
     RECT  55.897 1.728 56.408 30.12 ;
     RECT  55.861 31.152 56.408 38.568 ;
     RECT  55.868 39.888 56.408 41.16 ;
     RECT  55.681 42.336 56.408 42.84 ;
     RECT  55.429 43.824 56.408 44.616 ;
     RECT  56.293 46.704 56.408 47.304 ;
     RECT  55.681 48.336 56.408 49.608 ;
     RECT  56.069 50.688 56.408 67.272 ;
     RECT  56.293 0.096 56.485 0.264 ;
     RECT  56.408 1.728 56.704 67.272 ;
     RECT  56.704 48.384 56.765 49.608 ;
     RECT  56.704 1.728 56.819 41.16 ;
     RECT  56.704 45.888 56.819 47.064 ;
     RECT  56.704 51.168 56.837 67.272 ;
     RECT  56.485 0.096 56.867 0.36 ;
     RECT  56.765 48.48 56.981 49.608 ;
     RECT  56.837 51.168 57.107 65.736 ;
     RECT  56.837 66.912 57.203 67.272 ;
     RECT  56.261 68.4 57.253 68.952 ;
     RECT  56.704 43.392 57.413 43.848 ;
     RECT  56.819 4.704 57.443 41.16 ;
     RECT  57.203 67.248 57.637 67.272 ;
     RECT  57.253 68.4 57.637 69 ;
     RECT  56.819 1.728 57.731 3.432 ;
     RECT  56.819 45.888 57.845 46.824 ;
     RECT  57.731 2.256 57.884 3.432 ;
     RECT  57.443 4.704 57.884 32.328 ;
     RECT  57.829 42.192 57.913 42.216 ;
     RECT  57.413 43.392 57.913 43.416 ;
     RECT  57.637 67.248 57.971 69 ;
     RECT  57.913 42.192 57.989 43.416 ;
     RECT  56.981 48.672 57.993 49.608 ;
     RECT  57.989 42.192 58.025 42.888 ;
     RECT  58.025 42.192 58.067 42.744 ;
     RECT  57.845 45.888 58.067 45.912 ;
     RECT  56.867 0.096 58.213 0.12 ;
     RECT  57.443 33.312 58.237 41.16 ;
     RECT  58.213 0.096 58.261 0.216 ;
     RECT  57.884 2.256 58.489 32.328 ;
     RECT  58.237 33.312 58.489 41.208 ;
     RECT  57.107 51.168 58.501 65.64 ;
     RECT  57.993 48.672 58.525 50.136 ;
     RECT  58.501 51.168 58.525 65.784 ;
     RECT  57.971 68.928 58.595 69 ;
     RECT  58.067 42.24 58.781 42.744 ;
     RECT  57.971 67.248 58.94 67.8 ;
     RECT  58.957 47.28 58.993 47.304 ;
     RECT  58.453 43.872 59.065 43.896 ;
     RECT  59.065 43.872 59.105 44.472 ;
     RECT  58.525 48.672 59.209 65.784 ;
     RECT  58.94 66.912 59.209 67.8 ;
     RECT  58.489 2.256 59.267 41.208 ;
     RECT  58.993 47.28 59.269 47.544 ;
     RECT  59.209 48.672 59.269 67.8 ;
     RECT  58.261 0.096 59.365 0.312 ;
     RECT  59.267 2.256 59.425 38.616 ;
     RECT  59.365 0.096 59.461 0.6 ;
     RECT  59.269 47.28 59.465 67.8 ;
     RECT  58.633 45.6 59.569 45.624 ;
     RECT  59.465 47.28 59.569 47.544 ;
     RECT  59.461 0.096 59.605 0.648 ;
     RECT  59.569 45.6 59.681 47.544 ;
     RECT  59.465 48.672 59.713 67.8 ;
     RECT  58.595 68.976 59.713 69 ;
     RECT  58.781 42.624 59.749 42.648 ;
     RECT  59.605 0.096 59.795 1.128 ;
     RECT  59.425 2.16 59.797 38.616 ;
     RECT  59.749 42.624 59.861 42.792 ;
     RECT  59.713 48.672 59.897 69 ;
     RECT  59.267 39.792 60.041 41.208 ;
     RECT  59.797 2.112 60.101 38.616 ;
     RECT  59.897 48.912 60.113 69 ;
     RECT  59.105 44.448 60.181 44.472 ;
     RECT  60.101 1.728 60.185 38.616 ;
     RECT  59.681 45.6 60.257 47.304 ;
     RECT  60.181 43.632 60.365 44.472 ;
     RECT  60.185 2.16 60.421 38.616 ;
     RECT  60.041 39.84 60.937 41.208 ;
     RECT  59.861 42.624 60.937 42.648 ;
     RECT  60.937 39.84 60.973 42.648 ;
     RECT  60.365 43.632 60.973 44.232 ;
     RECT  60.113 48.912 61.091 68.952 ;
     RECT  59.795 0.096 61.093 0.6 ;
     RECT  61.093 0.096 61.235 1.176 ;
     RECT  61.235 0.096 61.265 0.6 ;
     RECT  61.091 68.304 61.285 68.952 ;
     RECT  60.421 2.16 61.441 38.808 ;
     RECT  60.973 39.84 61.441 44.232 ;
     RECT  61.265 0.144 61.619 0.6 ;
     RECT  60.257 45.744 61.669 47.304 ;
     RECT  61.091 48.912 61.669 67.272 ;
     RECT  61.441 2.16 61.729 44.232 ;
     RECT  61.729 2.16 61.808 44.376 ;
     RECT  61.669 45.744 61.808 67.272 ;
     RECT  61.808 2.148 61.957 67.272 ;
     RECT  61.957 1.728 62.104 67.272 ;
     RECT  62.104 46.128 62.489 48.024 ;
     RECT  61.619 0.144 62.557 0.552 ;
     RECT  62.104 49.488 62.669 67.272 ;
     RECT  62.557 0.096 62.675 0.552 ;
     RECT  62.675 0.48 62.725 0.552 ;
     RECT  62.669 49.488 62.777 66.504 ;
     RECT  62.104 42.144 62.819 43.704 ;
     RECT  62.725 0.48 62.867 0.6 ;
     RECT  62.104 1.728 62.917 39.48 ;
     RECT  62.819 42.144 62.921 42.792 ;
     RECT  62.104 44.688 62.957 44.712 ;
     RECT  61.285 68.304 63.029 69 ;
     RECT  62.777 49.488 63.277 66.456 ;
     RECT  62.917 1.152 63.353 39.48 ;
     RECT  63.277 49.152 63.353 66.456 ;
     RECT  62.489 47.904 63.421 48.024 ;
     RECT  63.353 49.152 63.421 65.496 ;
     RECT  63.353 1.152 63.425 38.712 ;
     RECT  63.421 47.904 63.596 65.496 ;
     RECT  62.489 46.128 63.605 46.296 ;
     RECT  63.425 1.152 63.731 37.128 ;
     RECT  63.731 1.152 63.779 37.08 ;
     RECT  63.029 68.976 63.821 69 ;
     RECT  62.921 42.72 64.001 42.792 ;
     RECT  63.925 0.528 64.019 0.6 ;
     RECT  63.596 47.712 64.028 65.496 ;
     RECT  63.745 66.864 64.069 66.888 ;
     RECT  64.028 47.184 64.153 65.496 ;
     RECT  64.153 47.184 64.253 47.736 ;
     RECT  63.425 38.112 64.357 38.712 ;
     RECT  64.153 48.864 64.361 65.496 ;
     RECT  64.361 56.352 64.429 65.496 ;
     RECT  64.069 66.864 64.429 67.272 ;
     RECT  64.357 38.112 64.444 38.904 ;
     RECT  63.781 44.976 64.505 45 ;
     RECT  64.444 38.112 64.541 38.472 ;
     RECT  64.429 56.352 64.541 67.272 ;
     RECT  64.541 38.112 64.613 38.184 ;
     RECT  63.605 46.128 64.739 46.152 ;
     RECT  63.779 1.728 64.861 37.08 ;
     RECT  64.613 38.112 64.861 38.136 ;
     RECT  64.361 48.864 64.865 55.224 ;
     RECT  64.019 0.576 65.125 0.6 ;
     RECT  64.253 47.712 65.257 47.736 ;
     RECT  65.257 47.712 65.341 47.88 ;
     RECT  64.865 48.96 65.404 55.224 ;
     RECT  65.404 48.96 65.405 54.888 ;
     RECT  64.541 56.4 65.516 67.272 ;
     RECT  64.861 1.728 65.585 38.136 ;
     RECT  65.516 55.92 65.585 67.272 ;
     RECT  65.585 1.728 65.596 35.88 ;
     RECT  65.585 55.92 65.603 56.952 ;
     RECT  65.041 46.224 65.621 46.248 ;
     RECT  65.596 1.728 65.693 35.736 ;
     RECT  64.001 42.768 65.701 42.792 ;
     RECT  65.701 42.768 65.747 43.368 ;
     RECT  65.693 35.616 65.765 35.736 ;
     RECT  65.113 44.448 65.765 44.472 ;
     RECT  65.405 51.504 65.765 54.888 ;
     RECT  65.765 35.712 65.795 35.736 ;
     RECT  65.405 48.96 65.795 50.184 ;
     RECT  65.747 43.344 65.801 43.368 ;
     RECT  65.585 37.296 65.837 38.136 ;
     RECT  65.795 48.96 65.837 48.984 ;
     RECT  65.473 47.328 65.873 47.352 ;
     RECT  65.693 1.728 65.945 34.056 ;
     RECT  65.585 57.984 65.977 67.272 ;
     RECT  65.977 57.984 66.017 67.464 ;
     RECT  65.837 38.112 66.161 38.136 ;
     RECT  65.603 56.688 66.161 56.952 ;
     RECT  65.945 32.976 66.197 34.056 ;
     RECT  65.765 51.504 66.197 54.552 ;
     RECT  66.161 56.688 66.197 56.76 ;
     RECT  65.945 1.728 66.269 31.944 ;
     RECT  66.197 52.656 66.305 54.552 ;
     RECT  66.269 19.872 66.341 31.944 ;
     RECT  66.017 58.368 66.341 67.464 ;
     RECT  66.197 32.976 66.377 33.72 ;
     RECT  66.305 53.712 66.377 54.552 ;
     RECT  66.377 32.976 66.563 33.672 ;
     RECT  66.197 56.736 66.593 56.76 ;
     RECT  66.341 19.92 66.601 31.944 ;
     RECT  66.269 1.728 66.773 18.888 ;
     RECT  66.563 32.976 66.773 33 ;
     RECT  66.197 51.504 66.805 51.528 ;
     RECT  66.773 4.512 66.809 18.888 ;
     RECT  66.341 58.368 66.809 61.992 ;
     RECT  66.809 4.56 66.845 18.888 ;
     RECT  66.845 4.56 66.881 8.712 ;
     RECT  66.809 58.464 66.881 61.992 ;
     RECT  65.795 50.16 66.917 50.184 ;
     RECT  66.773 2.304 67.043 3.432 ;
     RECT  66.881 5.76 67.187 8.712 ;
     RECT  66.601 20.4 67.201 31.944 ;
     RECT  66.805 51.408 67.273 51.528 ;
     RECT  66.305 52.656 67.273 52.68 ;
     RECT  66.377 53.712 67.273 54.408 ;
     RECT  67.187 5.76 67.283 6.36 ;
     RECT  66.881 58.608 67.309 61.992 ;
     RECT  66.341 62.976 67.309 67.464 ;
     RECT  66.881 4.56 67.313 4.584 ;
     RECT  66.845 9.696 67.331 18.888 ;
     RECT  67.043 2.304 67.349 3.384 ;
     RECT  67.349 2.736 67.379 3.384 ;
     RECT  67.187 7.872 67.379 8.712 ;
     RECT  65.125 0.096 67.421 0.6 ;
     RECT  67.379 2.736 67.427 2.856 ;
     RECT  67.379 8.064 67.523 8.712 ;
     RECT  67.421 0.096 67.571 0.264 ;
     RECT  67.523 8.4 67.571 8.712 ;
     RECT  67.427 2.784 67.619 2.856 ;
     RECT  67.571 8.4 67.619 8.424 ;
     RECT  67.571 0.096 67.667 0.12 ;
     RECT  67.283 5.76 67.667 5.784 ;
     RECT  67.201 20.4 67.741 32.04 ;
     RECT  67.741 20.208 67.777 32.136 ;
     RECT  67.331 9.84 67.813 18.888 ;
     RECT  67.813 9.84 67.849 19.08 ;
     RECT  67.777 20.112 67.849 32.136 ;
     RECT  67.619 2.784 67.859 2.808 ;
     RECT  67.309 58.608 68.389 67.464 ;
     RECT  68.389 58.416 69.001 67.464 ;
     RECT  67.849 9.84 69.041 9.936 ;
     RECT  67.849 9.936 69.036 9.96 ;
     RECT  67.849 9.96 69.041 10.032 ;
     RECT  67.849 10.032 69.036 10.056 ;
     RECT  67.849 10.056 69.041 10.128 ;
     RECT  67.849 10.128 69.036 10.152 ;
     RECT  67.849 10.152 69.041 10.224 ;
     RECT  67.849 10.224 69.036 10.248 ;
     RECT  67.849 10.248 69.041 10.32 ;
     RECT  67.849 10.32 69.036 10.344 ;
     RECT  67.849 10.344 69.041 10.416 ;
     RECT  67.849 10.416 69.036 10.44 ;
     RECT  67.849 10.44 69.041 10.512 ;
     RECT  67.849 10.512 69.036 10.536 ;
     RECT  67.849 10.536 69.041 10.608 ;
     RECT  67.849 10.608 69.036 10.632 ;
     RECT  67.849 10.632 69.041 10.704 ;
     RECT  67.849 10.704 69.036 10.728 ;
     RECT  67.849 10.728 69.041 10.8 ;
     RECT  67.849 10.8 69.036 10.824 ;
     RECT  67.849 10.824 69.041 10.896 ;
     RECT  67.849 10.896 69.036 10.92 ;
     RECT  67.849 10.92 69.041 10.992 ;
     RECT  67.849 10.992 69.036 11.016 ;
     RECT  67.849 11.016 69.041 11.088 ;
     RECT  67.849 11.088 69.036 11.112 ;
     RECT  67.849 11.112 69.041 11.184 ;
     RECT  67.849 11.184 69.036 11.208 ;
     RECT  67.849 11.208 69.041 11.28 ;
     RECT  67.849 11.28 69.036 11.304 ;
     RECT  67.849 11.304 69.041 11.376 ;
     RECT  67.849 11.376 69.036 11.4 ;
     RECT  67.849 11.4 69.041 11.472 ;
     RECT  67.849 11.472 69.036 11.496 ;
     RECT  67.849 11.496 69.041 11.568 ;
     RECT  67.849 11.568 69.036 11.592 ;
     RECT  67.849 11.592 69.041 11.664 ;
     RECT  67.849 11.664 69.036 11.688 ;
     RECT  67.849 11.688 69.041 11.76 ;
     RECT  67.849 11.76 69.036 11.784 ;
     RECT  67.849 11.784 69.041 11.856 ;
     RECT  67.849 11.856 69.036 11.88 ;
     RECT  67.849 11.88 69.041 11.952 ;
     RECT  67.849 11.952 69.036 11.976 ;
     RECT  67.849 11.976 69.041 12.048 ;
     RECT  67.849 12.048 69.036 12.072 ;
     RECT  67.849 12.072 69.041 12.144 ;
     RECT  67.849 12.144 69.036 12.168 ;
     RECT  67.849 12.168 69.041 12.24 ;
     RECT  67.849 12.24 69.036 12.264 ;
     RECT  67.849 12.264 69.041 12.336 ;
     RECT  67.849 12.336 69.036 12.36 ;
     RECT  67.849 12.36 69.041 12.432 ;
     RECT  67.849 12.432 69.036 12.456 ;
     RECT  67.849 12.456 69.041 12.528 ;
     RECT  67.849 12.528 69.036 12.552 ;
     RECT  67.849 12.552 69.041 12.624 ;
     RECT  67.849 12.624 69.036 12.648 ;
     RECT  67.849 12.648 69.041 12.72 ;
     RECT  67.849 12.72 69.036 12.744 ;
     RECT  67.849 12.744 69.041 12.816 ;
     RECT  67.849 12.816 69.036 12.84 ;
     RECT  67.849 12.84 69.041 12.912 ;
     RECT  67.849 12.912 69.036 12.936 ;
     RECT  67.849 12.936 69.041 13.008 ;
     RECT  67.849 13.008 69.036 13.032 ;
     RECT  67.849 13.032 69.041 13.104 ;
     RECT  67.849 13.104 69.036 13.128 ;
     RECT  67.849 13.128 69.041 13.2 ;
     RECT  67.849 13.2 69.036 13.224 ;
     RECT  67.849 13.224 69.041 13.296 ;
     RECT  67.849 13.296 69.036 13.32 ;
     RECT  67.849 13.32 69.041 13.392 ;
     RECT  67.849 13.392 69.036 13.416 ;
     RECT  67.849 13.416 69.041 13.488 ;
     RECT  67.849 13.488 69.036 13.512 ;
     RECT  67.849 13.512 69.041 13.584 ;
     RECT  67.849 13.584 69.036 13.608 ;
     RECT  67.849 13.608 69.041 13.68 ;
     RECT  67.849 13.68 69.036 13.704 ;
     RECT  67.849 13.704 69.041 13.776 ;
     RECT  67.849 13.776 69.036 13.8 ;
     RECT  67.849 13.8 69.041 13.872 ;
     RECT  67.849 13.872 69.036 13.896 ;
     RECT  67.849 13.896 69.041 13.968 ;
     RECT  67.849 13.968 69.036 13.992 ;
     RECT  67.849 13.992 69.041 14.064 ;
     RECT  67.849 14.064 69.036 14.088 ;
     RECT  67.849 14.088 69.041 14.16 ;
     RECT  67.849 14.16 69.036 14.184 ;
     RECT  67.849 14.184 69.041 14.256 ;
     RECT  67.849 14.256 69.036 14.28 ;
     RECT  67.849 14.28 69.041 14.352 ;
     RECT  67.849 14.352 69.036 14.376 ;
     RECT  67.849 14.376 69.041 14.448 ;
     RECT  67.849 14.448 69.036 14.472 ;
     RECT  67.849 14.472 69.041 14.544 ;
     RECT  67.849 14.544 69.036 14.568 ;
     RECT  67.849 14.568 69.041 14.64 ;
     RECT  67.849 14.64 69.036 14.664 ;
     RECT  67.849 14.664 69.041 14.736 ;
     RECT  67.849 14.736 69.036 14.76 ;
     RECT  67.849 14.76 69.041 14.832 ;
     RECT  67.849 14.832 69.036 14.856 ;
     RECT  67.849 14.856 69.041 14.928 ;
     RECT  67.849 14.928 69.036 14.952 ;
     RECT  67.849 14.952 69.041 15.024 ;
     RECT  67.849 15.024 69.036 15.048 ;
     RECT  67.849 15.048 69.041 15.12 ;
     RECT  67.849 15.12 69.036 15.144 ;
     RECT  67.849 15.144 69.041 15.216 ;
     RECT  67.849 15.216 69.036 15.24 ;
     RECT  67.849 15.24 69.041 15.312 ;
     RECT  67.849 15.312 69.036 15.336 ;
     RECT  67.849 15.336 69.041 15.408 ;
     RECT  67.849 15.408 69.036 15.432 ;
     RECT  67.849 15.432 69.041 15.504 ;
     RECT  67.849 15.504 69.036 15.528 ;
     RECT  67.849 15.528 69.041 15.6 ;
     RECT  67.849 15.6 69.036 15.624 ;
     RECT  67.849 15.624 69.041 15.696 ;
     RECT  67.849 15.696 69.036 15.72 ;
     RECT  67.849 15.72 69.041 15.792 ;
     RECT  67.849 15.792 69.036 15.816 ;
     RECT  67.849 15.816 69.041 15.888 ;
     RECT  67.849 15.888 69.036 15.912 ;
     RECT  67.849 15.912 69.041 15.984 ;
     RECT  67.849 15.984 69.036 16.008 ;
     RECT  67.849 16.008 69.041 16.08 ;
     RECT  67.849 16.08 69.036 16.104 ;
     RECT  67.849 16.104 69.041 16.176 ;
     RECT  67.849 16.176 69.036 16.2 ;
     RECT  67.849 16.2 69.041 16.272 ;
     RECT  67.849 16.272 69.036 16.296 ;
     RECT  67.849 16.296 69.041 16.368 ;
     RECT  67.849 16.368 69.036 16.392 ;
     RECT  67.849 16.392 69.041 16.464 ;
     RECT  67.849 16.464 69.036 16.488 ;
     RECT  67.849 16.488 69.041 16.56 ;
     RECT  67.849 16.56 69.036 16.584 ;
     RECT  67.849 16.584 69.041 16.656 ;
     RECT  67.849 16.656 69.036 16.68 ;
     RECT  67.849 16.68 69.041 16.752 ;
     RECT  67.849 16.752 69.036 16.776 ;
     RECT  67.849 16.776 69.041 16.848 ;
     RECT  67.849 16.848 69.036 16.872 ;
     RECT  67.849 16.872 69.041 16.944 ;
     RECT  67.849 16.944 69.036 16.968 ;
     RECT  67.849 16.968 69.041 17.04 ;
     RECT  67.849 17.04 69.036 17.064 ;
     RECT  67.849 17.064 69.041 17.136 ;
     RECT  67.849 17.136 69.036 17.16 ;
     RECT  67.849 17.16 69.041 17.232 ;
     RECT  67.849 17.232 69.036 17.256 ;
     RECT  67.849 17.256 69.041 17.328 ;
     RECT  67.849 17.328 69.036 17.352 ;
     RECT  67.849 17.352 69.041 17.424 ;
     RECT  67.849 17.424 69.036 17.448 ;
     RECT  67.849 17.448 69.041 17.52 ;
     RECT  67.849 17.52 69.036 17.544 ;
     RECT  67.849 17.544 69.041 17.616 ;
     RECT  67.849 17.616 69.036 17.64 ;
     RECT  67.849 17.64 69.041 17.712 ;
     RECT  67.849 17.712 69.036 17.736 ;
     RECT  67.849 17.736 69.041 17.808 ;
     RECT  67.849 17.808 69.036 17.832 ;
     RECT  67.849 17.832 69.041 17.904 ;
     RECT  67.849 17.904 69.036 17.928 ;
     RECT  67.849 17.928 69.041 18 ;
     RECT  67.849 18 69.036 18.024 ;
     RECT  67.849 18.024 69.041 18.096 ;
     RECT  67.849 18.096 69.036 18.12 ;
     RECT  67.849 18.12 69.041 18.192 ;
     RECT  67.849 18.192 69.036 18.216 ;
     RECT  67.849 18.216 69.041 18.288 ;
     RECT  67.849 18.288 69.036 18.312 ;
     RECT  67.849 18.312 69.041 18.384 ;
     RECT  67.849 18.384 69.036 18.408 ;
     RECT  67.849 18.408 69.041 18.48 ;
     RECT  67.849 18.48 69.036 18.504 ;
     RECT  67.849 18.504 69.041 18.576 ;
     RECT  67.849 18.576 69.036 18.6 ;
     RECT  67.849 18.6 69.041 18.672 ;
     RECT  67.849 18.672 69.036 18.696 ;
     RECT  67.849 18.696 69.041 18.768 ;
     RECT  67.849 18.768 69.036 18.792 ;
     RECT  67.849 18.792 69.041 18.864 ;
     RECT  67.849 18.864 69.036 18.888 ;
     RECT  67.849 18.888 69.041 18.96 ;
     RECT  67.849 18.96 69.036 18.984 ;
     RECT  67.849 18.984 69.041 19.056 ;
     RECT  67.849 19.056 69.036 19.08 ;
     RECT  67.849 19.08 69.041 19.92 ;
     RECT  67.849 19.92 69.036 19.944 ;
     RECT  67.849 19.944 69.041 20.016 ;
     RECT  67.849 20.016 69.036 20.04 ;
     RECT  67.849 20.04 69.041 20.112 ;
     RECT  67.849 20.112 69.036 20.136 ;
     RECT  67.849 20.136 69.041 20.208 ;
     RECT  67.849 20.208 69.036 20.232 ;
     RECT  67.849 20.232 69.041 20.304 ;
     RECT  67.849 20.304 69.036 20.328 ;
     RECT  67.849 20.328 69.041 20.4 ;
     RECT  67.849 20.4 69.036 20.424 ;
     RECT  67.849 20.424 69.041 20.496 ;
     RECT  67.849 20.496 69.036 20.52 ;
     RECT  67.849 20.52 69.041 20.592 ;
     RECT  67.849 20.592 69.036 20.616 ;
     RECT  67.849 20.616 69.041 20.688 ;
     RECT  67.849 20.688 69.036 20.712 ;
     RECT  67.849 20.712 69.041 20.784 ;
     RECT  67.849 20.784 69.036 20.808 ;
     RECT  67.849 20.808 69.041 20.88 ;
     RECT  67.849 20.88 69.036 20.904 ;
     RECT  67.849 20.904 69.041 20.976 ;
     RECT  67.849 20.976 69.036 21 ;
     RECT  67.849 21 69.041 21.072 ;
     RECT  67.849 21.072 69.036 21.096 ;
     RECT  67.849 21.096 69.041 21.168 ;
     RECT  67.849 21.168 69.036 21.192 ;
     RECT  67.849 21.192 69.041 21.264 ;
     RECT  67.849 21.264 69.036 21.288 ;
     RECT  67.849 21.288 69.041 21.36 ;
     RECT  67.849 21.36 69.036 21.384 ;
     RECT  67.849 21.384 69.041 21.456 ;
     RECT  67.849 21.456 69.036 21.48 ;
     RECT  67.849 21.48 69.041 21.552 ;
     RECT  67.849 21.552 69.036 21.576 ;
     RECT  67.849 21.576 69.041 21.648 ;
     RECT  67.849 21.648 69.036 21.672 ;
     RECT  67.849 21.672 69.041 21.744 ;
     RECT  67.849 21.744 69.036 21.768 ;
     RECT  67.849 21.768 69.041 21.84 ;
     RECT  67.849 21.84 69.036 21.864 ;
     RECT  67.849 21.864 69.041 21.936 ;
     RECT  67.849 21.936 69.036 21.96 ;
     RECT  67.849 21.96 69.041 22.032 ;
     RECT  67.849 22.032 69.036 22.056 ;
     RECT  67.849 22.056 69.041 22.128 ;
     RECT  67.849 22.128 69.036 22.152 ;
     RECT  67.849 22.152 69.041 22.224 ;
     RECT  67.849 22.224 69.036 22.248 ;
     RECT  67.849 22.248 69.041 22.32 ;
     RECT  67.849 22.32 69.036 22.344 ;
     RECT  67.849 22.344 69.041 22.416 ;
     RECT  67.849 22.416 69.036 22.44 ;
     RECT  67.849 22.44 69.041 22.512 ;
     RECT  67.849 22.512 69.036 22.536 ;
     RECT  67.849 22.536 69.041 22.608 ;
     RECT  67.849 22.608 69.036 22.632 ;
     RECT  67.849 22.632 69.041 22.704 ;
     RECT  67.849 22.704 69.036 22.728 ;
     RECT  67.849 22.728 69.041 22.8 ;
     RECT  67.849 22.8 69.036 22.824 ;
     RECT  67.849 22.824 69.041 22.896 ;
     RECT  67.849 22.896 69.036 22.92 ;
     RECT  67.849 22.92 69.041 22.992 ;
     RECT  67.849 22.992 69.036 23.016 ;
     RECT  67.849 23.016 69.041 23.088 ;
     RECT  67.849 23.088 69.036 23.112 ;
     RECT  67.849 23.112 69.041 23.184 ;
     RECT  67.849 23.184 69.036 23.208 ;
     RECT  67.849 23.208 69.041 23.28 ;
     RECT  67.849 23.28 69.036 23.304 ;
     RECT  67.849 23.304 69.041 23.376 ;
     RECT  67.849 23.376 69.036 23.4 ;
     RECT  67.849 23.4 69.041 23.472 ;
     RECT  67.849 23.472 69.036 23.496 ;
     RECT  67.849 23.496 69.041 23.568 ;
     RECT  67.849 23.568 69.036 23.592 ;
     RECT  67.849 23.592 69.041 23.664 ;
     RECT  67.849 23.664 69.036 23.688 ;
     RECT  67.849 23.688 69.041 23.76 ;
     RECT  67.849 23.76 69.036 23.784 ;
     RECT  67.849 23.784 69.041 23.856 ;
     RECT  67.849 23.856 69.036 23.88 ;
     RECT  67.849 23.88 69.041 23.952 ;
     RECT  67.849 23.952 69.036 23.976 ;
     RECT  67.849 23.976 69.041 24.048 ;
     RECT  67.849 24.048 69.036 24.072 ;
     RECT  67.849 24.072 69.041 24.144 ;
     RECT  67.849 24.144 69.036 24.168 ;
     RECT  67.849 24.168 69.041 24.24 ;
     RECT  67.849 24.24 69.036 24.264 ;
     RECT  67.849 24.264 69.041 24.336 ;
     RECT  67.849 24.336 69.036 24.36 ;
     RECT  67.849 24.36 69.041 24.432 ;
     RECT  67.849 24.432 69.036 24.456 ;
     RECT  67.849 24.456 69.041 24.528 ;
     RECT  67.849 24.528 69.036 24.552 ;
     RECT  67.849 24.552 69.041 24.624 ;
     RECT  67.849 24.624 69.036 24.648 ;
     RECT  67.849 24.648 69.041 24.72 ;
     RECT  67.849 24.72 69.036 24.744 ;
     RECT  67.849 24.744 69.041 24.816 ;
     RECT  67.849 24.816 69.036 24.84 ;
     RECT  67.849 24.84 69.041 24.912 ;
     RECT  67.849 24.912 69.036 24.936 ;
     RECT  67.849 24.936 69.041 25.008 ;
     RECT  67.849 25.008 69.036 25.032 ;
     RECT  67.849 25.032 69.041 25.104 ;
     RECT  67.849 25.104 69.036 25.128 ;
     RECT  67.849 25.128 69.041 25.2 ;
     RECT  67.849 25.2 69.036 25.224 ;
     RECT  67.849 25.224 69.041 25.296 ;
     RECT  67.849 25.296 69.036 25.32 ;
     RECT  67.849 25.32 69.041 25.392 ;
     RECT  67.849 25.392 69.036 25.416 ;
     RECT  67.849 25.416 69.041 25.488 ;
     RECT  67.849 25.488 69.036 25.512 ;
     RECT  67.849 25.512 69.041 25.584 ;
     RECT  67.849 25.584 69.036 25.608 ;
     RECT  67.849 25.608 69.041 25.68 ;
     RECT  67.849 25.68 69.036 25.704 ;
     RECT  67.849 25.704 69.041 25.776 ;
     RECT  67.849 25.776 69.036 25.8 ;
     RECT  67.849 25.8 69.041 25.872 ;
     RECT  67.849 25.872 69.036 25.896 ;
     RECT  67.849 25.896 69.041 25.968 ;
     RECT  67.849 25.968 69.036 25.992 ;
     RECT  67.849 25.992 69.041 26.064 ;
     RECT  67.849 26.064 69.036 26.088 ;
     RECT  67.849 26.088 69.041 26.16 ;
     RECT  67.849 26.16 69.036 26.184 ;
     RECT  67.849 26.184 69.041 26.256 ;
     RECT  67.849 26.256 69.036 26.28 ;
     RECT  67.849 26.28 69.041 26.352 ;
     RECT  67.849 26.352 69.036 26.376 ;
     RECT  67.849 26.376 69.041 26.448 ;
     RECT  67.849 26.448 69.036 26.472 ;
     RECT  67.849 26.472 69.041 26.544 ;
     RECT  67.849 26.544 69.036 26.568 ;
     RECT  67.849 26.568 69.041 26.64 ;
     RECT  67.849 26.64 69.036 26.664 ;
     RECT  67.849 26.664 69.041 26.736 ;
     RECT  67.849 26.736 69.036 26.76 ;
     RECT  67.849 26.76 69.041 26.832 ;
     RECT  67.849 26.832 69.036 26.856 ;
     RECT  67.849 26.856 69.041 26.928 ;
     RECT  67.849 26.928 69.036 26.952 ;
     RECT  67.849 26.952 69.041 27.024 ;
     RECT  67.849 27.024 69.036 27.048 ;
     RECT  67.849 27.048 69.041 27.12 ;
     RECT  67.849 27.12 69.036 27.144 ;
     RECT  67.849 27.144 69.041 27.216 ;
     RECT  67.849 27.216 69.036 27.24 ;
     RECT  67.849 27.24 69.041 27.312 ;
     RECT  67.849 27.312 69.036 27.336 ;
     RECT  67.849 27.336 69.041 27.408 ;
     RECT  67.849 27.408 69.036 27.432 ;
     RECT  67.849 27.432 69.041 27.504 ;
     RECT  67.849 27.504 69.036 27.528 ;
     RECT  67.849 27.528 69.041 27.6 ;
     RECT  67.849 27.6 69.036 27.624 ;
     RECT  67.849 27.624 69.041 27.696 ;
     RECT  67.849 27.696 69.036 27.72 ;
     RECT  67.849 27.72 69.041 27.792 ;
     RECT  67.849 27.792 69.036 27.816 ;
     RECT  67.849 27.816 69.041 27.888 ;
     RECT  67.849 27.888 69.036 27.912 ;
     RECT  67.849 27.912 69.041 27.984 ;
     RECT  67.849 27.984 69.036 28.008 ;
     RECT  67.849 28.008 69.041 28.08 ;
     RECT  67.849 28.08 69.036 28.104 ;
     RECT  67.849 28.104 69.041 28.176 ;
     RECT  67.849 28.176 69.036 28.2 ;
     RECT  67.849 28.2 69.041 28.272 ;
     RECT  67.849 28.272 69.036 28.296 ;
     RECT  67.849 28.296 69.041 28.368 ;
     RECT  67.849 28.368 69.036 28.392 ;
     RECT  67.849 28.392 69.041 28.464 ;
     RECT  67.849 28.464 69.036 28.488 ;
     RECT  67.849 28.488 69.041 28.56 ;
     RECT  67.849 28.56 69.036 28.584 ;
     RECT  67.849 28.584 69.041 28.656 ;
     RECT  67.849 28.656 69.036 28.68 ;
     RECT  67.849 28.68 69.041 28.752 ;
     RECT  67.849 28.752 69.036 28.776 ;
     RECT  67.849 28.776 69.041 28.848 ;
     RECT  67.849 28.848 69.036 28.872 ;
     RECT  67.849 28.872 69.041 28.944 ;
     RECT  67.849 28.944 69.036 28.968 ;
     RECT  67.849 28.968 69.041 29.04 ;
     RECT  67.849 29.04 69.036 29.064 ;
     RECT  67.849 29.064 69.041 29.136 ;
     RECT  67.849 29.136 69.036 29.16 ;
     RECT  67.849 29.16 69.041 29.232 ;
     RECT  67.849 29.232 69.036 29.256 ;
     RECT  67.849 29.256 69.041 29.328 ;
     RECT  67.849 29.328 69.036 29.352 ;
     RECT  67.849 29.352 69.041 29.424 ;
     RECT  67.849 29.424 69.036 29.448 ;
     RECT  67.849 29.448 69.041 29.52 ;
     RECT  67.849 29.52 69.036 29.544 ;
     RECT  67.849 29.544 69.041 29.616 ;
     RECT  67.849 29.616 69.036 29.64 ;
     RECT  67.849 29.64 69.041 29.712 ;
     RECT  67.849 29.712 69.036 29.736 ;
     RECT  67.849 29.736 69.041 29.808 ;
     RECT  67.849 29.808 69.036 29.832 ;
     RECT  67.849 29.832 69.041 29.904 ;
     RECT  67.849 29.904 69.036 29.928 ;
     RECT  67.849 29.928 69.041 30 ;
     RECT  67.849 30 69.036 30.024 ;
     RECT  67.849 30.024 69.041 30.096 ;
     RECT  67.849 30.096 69.036 30.12 ;
     RECT  67.849 30.12 69.041 30.192 ;
     RECT  67.849 30.192 69.036 30.216 ;
     RECT  67.849 30.216 69.041 30.288 ;
     RECT  67.849 30.288 69.036 30.312 ;
     RECT  67.849 30.312 69.041 30.384 ;
     RECT  67.849 30.384 69.036 30.408 ;
     RECT  67.849 30.408 69.041 30.48 ;
     RECT  67.849 30.48 69.036 30.504 ;
     RECT  67.849 30.504 69.041 30.576 ;
     RECT  67.849 30.576 69.036 30.6 ;
     RECT  67.849 30.6 69.041 30.672 ;
     RECT  67.849 30.672 69.036 30.696 ;
     RECT  67.849 30.696 69.041 30.768 ;
     RECT  67.849 30.768 69.036 30.792 ;
     RECT  67.849 30.792 69.041 30.864 ;
     RECT  67.849 30.864 69.036 30.888 ;
     RECT  67.849 30.888 69.041 30.96 ;
     RECT  67.849 30.96 69.036 30.984 ;
     RECT  67.849 30.984 69.041 31.056 ;
     RECT  67.849 31.056 69.036 31.08 ;
     RECT  67.849 31.08 69.041 31.152 ;
     RECT  67.849 31.152 69.036 31.176 ;
     RECT  67.849 31.176 69.041 31.248 ;
     RECT  67.849 31.248 69.036 31.272 ;
     RECT  67.849 31.272 69.041 31.344 ;
     RECT  67.849 31.344 69.036 31.368 ;
     RECT  67.849 31.368 69.041 31.44 ;
     RECT  67.849 31.44 69.036 31.464 ;
     RECT  67.849 31.464 69.041 31.536 ;
     RECT  67.849 31.536 69.036 31.56 ;
     RECT  67.849 31.56 69.041 31.632 ;
     RECT  67.849 31.632 69.036 31.656 ;
     RECT  67.849 31.656 69.041 31.728 ;
     RECT  67.849 31.728 69.036 31.752 ;
     RECT  67.849 31.752 69.041 31.824 ;
     RECT  67.849 31.824 69.036 31.848 ;
     RECT  67.849 31.848 69.041 31.92 ;
     RECT  67.849 31.92 69.036 31.944 ;
     RECT  67.849 31.944 69.041 32.016 ;
     RECT  67.849 32.016 69.036 32.04 ;
     RECT  67.849 32.04 69.041 32.112 ;
     RECT  67.849 32.112 69.036 32.136 ;
     RECT  69.041 9.96 69.084 10.032 ;
     RECT  69.041 10.056 69.084 10.128 ;
     RECT  69.041 10.152 69.084 10.224 ;
     RECT  69.041 10.248 69.084 10.32 ;
     RECT  69.041 10.344 69.084 10.416 ;
     RECT  69.041 10.44 69.084 10.512 ;
     RECT  69.041 10.536 69.084 10.608 ;
     RECT  69.041 10.632 69.084 10.704 ;
     RECT  69.041 10.728 69.084 10.8 ;
     RECT  69.041 10.824 69.084 10.896 ;
     RECT  69.041 10.92 69.084 10.992 ;
     RECT  69.041 11.016 69.084 11.088 ;
     RECT  69.041 11.112 69.084 11.184 ;
     RECT  69.041 11.208 69.084 11.28 ;
     RECT  69.041 11.304 69.084 11.376 ;
     RECT  69.041 11.4 69.084 11.472 ;
     RECT  69.041 11.496 69.084 11.568 ;
     RECT  69.041 11.592 69.084 11.664 ;
     RECT  69.041 11.688 69.084 11.76 ;
     RECT  69.041 11.784 69.084 11.856 ;
     RECT  69.041 11.88 69.084 11.952 ;
     RECT  69.041 11.976 69.084 12.048 ;
     RECT  69.041 12.072 69.084 12.144 ;
     RECT  69.041 12.168 69.084 12.24 ;
     RECT  69.041 12.264 69.084 12.336 ;
     RECT  69.041 12.36 69.084 12.432 ;
     RECT  69.041 12.456 69.084 12.528 ;
     RECT  69.041 12.552 69.084 12.624 ;
     RECT  69.041 12.648 69.084 12.72 ;
     RECT  69.041 12.744 69.084 12.816 ;
     RECT  69.041 12.84 69.084 12.912 ;
     RECT  69.041 12.936 69.084 13.008 ;
     RECT  69.041 13.032 69.084 13.104 ;
     RECT  69.041 13.128 69.084 13.2 ;
     RECT  69.041 13.224 69.084 13.296 ;
     RECT  69.041 13.32 69.084 13.392 ;
     RECT  69.041 13.416 69.084 13.488 ;
     RECT  69.041 13.512 69.084 13.584 ;
     RECT  69.041 13.608 69.084 13.68 ;
     RECT  69.041 13.704 69.084 13.776 ;
     RECT  69.041 13.8 69.084 13.872 ;
     RECT  69.041 13.896 69.084 13.968 ;
     RECT  69.041 13.992 69.084 14.064 ;
     RECT  69.041 14.088 69.084 14.16 ;
     RECT  69.041 14.184 69.084 14.256 ;
     RECT  69.041 14.28 69.084 14.352 ;
     RECT  69.041 14.376 69.084 14.448 ;
     RECT  69.041 14.472 69.084 14.544 ;
     RECT  69.041 14.568 69.084 14.64 ;
     RECT  69.041 14.664 69.084 14.736 ;
     RECT  69.041 14.76 69.084 14.832 ;
     RECT  69.041 14.856 69.084 14.928 ;
     RECT  69.041 14.952 69.084 15.024 ;
     RECT  69.041 15.048 69.084 15.12 ;
     RECT  69.041 15.144 69.084 15.216 ;
     RECT  69.041 15.24 69.084 15.312 ;
     RECT  69.041 15.336 69.084 15.408 ;
     RECT  69.041 15.432 69.084 15.504 ;
     RECT  69.041 15.528 69.084 15.6 ;
     RECT  69.041 15.624 69.084 15.696 ;
     RECT  69.041 15.72 69.084 15.792 ;
     RECT  69.041 15.816 69.084 15.888 ;
     RECT  69.041 15.912 69.084 15.984 ;
     RECT  69.041 16.008 69.084 16.08 ;
     RECT  69.041 16.104 69.084 16.176 ;
     RECT  69.041 16.2 69.084 16.272 ;
     RECT  69.041 16.296 69.084 16.368 ;
     RECT  69.041 16.392 69.084 16.464 ;
     RECT  69.041 16.488 69.084 16.56 ;
     RECT  69.041 16.584 69.084 16.656 ;
     RECT  69.041 16.68 69.084 16.752 ;
     RECT  69.041 16.776 69.084 16.848 ;
     RECT  69.041 16.872 69.084 16.944 ;
     RECT  69.041 16.968 69.084 17.04 ;
     RECT  69.041 17.064 69.084 17.136 ;
     RECT  69.041 17.16 69.084 17.232 ;
     RECT  69.041 17.256 69.084 17.328 ;
     RECT  69.041 17.352 69.084 17.424 ;
     RECT  69.041 17.448 69.084 17.52 ;
     RECT  69.041 17.544 69.084 17.616 ;
     RECT  69.041 17.64 69.084 17.712 ;
     RECT  69.041 17.736 69.084 17.808 ;
     RECT  69.041 17.832 69.084 17.904 ;
     RECT  69.041 17.928 69.084 18 ;
     RECT  69.041 18.024 69.084 18.096 ;
     RECT  69.041 18.12 69.084 18.192 ;
     RECT  69.041 18.216 69.084 18.288 ;
     RECT  69.041 18.312 69.084 18.384 ;
     RECT  69.041 18.408 69.084 18.48 ;
     RECT  69.041 18.504 69.084 18.576 ;
     RECT  69.041 18.6 69.084 18.672 ;
     RECT  69.041 18.696 69.084 18.768 ;
     RECT  69.041 18.792 69.084 18.864 ;
     RECT  69.041 18.888 69.084 18.96 ;
     RECT  69.041 18.984 69.084 19.056 ;
     RECT  69.041 19.08 69.084 19.92 ;
     RECT  69.041 19.944 69.084 20.016 ;
     RECT  69.041 20.04 69.084 20.112 ;
     RECT  69.041 20.136 69.084 20.208 ;
     RECT  69.041 20.232 69.084 20.304 ;
     RECT  69.041 20.328 69.084 20.4 ;
     RECT  69.041 20.424 69.084 20.496 ;
     RECT  69.041 20.52 69.084 20.592 ;
     RECT  69.041 20.616 69.084 20.688 ;
     RECT  69.041 20.712 69.084 20.784 ;
     RECT  69.041 20.808 69.084 20.88 ;
     RECT  69.041 20.904 69.084 20.976 ;
     RECT  69.041 21 69.084 21.072 ;
     RECT  69.041 21.096 69.084 21.168 ;
     RECT  69.041 21.192 69.084 21.264 ;
     RECT  69.041 21.288 69.084 21.36 ;
     RECT  69.041 21.384 69.084 21.456 ;
     RECT  69.041 21.48 69.084 21.552 ;
     RECT  69.041 21.576 69.084 21.648 ;
     RECT  69.041 21.672 69.084 21.744 ;
     RECT  69.041 21.768 69.084 21.84 ;
     RECT  69.041 21.864 69.084 21.936 ;
     RECT  69.041 21.96 69.084 22.032 ;
     RECT  69.041 22.056 69.084 22.128 ;
     RECT  69.041 22.152 69.084 22.224 ;
     RECT  69.041 22.248 69.084 22.32 ;
     RECT  69.041 22.344 69.084 22.416 ;
     RECT  69.041 22.44 69.084 22.512 ;
     RECT  69.041 22.536 69.084 22.608 ;
     RECT  69.041 22.632 69.084 22.704 ;
     RECT  69.041 22.728 69.084 22.8 ;
     RECT  69.041 22.824 69.084 22.896 ;
     RECT  69.041 22.92 69.084 22.992 ;
     RECT  69.041 23.016 69.084 23.088 ;
     RECT  69.041 23.112 69.084 23.184 ;
     RECT  69.041 23.208 69.084 23.28 ;
     RECT  69.041 23.304 69.084 23.376 ;
     RECT  69.041 23.4 69.084 23.472 ;
     RECT  69.041 23.496 69.084 23.568 ;
     RECT  69.041 23.592 69.084 23.664 ;
     RECT  69.041 23.688 69.084 23.76 ;
     RECT  69.041 23.784 69.084 23.856 ;
     RECT  69.041 23.88 69.084 23.952 ;
     RECT  69.041 23.976 69.084 24.048 ;
     RECT  69.041 24.072 69.084 24.144 ;
     RECT  69.041 24.168 69.084 24.24 ;
     RECT  69.041 24.264 69.084 24.336 ;
     RECT  69.041 24.36 69.084 24.432 ;
     RECT  69.041 24.456 69.084 24.528 ;
     RECT  69.041 24.552 69.084 24.624 ;
     RECT  69.041 24.648 69.084 24.72 ;
     RECT  69.041 24.744 69.084 24.816 ;
     RECT  69.041 24.84 69.084 24.912 ;
     RECT  69.041 24.936 69.084 25.008 ;
     RECT  69.041 25.032 69.084 25.104 ;
     RECT  69.041 25.128 69.084 25.2 ;
     RECT  69.041 25.224 69.084 25.296 ;
     RECT  69.041 25.32 69.084 25.392 ;
     RECT  69.041 25.416 69.084 25.488 ;
     RECT  69.041 25.512 69.084 25.584 ;
     RECT  69.041 25.608 69.084 25.68 ;
     RECT  69.041 25.704 69.084 25.776 ;
     RECT  69.041 25.8 69.084 25.872 ;
     RECT  69.041 25.896 69.084 25.968 ;
     RECT  69.041 25.992 69.084 26.064 ;
     RECT  69.041 26.088 69.084 26.16 ;
     RECT  69.041 26.184 69.084 26.256 ;
     RECT  69.041 26.28 69.084 26.352 ;
     RECT  69.041 26.376 69.084 26.448 ;
     RECT  69.041 26.472 69.084 26.544 ;
     RECT  69.041 26.568 69.084 26.64 ;
     RECT  69.041 26.664 69.084 26.736 ;
     RECT  69.041 26.76 69.084 26.832 ;
     RECT  69.041 26.856 69.084 26.928 ;
     RECT  69.041 26.952 69.084 27.024 ;
     RECT  69.041 27.048 69.084 27.12 ;
     RECT  69.041 27.144 69.084 27.216 ;
     RECT  69.041 27.24 69.084 27.312 ;
     RECT  69.041 27.336 69.084 27.408 ;
     RECT  69.041 27.432 69.084 27.504 ;
     RECT  69.041 27.528 69.084 27.6 ;
     RECT  69.041 27.624 69.084 27.696 ;
     RECT  69.041 27.72 69.084 27.792 ;
     RECT  69.041 27.816 69.084 27.888 ;
     RECT  69.041 27.912 69.084 27.984 ;
     RECT  69.041 28.008 69.084 28.08 ;
     RECT  69.041 28.104 69.084 28.176 ;
     RECT  69.041 28.2 69.084 28.272 ;
     RECT  69.041 28.296 69.084 28.368 ;
     RECT  69.041 28.392 69.084 28.464 ;
     RECT  69.041 28.488 69.084 28.56 ;
     RECT  69.041 28.584 69.084 28.656 ;
     RECT  69.041 28.68 69.084 28.752 ;
     RECT  69.041 28.776 69.084 28.848 ;
     RECT  69.041 28.872 69.084 28.944 ;
     RECT  69.041 28.968 69.084 29.04 ;
     RECT  69.041 29.064 69.084 29.136 ;
     RECT  69.041 29.16 69.084 29.232 ;
     RECT  69.041 29.256 69.084 29.328 ;
     RECT  69.041 29.352 69.084 29.424 ;
     RECT  69.041 29.448 69.084 29.52 ;
     RECT  69.041 29.544 69.084 29.616 ;
     RECT  69.041 29.64 69.084 29.712 ;
     RECT  69.041 29.736 69.084 29.808 ;
     RECT  69.041 29.832 69.084 29.904 ;
     RECT  69.041 29.928 69.084 30 ;
     RECT  69.041 30.024 69.084 30.096 ;
     RECT  69.041 30.12 69.084 30.192 ;
     RECT  69.041 30.216 69.084 30.288 ;
     RECT  69.041 30.312 69.084 30.384 ;
     RECT  69.041 30.408 69.084 30.48 ;
     RECT  69.041 30.504 69.084 30.576 ;
     RECT  69.041 30.6 69.084 30.672 ;
     RECT  69.041 30.696 69.084 30.768 ;
     RECT  69.041 30.792 69.084 30.864 ;
     RECT  69.041 30.888 69.084 30.96 ;
     RECT  69.041 30.984 69.084 31.056 ;
     RECT  69.041 31.08 69.084 31.152 ;
     RECT  69.041 31.176 69.084 31.248 ;
     RECT  69.041 31.272 69.084 31.344 ;
     RECT  69.041 31.368 69.084 31.44 ;
     RECT  69.041 31.464 69.084 31.536 ;
     RECT  69.041 31.56 69.084 31.632 ;
     RECT  69.041 31.656 69.084 31.728 ;
     RECT  69.041 31.752 69.084 31.824 ;
     RECT  69.041 31.848 69.084 31.92 ;
     RECT  69.041 31.944 69.084 32.016 ;
     RECT  69.041 32.04 69.084 32.112 ;
     RECT  67.273 51.408 69.036 51.432 ;
     RECT  67.273 51.432 69.084 51.504 ;
     RECT  67.273 51.504 69.036 51.528 ;
     RECT  67.273 51.528 69.084 51.6 ;
     RECT  67.273 51.6 69.036 51.624 ;
     RECT  67.273 51.624 69.084 51.696 ;
     RECT  67.273 51.696 69.036 51.72 ;
     RECT  67.273 51.72 69.084 51.792 ;
     RECT  67.273 51.792 69.036 51.816 ;
     RECT  67.273 51.816 69.084 51.888 ;
     RECT  67.273 51.888 69.036 51.912 ;
     RECT  67.273 51.912 69.084 51.984 ;
     RECT  67.273 51.984 69.036 52.008 ;
     RECT  67.273 52.008 69.084 52.08 ;
     RECT  67.273 52.08 69.036 52.104 ;
     RECT  67.273 52.104 69.084 52.176 ;
     RECT  67.273 52.176 69.036 52.2 ;
     RECT  67.273 52.2 69.084 52.272 ;
     RECT  67.273 52.272 69.036 52.296 ;
     RECT  67.273 52.296 69.084 52.368 ;
     RECT  67.273 52.368 69.036 52.392 ;
     RECT  67.273 52.392 69.084 52.464 ;
     RECT  67.273 52.464 69.036 52.488 ;
     RECT  67.273 52.488 69.084 52.56 ;
     RECT  67.273 52.56 69.036 52.584 ;
     RECT  67.273 52.584 69.084 52.656 ;
     RECT  67.273 52.656 69.036 52.68 ;
     RECT  67.273 52.68 69.084 52.752 ;
     RECT  67.273 52.752 69.036 52.776 ;
     RECT  67.273 52.776 69.084 52.848 ;
     RECT  67.273 52.848 69.036 52.872 ;
     RECT  67.273 52.872 69.084 52.944 ;
     RECT  67.273 52.944 69.036 52.968 ;
     RECT  67.273 52.968 69.084 53.04 ;
     RECT  67.273 53.04 69.036 53.064 ;
     RECT  67.273 53.064 69.084 53.136 ;
     RECT  67.273 53.136 69.036 53.16 ;
     RECT  67.273 53.16 69.084 53.232 ;
     RECT  67.273 53.232 69.036 53.256 ;
     RECT  67.273 53.256 69.084 53.328 ;
     RECT  67.273 53.328 69.036 53.352 ;
     RECT  67.273 53.352 69.084 53.424 ;
     RECT  67.273 53.424 69.036 53.448 ;
     RECT  67.273 53.448 69.084 53.52 ;
     RECT  67.273 53.52 69.036 53.544 ;
     RECT  67.273 53.544 69.084 53.616 ;
     RECT  67.273 53.616 69.036 53.64 ;
     RECT  67.273 53.64 69.084 53.712 ;
     RECT  67.273 53.712 69.036 53.736 ;
     RECT  67.273 53.736 69.084 53.808 ;
     RECT  67.273 53.808 69.036 53.832 ;
     RECT  67.273 53.832 69.084 53.904 ;
     RECT  67.273 53.904 69.036 53.928 ;
     RECT  67.273 53.928 69.084 54 ;
     RECT  67.273 54 69.036 54.024 ;
     RECT  67.273 54.024 69.084 54.096 ;
     RECT  67.273 54.096 69.036 54.12 ;
     RECT  67.273 54.12 69.084 54.192 ;
     RECT  67.273 54.192 69.036 54.216 ;
     RECT  67.273 54.216 69.084 54.288 ;
     RECT  67.273 54.288 69.036 54.312 ;
     RECT  67.273 54.312 69.084 54.384 ;
     RECT  67.273 54.384 69.036 54.408 ;
     RECT  69.001 58.32 69.036 58.344 ;
     RECT  69.001 58.344 69.084 58.416 ;
     RECT  69.001 58.416 69.036 58.44 ;
     RECT  69.001 58.44 69.084 58.512 ;
     RECT  69.001 58.512 69.036 58.536 ;
     RECT  69.001 58.536 69.084 58.608 ;
     RECT  69.001 58.608 69.036 58.632 ;
     RECT  69.001 58.632 69.084 58.704 ;
     RECT  69.001 58.704 69.036 58.728 ;
     RECT  69.001 58.728 69.084 58.8 ;
     RECT  69.001 58.8 69.036 58.824 ;
     RECT  69.001 58.824 69.084 58.896 ;
     RECT  69.001 58.896 69.036 58.92 ;
     RECT  69.001 58.92 69.084 58.992 ;
     RECT  69.001 58.992 69.036 59.016 ;
     RECT  69.001 59.016 69.084 59.088 ;
     RECT  69.001 59.088 69.036 59.112 ;
     RECT  69.001 59.112 69.084 59.184 ;
     RECT  69.001 59.184 69.036 59.208 ;
     RECT  69.001 59.208 69.084 59.28 ;
     RECT  69.001 59.28 69.036 59.304 ;
     RECT  69.001 59.304 69.084 59.376 ;
     RECT  69.001 59.376 69.036 59.4 ;
     RECT  69.001 59.4 69.084 59.472 ;
     RECT  69.001 59.472 69.036 59.496 ;
     RECT  69.001 59.496 69.084 59.568 ;
     RECT  69.001 59.568 69.036 59.592 ;
     RECT  69.001 59.592 69.084 59.664 ;
     RECT  69.001 59.664 69.036 59.688 ;
     RECT  69.001 59.688 69.084 59.76 ;
     RECT  69.001 59.76 69.036 59.784 ;
     RECT  69.001 59.784 69.084 59.856 ;
     RECT  69.001 59.856 69.036 59.88 ;
     RECT  69.001 59.88 69.084 59.952 ;
     RECT  69.001 59.952 69.036 59.976 ;
     RECT  69.001 59.976 69.084 60.048 ;
     RECT  69.001 60.048 69.036 60.072 ;
     RECT  69.001 60.072 69.084 60.144 ;
     RECT  69.001 60.144 69.036 60.168 ;
     RECT  69.001 60.168 69.084 60.24 ;
     RECT  69.001 60.24 69.036 60.264 ;
     RECT  69.001 60.264 69.084 60.336 ;
     RECT  69.001 60.336 69.036 60.36 ;
     RECT  69.001 60.36 69.084 60.432 ;
     RECT  69.001 60.432 69.036 60.456 ;
     RECT  69.001 60.456 69.084 60.528 ;
     RECT  69.001 60.528 69.036 60.552 ;
     RECT  69.001 60.552 69.084 60.624 ;
     RECT  69.001 60.624 69.036 60.648 ;
     RECT  69.001 60.648 69.084 60.72 ;
     RECT  69.001 60.72 69.036 60.744 ;
     RECT  69.001 60.744 69.084 60.816 ;
     RECT  69.001 60.816 69.036 60.84 ;
     RECT  69.001 60.84 69.084 60.912 ;
     RECT  69.001 60.912 69.036 60.936 ;
     RECT  69.001 60.936 69.084 61.008 ;
     RECT  69.001 61.008 69.036 61.032 ;
     RECT  69.001 61.032 69.084 61.104 ;
     RECT  69.001 61.104 69.036 61.128 ;
     RECT  69.001 61.128 69.084 61.2 ;
     RECT  69.001 61.2 69.036 61.224 ;
     RECT  69.001 61.224 69.084 61.296 ;
     RECT  69.001 61.296 69.036 61.32 ;
     RECT  69.001 61.32 69.084 61.392 ;
     RECT  69.001 61.392 69.036 61.416 ;
     RECT  69.001 61.416 69.084 61.488 ;
     RECT  69.001 61.488 69.036 61.512 ;
     RECT  69.001 61.512 69.084 61.584 ;
     RECT  69.001 61.584 69.036 61.608 ;
     RECT  69.001 61.608 69.084 61.68 ;
     RECT  69.001 61.68 69.036 61.704 ;
     RECT  69.001 61.704 69.084 61.776 ;
     RECT  69.001 61.776 69.036 61.8 ;
     RECT  69.001 61.8 69.084 61.872 ;
     RECT  69.001 61.872 69.036 61.896 ;
     RECT  69.001 61.896 69.084 61.968 ;
     RECT  69.001 61.968 69.036 61.992 ;
     RECT  69.001 61.992 69.084 62.064 ;
     RECT  69.001 62.064 69.036 62.088 ;
     RECT  69.001 62.088 69.084 62.16 ;
     RECT  69.001 62.16 69.036 62.184 ;
     RECT  69.001 62.184 69.084 62.256 ;
     RECT  69.001 62.256 69.036 62.28 ;
     RECT  69.001 62.28 69.084 62.352 ;
     RECT  69.001 62.352 69.036 62.376 ;
     RECT  69.001 62.376 69.084 62.448 ;
     RECT  69.001 62.448 69.036 62.472 ;
     RECT  69.001 62.472 69.084 62.544 ;
     RECT  69.001 62.544 69.036 62.568 ;
     RECT  69.001 62.568 69.084 62.64 ;
     RECT  69.001 62.64 69.036 62.664 ;
     RECT  69.001 62.664 69.084 62.736 ;
     RECT  69.001 62.736 69.036 62.76 ;
     RECT  69.001 62.76 69.084 62.832 ;
     RECT  69.001 62.832 69.036 62.856 ;
     RECT  69.001 62.856 69.084 62.928 ;
     RECT  69.001 62.928 69.036 62.952 ;
     RECT  69.001 62.952 69.084 63.024 ;
     RECT  69.001 63.024 69.036 63.048 ;
     RECT  69.001 63.048 69.084 63.12 ;
     RECT  69.001 63.12 69.036 63.144 ;
     RECT  69.001 63.144 69.084 63.216 ;
     RECT  69.001 63.216 69.036 63.24 ;
     RECT  69.001 63.24 69.084 63.312 ;
     RECT  69.001 63.312 69.036 63.336 ;
     RECT  69.001 63.336 69.084 63.408 ;
     RECT  69.001 63.408 69.036 63.432 ;
     RECT  69.001 63.432 69.084 63.504 ;
     RECT  69.001 63.504 69.036 63.528 ;
     RECT  69.001 63.528 69.084 63.6 ;
     RECT  69.001 63.6 69.036 63.624 ;
     RECT  69.001 63.624 69.084 63.696 ;
     RECT  69.001 63.696 69.036 63.72 ;
     RECT  69.001 63.72 69.084 63.792 ;
     RECT  69.001 63.792 69.036 63.816 ;
     RECT  69.001 63.816 69.084 63.888 ;
     RECT  69.001 63.888 69.036 63.912 ;
     RECT  69.001 63.912 69.084 63.984 ;
     RECT  69.001 63.984 69.036 64.008 ;
     RECT  69.001 64.008 69.084 64.08 ;
     RECT  69.001 64.08 69.036 64.104 ;
     RECT  69.001 64.104 69.084 64.176 ;
     RECT  69.001 64.176 69.036 64.2 ;
     RECT  69.001 64.2 69.084 64.464 ;
     RECT  69.001 64.464 69.036 64.488 ;
     RECT  69.001 64.488 69.084 64.56 ;
     RECT  69.001 64.56 69.036 64.584 ;
     RECT  69.001 64.584 69.084 64.656 ;
     RECT  69.001 64.656 69.036 64.68 ;
     RECT  69.001 64.68 69.084 64.752 ;
     RECT  69.001 64.752 69.036 64.776 ;
     RECT  69.001 64.776 69.084 64.848 ;
     RECT  69.001 64.848 69.036 64.872 ;
     RECT  69.001 64.872 69.084 64.944 ;
     RECT  69.001 64.944 69.036 64.968 ;
     RECT  69.001 64.968 69.084 65.04 ;
     RECT  69.001 65.04 69.036 65.064 ;
     RECT  69.001 65.064 69.084 65.136 ;
     RECT  69.001 65.136 69.036 65.16 ;
     RECT  69.001 65.16 69.084 65.232 ;
     RECT  69.001 65.232 69.036 65.256 ;
     RECT  69.001 65.256 69.084 65.328 ;
     RECT  69.001 65.328 69.036 65.352 ;
     RECT  69.001 65.352 69.084 65.424 ;
     RECT  69.001 65.424 69.036 65.448 ;
     RECT  69.001 65.448 69.084 65.52 ;
     RECT  69.001 65.52 69.036 65.544 ;
     RECT  69.001 65.544 69.084 65.616 ;
     RECT  69.001 65.616 69.036 65.64 ;
     RECT  69.001 65.64 69.084 65.712 ;
     RECT  69.001 65.712 69.036 65.736 ;
     RECT  69.001 65.736 69.084 65.808 ;
     RECT  69.001 65.808 69.036 65.832 ;
     RECT  69.001 65.832 69.084 65.904 ;
     RECT  69.001 65.904 69.036 65.928 ;
     RECT  69.001 65.928 69.084 66 ;
     RECT  69.001 66 69.036 66.024 ;
     RECT  69.001 66.024 69.084 66.096 ;
     RECT  69.001 66.096 69.036 66.12 ;
     RECT  69.001 66.12 69.084 66.192 ;
     RECT  69.001 66.192 69.036 66.216 ;
     RECT  69.001 66.216 69.084 66.288 ;
     RECT  69.001 66.288 69.036 66.312 ;
     RECT  69.001 66.312 69.084 66.384 ;
     RECT  69.001 66.384 69.036 66.408 ;
     RECT  69.001 66.408 69.084 66.48 ;
     RECT  69.001 66.48 69.036 66.504 ;
     RECT  69.001 66.504 69.084 66.576 ;
     RECT  69.001 66.576 69.036 66.6 ;
     RECT  69.001 66.6 69.084 66.672 ;
     RECT  69.001 66.672 69.036 66.696 ;
     RECT  69.001 66.696 69.084 66.768 ;
     RECT  69.001 66.768 69.036 66.792 ;
     RECT  69.001 66.792 69.084 66.864 ;
     RECT  69.001 66.864 69.036 66.888 ;
     RECT  69.001 66.888 69.084 66.96 ;
     RECT  69.001 66.96 69.036 66.984 ;
     RECT  69.001 66.984 69.084 67.056 ;
     RECT  69.001 67.056 69.036 67.08 ;
     RECT  69.001 67.08 69.084 67.152 ;
     RECT  69.001 67.152 69.036 67.176 ;
     RECT  69.001 67.176 69.084 67.248 ;
     RECT  69.001 67.248 69.036 67.272 ;
     RECT  69.001 67.272 69.084 67.344 ;
     RECT  69.001 67.344 69.036 67.368 ;
     RECT  69.001 67.368 69.084 67.44 ;
     RECT  69.001 67.44 69.036 67.464 ;
    LAYER M5 ;
     RECT  42.216 0.016 42.288 0.084 ;
     RECT  42.312 0.016 42.384 0.084 ;
     RECT  42.408 0.016 42.48 0.084 ;
     RECT  42.504 0.016 42.576 0.084 ;
     RECT  42.6 0.016 42.672 0.084 ;
     RECT  42.696 0.016 42.768 0.084 ;
     RECT  42.792 0.016 42.864 0.084 ;
     RECT  42.888 0.016 42.96 0.084 ;
     RECT  42.984 0.016 43.056 0.084 ;
     RECT  43.08 0.016 43.152 0.084 ;
     RECT  43.176 0.016 43.248 0.084 ;
     RECT  43.272 0.016 43.344 0.084 ;
     RECT  43.368 0.016 43.44 0.084 ;
     RECT  43.464 0.016 43.536 0.084 ;
     RECT  43.56 0.016 43.632 0.084 ;
     RECT  43.656 0.016 43.728 0.084 ;
     RECT  43.752 0.016 43.824 0.084 ;
     RECT  43.848 0.016 43.92 0.084 ;
     RECT  43.944 0.016 44.016 0.084 ;
     RECT  44.04 0.016 44.112 0.084 ;
     RECT  44.136 0.016 44.208 0.084 ;
     RECT  44.232 0.016 44.304 0.084 ;
     RECT  44.328 0.016 44.4 0.084 ;
     RECT  44.424 0.016 44.496 0.084 ;
     RECT  44.52 0.016 44.592 0.084 ;
     RECT  44.616 0.016 44.688 0.084 ;
     RECT  44.712 0.016 44.784 0.084 ;
     RECT  44.808 0.016 44.88 0.084 ;
     RECT  44.904 0.016 44.976 0.084 ;
     RECT  45 0.016 45.072 0.084 ;
     RECT  45.096 0.016 45.168 0.084 ;
     RECT  45.192 0.016 45.264 0.084 ;
     RECT  45.288 0.016 45.36 0.084 ;
     RECT  45.384 0.016 45.456 0.084 ;
     RECT  45.48 0.016 45.552 0.084 ;
     RECT  45.576 0.016 45.648 0.084 ;
     RECT  45.672 0.016 45.744 0.084 ;
     RECT  45.768 0.016 45.84 0.084 ;
     RECT  45.864 0.016 45.936 0.084 ;
     RECT  45.96 0.016 46.032 0.084 ;
     RECT  46.056 0.016 46.128 0.084 ;
     RECT  46.152 0.016 46.224 0.084 ;
     RECT  46.248 0.016 46.32 0.084 ;
     RECT  46.344 0.016 46.416 0.084 ;
     RECT  46.44 0.016 46.512 0.084 ;
     RECT  46.536 0.016 46.608 0.084 ;
     RECT  46.632 0.016 46.704 0.084 ;
     RECT  46.728 0.016 46.8 0.084 ;
     RECT  46.824 0.016 46.896 0.084 ;
     RECT  46.92 0.016 46.992 0.084 ;
     RECT  47.016 0.016 47.088 0.084 ;
     RECT  47.112 0.016 47.184 0.084 ;
     RECT  47.208 0.016 47.28 0.084 ;
     RECT  47.304 0.016 47.376 0.084 ;
     RECT  47.4 0.016 47.472 0.084 ;
     RECT  47.496 0.016 47.568 0.084 ;
     RECT  47.592 0.016 47.664 0.084 ;
     RECT  47.688 0.016 47.76 0.084 ;
     RECT  47.784 0.016 47.856 0.084 ;
     RECT  47.88 0.016 47.952 0.084 ;
     RECT  47.976 0.016 48.048 0.084 ;
     RECT  48.072 0.016 48.144 0.084 ;
     RECT  48.168 0.016 48.24 0.084 ;
     RECT  48.264 0.016 48.336 0.084 ;
     RECT  48.36 0.016 48.432 0.084 ;
     RECT  48.456 0.016 48.528 0.084 ;
     RECT  48.552 0.016 48.624 0.084 ;
     RECT  48.648 0.016 48.72 0.084 ;
     RECT  48.744 0.016 48.816 0.084 ;
     RECT  48.84 0.016 48.912 0.084 ;
     RECT  48.936 0.016 49.008 0.084 ;
     RECT  49.032 0.016 49.104 0.084 ;
     RECT  49.128 0.016 49.2 0.084 ;
     RECT  49.224 0.016 49.296 0.084 ;
     RECT  49.32 0.016 49.392 0.084 ;
     RECT  49.416 0.016 49.488 0.084 ;
     RECT  49.512 0.016 49.584 0.084 ;
     RECT  49.608 0.016 49.68 0.084 ;
     RECT  49.704 0.016 49.776 0.084 ;
     RECT  49.8 0.016 49.872 0.084 ;
     RECT  49.896 0.016 49.968 0.084 ;
     RECT  49.992 0.016 50.064 0.084 ;
     RECT  50.088 0.016 50.16 0.084 ;
     RECT  50.184 0.016 50.256 0.084 ;
     RECT  50.28 0.016 50.352 0.084 ;
     RECT  50.376 0.016 50.448 0.084 ;
     RECT  50.472 0.016 50.544 0.084 ;
     RECT  50.568 0.016 50.64 0.084 ;
     RECT  50.664 0.016 50.736 0.084 ;
     RECT  50.76 0.016 50.832 0.084 ;
     RECT  50.856 0.016 50.928 0.084 ;
     RECT  50.952 0.016 51.024 0.084 ;
     RECT  51.048 0.016 51.12 0.084 ;
     RECT  51.144 0.016 51.216 0.084 ;
     RECT  51.24 0.016 51.312 0.084 ;
     RECT  51.336 0.016 51.408 0.084 ;
     RECT  51.432 0.016 51.504 0.084 ;
     RECT  51.528 0.016 51.6 0.084 ;
     RECT  51.624 0.016 51.696 0.084 ;
     RECT  51.72 0.016 51.792 0.084 ;
     RECT  51.816 0.016 51.888 0.084 ;
     RECT  51.912 0.016 51.984 0.084 ;
     RECT  52.008 0.016 52.08 0.084 ;
     RECT  52.104 0.016 52.176 0.084 ;
     RECT  52.2 0.016 52.272 0.084 ;
     RECT  52.296 0.016 52.368 0.084 ;
     RECT  52.392 0.016 52.464 0.084 ;
     RECT  52.488 0.016 52.56 0.084 ;
     RECT  52.584 0.016 52.656 0.084 ;
     RECT  52.68 0.016 52.752 0.084 ;
     RECT  52.776 0.016 52.848 0.084 ;
     RECT  52.872 0.016 52.944 0.084 ;
     RECT  52.968 0.016 53.04 0.084 ;
     RECT  53.064 0.016 53.136 0.084 ;
     RECT  53.16 0.016 53.232 0.084 ;
     RECT  53.256 0.016 53.328 0.084 ;
     RECT  53.352 0.016 53.424 0.084 ;
     RECT  53.448 0.016 53.52 0.084 ;
     RECT  53.544 0.016 53.616 0.084 ;
     RECT  53.64 0.016 53.712 0.084 ;
     RECT  53.736 0.016 53.808 0.084 ;
     RECT  53.832 0.016 53.904 0.084 ;
     RECT  53.928 0.016 54 0.084 ;
     RECT  54.024 0.016 54.096 0.084 ;
     RECT  54.12 0.016 54.192 0.084 ;
     RECT  54.216 0.016 54.288 0.084 ;
     RECT  54.312 0.016 54.384 0.084 ;
     RECT  54.408 0.016 54.48 0.084 ;
     RECT  54.504 0.016 54.576 0.084 ;
     RECT  54.6 0.016 54.672 0.084 ;
     RECT  54.696 0.016 54.768 0.084 ;
     RECT  54.792 0.016 54.864 0.084 ;
     RECT  54.888 0.016 54.96 0.084 ;
     RECT  54.984 0.016 55.056 0.084 ;
     RECT  55.08 0.016 55.152 0.084 ;
     RECT  55.176 0.016 55.248 0.084 ;
     RECT  55.272 0.016 55.344 0.084 ;
     RECT  55.368 0.016 55.44 0.084 ;
     RECT  55.464 0.016 55.536 0.084 ;
     RECT  55.56 0.016 55.632 0.084 ;
     RECT  55.656 0.016 55.728 0.084 ;
     RECT  55.752 0.016 55.824 0.084 ;
     RECT  55.848 0.016 55.92 0.084 ;
     RECT  55.944 0.016 56.016 0.084 ;
     RECT  56.04 0.016 56.112 0.084 ;
     RECT  56.136 0.016 56.208 0.084 ;
     RECT  56.232 0.016 56.304 0.084 ;
     RECT  56.328 0.016 56.4 0.084 ;
     RECT  56.424 0.016 56.496 0.084 ;
     RECT  56.52 0.016 56.592 0.084 ;
     RECT  56.616 0.016 56.688 0.084 ;
     RECT  56.712 0.016 56.784 0.084 ;
     RECT  56.808 0.016 56.88 0.084 ;
     RECT  56.904 0.016 56.976 0.084 ;
     RECT  57 0.016 57.072 0.084 ;
     RECT  57.096 0.016 57.168 0.084 ;
     RECT  57.192 0.016 57.264 0.084 ;
     RECT  57.288 0.016 57.36 0.084 ;
     RECT  57.384 0.016 57.456 0.084 ;
     RECT  57.48 0.016 58.32 0.084 ;
     RECT  58.344 0.016 58.416 0.084 ;
     RECT  58.44 0.016 58.512 0.084 ;
     RECT  58.536 0.016 58.608 0.084 ;
     RECT  58.632 0.016 58.704 0.084 ;
     RECT  58.728 0.016 58.8 0.084 ;
     RECT  58.824 0.016 58.896 0.084 ;
     RECT  58.92 0.016 58.992 0.084 ;
     RECT  59.016 0.016 59.088 0.084 ;
     RECT  59.112 0.016 59.184 0.084 ;
     RECT  59.208 0.016 59.28 0.084 ;
     RECT  59.304 0.016 59.376 0.084 ;
     RECT  59.4 0.016 59.472 0.084 ;
     RECT  59.496 0.016 59.568 0.084 ;
     RECT  59.592 0.016 59.664 0.084 ;
     RECT  59.688 0.016 59.76 0.084 ;
     RECT  59.784 0.016 59.856 0.084 ;
     RECT  59.88 0.016 59.952 0.084 ;
     RECT  59.976 0.016 60.048 0.084 ;
     RECT  60.072 0.016 60.144 0.084 ;
     RECT  60.168 0.016 60.24 0.084 ;
     RECT  60.264 0.016 60.336 0.084 ;
     RECT  60.36 0.016 60.432 0.084 ;
     RECT  60.456 0.016 60.528 0.084 ;
     RECT  60.552 0.016 60.624 0.084 ;
     RECT  60.648 0.016 60.72 0.084 ;
     RECT  60.744 0.016 60.816 0.084 ;
     RECT  60.84 0.016 60.912 0.084 ;
     RECT  60.936 0.016 61.008 0.084 ;
     RECT  61.032 0.016 61.104 0.084 ;
     RECT  61.128 0.016 61.2 0.084 ;
     RECT  61.224 0.016 61.296 0.084 ;
     RECT  61.32 0.016 61.392 0.084 ;
     RECT  61.416 0.016 61.488 0.084 ;
     RECT  61.512 0.016 61.584 0.084 ;
     RECT  61.608 0.016 61.68 0.084 ;
     RECT  61.704 0.016 61.776 0.084 ;
     RECT  61.8 0.016 61.872 0.084 ;
     RECT  61.896 0.016 61.968 0.084 ;
     RECT  61.992 0.016 62.064 0.084 ;
     RECT  62.088 0.016 62.16 0.084 ;
     RECT  62.184 0.016 62.256 0.084 ;
     RECT  62.28 0.016 62.352 0.084 ;
     RECT  62.376 0.016 62.448 0.084 ;
     RECT  62.472 0.016 62.544 0.084 ;
     RECT  62.568 0.016 62.64 0.084 ;
     RECT  62.664 0.016 62.736 0.084 ;
     RECT  62.76 0.016 62.832 0.084 ;
     RECT  62.856 0.016 62.928 0.084 ;
     RECT  62.952 0.016 63.024 0.084 ;
     RECT  63.048 0.016 63.12 0.084 ;
     RECT  63.144 0.016 63.216 0.084 ;
     RECT  63.24 0.016 63.312 0.084 ;
     RECT  63.336 0.016 63.408 0.084 ;
     RECT  63.432 0.016 63.504 0.084 ;
     RECT  63.528 0.016 63.6 0.084 ;
     RECT  63.624 0.016 63.696 0.084 ;
     RECT  63.72 0.016 63.792 0.084 ;
     RECT  63.816 0.016 63.888 0.084 ;
     RECT  63.912 0.016 63.984 0.084 ;
     RECT  64.008 0.016 64.08 0.084 ;
     RECT  64.104 0.016 64.176 0.084 ;
     RECT  64.2 0.016 64.272 0.084 ;
     RECT  64.296 0.016 64.368 0.084 ;
     RECT  64.392 0.016 64.464 0.084 ;
     RECT  64.488 0.016 64.56 0.084 ;
     RECT  64.584 0.016 64.656 0.084 ;
     RECT  64.68 0.016 64.752 0.084 ;
     RECT  64.776 0.016 64.848 0.084 ;
     RECT  64.872 0.016 64.944 0.084 ;
     RECT  64.968 0.016 65.04 0.084 ;
     RECT  65.064 0.016 65.136 0.084 ;
     RECT  65.16 0.016 65.232 0.084 ;
     RECT  65.256 0.016 65.328 0.084 ;
     RECT  65.352 0.016 65.424 0.084 ;
     RECT  65.448 0.016 65.52 0.084 ;
     RECT  65.544 0.016 65.616 0.084 ;
     RECT  65.64 0.016 65.712 0.084 ;
     RECT  65.736 0.016 65.808 0.084 ;
     RECT  65.832 0.016 65.904 0.084 ;
     RECT  65.928 0.016 66 0.084 ;
     RECT  66.024 0.016 66.096 0.084 ;
     RECT  66.12 0.016 66.192 0.084 ;
     RECT  66.216 0.016 66.288 0.084 ;
     RECT  66.312 0.016 66.384 0.084 ;
     RECT  66.408 0.016 66.48 0.084 ;
     RECT  66.504 0.016 66.576 0.084 ;
     RECT  66.6 0.016 66.672 0.084 ;
     RECT  66.696 0.016 66.768 0.084 ;
     RECT  66.792 0.016 66.864 0.084 ;
     RECT  66.888 0.016 66.96 0.084 ;
     RECT  66.984 0.016 67.056 0.084 ;
     RECT  67.08 0.016 67.152 0.084 ;
     RECT  67.176 0.016 67.248 0.084 ;
     RECT  67.272 0.016 67.344 0.084 ;
     RECT  67.368 0.016 67.44 0.084 ;
     RECT  42.192 0.084 67.464 0.085 ;
     RECT  42.192 0.085 67.656 0.611 ;
     RECT  42.288 0.611 67.656 0.707 ;
     RECT  42.384 0.707 67.656 1.763 ;
     RECT  2.4 2.137 2.52 2.151 ;
     RECT  7.8 2.137 7.92 2.151 ;
     RECT  13.2 2.137 13.32 2.151 ;
     RECT  18.6 2.137 18.72 2.151 ;
     RECT  24 2.137 24.12 2.151 ;
     RECT  29.4 2.137 29.52 2.151 ;
     RECT  34.8 2.137 34.92 2.151 ;
     RECT  40.2 2.137 40.32 2.151 ;
     RECT  42.48 1.763 67.656 2.773 ;
     RECT  29.4 2.151 29.712 2.821 ;
     RECT  40.2 2.151 40.512 2.821 ;
     RECT  42.48 2.773 67.848 2.867 ;
     RECT  24 2.151 24.312 3.157 ;
     RECT  31.536 3.349 31.56 3.397 ;
     RECT  40.2 2.821 40.632 3.875 ;
     RECT  7.8 2.151 8.112 3.925 ;
     RECT  43.536 2.867 67.848 4.019 ;
     RECT  9.744 3.925 9.768 4.261 ;
     RECT  43.728 4.019 67.848 4.643 ;
     RECT  24 3.157 24.408 4.789 ;
     RECT  29.088 2.821 29.712 4.885 ;
     RECT  14.784 2.581 14.808 4.933 ;
     RECT  18.6 2.151 18.912 5.029 ;
     RECT  31.536 3.397 32.04 5.029 ;
     RECT  43.776 4.643 67.848 5.171 ;
     RECT  29.04 4.885 29.712 5.221 ;
     RECT  29.04 5.221 29.832 5.461 ;
     RECT  14.784 4.933 15.144 5.747 ;
     RECT  14.784 5.747 15.096 6.131 ;
     RECT  18.6 5.029 19.128 6.277 ;
     RECT  37.632 2.821 37.656 6.323 ;
     RECT  43.824 5.171 67.848 6.323 ;
     RECT  47.04 6.323 67.848 6.371 ;
     RECT  9.264 4.261 9.768 6.805 ;
     RECT  18.6 6.277 19.368 7.139 ;
     RECT  34.8 2.151 35.112 7.141 ;
     RECT  42.432 5.365 42.456 7.381 ;
     RECT  29.04 5.461 30.024 7.427 ;
     RECT  2.4 2.151 2.712 7.861 ;
     RECT  2.4 7.861 2.808 8.003 ;
     RECT  38.256 6.805 38.328 8.195 ;
     RECT  27.936 4.837 27.96 8.243 ;
     RECT  18.6 7.139 18.912 8.437 ;
     RECT  20.496 7.189 20.52 8.437 ;
     RECT  24 4.789 25.08 8.485 ;
     RECT  26.736 6.421 26.76 8.579 ;
     RECT  29.088 7.427 30.024 8.579 ;
     RECT  48.096 6.371 67.848 8.579 ;
     RECT  9.264 6.805 10.008 8.675 ;
     RECT  43.824 6.323 46.008 8.725 ;
     RECT  47.04 6.371 47.112 8.725 ;
     RECT  36.336 7.765 36.36 8.867 ;
     RECT  38.256 8.195 38.28 8.915 ;
     RECT  34.8 7.141 35.256 9.013 ;
     RECT  29.4 8.579 30.024 9.109 ;
     RECT  34.8 9.013 35.352 9.109 ;
     RECT  18.6 8.437 20.52 9.155 ;
     RECT  48.48 8.579 67.848 9.155 ;
     RECT  31.392 5.029 32.04 9.205 ;
     RECT  23.616 8.485 25.08 9.251 ;
     RECT  31.2 9.205 32.04 9.251 ;
     RECT  29.4 9.109 30.072 9.493 ;
     RECT  31.2 9.251 31.56 9.493 ;
     RECT  40.2 3.875 40.512 9.541 ;
     RECT  0.144 9.397 0.168 9.587 ;
     RECT  9.264 8.675 9.48 9.587 ;
     RECT  23.616 9.251 24.984 9.731 ;
     RECT  11.664 9.061 11.688 9.827 ;
     RECT  48.48 9.155 53.304 9.923 ;
     RECT  54.624 9.155 67.848 10.019 ;
     RECT  34.8 9.109 35.88 10.067 ;
     RECT  15.072 6.131 15.096 10.211 ;
     RECT  23.616 9.731 24.312 10.213 ;
     RECT  48.528 9.923 53.304 10.259 ;
     RECT  7.392 3.925 8.112 10.261 ;
     RECT  6.48 10.261 8.112 10.309 ;
     RECT  9.264 9.587 9.288 10.309 ;
     RECT  42.432 7.381 42.792 10.355 ;
     RECT  54.624 10.019 67.464 10.355 ;
     RECT  18.6 9.155 19.896 10.597 ;
     RECT  50.544 10.259 53.304 10.597 ;
     RECT  54.624 10.355 66.648 10.597 ;
     RECT  40.2 9.541 40.728 10.643 ;
     RECT  48.528 10.259 49.56 10.691 ;
     RECT  29.4 9.493 31.56 10.693 ;
     RECT  13.2 2.151 13.512 10.741 ;
     RECT  6.48 10.309 9.288 10.883 ;
     RECT  16.128 10.165 16.152 10.885 ;
     RECT  29.28 10.693 31.56 10.885 ;
     RECT  12.048 10.789 12.072 10.931 ;
     RECT  43.824 8.725 47.112 10.933 ;
     RECT  42.576 10.355 42.792 10.981 ;
     RECT  43.824 10.933 47.496 10.981 ;
     RECT  16.128 10.885 16.584 11.411 ;
     RECT  18.384 10.597 19.896 11.459 ;
     RECT  21.12 10.597 21.144 11.459 ;
     RECT  28.656 10.885 31.56 11.459 ;
     RECT  3.936 11.413 3.96 11.555 ;
     RECT  36.672 10.501 36.696 11.653 ;
     RECT  49.008 10.691 49.56 11.653 ;
     RECT  36.432 11.653 36.696 11.699 ;
     RECT  7.008 10.883 8.112 11.795 ;
     RECT  22.8 10.213 24.312 11.843 ;
     RECT  38.256 11.701 38.28 11.843 ;
     RECT  22.896 11.843 24.312 11.939 ;
     RECT  31.392 11.459 31.56 11.941 ;
     RECT  50.544 10.597 66.648 11.941 ;
     RECT  48.624 11.653 49.56 11.989 ;
     RECT  50.544 11.941 66.696 11.989 ;
     RECT  28.656 11.459 30.264 12.179 ;
     RECT  34.8 10.067 35.352 12.229 ;
     RECT  42.576 10.981 47.496 12.467 ;
     RECT  13.2 10.741 13.944 12.469 ;
     RECT  47.472 12.467 47.496 12.469 ;
     RECT  48.624 11.989 66.696 12.469 ;
     RECT  29.4 12.179 30.264 12.517 ;
     RECT  31.392 11.941 31.608 12.517 ;
     RECT  42.768 12.467 46.44 12.563 ;
     RECT  36.432 11.699 36.456 12.755 ;
     RECT  0.144 11.797 0.168 12.803 ;
     RECT  47.472 12.469 66.696 12.851 ;
     RECT  40.2 10.643 40.512 12.901 ;
     RECT  23.616 11.939 24.312 13.045 ;
     RECT  22.752 13.045 24.312 13.091 ;
     RECT  29.4 12.517 31.608 13.139 ;
     RECT  54.096 12.851 66.696 13.331 ;
     RECT  16.128 11.411 16.152 13.379 ;
     RECT  47.472 12.851 53.064 13.379 ;
     RECT  31.392 13.139 31.608 13.427 ;
     RECT  7.392 11.795 8.112 13.429 ;
     RECT  9.264 10.883 9.288 13.429 ;
     RECT  10.848 12.709 10.872 13.477 ;
     RECT  42.768 12.563 46.248 13.525 ;
     RECT  47.472 13.379 48.408 13.525 ;
     RECT  22.752 13.091 22.776 13.573 ;
     RECT  13.104 12.469 13.944 13.619 ;
     RECT  24 13.091 24.312 13.621 ;
     RECT  33.984 12.229 35.352 13.715 ;
     RECT  31.392 13.427 31.416 13.763 ;
     RECT  10.56 13.477 10.872 13.811 ;
     RECT  49.536 13.379 53.064 13.909 ;
     RECT  54.096 13.331 66.648 13.909 ;
     RECT  7.392 13.429 9.288 14.101 ;
     RECT  29.4 13.139 30.264 14.101 ;
     RECT  6.528 14.101 9.288 14.147 ;
     RECT  29.4 14.101 30.552 14.197 ;
     RECT  22.224 13.573 22.776 14.339 ;
     RECT  7.8 14.147 9.288 14.435 ;
     RECT  24 13.621 24.456 14.533 ;
     RECT  27.36 11.365 27.384 14.581 ;
     RECT  10.56 13.811 10.824 14.627 ;
     RECT  27.36 14.581 27.528 14.627 ;
     RECT  34.56 13.715 35.352 14.773 ;
     RECT  29.04 14.197 30.552 14.867 ;
     RECT  42.768 13.525 48.408 14.917 ;
     RECT  49.536 13.909 66.648 14.917 ;
     RECT  34.56 14.773 35.976 15.157 ;
     RECT  42.768 14.917 66.648 15.301 ;
     RECT  20.976 12.949 21 15.347 ;
     RECT  4.896 14.773 4.92 15.491 ;
     RECT  42.336 15.301 66.648 15.493 ;
     RECT  10.56 14.627 10.776 15.731 ;
     RECT  42.336 15.493 66.696 15.731 ;
     RECT  22.752 14.339 22.776 15.827 ;
     RECT  27.504 14.627 27.528 15.875 ;
     RECT  34.56 15.157 36.36 15.971 ;
     RECT  29.4 14.867 30.552 16.019 ;
     RECT  42.336 15.731 66.552 16.019 ;
     RECT  42.336 16.019 46.824 16.211 ;
     RECT  32.112 15.589 32.136 16.213 ;
     RECT  29.4 16.019 30.12 16.259 ;
     RECT  31.2 16.213 32.136 16.355 ;
     RECT  42.336 16.211 46.2 16.501 ;
     RECT  42.096 16.501 46.2 16.547 ;
     RECT  37.872 13.477 37.896 16.595 ;
     RECT  36.336 15.971 36.36 16.835 ;
     RECT  47.856 16.019 66.552 16.883 ;
     RECT  47.856 16.883 54.168 16.979 ;
     RECT  15.6 14.773 15.624 17.075 ;
     RECT  40.2 12.901 40.68 17.077 ;
     RECT  6.528 14.147 6.552 17.123 ;
     RECT  34.56 15.971 35.112 17.123 ;
     RECT  40.2 17.077 41.064 17.219 ;
     RECT  55.584 16.883 66.552 17.221 ;
     RECT  42.096 16.547 46.104 17.267 ;
     RECT  42.096 17.267 42.792 17.461 ;
     RECT  29.4 16.259 29.928 17.507 ;
     RECT  13.2 13.619 13.944 17.509 ;
     RECT  16.608 16.981 16.632 17.509 ;
     RECT  47.856 16.979 49.8 17.555 ;
     RECT  38.16 17.029 38.184 17.603 ;
     RECT  50.832 16.979 54.168 17.603 ;
     RECT  27.36 16.549 27.384 17.651 ;
     RECT  55.584 17.221 66.696 17.699 ;
     RECT  22.704 17.029 22.728 17.747 ;
     RECT  50.832 17.603 52.488 17.843 ;
     RECT  31.2 16.355 31.224 18.275 ;
     RECT  43.824 17.267 46.104 18.275 ;
     RECT  48.144 17.555 49.8 18.565 ;
     RECT  50.832 17.843 51.312 18.565 ;
     RECT  55.584 17.699 66.552 18.709 ;
     RECT  55.152 18.709 66.552 18.803 ;
     RECT  55.152 18.803 66.12 18.851 ;
     RECT  47.856 18.565 51.312 18.899 ;
     RECT  40.2 17.219 40.512 18.949 ;
     RECT  33.744 18.853 33.768 19.139 ;
     RECT  40.2 18.949 40.68 19.237 ;
     RECT  41.712 17.461 42.792 19.237 ;
     RECT  43.824 18.275 45.912 19.237 ;
     RECT  47.856 18.899 48.408 19.283 ;
     RECT  2.4 8.003 2.712 19.333 ;
     RECT  3.84 17.605 3.864 19.333 ;
     RECT  2.4 19.333 3.864 19.379 ;
     RECT  65.472 18.851 66.12 19.427 ;
     RECT  53.616 17.603 54.168 19.429 ;
     RECT  53.568 19.429 54.168 19.475 ;
     RECT  34.8 17.123 35.112 19.621 ;
     RECT  49.776 18.899 51.312 19.667 ;
     RECT  47.952 19.283 48.408 19.763 ;
     RECT  9.264 14.435 9.288 19.813 ;
     RECT  10.56 15.731 10.584 19.813 ;
     RECT  40.2 19.237 42.792 19.909 ;
     RECT  55.152 18.851 64.392 19.909 ;
     RECT  55.152 19.909 65.352 20.003 ;
     RECT  38.016 19.957 38.04 20.195 ;
     RECT  50.736 19.667 51.312 20.243 ;
     RECT  55.152 20.003 56.712 20.243 ;
     RECT  58.032 20.003 65.352 20.339 ;
     RECT  47.952 19.763 48.168 20.387 ;
     RECT  53.568 19.475 53.736 20.387 ;
     RECT  50.784 20.243 51.312 20.629 ;
     RECT  2.4 19.379 3.288 20.723 ;
     RECT  50.784 20.629 51.432 20.723 ;
     RECT  50.88 20.723 51.432 21.011 ;
     RECT  39.36 19.909 42.792 21.061 ;
     RECT  43.824 19.237 46.008 21.061 ;
     RECT  9.264 19.813 10.584 21.155 ;
     RECT  39.36 21.061 46.008 21.203 ;
     RECT  47.616 20.389 47.64 21.205 ;
     RECT  26.592 19.237 26.616 21.395 ;
     RECT  29.4 17.507 29.832 21.443 ;
     RECT  41.712 21.203 46.008 21.445 ;
     RECT  47.328 21.205 47.64 21.445 ;
     RECT  13.2 17.509 14.28 21.683 ;
     RECT  15.696 17.509 16.632 21.683 ;
     RECT  39.36 21.203 40.512 21.683 ;
     RECT  55.728 20.243 56.712 21.731 ;
     RECT  58.368 20.339 65.352 21.781 ;
     RECT  18.6 11.459 18.912 22.021 ;
     RECT  58.128 21.781 65.352 22.117 ;
     RECT  30.768 22.021 30.792 22.163 ;
     RECT  39.648 21.683 40.512 22.163 ;
     RECT  9.264 21.155 9.288 22.165 ;
     RECT  10.56 21.155 10.584 22.165 ;
     RECT  21.984 20.485 22.008 22.165 ;
     RECT  57.936 22.117 65.352 22.165 ;
     RECT  66.528 19.909 66.552 22.165 ;
     RECT  50.88 21.011 51.312 22.451 ;
     RECT  9.264 22.165 10.584 22.693 ;
     RECT  11.664 20.725 11.688 22.693 ;
     RECT  57.936 22.165 66.552 22.739 ;
     RECT  18.384 22.021 18.912 22.741 ;
     RECT  56.4 21.731 56.712 22.741 ;
     RECT  57.936 22.739 65.352 22.741 ;
     RECT  15.696 21.683 15.72 22.789 ;
     RECT  38.304 20.965 38.328 23.077 ;
     RECT  7.8 14.435 8.112 23.173 ;
     RECT  9.264 22.693 11.688 23.173 ;
     RECT  52.416 21.973 52.44 23.173 ;
     RECT  53.712 20.387 53.736 23.173 ;
     RECT  32.496 22.597 32.52 23.315 ;
     RECT  52.416 23.173 53.736 23.315 ;
     RECT  18.384 22.741 19.8 23.363 ;
     RECT  13.2 21.683 14.232 23.411 ;
     RECT  15.696 22.789 15.912 23.555 ;
     RECT  18.384 23.363 18.912 23.555 ;
     RECT  21.984 22.165 22.584 23.555 ;
     RECT  55.344 23.317 55.368 23.603 ;
     RECT  41.712 21.445 47.64 23.795 ;
     RECT  28.272 21.349 28.296 23.843 ;
     RECT  7.8 23.173 11.688 23.893 ;
     RECT  4.56 23.269 4.584 23.987 ;
     RECT  29.4 21.443 29.712 24.085 ;
     RECT  56.4 22.741 65.352 24.085 ;
     RECT  38.208 23.077 38.328 24.131 ;
     RECT  56.4 24.085 65.544 24.133 ;
     RECT  66.528 22.739 66.552 24.133 ;
     RECT  7.392 23.893 11.688 24.515 ;
     RECT  53.136 23.315 53.736 24.563 ;
     RECT  40.2 22.163 40.512 24.613 ;
     RECT  41.712 23.795 42.792 24.613 ;
     RECT  32.304 23.749 32.328 24.803 ;
     RECT  24 14.533 24.504 24.901 ;
     RECT  51 22.451 51.312 24.901 ;
     RECT  33.792 23.317 33.816 24.997 ;
     RECT  34.8 19.621 35.64 24.997 ;
     RECT  40.2 24.613 42.792 25.043 ;
     RECT  24 24.901 25.08 25.429 ;
     RECT  24 25.429 25.176 25.525 ;
     RECT  21.984 23.555 22.008 25.571 ;
     RECT  23.328 25.525 25.176 25.571 ;
     RECT  38.304 24.131 38.328 25.621 ;
     RECT  7.392 24.515 11.448 25.715 ;
     RECT  10.56 25.715 11.448 25.763 ;
     RECT  23.328 25.571 24.504 25.763 ;
     RECT  17.04 24.277 17.064 25.813 ;
     RECT  41.712 25.043 42.792 25.861 ;
     RECT  43.824 23.795 47.64 25.861 ;
     RECT  15.696 23.555 15.72 25.955 ;
     RECT  49.248 24.133 49.272 26.003 ;
     RECT  40.2 25.043 40.512 26.005 ;
     RECT  2.4 20.723 2.712 26.053 ;
     RECT  38.304 25.621 38.616 26.053 ;
     RECT  32.784 24.949 32.808 26.101 ;
     RECT  33.792 24.997 35.64 26.101 ;
     RECT  40.2 26.005 40.68 26.101 ;
     RECT  41.712 25.861 47.64 26.101 ;
     RECT  40.2 26.101 47.64 26.149 ;
     RECT  51 24.901 51.72 26.149 ;
     RECT  17.04 25.813 17.352 26.243 ;
     RECT  54.528 25.621 54.552 26.341 ;
     RECT  40.2 26.149 48.504 26.387 ;
     RECT  29.4 24.085 30.408 26.531 ;
     RECT  29.4 26.531 30.36 26.533 ;
     RECT  2.4 26.053 2.856 26.725 ;
     RECT  7.392 25.715 9.288 26.771 ;
     RECT  29.28 26.533 30.36 26.771 ;
     RECT  51 26.149 51.912 26.773 ;
     RECT  10.8 25.763 11.448 26.819 ;
     RECT  40.2 26.387 43.944 26.819 ;
     RECT  45.12 26.387 48.504 26.915 ;
     RECT  32.784 26.101 35.64 27.059 ;
     RECT  29.28 26.771 30.12 27.061 ;
     RECT  56.4 24.133 66.552 27.205 ;
     RECT  50.88 26.773 51.912 27.253 ;
     RECT  53.136 24.563 53.16 27.253 ;
     RECT  54.24 26.341 54.552 27.301 ;
     RECT  40.2 26.819 43.848 27.587 ;
     RECT  50.88 27.253 53.16 27.683 ;
     RECT  38.304 26.053 39.192 27.685 ;
     RECT  45.12 26.915 48.408 27.731 ;
     RECT  52.608 27.683 53.16 27.733 ;
     RECT  54.24 27.301 55.272 27.733 ;
     RECT  13.2 23.411 13.512 27.877 ;
     RECT  28.656 27.061 30.12 27.971 ;
     RECT  45.216 27.731 48.408 27.971 ;
     RECT  32.784 27.059 35.208 28.117 ;
     RECT  45.6 27.971 48.408 28.117 ;
     RECT  10.272 26.869 10.296 28.163 ;
     RECT  52.608 27.733 55.272 28.165 ;
     RECT  56.256 27.205 66.552 28.165 ;
     RECT  45.6 28.117 49.032 28.259 ;
     RECT  52.608 28.165 66.552 28.307 ;
     RECT  32.784 28.117 35.304 28.355 ;
     RECT  37.056 26.869 37.08 28.357 ;
     RECT  50.88 27.683 51.576 28.403 ;
     RECT  2.4 26.725 3.384 28.405 ;
     RECT  2.4 28.405 3.864 28.451 ;
     RECT  45.6 28.259 48.408 28.451 ;
     RECT  36.192 28.357 37.08 28.499 ;
     RECT  56.256 28.307 66.552 28.499 ;
     RECT  7.8 26.771 9.288 28.501 ;
     RECT  23.328 25.763 24.312 28.547 ;
     RECT  56.4 28.499 66.552 28.547 ;
     RECT  7.8 28.501 9.528 28.595 ;
     RECT  32.784 28.355 35.208 28.595 ;
     RECT  2.4 28.451 2.856 28.643 ;
     RECT  3.84 28.451 3.864 29.029 ;
     RECT  4.944 28.789 4.968 29.029 ;
     RECT  38.208 27.685 39.192 29.029 ;
     RECT  40.2 27.587 42.792 29.029 ;
     RECT  13.2 27.877 13.896 29.075 ;
     RECT  37.056 28.499 37.08 29.123 ;
     RECT  38.208 29.029 42.792 29.123 ;
     RECT  52.608 28.307 55.272 29.171 ;
     RECT  56.4 28.547 65.4 29.219 ;
     RECT  42.384 29.123 42.792 29.363 ;
     RECT  24 28.547 24.312 29.509 ;
     RECT  52.704 29.171 55.272 29.555 ;
     RECT  38.208 29.123 41.304 29.603 ;
     RECT  48.72 29.509 48.744 29.605 ;
     RECT  51 28.403 51.576 29.653 ;
     RECT  9.264 28.595 9.528 29.699 ;
     RECT  9.504 29.699 9.528 29.795 ;
     RECT  29.28 27.971 30.12 29.795 ;
     RECT  29.28 29.795 30.024 29.941 ;
     RECT  39.12 29.603 41.304 30.035 ;
     RECT  45.6 28.451 47.64 30.035 ;
     RECT  3.84 29.029 4.968 30.179 ;
     RECT  52.704 29.555 54.696 30.275 ;
     RECT  56.4 29.219 64.968 30.275 ;
     RECT  56.4 30.275 64.872 30.323 ;
     RECT  3.84 30.179 4.728 30.371 ;
     RECT  13.2 29.075 13.512 30.373 ;
     RECT  15.456 28.453 15.48 30.373 ;
     RECT  11.424 26.819 11.448 30.515 ;
     RECT  48.72 29.605 49.224 30.611 ;
     RECT  40.2 30.035 41.304 30.613 ;
     RECT  42.384 29.363 42.408 30.613 ;
     RECT  29.088 29.941 30.024 30.659 ;
     RECT  24 29.509 24.456 30.707 ;
     RECT  12.624 30.373 13.512 30.709 ;
     RECT  15.456 30.373 15.96 30.709 ;
     RECT  15.024 30.709 15.96 30.757 ;
     RECT  43.824 27.587 43.848 30.757 ;
     RECT  40.2 30.613 42.408 30.803 ;
     RECT  14.736 30.757 15.96 30.851 ;
     RECT  32.784 28.595 35.112 30.851 ;
     RECT  14.736 30.851 15.048 30.899 ;
     RECT  41.568 30.803 42.408 30.899 ;
     RECT  43.824 30.757 43.992 30.901 ;
     RECT  50.88 29.653 51.576 30.901 ;
     RECT  52.704 30.275 54.648 30.947 ;
     RECT  39.12 30.035 39.192 31.139 ;
     RECT  52.704 30.947 53.304 31.139 ;
     RECT  50.352 30.901 51.576 31.189 ;
     RECT  54.288 30.947 54.648 31.379 ;
     RECT  12.528 30.709 13.512 31.427 ;
     RECT  52.992 31.139 53.304 31.427 ;
     RECT  43.824 30.901 44.232 31.475 ;
     RECT  7.8 28.595 8.112 31.669 ;
     RECT  56.4 30.323 64.392 31.669 ;
     RECT  21.936 29.893 21.96 31.811 ;
     RECT  39.168 31.139 39.192 31.861 ;
     RECT  40.2 30.803 40.512 31.861 ;
     RECT  4.704 30.371 4.728 31.955 ;
     RECT  11.28 31.237 11.304 31.955 ;
     RECT  12.624 31.427 13.512 31.955 ;
     RECT  29.4 30.659 30.024 31.955 ;
     RECT  45.6 30.035 47.352 31.955 ;
     RECT  55.776 31.669 64.392 32.003 ;
     RECT  58.464 32.003 64.392 32.053 ;
     RECT  41.568 30.899 41.592 32.099 ;
     RECT  58.464 32.053 64.728 32.099 ;
     RECT  53.04 31.427 53.304 32.149 ;
     RECT  54.288 31.379 54.408 32.149 ;
     RECT  45.6 31.955 47.256 32.243 ;
     RECT  48.72 30.611 48.744 32.245 ;
     RECT  50.352 31.189 51.672 32.245 ;
     RECT  53.04 32.149 54.408 32.387 ;
     RECT  39.168 31.861 40.512 32.485 ;
     RECT  38.688 32.485 40.512 32.531 ;
     RECT  38.688 32.531 39.192 32.723 ;
     RECT  58.896 32.099 64.728 32.965 ;
     RECT  17.328 26.243 17.352 33.061 ;
     RECT  17.328 33.061 17.496 33.107 ;
     RECT  43.968 31.475 44.232 33.299 ;
     RECT  55.776 32.003 57.432 33.301 ;
     RECT  45.6 32.243 47.112 33.347 ;
     RECT  33.36 30.851 35.112 33.397 ;
     RECT  29.4 31.955 29.976 33.491 ;
     RECT  53.136 32.387 54.408 33.491 ;
     RECT  33.12 33.397 35.112 33.539 ;
     RECT  54.144 33.491 54.408 33.683 ;
     RECT  66.528 28.547 66.552 33.683 ;
     RECT  58.896 32.965 64.968 33.779 ;
     RECT  48.72 32.245 51.672 33.827 ;
     RECT  49.68 33.827 51.672 34.067 ;
     RECT  54.288 33.683 54.408 34.117 ;
     RECT  55.776 33.301 57.624 34.259 ;
     RECT  15.024 30.899 15.048 34.355 ;
     RECT  56.256 34.259 57.624 34.355 ;
     RECT  7.8 31.669 8.232 34.403 ;
     RECT  56.256 34.355 57.288 34.499 ;
     RECT  49.824 34.067 51.672 34.645 ;
     RECT  18.6 23.555 18.912 34.741 ;
     RECT  54.288 34.117 54.696 34.741 ;
     RECT  58.896 33.779 64.728 34.835 ;
     RECT  53.136 33.491 53.16 35.123 ;
     RECT  56.256 34.499 57.144 35.123 ;
     RECT  56.256 35.123 56.808 35.459 ;
     RECT  54.288 34.741 54.888 35.509 ;
     RECT  18.6 34.741 19.272 35.651 ;
     RECT  58.896 34.835 64.584 35.845 ;
     RECT  65.76 35.701 65.784 35.845 ;
     RECT  13.2 31.955 13.512 35.893 ;
     RECT  15.264 35.317 15.288 35.939 ;
     RECT  38.688 32.723 38.712 35.939 ;
     RECT  31.584 30.181 31.608 35.987 ;
     RECT  58.896 35.845 65.784 35.987 ;
     RECT  29.4 33.491 29.712 36.037 ;
     RECT  7.8 34.403 8.112 36.325 ;
     RECT  12.336 35.893 13.512 36.515 ;
     RECT  49.824 34.645 51.912 36.515 ;
     RECT  58.896 35.987 59.112 36.515 ;
     RECT  50.016 36.515 51.912 36.563 ;
     RECT  54.288 35.509 55.32 36.565 ;
     RECT  56.304 35.459 56.808 36.565 ;
     RECT  60.432 35.987 65.784 36.803 ;
     RECT  65.376 36.803 65.784 36.851 ;
     RECT  7.8 36.325 8.232 36.901 ;
     RECT  54.288 36.565 56.808 37.139 ;
     RECT  65.76 36.851 65.784 37.331 ;
     RECT  7.8 36.901 8.52 37.427 ;
     RECT  54.288 37.139 56.712 37.429 ;
     RECT  50.88 36.563 51.912 37.573 ;
     RECT  58.896 36.515 59.064 37.669 ;
     RECT  60.432 36.803 63.72 37.669 ;
     RECT  4.416 36.853 4.44 37.907 ;
     RECT  37.056 36.997 37.08 38.101 ;
     RECT  37.056 38.101 37.848 38.147 ;
     RECT  24 30.707 24.312 38.149 ;
     RECT  58.896 37.669 63.72 38.195 ;
     RECT  60.432 38.195 63.72 38.197 ;
     RECT  60.432 38.197 64.392 38.387 ;
     RECT  60.432 38.387 63.144 38.483 ;
     RECT  57.84 36.853 57.864 38.629 ;
     RECT  58.896 38.195 59.256 38.629 ;
     RECT  5.424 38.149 5.448 38.675 ;
     RECT  33.12 33.539 33.144 38.675 ;
     RECT  17.472 33.107 17.496 38.725 ;
     RECT  60.432 38.483 62.112 38.819 ;
     RECT  37.824 38.147 37.848 38.915 ;
     RECT  64.368 38.387 64.392 38.915 ;
     RECT  63.12 38.483 63.144 39.011 ;
     RECT  7.8 37.427 8.232 39.205 ;
     RECT  24 38.149 25.032 39.251 ;
     RECT  0.24 39.013 0.264 39.299 ;
     RECT  26.064 36.613 26.088 39.349 ;
     RECT  7.68 39.205 8.232 39.587 ;
     RECT  45.6 33.347 45.912 39.589 ;
     RECT  47.088 33.347 47.112 39.589 ;
     RECT  7.68 39.587 8.112 39.731 ;
     RECT  57.84 38.629 59.256 39.781 ;
     RECT  0.144 39.493 0.168 39.875 ;
     RECT  17.232 38.725 17.496 39.877 ;
     RECT  18.6 35.651 18.912 39.877 ;
     RECT  17.232 39.877 18.912 39.923 ;
     RECT  21.6 38.149 21.624 39.923 ;
     RECT  45.312 39.589 45.912 40.019 ;
     RECT  57.792 39.781 59.256 40.019 ;
     RECT  48.816 36.901 48.84 40.165 ;
     RECT  44.304 38.725 44.328 40.259 ;
     RECT  26.064 39.349 26.328 40.307 ;
     RECT  31.824 38.725 31.848 40.451 ;
     RECT  10.656 36.997 10.68 40.499 ;
     RECT  54.144 37.429 56.712 40.499 ;
     RECT  28.464 36.037 29.712 40.547 ;
     RECT  54.912 40.499 56.712 40.643 ;
     RECT  17.472 39.923 18.912 40.691 ;
     RECT  57.792 40.019 58.104 40.835 ;
     RECT  55.92 40.643 56.712 40.883 ;
     RECT  57.792 40.835 57.864 40.883 ;
     RECT  48.816 40.165 49.128 40.979 ;
     RECT  38.784 40.405 38.808 41.075 ;
     RECT  48.816 40.979 49.032 41.075 ;
     RECT  50.88 37.573 52.296 41.075 ;
     RECT  54.912 40.643 54.936 41.075 ;
     RECT  59.232 40.019 59.256 41.075 ;
     RECT  29.4 40.547 29.712 41.557 ;
     RECT  31.248 41.269 31.272 41.557 ;
     RECT  6.528 40.837 6.552 41.603 ;
     RECT  2.4 28.643 2.712 41.989 ;
     RECT  13.2 36.515 13.512 41.989 ;
     RECT  24 39.251 24.312 41.989 ;
     RECT  26.064 40.307 26.088 41.989 ;
     RECT  26.064 41.989 26.232 42.035 ;
     RECT  17.472 40.691 17.496 42.133 ;
     RECT  18.48 40.691 18.912 42.133 ;
     RECT  27.936 41.509 27.96 42.179 ;
     RECT  57.84 40.883 57.864 42.181 ;
     RECT  47.088 39.589 47.448 42.227 ;
     RECT  57.84 42.181 58.056 42.227 ;
     RECT  13.104 41.989 13.512 42.229 ;
     RECT  23.52 41.989 24.312 42.611 ;
     RECT  29.4 41.557 31.272 42.709 ;
     RECT  2.304 41.989 2.712 42.755 ;
     RECT  13.104 42.229 13.608 42.803 ;
     RECT  17.472 42.133 18.912 42.803 ;
     RECT  26.208 42.035 26.232 42.997 ;
     RECT  10.608 40.741 10.632 43.093 ;
     RECT  11.664 42.085 11.688 43.093 ;
     RECT  14.784 39.445 14.808 43.139 ;
     RECT  10.608 43.093 11.688 43.141 ;
     RECT  42.096 40.741 42.12 43.141 ;
     RECT  13.104 42.803 13.512 43.379 ;
     RECT  65.712 42.757 65.736 43.379 ;
     RECT  60.48 38.819 62.112 43.669 ;
     RECT  25.776 42.997 26.232 43.717 ;
     RECT  10.272 43.141 11.688 43.811 ;
     RECT  5.664 43.717 5.688 43.859 ;
     RECT  10.272 43.811 11.112 43.907 ;
     RECT  29.4 42.709 31.368 44.051 ;
     RECT  37.104 41.557 37.128 44.195 ;
     RECT  42.096 43.141 42.792 44.195 ;
     RECT  42.768 44.195 42.792 44.245 ;
     RECT  44.448 43.093 44.472 44.245 ;
     RECT  45.6 40.019 45.912 44.341 ;
     RECT  47.088 42.227 47.112 44.341 ;
     RECT  13.2 43.379 13.512 44.437 ;
     RECT  25.776 43.717 26.904 44.483 ;
     RECT  29.4 44.051 30.552 44.483 ;
     RECT  42.768 44.245 44.472 44.483 ;
     RECT  45.6 44.341 47.112 44.483 ;
     RECT  50.88 41.075 51.912 44.483 ;
     RECT  29.4 44.483 29.712 44.725 ;
     RECT  34.32 33.539 35.112 44.725 ;
     RECT  7.8 39.731 8.112 44.965 ;
     RECT  48.816 41.075 48.84 45.059 ;
     RECT  34.32 44.725 35.208 45.109 ;
     RECT  31.2 45.157 31.32 45.299 ;
     RECT  31.2 45.299 31.224 45.443 ;
     RECT  3.984 44.437 4.008 45.637 ;
     RECT  3.984 45.637 4.104 45.683 ;
     RECT  21.648 44.965 21.672 45.875 ;
     RECT  43.584 44.483 44.472 45.877 ;
     RECT  56.4 40.883 56.712 45.877 ;
     RECT  58.032 42.227 58.056 45.877 ;
     RECT  56.4 45.877 58.056 45.923 ;
     RECT  7.392 44.965 8.112 45.973 ;
     RECT  29.28 44.725 29.712 45.973 ;
     RECT  10.608 43.907 11.112 46.019 ;
     RECT  27.744 45.301 27.768 46.115 ;
     RECT  18.48 42.803 18.912 46.211 ;
     RECT  30.768 45.685 30.792 46.211 ;
     RECT  34.32 45.109 35.88 46.211 ;
     RECT  45.6 44.483 46.536 46.211 ;
     RECT  25.776 44.483 26.04 46.213 ;
     RECT  13.2 44.437 13.656 46.259 ;
     RECT  53.856 43.813 53.88 46.259 ;
     RECT  60.48 43.669 62.808 46.259 ;
     RECT  13.2 46.259 13.512 46.261 ;
     RECT  60.48 46.259 62.112 46.309 ;
     RECT  56.4 45.923 57.624 46.693 ;
     RECT  4.08 45.683 4.104 46.787 ;
     RECT  17.472 42.803 17.496 46.787 ;
     RECT  43.584 45.877 44.52 46.787 ;
     RECT  10.8 46.019 11.112 46.883 ;
     RECT  33.024 44.773 33.048 46.981 ;
     RECT  34.32 46.211 35.112 46.981 ;
     RECT  33.024 46.981 35.112 47.027 ;
     RECT  49.824 45.541 49.848 47.027 ;
     RECT  7.392 45.973 8.52 47.029 ;
     RECT  10.8 46.883 10.824 47.029 ;
     RECT  43.584 46.787 43.896 47.029 ;
     RECT  18.6 46.211 18.912 47.125 ;
     RECT  64.704 46.117 64.728 47.173 ;
     RECT  33.792 47.027 35.112 47.221 ;
     RECT  56.304 46.693 57.624 47.315 ;
     RECT  60.432 46.309 62.112 47.315 ;
     RECT  7.104 47.029 8.52 47.363 ;
     RECT  29.232 45.973 29.712 47.459 ;
     RECT  18.6 47.125 19.848 47.653 ;
     RECT  25.776 46.213 26.76 47.653 ;
     RECT  29.28 47.459 29.712 47.699 ;
     RECT  2.4 42.755 2.712 47.701 ;
     RECT  64.08 47.173 64.728 47.701 ;
     RECT  63.648 47.701 64.728 47.747 ;
     RECT  33.792 47.221 35.352 47.843 ;
     RECT  10.512 47.029 10.824 47.845 ;
     RECT  18.432 47.653 19.848 47.893 ;
     RECT  38.592 44.149 38.616 47.939 ;
     RECT  12.528 46.261 13.512 48.131 ;
     RECT  17.616 47.893 19.848 48.131 ;
     RECT  63.648 47.747 64.104 48.131 ;
     RECT  7.104 47.363 8.112 48.229 ;
     RECT  45.6 46.211 45.912 48.277 ;
     RECT  25.392 47.653 26.76 48.421 ;
     RECT  56.4 47.315 57.624 48.469 ;
     RECT  2.4 47.701 2.856 48.659 ;
     RECT  17.616 48.131 18.912 48.659 ;
     RECT  45.6 48.277 46.008 48.661 ;
     RECT  6.192 48.229 8.112 48.707 ;
     RECT  13.104 48.131 13.512 48.707 ;
     RECT  15.024 46.357 15.048 48.899 ;
     RECT  65.28 47.845 65.304 48.949 ;
     RECT  53.184 47.845 53.208 49.043 ;
     RECT  55.872 48.469 57.624 49.139 ;
     RECT  25.392 48.421 27.72 49.235 ;
     RECT  7.104 48.707 8.112 49.285 ;
     RECT  18.288 48.659 18.912 49.331 ;
     RECT  56.4 49.139 57.624 49.333 ;
     RECT  13.2 48.707 13.512 49.477 ;
     RECT  45.6 48.661 46.056 49.571 ;
     RECT  65.28 48.949 65.784 49.571 ;
     RECT  56.4 49.333 58.056 49.619 ;
     RECT  31.872 48.949 31.896 49.763 ;
     RECT  7.104 49.285 8.232 49.861 ;
     RECT  58.032 49.619 58.056 50.053 ;
     RECT  59.28 47.845 59.304 50.053 ;
     RECT  18.432 49.331 18.912 50.101 ;
     RECT  24 42.611 24.312 50.101 ;
     RECT  60.48 47.315 62.112 50.101 ;
     RECT  7.056 49.861 8.232 50.147 ;
     RECT  58.032 50.053 59.304 50.147 ;
     RECT  13.2 49.477 13.608 50.195 ;
     RECT  43.488 47.029 43.896 50.195 ;
     RECT  25.392 49.235 26.76 50.339 ;
     RECT  4.992 49.333 5.016 50.435 ;
     RECT  10.512 47.845 11.4 50.435 ;
     RECT  58.368 50.147 59.304 50.531 ;
     RECT  65.28 49.571 65.304 50.531 ;
     RECT  2.4 48.659 2.712 50.629 ;
     RECT  56.4 49.619 56.808 50.677 ;
     RECT  63.648 48.131 63.672 50.819 ;
     RECT  45.6 49.571 45.912 50.965 ;
     RECT  60.336 50.101 62.112 51.109 ;
     RECT  53.52 50.965 53.544 51.203 ;
     RECT  23.808 50.101 24.312 51.205 ;
     RECT  56.256 50.677 56.808 51.205 ;
     RECT  13.2 50.195 13.512 51.253 ;
     RECT  9.12 51.157 9.144 51.301 ;
     RECT  9.12 51.301 9.288 51.347 ;
     RECT  18.432 50.101 19.368 51.347 ;
     RECT  34.32 47.843 35.352 51.443 ;
     RECT  51 44.483 51.912 51.493 ;
     RECT  56.064 51.205 56.808 51.539 ;
     RECT  51 51.493 52.008 51.635 ;
     RECT  60.336 51.109 62.232 51.635 ;
     RECT  56.112 51.539 56.808 51.829 ;
     RECT  44.736 50.965 45.912 51.875 ;
     RECT  48.432 51.253 48.456 51.923 ;
     RECT  18.432 51.347 18.912 52.021 ;
     RECT  43.488 50.195 43.656 52.021 ;
     RECT  21.408 52.021 21.432 52.165 ;
     RECT  2.4 50.629 2.856 52.211 ;
     RECT  15.36 52.165 15.384 52.261 ;
     RECT  60.336 51.635 62.112 52.261 ;
     RECT  21.168 52.165 21.432 52.357 ;
     RECT  15.312 52.261 15.384 52.405 ;
     RECT  29.4 47.699 29.712 52.405 ;
     RECT  34.8 51.443 35.352 52.405 ;
     RECT  51 51.635 51.912 52.405 ;
     RECT  58.368 50.531 58.392 52.405 ;
     RECT  59.808 52.261 62.112 52.405 ;
     RECT  15.264 52.405 15.384 52.451 ;
     RECT  10.512 50.435 11.016 52.499 ;
     RECT  21.168 52.357 21.576 52.739 ;
     RECT  56.112 51.829 57.096 52.789 ;
     RECT  65.136 51.205 65.16 52.837 ;
     RECT  65.136 52.837 65.592 52.883 ;
     RECT  7.056 50.147 8.112 52.933 ;
     RECT  9.264 51.347 9.288 52.933 ;
     RECT  21.552 52.739 21.576 52.979 ;
     RECT  13.2 51.253 14.232 52.981 ;
     RECT  40.2 32.531 40.512 52.981 ;
     RECT  56.112 52.789 57.288 52.981 ;
     RECT  58.368 52.405 62.112 52.981 ;
     RECT  23.424 51.205 24.312 53.029 ;
     RECT  25.392 50.339 25.944 53.029 ;
     RECT  16.8 52.741 16.824 53.075 ;
     RECT  43.488 52.021 43.944 53.075 ;
     RECT  45.6 51.875 45.912 53.125 ;
     RECT  12.528 52.981 14.232 53.267 ;
     RECT  36.432 52.981 36.456 53.267 ;
     RECT  56.112 52.981 62.112 53.269 ;
     RECT  34.176 52.405 35.352 53.555 ;
     RECT  28.224 53.269 28.248 53.557 ;
     RECT  45.6 53.125 46.152 53.749 ;
     RECT  12.528 53.267 13.512 53.795 ;
     RECT  23.424 53.029 25.944 53.795 ;
     RECT  44.88 53.749 46.152 53.845 ;
     RECT  55.92 53.269 62.112 53.845 ;
     RECT  18.24 52.021 18.912 53.941 ;
     RECT  20.112 52.549 20.136 53.941 ;
     RECT  15.264 52.451 15.336 53.987 ;
     RECT  49.104 53.557 49.128 53.987 ;
     RECT  29.4 52.405 29.88 54.083 ;
     RECT  18.24 53.941 20.136 54.131 ;
     RECT  25.392 53.795 25.944 54.179 ;
     RECT  17.088 53.077 17.112 54.275 ;
     RECT  44.88 53.845 46.632 54.419 ;
     RECT  25.92 54.179 25.944 54.565 ;
     RECT  55.68 53.845 62.112 54.565 ;
     RECT  50.16 52.405 51.912 54.709 ;
     RECT  52.896 54.085 52.92 54.709 ;
     RECT  19.92 54.131 20.136 54.755 ;
     RECT  25.92 54.565 26.04 54.755 ;
     RECT  27.888 53.557 28.248 54.755 ;
     RECT  50.16 54.709 52.92 54.755 ;
     RECT  4.032 53.941 4.056 54.851 ;
     RECT  10.512 52.499 10.536 54.901 ;
     RECT  7.056 52.933 9.288 55.139 ;
     RECT  15.264 53.987 15.288 55.139 ;
     RECT  10.512 54.901 11.496 55.187 ;
     RECT  65.568 52.883 65.592 55.189 ;
     RECT  55.68 54.565 62.28 55.237 ;
     RECT  13.104 53.795 13.512 55.283 ;
     RECT  50.16 54.755 52.632 55.283 ;
     RECT  18.24 54.131 18.912 55.331 ;
     RECT  25.92 54.755 25.944 55.331 ;
     RECT  28.224 54.755 28.248 55.331 ;
     RECT  41.664 51.397 41.688 55.379 ;
     RECT  23.424 53.795 24.312 55.381 ;
     RECT  51 55.283 52.632 55.427 ;
     RECT  55.632 55.237 62.28 55.429 ;
     RECT  55.632 55.429 63.288 55.813 ;
     RECT  44.88 54.419 45.912 55.859 ;
     RECT  10.512 55.187 11.352 55.907 ;
     RECT  23.424 55.381 24.504 55.907 ;
     RECT  55.632 55.813 64.2 55.955 ;
     RECT  65.328 55.189 65.592 55.955 ;
     RECT  24 55.907 24.504 56.245 ;
     RECT  13.2 55.283 13.512 56.389 ;
     RECT  55.68 55.955 64.2 56.389 ;
     RECT  65.328 55.955 65.352 56.389 ;
     RECT  54.096 54.661 54.12 56.435 ;
     RECT  16.992 55.813 17.016 56.483 ;
     RECT  29.4 54.083 29.712 56.677 ;
     RECT  7.8 55.139 9.288 56.723 ;
     RECT  55.68 56.389 65.352 56.917 ;
     RECT  18.384 55.331 18.912 56.963 ;
     RECT  43.488 53.075 43.896 56.965 ;
     RECT  42.768 56.965 43.896 57.011 ;
     RECT  24 56.245 24.552 57.059 ;
     RECT  51 55.427 51.912 57.059 ;
     RECT  34.8 53.555 35.352 57.349 ;
     RECT  55.152 56.917 65.352 57.395 ;
     RECT  5.28 55.237 5.304 57.445 ;
     RECT  45.6 55.859 45.912 57.445 ;
     RECT  5.28 57.445 5.4 57.491 ;
     RECT  32.496 55.813 32.52 57.635 ;
     RECT  51 57.059 51.672 57.827 ;
     RECT  22.608 56.917 22.632 58.069 ;
     RECT  20.112 54.755 20.136 58.115 ;
     RECT  28.272 55.525 28.296 58.115 ;
     RECT  3.696 57.445 3.72 58.163 ;
     RECT  42.768 57.011 43.608 58.163 ;
     RECT  13.2 56.389 13.896 58.357 ;
     RECT  18.6 56.963 18.912 58.357 ;
     RECT  10.512 55.907 10.536 58.501 ;
     RECT  12 58.117 12.024 58.501 ;
     RECT  48.24 58.549 48.264 58.597 ;
     RECT  5.328 57.491 5.4 58.645 ;
     RECT  10.512 58.501 12.024 58.739 ;
     RECT  11.04 58.739 12.024 58.787 ;
     RECT  47.904 58.597 48.264 58.835 ;
     RECT  22.56 58.069 22.632 58.883 ;
     RECT  55.152 57.395 62.328 58.883 ;
     RECT  9.264 56.723 9.288 58.885 ;
     RECT  9.264 58.885 9.672 58.931 ;
     RECT  55.152 58.883 62.232 58.933 ;
     RECT  54.24 58.933 62.232 59.027 ;
     RECT  29.4 56.677 30.696 59.029 ;
     RECT  34.8 57.349 35.592 59.221 ;
     RECT  52.944 56.389 52.968 59.315 ;
     RECT  4.56 58.645 5.4 59.459 ;
     RECT  54.24 59.027 58.056 59.797 ;
     RECT  48.24 58.835 48.264 59.843 ;
     RECT  18.6 58.357 19.176 59.891 ;
     RECT  59.184 59.027 62.232 59.891 ;
     RECT  60.624 59.891 62.232 59.987 ;
     RECT  29.4 59.029 31.224 60.037 ;
     RECT  13.2 58.357 14.232 60.181 ;
     RECT  34.608 59.221 35.592 60.229 ;
     RECT  39.264 52.981 40.512 60.229 ;
     RECT  52.992 59.797 58.056 60.275 ;
     RECT  18.6 59.891 18.912 60.325 ;
     RECT  64.176 57.395 65.352 60.325 ;
     RECT  64.176 60.325 65.496 60.371 ;
     RECT  11.04 58.787 11.064 60.419 ;
     RECT  39.264 60.229 41.496 60.421 ;
     RECT  38.784 60.421 41.496 60.467 ;
     RECT  65.232 60.371 65.496 60.467 ;
     RECT  38.784 60.467 38.808 60.469 ;
     RECT  45.6 57.445 46.008 60.517 ;
     RECT  51 57.827 51.312 60.565 ;
     RECT  60.672 59.987 62.232 60.611 ;
     RECT  13.2 60.181 14.28 60.661 ;
     RECT  22.608 58.883 22.632 60.757 ;
     RECT  22.608 60.757 22.776 60.805 ;
     RECT  64.176 60.371 64.2 60.851 ;
     RECT  29.4 60.037 31.656 60.949 ;
     RECT  40.2 60.467 41.496 60.949 ;
     RECT  51 60.565 51.672 60.995 ;
     RECT  53.184 60.275 58.056 61.091 ;
     RECT  7.8 56.723 8.112 61.189 ;
     RECT  12.864 60.661 14.28 61.379 ;
     RECT  25.728 60.517 25.752 61.379 ;
     RECT  44.736 60.517 46.008 61.379 ;
     RECT  65.232 60.467 65.352 61.427 ;
     RECT  12.864 61.379 14.232 61.619 ;
     RECT  34.416 60.229 35.592 61.619 ;
     RECT  22.464 60.805 22.776 61.667 ;
     RECT  28.416 60.949 31.656 61.667 ;
     RECT  59.184 59.891 59.64 61.765 ;
     RECT  60.816 60.611 62.232 61.765 ;
     RECT  53.184 61.091 57.576 61.813 ;
     RECT  34.8 61.619 35.592 61.909 ;
     RECT  52.992 61.813 57.576 61.955 ;
     RECT  51 60.995 51.528 62.051 ;
     RECT  52.992 61.955 53.208 62.147 ;
     RECT  9.648 58.931 9.672 62.195 ;
     RECT  37.824 60.469 38.808 62.195 ;
     RECT  65.328 61.427 65.352 62.195 ;
     RECT  40.2 60.949 42.168 62.243 ;
     RECT  47.616 61.477 47.64 62.243 ;
     RECT  6.816 61.189 8.112 62.339 ;
     RECT  24 57.059 24.312 62.437 ;
     RECT  29.4 61.667 31.656 62.485 ;
     RECT  34.8 61.909 35.928 62.629 ;
     RECT  54.576 61.955 57.576 62.629 ;
     RECT  33.504 62.629 35.928 62.675 ;
     RECT  59.184 61.765 62.232 62.675 ;
     RECT  45.6 61.379 46.008 62.677 ;
     RECT  29.4 62.485 31.896 62.723 ;
     RECT  38.784 62.195 38.808 62.723 ;
     RECT  5.376 59.459 5.4 62.771 ;
     RECT  17.664 60.325 18.912 62.771 ;
     RECT  26.208 62.005 26.232 63.155 ;
     RECT  22.464 61.667 22.488 63.251 ;
     RECT  15.744 62.341 15.768 63.299 ;
     RECT  33.504 62.675 35.448 63.299 ;
     RECT  47.856 62.677 47.88 63.299 ;
     RECT  64.944 62.677 64.968 63.347 ;
     RECT  51 62.051 51.48 63.349 ;
     RECT  52.992 62.147 53.016 63.349 ;
     RECT  51 63.349 53.016 63.443 ;
     RECT  7.8 62.339 8.112 63.589 ;
     RECT  40.2 62.243 41.496 63.589 ;
     RECT  45.504 62.677 46.008 63.635 ;
     RECT  29.4 62.723 31.512 63.683 ;
     RECT  59.232 62.675 62.232 63.685 ;
     RECT  63.216 63.205 63.24 63.685 ;
     RECT  54.576 62.629 57.864 63.733 ;
     RECT  2.4 52.211 2.712 63.781 ;
     RECT  13.2 61.619 14.232 63.781 ;
     RECT  54.576 63.733 58.152 63.781 ;
     RECT  59.232 63.685 63.24 63.781 ;
     RECT  52.368 63.443 53.016 63.827 ;
     RECT  13.2 63.781 15.192 63.875 ;
     RECT  33.504 63.299 33.528 63.923 ;
     RECT  34.8 63.299 35.448 64.019 ;
     RECT  24 62.437 24.408 64.117 ;
     RECT  15.168 63.875 15.192 64.355 ;
     RECT  24 64.117 24.456 64.357 ;
     RECT  51 63.443 51.312 64.405 ;
     RECT  29.4 63.683 30.84 64.451 ;
     RECT  45.6 63.635 46.008 64.451 ;
     RECT  50.448 64.405 51.312 64.549 ;
     RECT  52.368 63.827 52.488 64.549 ;
     RECT  30.816 64.451 30.84 64.595 ;
     RECT  18.6 62.771 18.912 64.597 ;
     RECT  5.184 64.117 5.208 64.691 ;
     RECT  50.448 64.549 52.488 64.837 ;
     RECT  50.448 64.837 52.92 64.933 ;
     RECT  54.576 63.781 63.24 65.027 ;
     RECT  24 64.357 24.84 65.171 ;
     RECT  50.4 64.933 52.92 65.461 ;
     RECT  34.8 64.019 35.4 65.603 ;
     RECT  2.4 63.781 3.432 65.845 ;
     RECT  40.2 63.589 41.544 66.083 ;
     RECT  44.496 63.061 44.52 66.131 ;
     RECT  54.576 65.027 55.176 66.179 ;
     RECT  40.2 66.083 40.632 66.227 ;
     RECT  30.96 64.837 30.984 66.275 ;
     RECT  56.256 65.027 63.24 66.275 ;
     RECT  63.216 66.275 63.24 66.467 ;
     RECT  24 65.171 24.408 66.563 ;
     RECT  2.4 65.845 3.624 66.611 ;
     RECT  50.16 65.461 52.92 66.661 ;
     RECT  17.664 64.597 18.912 66.707 ;
     RECT  7.8 63.589 9.096 66.755 ;
     RECT  56.256 66.275 62.232 66.803 ;
     RECT  50.064 66.661 52.92 66.901 ;
     RECT  2.4 66.611 2.712 66.969 ;
     RECT  7.8 66.755 8.112 66.969 ;
     RECT  13.2 63.875 13.512 66.969 ;
     RECT  18.6 66.707 18.912 66.969 ;
     RECT  24 66.563 24.312 66.969 ;
     RECT  29.4 64.451 29.712 66.969 ;
     RECT  34.8 65.603 35.112 66.969 ;
     RECT  40.2 66.227 40.512 66.969 ;
     RECT  45.6 64.451 45.912 66.969 ;
     RECT  2.4 66.969 2.52 66.983 ;
     RECT  7.8 66.969 7.92 66.983 ;
     RECT  13.2 66.969 13.32 66.983 ;
     RECT  18.6 66.969 18.72 66.983 ;
     RECT  24 66.969 24.12 66.983 ;
     RECT  29.4 66.969 29.52 66.983 ;
     RECT  34.8 66.969 34.92 66.983 ;
     RECT  40.2 66.969 40.32 66.983 ;
     RECT  45.6 66.969 45.72 66.983 ;
     RECT  56.256 66.803 62.184 67.237 ;
     RECT  50.064 66.901 52.968 68.341 ;
     RECT  49.968 68.341 52.968 69.036 ;
     RECT  49.992 69.036 50.064 69.072 ;
     RECT  50.088 69.036 50.16 69.072 ;
     RECT  50.184 69.036 50.256 69.072 ;
     RECT  50.28 69.036 50.352 69.072 ;
     RECT  50.376 69.036 50.448 69.072 ;
     RECT  50.472 69.036 50.544 69.072 ;
     RECT  50.568 69.036 50.64 69.072 ;
     RECT  50.664 69.036 50.736 69.072 ;
     RECT  50.76 69.036 50.832 69.072 ;
     RECT  50.856 69.036 50.928 69.072 ;
     RECT  50.952 69.036 51.024 69.072 ;
     RECT  51.048 69.036 51.12 69.072 ;
     RECT  51.144 69.036 51.216 69.072 ;
     RECT  51.24 69.036 51.312 69.072 ;
     RECT  51.336 69.036 51.408 69.072 ;
     RECT  51.432 69.036 51.504 69.072 ;
     RECT  51.528 69.036 51.6 69.072 ;
     RECT  51.624 69.036 51.696 69.072 ;
     RECT  51.72 69.036 51.792 69.072 ;
     RECT  51.816 69.036 51.888 69.072 ;
     RECT  51.912 69.036 51.984 69.072 ;
     RECT  52.008 69.036 52.08 69.072 ;
     RECT  52.104 69.036 52.176 69.072 ;
     RECT  52.2 69.036 52.272 69.072 ;
     RECT  52.296 69.036 52.368 69.072 ;
     RECT  52.392 69.036 52.464 69.072 ;
     RECT  52.488 69.036 52.56 69.072 ;
     RECT  52.584 69.036 52.656 69.072 ;
     RECT  52.68 69.036 52.752 69.072 ;
     RECT  52.776 69.036 52.848 69.072 ;
     RECT  52.872 69.036 52.944 69.072 ;
     RECT  56.112 67.237 62.184 69.036 ;
     RECT  56.136 69.036 56.208 69.072 ;
     RECT  56.232 69.036 56.304 69.072 ;
     RECT  56.328 69.036 56.4 69.072 ;
     RECT  56.424 69.036 56.496 69.072 ;
     RECT  56.52 69.036 56.592 69.072 ;
     RECT  56.616 69.036 56.688 69.072 ;
     RECT  56.712 69.036 56.784 69.072 ;
     RECT  56.808 69.036 56.88 69.072 ;
     RECT  56.904 69.036 56.976 69.072 ;
     RECT  57 69.036 57.072 69.072 ;
     RECT  57.096 69.036 57.168 69.072 ;
     RECT  57.192 69.036 57.264 69.072 ;
     RECT  57.288 69.036 57.36 69.072 ;
     RECT  57.384 69.036 57.456 69.072 ;
     RECT  57.48 69.036 57.552 69.072 ;
     RECT  57.576 69.036 57.648 69.072 ;
     RECT  57.672 69.036 57.744 69.072 ;
     RECT  57.768 69.036 57.84 69.072 ;
     RECT  57.864 69.036 57.936 69.072 ;
     RECT  57.96 69.036 58.032 69.072 ;
     RECT  58.056 69.036 58.128 69.072 ;
     RECT  58.152 69.036 58.224 69.072 ;
     RECT  58.248 69.036 58.32 69.072 ;
     RECT  58.344 69.036 58.416 69.072 ;
     RECT  58.44 69.036 58.512 69.072 ;
     RECT  58.536 69.036 58.608 69.072 ;
     RECT  58.632 69.036 58.704 69.072 ;
     RECT  58.728 69.036 58.8 69.072 ;
     RECT  58.824 69.036 58.896 69.072 ;
     RECT  58.92 69.036 58.992 69.072 ;
     RECT  59.016 69.036 59.088 69.072 ;
     RECT  59.112 69.036 59.472 69.072 ;
     RECT  59.496 69.036 59.568 69.072 ;
     RECT  59.592 69.036 59.664 69.072 ;
     RECT  59.688 69.036 59.76 69.072 ;
     RECT  59.784 69.036 59.856 69.072 ;
     RECT  59.88 69.036 59.952 69.072 ;
     RECT  59.976 69.036 60.048 69.072 ;
     RECT  60.072 69.036 60.144 69.072 ;
     RECT  60.168 69.036 60.24 69.072 ;
     RECT  60.264 69.036 60.336 69.072 ;
     RECT  60.36 69.036 60.432 69.072 ;
     RECT  60.456 69.036 60.528 69.072 ;
     RECT  60.552 69.036 60.624 69.072 ;
     RECT  60.648 69.036 60.72 69.072 ;
     RECT  60.744 69.036 60.816 69.072 ;
     RECT  60.84 69.036 60.912 69.072 ;
     RECT  60.936 69.036 61.008 69.072 ;
     RECT  61.032 69.036 61.104 69.072 ;
     RECT  61.128 69.036 61.2 69.072 ;
     RECT  61.224 69.036 61.296 69.072 ;
     RECT  61.32 69.036 61.392 69.072 ;
     RECT  61.416 69.036 61.488 69.072 ;
     RECT  61.512 69.036 61.584 69.072 ;
     RECT  61.608 69.036 61.68 69.072 ;
     RECT  61.704 69.036 61.776 69.072 ;
     RECT  61.8 69.036 61.872 69.072 ;
     RECT  61.896 69.036 61.968 69.072 ;
     RECT  61.992 69.036 62.064 69.072 ;
     RECT  62.088 69.036 62.16 69.072 ;
     RECT  13.512 2.581 14.784 6.131 ;
     RECT  43.536 4.019 43.728 4.643 ;
     RECT  8.112 4.261 9.264 10.309 ;
     RECT  43.536 4.643 43.776 5.171 ;
     RECT  27.96 4.837 29.088 4.885 ;
     RECT  27.96 4.885 29.04 7.427 ;
     RECT  43.536 5.171 43.824 5.365 ;
     RECT  42.456 5.365 43.824 7.381 ;
     RECT  30.024 5.461 31.392 9.109 ;
     RECT  46.008 6.323 47.04 8.725 ;
     RECT  47.112 6.371 48.096 8.579 ;
     RECT  26.76 6.421 27.936 8.243 ;
     RECT  18.912 7.139 19.368 7.189 ;
     RECT  18.912 7.189 20.496 8.437 ;
     RECT  42.792 7.381 43.824 10.981 ;
     RECT  27.96 7.427 29.088 8.243 ;
     RECT  35.256 7.765 36.336 8.867 ;
     RECT  47.112 8.579 48.48 9.923 ;
     RECT  35.256 8.867 35.88 9.013 ;
     RECT  35.352 9.013 35.88 9.109 ;
     RECT  11.688 9.061 13.2 9.827 ;
     RECT  30.072 9.109 31.392 9.205 ;
     RECT  19.896 9.155 20.52 10.597 ;
     RECT  53.304 9.155 54.624 10.597 ;
     RECT  30.072 9.205 31.2 9.493 ;
     RECT  12.048 9.827 13.2 10.789 ;
     RECT  47.112 9.923 48.528 10.691 ;
     RECT  35.352 10.067 35.88 10.501 ;
     RECT  15.096 10.165 16.128 10.211 ;
     RECT  49.56 10.259 50.544 11.989 ;
     RECT  35.352 10.501 36.672 11.653 ;
     RECT  19.896 10.597 21.12 11.459 ;
     RECT  47.112 10.691 49.008 10.933 ;
     RECT  12.072 10.789 13.2 10.931 ;
     RECT  8.112 10.883 9.264 13.429 ;
     RECT  47.496 10.933 49.008 11.653 ;
     RECT  27.384 11.365 28.656 12.179 ;
     RECT  2.712 11.413 3.936 11.555 ;
     RECT  20.976 11.459 21 12.949 ;
     RECT  30.264 11.459 31.392 12.517 ;
     RECT  35.352 11.653 36.432 12.755 ;
     RECT  47.496 11.653 48.624 12.469 ;
     RECT  22.8 11.843 22.896 11.939 ;
     RECT  22.8 11.939 23.616 13.045 ;
     RECT  46.44 12.467 47.472 12.563 ;
     RECT  46.248 12.563 47.472 13.525 ;
     RECT  53.064 12.851 54.096 13.909 ;
     RECT  22.776 13.091 24 15.827 ;
     RECT  30.264 13.139 31.392 13.763 ;
     RECT  48.408 13.379 49.536 14.917 ;
     RECT  9.288 13.477 10.56 19.813 ;
     RECT  21 13.573 22.224 14.339 ;
     RECT  30.264 13.763 30.552 14.101 ;
     RECT  6.552 14.147 7.8 17.123 ;
     RECT  8.112 14.435 9.264 23.173 ;
     RECT  27.528 14.581 29.04 14.867 ;
     RECT  36.36 15.157 37.872 16.595 ;
     RECT  66.552 15.731 66.696 17.221 ;
     RECT  22.752 15.827 24 17.029 ;
     RECT  35.112 15.971 36.336 16.835 ;
     RECT  30.12 16.019 30.552 16.213 ;
     RECT  46.824 16.019 47.856 16.211 ;
     RECT  30.12 16.213 31.2 16.259 ;
     RECT  29.928 16.259 31.2 17.507 ;
     RECT  40.68 16.501 42.096 17.077 ;
     RECT  54.168 16.883 55.584 18.709 ;
     RECT  49.8 16.979 50.832 18.565 ;
     RECT  15.624 16.981 16.608 17.075 ;
     RECT  22.728 17.029 24 17.747 ;
     RECT  15.6 17.075 16.608 17.509 ;
     RECT  41.064 17.077 42.096 17.219 ;
     RECT  40.512 17.219 42.096 17.461 ;
     RECT  42.792 17.267 43.824 21.061 ;
     RECT  40.512 17.461 41.712 18.949 ;
     RECT  29.832 17.507 31.2 18.275 ;
     RECT  14.28 17.509 15.696 21.683 ;
     RECT  47.856 17.555 48.144 18.565 ;
     RECT  52.488 17.603 53.616 17.843 ;
     RECT  2.712 17.605 3.84 19.333 ;
     RECT  45.912 18.275 46.008 19.237 ;
     RECT  54.168 18.709 55.152 19.475 ;
     RECT  66.12 18.803 66.552 19.427 ;
     RECT  64.392 18.851 65.472 19.427 ;
     RECT  33.768 18.853 34.8 19.139 ;
     RECT  48.408 18.899 49.776 19.667 ;
     RECT  40.68 18.949 41.712 19.237 ;
     RECT  64.392 19.427 66.552 19.909 ;
     RECT  53.736 19.475 55.152 20.243 ;
     RECT  65.352 19.909 66.528 22.165 ;
     RECT  38.04 19.957 39.36 20.195 ;
     RECT  56.712 20.003 58.032 20.339 ;
     RECT  38.304 20.195 39.36 20.965 ;
     RECT  56.712 20.339 58.368 21.781 ;
     RECT  10.584 20.725 11.664 22.693 ;
     RECT  11.688 20.725 13.2 24.515 ;
     RECT  38.328 20.965 39.36 21.683 ;
     RECT  51.312 21.011 51.432 21.973 ;
     RECT  9.288 21.155 10.56 22.165 ;
     RECT  40.512 21.203 41.712 24.613 ;
     RECT  46.008 21.205 47.328 21.445 ;
     RECT  28.296 21.349 29.4 23.843 ;
     RECT  29.712 21.443 29.832 22.021 ;
     RECT  14.232 21.683 15.696 23.411 ;
     RECT  15.72 21.683 15.912 22.789 ;
     RECT  38.328 21.683 39.648 22.163 ;
     RECT  56.712 21.781 58.128 22.117 ;
     RECT  51.312 21.973 52.416 23.315 ;
     RECT  52.44 21.973 53.712 23.173 ;
     RECT  29.712 22.021 30.768 22.163 ;
     RECT  56.712 22.117 57.936 22.741 ;
     RECT  22.584 22.165 24 23.555 ;
     RECT  65.352 22.739 66.528 24.085 ;
     RECT  32.496 23.315 32.52 23.317 ;
     RECT  32.496 23.317 33.792 23.749 ;
     RECT  33.816 23.317 34.8 24.997 ;
     RECT  55.368 23.317 56.4 23.603 ;
     RECT  15.72 23.555 15.912 24.277 ;
     RECT  32.328 23.749 33.792 24.803 ;
     RECT  42.792 23.795 43.824 25.861 ;
     RECT  65.544 24.085 66.528 24.133 ;
     RECT  15.72 24.277 17.04 25.955 ;
     RECT  53.16 24.563 53.736 25.621 ;
     RECT  32.784 24.803 33.792 24.949 ;
     RECT  51.72 24.901 53.136 26.149 ;
     RECT  32.808 24.949 33.792 26.101 ;
     RECT  40.512 25.043 41.712 26.005 ;
     RECT  22.008 25.525 23.328 25.571 ;
     RECT  53.16 25.621 54.528 26.341 ;
     RECT  9.288 25.715 10.56 25.763 ;
     RECT  9.288 25.763 10.8 26.819 ;
     RECT  17.352 25.813 18.6 33.061 ;
     RECT  40.68 26.005 41.712 26.101 ;
     RECT  39.192 26.053 40.2 29.029 ;
     RECT  51.912 26.149 53.136 27.253 ;
     RECT  53.16 26.341 54.24 27.733 ;
     RECT  43.944 26.387 45.12 26.819 ;
     RECT  9.288 26.819 11.424 26.869 ;
     RECT  43.848 26.819 45.12 27.731 ;
     RECT  9.288 26.869 10.272 28.163 ;
     RECT  10.296 26.869 11.424 28.163 ;
     RECT  35.64 26.869 37.056 27.059 ;
     RECT  37.08 26.869 38.304 27.685 ;
     RECT  48.408 26.915 48.504 28.117 ;
     RECT  35.208 27.059 37.056 28.117 ;
     RECT  55.272 27.301 56.256 28.165 ;
     RECT  42.792 27.587 43.824 29.363 ;
     RECT  51.576 27.683 52.608 29.171 ;
     RECT  37.08 27.685 38.208 29.123 ;
     RECT  43.848 27.731 45.216 27.971 ;
     RECT  35.304 28.117 37.056 28.355 ;
     RECT  9.288 28.163 9.528 28.501 ;
     RECT  48.408 28.259 49.032 28.451 ;
     RECT  55.272 28.307 56.256 28.499 ;
     RECT  35.208 28.355 37.056 28.357 ;
     RECT  35.208 28.357 36.192 28.499 ;
     RECT  50.88 28.403 51 29.653 ;
     RECT  2.856 28.451 3.84 28.643 ;
     RECT  47.64 28.451 49.032 29.509 ;
     RECT  55.272 28.499 56.4 29.555 ;
     RECT  65.4 28.547 66.528 29.219 ;
     RECT  8.112 28.595 9.264 29.699 ;
     RECT  2.712 28.643 3.84 30.371 ;
     RECT  3.864 28.789 4.944 29.029 ;
     RECT  41.304 29.123 42.384 30.613 ;
     RECT  51.576 29.171 52.704 31.139 ;
     RECT  42.408 29.363 43.824 30.899 ;
     RECT  47.64 29.509 48.72 30.035 ;
     RECT  48.744 29.509 49.032 29.605 ;
     RECT  8.112 29.699 9.504 29.795 ;
     RECT  39.192 30.035 40.2 31.861 ;
     RECT  47.352 30.035 48.72 31.955 ;
     RECT  31.608 30.181 32.784 30.851 ;
     RECT  54.648 30.275 54.696 31.379 ;
     RECT  11.448 30.373 12.624 30.515 ;
     RECT  15.96 30.373 17.328 30.851 ;
     RECT  11.424 30.515 12.624 30.709 ;
     RECT  11.424 30.709 12.528 31.237 ;
     RECT  13.512 30.709 15.024 30.757 ;
     RECT  13.512 30.757 14.736 30.899 ;
     RECT  40.512 30.803 41.568 32.099 ;
     RECT  13.512 30.899 15.024 34.355 ;
     RECT  44.232 30.901 45.6 33.299 ;
     RECT  53.304 30.947 54.288 32.149 ;
     RECT  39.12 31.139 39.168 32.485 ;
     RECT  51.576 31.139 52.992 31.189 ;
     RECT  51.672 31.189 52.992 31.427 ;
     RECT  11.304 31.237 12.528 31.427 ;
     RECT  54.408 31.379 54.696 31.669 ;
     RECT  11.304 31.427 12.624 31.955 ;
     RECT  51.672 31.427 53.04 32.387 ;
     RECT  54.408 31.669 55.776 34.117 ;
     RECT  47.256 31.955 48.72 32.243 ;
     RECT  57.432 32.003 58.464 32.099 ;
     RECT  57.432 32.099 58.896 33.301 ;
     RECT  51.672 32.387 53.136 34.645 ;
     RECT  39.192 32.531 40.2 32.723 ;
     RECT  38.712 32.723 40.2 35.939 ;
     RECT  17.496 33.061 18.6 39.877 ;
     RECT  57.624 33.301 58.896 34.355 ;
     RECT  45.912 33.347 47.088 44.341 ;
     RECT  31.608 33.397 33.12 35.987 ;
     RECT  53.16 33.491 54.144 33.683 ;
     RECT  33.144 33.539 34.32 38.675 ;
     RECT  53.16 33.683 54.288 35.123 ;
     RECT  54.696 34.117 55.776 34.259 ;
     RECT  54.696 34.259 56.256 34.741 ;
     RECT  51.912 34.645 53.136 35.123 ;
     RECT  54.888 34.741 56.256 35.459 ;
     RECT  64.584 34.835 64.728 35.701 ;
     RECT  54.888 35.459 56.304 35.509 ;
     RECT  55.32 35.509 56.304 36.565 ;
     RECT  64.584 35.701 65.76 35.845 ;
     RECT  59.112 35.987 60.432 36.515 ;
     RECT  59.064 36.515 60.432 37.669 ;
     RECT  63.72 36.803 65.376 36.851 ;
     RECT  63.72 36.851 65.76 37.331 ;
     RECT  56.808 36.853 57.84 37.139 ;
     RECT  57.864 36.853 58.896 38.629 ;
     RECT  56.712 37.139 57.84 39.781 ;
     RECT  63.72 37.331 64.392 38.197 ;
     RECT  25.032 38.149 26.064 39.251 ;
     RECT  59.256 38.195 60.432 38.819 ;
     RECT  63.144 38.387 64.368 38.915 ;
     RECT  62.112 38.483 63.12 39.011 ;
     RECT  44.328 38.725 45.6 39.589 ;
     RECT  59.256 38.819 60.48 41.075 ;
     RECT  13.512 39.445 14.784 42.229 ;
     RECT  44.328 39.589 45.312 40.019 ;
     RECT  47.448 39.589 48.816 42.227 ;
     RECT  7.68 39.731 7.8 40.837 ;
     RECT  56.712 39.781 57.792 40.883 ;
     RECT  44.328 40.019 45.6 40.259 ;
     RECT  58.104 40.019 59.232 40.835 ;
     RECT  38.808 40.405 40.2 41.075 ;
     RECT  28.464 40.547 29.4 41.509 ;
     RECT  54.936 40.643 55.92 40.883 ;
     RECT  17.496 40.691 18.48 42.133 ;
     RECT  57.864 40.835 59.232 41.075 ;
     RECT  6.552 40.837 7.8 41.603 ;
     RECT  54.936 40.883 56.4 41.075 ;
     RECT  56.712 40.883 57.84 42.227 ;
     RECT  57.864 41.075 58.056 42.181 ;
     RECT  27.96 41.509 29.4 42.179 ;
     RECT  26.064 42.035 26.208 42.997 ;
     RECT  10.632 42.085 11.664 43.093 ;
     RECT  11.688 42.085 13.104 43.379 ;
     RECT  56.712 42.227 58.032 45.877 ;
     RECT  13.608 42.229 14.784 42.803 ;
     RECT  13.512 42.803 14.784 43.139 ;
     RECT  17.496 42.803 18.48 46.211 ;
     RECT  24.312 42.997 25.776 47.653 ;
     RECT  44.472 43.093 45.6 45.877 ;
     RECT  13.512 43.139 13.656 44.437 ;
     RECT  11.688 43.379 13.2 43.811 ;
     RECT  30.552 44.051 31.32 44.483 ;
     RECT  37.128 44.149 38.592 44.195 ;
     RECT  2.712 44.437 3.984 45.683 ;
     RECT  29.712 44.483 31.32 45.157 ;
     RECT  50.88 44.483 51 45.541 ;
     RECT  33.048 44.773 34.32 46.981 ;
     RECT  29.712 45.157 31.2 45.443 ;
     RECT  27.768 45.301 29.28 45.973 ;
     RECT  29.712 45.443 30.792 45.685 ;
     RECT  49.848 45.541 51 47.027 ;
     RECT  2.712 45.683 4.08 46.787 ;
     RECT  29.712 45.685 30.768 46.211 ;
     RECT  44.52 45.877 45.6 46.787 ;
     RECT  27.768 45.973 29.232 46.115 ;
     RECT  10.608 46.019 10.8 47.029 ;
     RECT  17.496 46.211 18.6 46.787 ;
     RECT  35.112 46.211 35.352 47.221 ;
     RECT  13.512 46.259 13.656 46.357 ;
     RECT  11.112 46.261 12.528 46.883 ;
     RECT  13.512 46.357 15.024 48.899 ;
     RECT  2.712 46.787 2.856 47.701 ;
     RECT  17.616 46.787 18.6 47.653 ;
     RECT  10.824 46.883 12.528 47.845 ;
     RECT  56.304 47.315 56.4 48.469 ;
     RECT  60.432 47.315 60.48 47.845 ;
     RECT  17.616 47.653 18.432 47.893 ;
     RECT  24.312 47.653 25.392 53.029 ;
     RECT  64.104 47.747 64.728 47.845 ;
     RECT  11.4 47.845 12.528 48.131 ;
     RECT  51.912 47.845 53.184 49.043 ;
     RECT  59.304 47.845 60.48 50.101 ;
     RECT  64.104 47.845 65.28 48.131 ;
     RECT  7.056 48.707 7.104 49.861 ;
     RECT  13.512 48.899 13.608 49.477 ;
     RECT  58.056 49.333 59.28 50.053 ;
     RECT  56.808 49.619 58.032 50.147 ;
     RECT  59.304 50.101 60.336 50.531 ;
     RECT  8.112 50.147 8.232 51.157 ;
     RECT  13.512 50.195 13.608 51.253 ;
     RECT  43.656 50.195 43.896 50.965 ;
     RECT  43.656 50.965 44.736 51.875 ;
     RECT  8.112 51.157 9.12 51.347 ;
     RECT  9.144 51.157 10.512 51.301 ;
     RECT  9.288 51.301 10.512 58.739 ;
     RECT  8.112 51.347 9.264 52.933 ;
     RECT  18.912 51.347 19.368 52.549 ;
     RECT  40.512 51.397 41.664 55.379 ;
     RECT  34.32 51.443 34.8 52.405 ;
     RECT  57.096 51.829 58.368 52.789 ;
     RECT  43.656 51.875 43.944 52.021 ;
     RECT  14.232 52.165 15.36 52.261 ;
     RECT  14.232 52.261 15.312 52.405 ;
     RECT  58.392 52.261 59.808 52.405 ;
     RECT  14.232 52.405 15.264 53.267 ;
     RECT  15.336 52.451 15.384 52.741 ;
     RECT  18.912 52.549 20.112 53.941 ;
     RECT  20.136 52.549 21.168 52.739 ;
     RECT  20.136 52.739 21.552 52.979 ;
     RECT  15.336 52.741 16.8 53.075 ;
     RECT  16.824 52.741 18.24 53.075 ;
     RECT  57.288 52.789 58.368 52.981 ;
     RECT  35.352 52.981 36.432 53.267 ;
     RECT  17.088 53.075 18.24 53.077 ;
     RECT  43.896 53.075 43.944 53.749 ;
     RECT  17.112 53.077 18.24 54.275 ;
     RECT  28.248 53.269 29.4 55.331 ;
     RECT  49.128 53.557 50.16 53.987 ;
     RECT  43.896 53.749 44.88 55.859 ;
     RECT  24.312 53.795 25.392 54.179 ;
     RECT  2.712 53.941 4.032 54.851 ;
     RECT  51.912 54.085 52.896 54.709 ;
     RECT  18.912 54.131 19.92 54.755 ;
     RECT  24.312 54.179 25.92 55.331 ;
     RECT  52.92 54.661 54.096 54.755 ;
     RECT  18.912 54.755 20.112 58.115 ;
     RECT  52.632 54.755 54.096 55.427 ;
     RECT  54.12 55.237 55.632 55.955 ;
     RECT  18.24 55.331 18.384 55.813 ;
     RECT  24.312 55.331 24.552 55.381 ;
     RECT  28.272 55.331 29.4 55.525 ;
     RECT  24.504 55.381 24.552 56.245 ;
     RECT  51.912 55.427 54.096 56.389 ;
     RECT  28.296 55.525 29.4 58.115 ;
     RECT  17.016 55.813 18.384 56.483 ;
     RECT  64.2 55.813 65.328 56.389 ;
     RECT  23.424 55.907 24 56.917 ;
     RECT  54.12 55.955 55.68 56.435 ;
     RECT  51.912 56.389 52.944 57.059 ;
     RECT  52.968 56.389 54.096 56.435 ;
     RECT  55.152 56.435 55.68 56.917 ;
     RECT  8.112 56.723 9.264 58.931 ;
     RECT  22.632 56.917 24 60.757 ;
     RECT  51.672 57.059 52.944 57.827 ;
     RECT  2.712 57.445 3.696 58.163 ;
     RECT  5.28 57.491 5.328 58.645 ;
     RECT  18.912 58.115 19.176 58.357 ;
     RECT  10.536 58.117 12 58.501 ;
     RECT  12.024 58.117 13.2 58.787 ;
     RECT  9.288 58.739 11.04 58.885 ;
     RECT  9.672 58.885 11.04 60.419 ;
     RECT  52.968 58.933 54.24 59.315 ;
     RECT  58.056 59.027 59.184 61.091 ;
     RECT  52.944 59.315 54.24 59.797 ;
     RECT  52.944 59.797 52.992 60.275 ;
     RECT  59.64 59.891 60.624 59.987 ;
     RECT  59.64 59.987 60.672 60.611 ;
     RECT  52.944 60.275 53.184 60.565 ;
     RECT  64.2 60.371 65.232 60.851 ;
     RECT  38.808 60.467 40.2 62.723 ;
     RECT  24.312 60.517 25.728 61.379 ;
     RECT  51.672 60.565 53.184 60.995 ;
     RECT  59.64 60.611 60.816 61.765 ;
     RECT  22.776 60.757 24 61.667 ;
     RECT  51.528 60.995 53.184 61.813 ;
     RECT  5.4 61.189 6.816 62.339 ;
     RECT  14.232 61.379 14.28 62.341 ;
     RECT  24.312 61.379 24.408 62.437 ;
     RECT  45.504 61.379 45.6 62.677 ;
     RECT  34.416 61.619 34.8 62.629 ;
     RECT  22.488 61.667 24 63.251 ;
     RECT  51.528 61.813 52.992 62.051 ;
     RECT  53.208 61.955 54.576 62.147 ;
     RECT  51.48 62.051 52.992 63.349 ;
     RECT  41.496 62.243 41.544 63.589 ;
     RECT  14.232 62.341 15.744 63.299 ;
     RECT  57.864 62.629 59.184 62.675 ;
     RECT  57.864 62.675 59.232 63.733 ;
     RECT  44.52 63.061 45.504 63.635 ;
     RECT  62.232 63.205 63.216 63.685 ;
     RECT  14.232 63.299 15.192 63.781 ;
     RECT  33.528 63.299 34.8 63.923 ;
     RECT  51.312 63.443 52.368 64.549 ;
     RECT  44.52 63.635 45.6 66.131 ;
     RECT  30.84 63.683 30.984 64.595 ;
     RECT  58.152 63.733 59.232 63.781 ;
     RECT  52.488 63.827 52.92 64.837 ;
     RECT  29.712 64.451 30.816 64.595 ;
     RECT  29.712 64.595 30.984 64.837 ;
     RECT  29.712 64.837 30.96 66.275 ;
     RECT  55.176 65.027 56.256 66.179 ;
     RECT  56.112 66.179 56.256 67.237 ;
     RECT  62.232 66.275 63.216 66.467 ;
  END
END ot_hgi_dma_back_static_vp4_controller
END LIBRARY
